VERSION 5.8 ;
BUSBITCHARS "[]" ;
DIVIDERCHAR "/" ;
UNITS
    DATABASE MICRONS 1000 ;
END UNITS

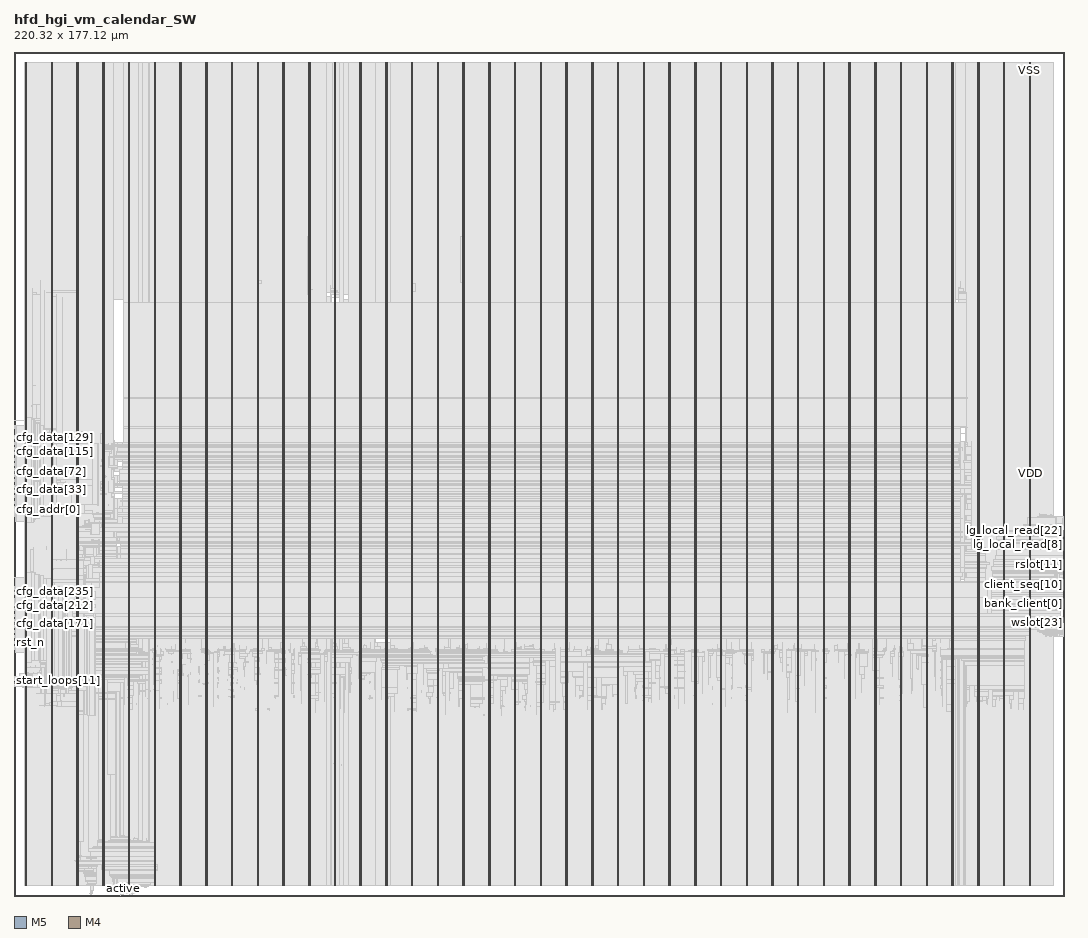
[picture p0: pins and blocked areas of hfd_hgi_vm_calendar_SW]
MACRO hfd_hgi_vm_calendar_SW
  FOREIGN hfd_hgi_vm_calendar_SW 0 0 ;
  CLASS BLOCK ;
  SIZE 220.32 BY 177.12 ;
  PIN active
    DIRECTION OUTPUT ;
    USE SIGNAL ;
    PORT
      LAYER M5 ;
        RECT  22.992 0 23.016 0.084 ;
    END
  END active
  PIN bank_client[0]
    DIRECTION OUTPUT ;
    USE SIGNAL ;
    PORT
      LAYER M4 ;
        RECT  220.236 61.392 220.32 61.416 ;
    END
  END bank_client[0]
  PIN bank_client[10]
    DIRECTION OUTPUT ;
    USE SIGNAL ;
    PORT
      LAYER M4 ;
        RECT  220.236 62.352 220.32 62.376 ;
    END
  END bank_client[10]
  PIN bank_client[11]
    DIRECTION OUTPUT ;
    USE SIGNAL ;
    PORT
      LAYER M4 ;
        RECT  220.236 62.448 220.32 62.472 ;
    END
  END bank_client[11]
  PIN bank_client[12]
    DIRECTION OUTPUT ;
    USE SIGNAL ;
    PORT
      LAYER M4 ;
        RECT  220.236 62.544 220.32 62.568 ;
    END
  END bank_client[12]
  PIN bank_client[13]
    DIRECTION OUTPUT ;
    USE SIGNAL ;
    PORT
      LAYER M4 ;
        RECT  220.236 62.64 220.32 62.664 ;
    END
  END bank_client[13]
  PIN bank_client[14]
    DIRECTION OUTPUT ;
    USE SIGNAL ;
    PORT
      LAYER M4 ;
        RECT  220.236 62.736 220.32 62.76 ;
    END
  END bank_client[14]
  PIN bank_client[15]
    DIRECTION OUTPUT ;
    USE SIGNAL ;
    PORT
      LAYER M4 ;
        RECT  220.236 62.832 220.32 62.856 ;
    END
  END bank_client[15]
  PIN bank_client[16]
    DIRECTION OUTPUT ;
    USE SIGNAL ;
    PORT
      LAYER M4 ;
        RECT  220.236 62.928 220.32 62.952 ;
    END
  END bank_client[16]
  PIN bank_client[17]
    DIRECTION OUTPUT ;
    USE SIGNAL ;
    PORT
      LAYER M4 ;
        RECT  220.236 63.024 220.32 63.048 ;
    END
  END bank_client[17]
  PIN bank_client[18]
    DIRECTION OUTPUT ;
    USE SIGNAL ;
    PORT
      LAYER M4 ;
        RECT  220.236 63.12 220.32 63.144 ;
    END
  END bank_client[18]
  PIN bank_client[19]
    DIRECTION OUTPUT ;
    USE SIGNAL ;
    PORT
      LAYER M4 ;
        RECT  220.236 63.216 220.32 63.24 ;
    END
  END bank_client[19]
  PIN bank_client[1]
    DIRECTION OUTPUT ;
    USE SIGNAL ;
    PORT
      LAYER M4 ;
        RECT  220.236 61.488 220.32 61.512 ;
    END
  END bank_client[1]
  PIN bank_client[20]
    DIRECTION OUTPUT ;
    USE SIGNAL ;
    PORT
      LAYER M4 ;
        RECT  220.236 63.312 220.32 63.336 ;
    END
  END bank_client[20]
  PIN bank_client[21]
    DIRECTION OUTPUT ;
    USE SIGNAL ;
    PORT
      LAYER M4 ;
        RECT  220.236 63.408 220.32 63.432 ;
    END
  END bank_client[21]
  PIN bank_client[22]
    DIRECTION OUTPUT ;
    USE SIGNAL ;
    PORT
      LAYER M4 ;
        RECT  220.236 63.504 220.32 63.528 ;
    END
  END bank_client[22]
  PIN bank_client[23]
    DIRECTION OUTPUT ;
    USE SIGNAL ;
    PORT
      LAYER M4 ;
        RECT  220.236 63.6 220.32 63.624 ;
    END
  END bank_client[23]
  PIN bank_client[2]
    DIRECTION OUTPUT ;
    USE SIGNAL ;
    PORT
      LAYER M4 ;
        RECT  220.236 61.584 220.32 61.608 ;
    END
  END bank_client[2]
  PIN bank_client[3]
    DIRECTION OUTPUT ;
    USE SIGNAL ;
    PORT
      LAYER M4 ;
        RECT  220.236 61.68 220.32 61.704 ;
    END
  END bank_client[3]
  PIN bank_client[4]
    DIRECTION OUTPUT ;
    USE SIGNAL ;
    PORT
      LAYER M4 ;
        RECT  220.236 61.776 220.32 61.8 ;
    END
  END bank_client[4]
  PIN bank_client[5]
    DIRECTION OUTPUT ;
    USE SIGNAL ;
    PORT
      LAYER M4 ;
        RECT  220.236 61.872 220.32 61.896 ;
    END
  END bank_client[5]
  PIN bank_client[6]
    DIRECTION OUTPUT ;
    USE SIGNAL ;
    PORT
      LAYER M4 ;
        RECT  220.236 61.968 220.32 61.992 ;
    END
  END bank_client[6]
  PIN bank_client[7]
    DIRECTION OUTPUT ;
    USE SIGNAL ;
    PORT
      LAYER M4 ;
        RECT  220.236 62.064 220.32 62.088 ;
    END
  END bank_client[7]
  PIN bank_client[8]
    DIRECTION OUTPUT ;
    USE SIGNAL ;
    PORT
      LAYER M4 ;
        RECT  220.236 62.16 220.32 62.184 ;
    END
  END bank_client[8]
  PIN bank_client[9]
    DIRECTION OUTPUT ;
    USE SIGNAL ;
    PORT
      LAYER M4 ;
        RECT  220.236 62.256 220.32 62.28 ;
    END
  END bank_client[9]
  PIN bank_enable[0]
    DIRECTION OUTPUT ;
    USE SIGNAL ;
    PORT
      LAYER M4 ;
        RECT  220.236 63.696 220.32 63.72 ;
    END
  END bank_enable[0]
  PIN bank_enable[1]
    DIRECTION OUTPUT ;
    USE SIGNAL ;
    PORT
      LAYER M4 ;
        RECT  220.236 63.792 220.32 63.816 ;
    END
  END bank_enable[1]
  PIN bank_enable[2]
    DIRECTION OUTPUT ;
    USE SIGNAL ;
    PORT
      LAYER M4 ;
        RECT  220.236 63.888 220.32 63.912 ;
    END
  END bank_enable[2]
  PIN bank_enable[3]
    DIRECTION OUTPUT ;
    USE SIGNAL ;
    PORT
      LAYER M4 ;
        RECT  220.236 63.984 220.32 64.008 ;
    END
  END bank_enable[3]
  PIN bank_enable[4]
    DIRECTION OUTPUT ;
    USE SIGNAL ;
    PORT
      LAYER M4 ;
        RECT  220.236 64.08 220.32 64.104 ;
    END
  END bank_enable[4]
  PIN bank_enable[5]
    DIRECTION OUTPUT ;
    USE SIGNAL ;
    PORT
      LAYER M4 ;
        RECT  220.236 64.176 220.32 64.2 ;
    END
  END bank_enable[5]
  PIN bank_enable[6]
    DIRECTION OUTPUT ;
    USE SIGNAL ;
    PORT
      LAYER M4 ;
        RECT  220.236 64.272 220.32 64.296 ;
    END
  END bank_enable[6]
  PIN bank_enable[7]
    DIRECTION OUTPUT ;
    USE SIGNAL ;
    PORT
      LAYER M4 ;
        RECT  220.236 64.368 220.32 64.392 ;
    END
  END bank_enable[7]
  PIN calendar_v
    DIRECTION OUTPUT ;
    USE SIGNAL ;
    PORT
      LAYER M5 ;
        RECT  23.088 0 23.112 0.084 ;
    END
  END calendar_v
  PIN cfg_addr[0]
    DIRECTION INPUT ;
    USE SIGNAL ;
    PORT
      LAYER M4 ;
        RECT  0 81.168 0.084 81.192 ;
    END
  END cfg_addr[0]
  PIN cfg_addr[1]
    DIRECTION INPUT ;
    USE SIGNAL ;
    PORT
      LAYER M4 ;
        RECT  0 81.264 0.084 81.288 ;
    END
  END cfg_addr[1]
  PIN cfg_addr[2]
    DIRECTION INPUT ;
    USE SIGNAL ;
    PORT
      LAYER M4 ;
        RECT  0 81.36 0.084 81.384 ;
    END
  END cfg_addr[2]
  PIN cfg_addr[3]
    DIRECTION INPUT ;
    USE SIGNAL ;
    PORT
      LAYER M4 ;
        RECT  0 81.456 0.084 81.48 ;
    END
  END cfg_addr[3]
  PIN cfg_addr[4]
    DIRECTION INPUT ;
    USE SIGNAL ;
    PORT
      LAYER M4 ;
        RECT  0 81.552 0.084 81.576 ;
    END
  END cfg_addr[4]
  PIN cfg_addr[5]
    DIRECTION INPUT ;
    USE SIGNAL ;
    PORT
      LAYER M4 ;
        RECT  0 81.648 0.084 81.672 ;
    END
  END cfg_addr[5]
  PIN cfg_addr[6]
    DIRECTION INPUT ;
    USE SIGNAL ;
    PORT
      LAYER M4 ;
        RECT  0 81.744 0.084 81.768 ;
    END
  END cfg_addr[6]
  PIN cfg_addr[7]
    DIRECTION INPUT ;
    USE SIGNAL ;
    PORT
      LAYER M4 ;
        RECT  0 81.84 0.084 81.864 ;
    END
  END cfg_addr[7]
  PIN cfg_addr[8]
    DIRECTION INPUT ;
    USE SIGNAL ;
    PORT
      LAYER M4 ;
        RECT  0 81.936 0.084 81.96 ;
    END
  END cfg_addr[8]
  PIN cfg_addr[9]
    DIRECTION INPUT ;
    USE SIGNAL ;
    PORT
      LAYER M4 ;
        RECT  0 82.032 0.084 82.056 ;
    END
  END cfg_addr[9]
  PIN cfg_data[0]
    DIRECTION INPUT ;
    USE SIGNAL ;
    PORT
      LAYER M4 ;
        RECT  0 82.128 0.084 82.152 ;
    END
  END cfg_data[0]
  PIN cfg_data[100]
    DIRECTION INPUT ;
    USE SIGNAL ;
    PORT
      LAYER M4 ;
        RECT  0 91.728 0.084 91.752 ;
    END
  END cfg_data[100]
  PIN cfg_data[101]
    DIRECTION INPUT ;
    USE SIGNAL ;
    PORT
      LAYER M4 ;
        RECT  0 91.824 0.084 91.848 ;
    END
  END cfg_data[101]
  PIN cfg_data[102]
    DIRECTION INPUT ;
    USE SIGNAL ;
    PORT
      LAYER M4 ;
        RECT  0 91.92 0.084 91.944 ;
    END
  END cfg_data[102]
  PIN cfg_data[103]
    DIRECTION INPUT ;
    USE SIGNAL ;
    PORT
      LAYER M4 ;
        RECT  0 92.016 0.084 92.04 ;
    END
  END cfg_data[103]
  PIN cfg_data[104]
    DIRECTION INPUT ;
    USE SIGNAL ;
    PORT
      LAYER M4 ;
        RECT  0 92.112 0.084 92.136 ;
    END
  END cfg_data[104]
  PIN cfg_data[105]
    DIRECTION INPUT ;
    USE SIGNAL ;
    PORT
      LAYER M4 ;
        RECT  0 92.208 0.084 92.232 ;
    END
  END cfg_data[105]
  PIN cfg_data[106]
    DIRECTION INPUT ;
    USE SIGNAL ;
    PORT
      LAYER M4 ;
        RECT  0 92.304 0.084 92.328 ;
    END
  END cfg_data[106]
  PIN cfg_data[107]
    DIRECTION INPUT ;
    USE SIGNAL ;
    PORT
      LAYER M4 ;
        RECT  0 92.4 0.084 92.424 ;
    END
  END cfg_data[107]
  PIN cfg_data[108]
    DIRECTION INPUT ;
    USE SIGNAL ;
    PORT
      LAYER M4 ;
        RECT  0 92.496 0.084 92.52 ;
    END
  END cfg_data[108]
  PIN cfg_data[109]
    DIRECTION INPUT ;
    USE SIGNAL ;
    PORT
      LAYER M4 ;
        RECT  0 92.592 0.084 92.616 ;
    END
  END cfg_data[109]
  PIN cfg_data[10]
    DIRECTION INPUT ;
    USE SIGNAL ;
    PORT
      LAYER M4 ;
        RECT  0 83.088 0.084 83.112 ;
    END
  END cfg_data[10]
  PIN cfg_data[110]
    DIRECTION INPUT ;
    USE SIGNAL ;
    PORT
      LAYER M4 ;
        RECT  0 92.688 0.084 92.712 ;
    END
  END cfg_data[110]
  PIN cfg_data[111]
    DIRECTION INPUT ;
    USE SIGNAL ;
    PORT
      LAYER M4 ;
        RECT  0 92.784 0.084 92.808 ;
    END
  END cfg_data[111]
  PIN cfg_data[112]
    DIRECTION INPUT ;
    USE SIGNAL ;
    PORT
      LAYER M4 ;
        RECT  0 92.88 0.084 92.904 ;
    END
  END cfg_data[112]
  PIN cfg_data[113]
    DIRECTION INPUT ;
    USE SIGNAL ;
    PORT
      LAYER M4 ;
        RECT  0 92.976 0.084 93 ;
    END
  END cfg_data[113]
  PIN cfg_data[114]
    DIRECTION INPUT ;
    USE SIGNAL ;
    PORT
      LAYER M4 ;
        RECT  0 93.072 0.084 93.096 ;
    END
  END cfg_data[114]
  PIN cfg_data[115]
    DIRECTION INPUT ;
    USE SIGNAL ;
    PORT
      LAYER M4 ;
        RECT  0 93.168 0.084 93.192 ;
    END
  END cfg_data[115]
  PIN cfg_data[116]
    DIRECTION INPUT ;
    USE SIGNAL ;
    PORT
      LAYER M4 ;
        RECT  0 93.264 0.084 93.288 ;
    END
  END cfg_data[116]
  PIN cfg_data[117]
    DIRECTION INPUT ;
    USE SIGNAL ;
    PORT
      LAYER M4 ;
        RECT  0 93.36 0.084 93.384 ;
    END
  END cfg_data[117]
  PIN cfg_data[118]
    DIRECTION INPUT ;
    USE SIGNAL ;
    PORT
      LAYER M4 ;
        RECT  0 93.456 0.084 93.48 ;
    END
  END cfg_data[118]
  PIN cfg_data[119]
    DIRECTION INPUT ;
    USE SIGNAL ;
    PORT
      LAYER M4 ;
        RECT  0 93.552 0.084 93.576 ;
    END
  END cfg_data[119]
  PIN cfg_data[11]
    DIRECTION INPUT ;
    USE SIGNAL ;
    PORT
      LAYER M4 ;
        RECT  0 83.184 0.084 83.208 ;
    END
  END cfg_data[11]
  PIN cfg_data[120]
    DIRECTION INPUT ;
    USE SIGNAL ;
    PORT
      LAYER M4 ;
        RECT  0 93.648 0.084 93.672 ;
    END
  END cfg_data[120]
  PIN cfg_data[121]
    DIRECTION INPUT ;
    USE SIGNAL ;
    PORT
      LAYER M4 ;
        RECT  0 93.744 0.084 93.768 ;
    END
  END cfg_data[121]
  PIN cfg_data[122]
    DIRECTION INPUT ;
    USE SIGNAL ;
    PORT
      LAYER M4 ;
        RECT  0 93.84 0.084 93.864 ;
    END
  END cfg_data[122]
  PIN cfg_data[123]
    DIRECTION INPUT ;
    USE SIGNAL ;
    PORT
      LAYER M4 ;
        RECT  0 93.936 0.084 93.96 ;
    END
  END cfg_data[123]
  PIN cfg_data[124]
    DIRECTION INPUT ;
    USE SIGNAL ;
    PORT
      LAYER M4 ;
        RECT  0 94.032 0.084 94.056 ;
    END
  END cfg_data[124]
  PIN cfg_data[125]
    DIRECTION INPUT ;
    USE SIGNAL ;
    PORT
      LAYER M4 ;
        RECT  0 94.128 0.084 94.152 ;
    END
  END cfg_data[125]
  PIN cfg_data[126]
    DIRECTION INPUT ;
    USE SIGNAL ;
    PORT
      LAYER M4 ;
        RECT  0 94.224 0.084 94.248 ;
    END
  END cfg_data[126]
  PIN cfg_data[127]
    DIRECTION INPUT ;
    USE SIGNAL ;
    PORT
      LAYER M4 ;
        RECT  0 94.32 0.084 94.344 ;
    END
  END cfg_data[127]
  PIN cfg_data[128]
    DIRECTION INPUT ;
    USE SIGNAL ;
    PORT
      LAYER M4 ;
        RECT  0 94.416 0.084 94.44 ;
    END
  END cfg_data[128]
  PIN cfg_data[129]
    DIRECTION INPUT ;
    USE SIGNAL ;
    PORT
      LAYER M4 ;
        RECT  0 94.512 0.084 94.536 ;
    END
  END cfg_data[129]
  PIN cfg_data[12]
    DIRECTION INPUT ;
    USE SIGNAL ;
    PORT
      LAYER M4 ;
        RECT  0 83.28 0.084 83.304 ;
    END
  END cfg_data[12]
  PIN cfg_data[130]
    DIRECTION INPUT ;
    USE SIGNAL ;
    PORT
      LAYER M4 ;
        RECT  0 94.608 0.084 94.632 ;
    END
  END cfg_data[130]
  PIN cfg_data[131]
    DIRECTION INPUT ;
    USE SIGNAL ;
    PORT
      LAYER M4 ;
        RECT  0 94.704 0.084 94.728 ;
    END
  END cfg_data[131]
  PIN cfg_data[132]
    DIRECTION INPUT ;
    USE SIGNAL ;
    PORT
      LAYER M4 ;
        RECT  0 94.8 0.084 94.824 ;
    END
  END cfg_data[132]
  PIN cfg_data[133]
    DIRECTION INPUT ;
    USE SIGNAL ;
    PORT
      LAYER M4 ;
        RECT  0 94.896 0.084 94.92 ;
    END
  END cfg_data[133]
  PIN cfg_data[134]
    DIRECTION INPUT ;
    USE SIGNAL ;
    PORT
      LAYER M4 ;
        RECT  0 94.992 0.084 95.016 ;
    END
  END cfg_data[134]
  PIN cfg_data[135]
    DIRECTION INPUT ;
    USE SIGNAL ;
    PORT
      LAYER M4 ;
        RECT  0 95.088 0.084 95.112 ;
    END
  END cfg_data[135]
  PIN cfg_data[136]
    DIRECTION INPUT ;
    USE SIGNAL ;
    PORT
      LAYER M4 ;
        RECT  0 95.184 0.084 95.208 ;
    END
  END cfg_data[136]
  PIN cfg_data[137]
    DIRECTION INPUT ;
    USE SIGNAL ;
    PORT
      LAYER M4 ;
        RECT  0 95.28 0.084 95.304 ;
    END
  END cfg_data[137]
  PIN cfg_data[138]
    DIRECTION INPUT ;
    USE SIGNAL ;
    PORT
      LAYER M4 ;
        RECT  0 95.376 0.084 95.4 ;
    END
  END cfg_data[138]
  PIN cfg_data[139]
    DIRECTION INPUT ;
    USE SIGNAL ;
    PORT
      LAYER M4 ;
        RECT  0 95.472 0.084 95.496 ;
    END
  END cfg_data[139]
  PIN cfg_data[13]
    DIRECTION INPUT ;
    USE SIGNAL ;
    PORT
      LAYER M4 ;
        RECT  0 83.376 0.084 83.4 ;
    END
  END cfg_data[13]
  PIN cfg_data[140]
    DIRECTION INPUT ;
    USE SIGNAL ;
    PORT
      LAYER M4 ;
        RECT  0 95.568 0.084 95.592 ;
    END
  END cfg_data[140]
  PIN cfg_data[141]
    DIRECTION INPUT ;
    USE SIGNAL ;
    PORT
      LAYER M4 ;
        RECT  0 95.664 0.084 95.688 ;
    END
  END cfg_data[141]
  PIN cfg_data[142]
    DIRECTION INPUT ;
    USE SIGNAL ;
    PORT
      LAYER M4 ;
        RECT  0 95.76 0.084 95.784 ;
    END
  END cfg_data[142]
  PIN cfg_data[143]
    DIRECTION INPUT ;
    USE SIGNAL ;
    PORT
      LAYER M4 ;
        RECT  0 95.856 0.084 95.88 ;
    END
  END cfg_data[143]
  PIN cfg_data[144]
    DIRECTION INPUT ;
    USE SIGNAL ;
    PORT
      LAYER M4 ;
        RECT  0 95.952 0.084 95.976 ;
    END
  END cfg_data[144]
  PIN cfg_data[145]
    DIRECTION INPUT ;
    USE SIGNAL ;
    PORT
      LAYER M4 ;
        RECT  0 96.048 0.084 96.072 ;
    END
  END cfg_data[145]
  PIN cfg_data[146]
    DIRECTION INPUT ;
    USE SIGNAL ;
    PORT
      LAYER M4 ;
        RECT  0 96.144 0.084 96.168 ;
    END
  END cfg_data[146]
  PIN cfg_data[147]
    DIRECTION INPUT ;
    USE SIGNAL ;
    PORT
      LAYER M4 ;
        RECT  0 96.24 0.084 96.264 ;
    END
  END cfg_data[147]
  PIN cfg_data[148]
    DIRECTION INPUT ;
    USE SIGNAL ;
    PORT
      LAYER M4 ;
        RECT  0 96.336 0.084 96.36 ;
    END
  END cfg_data[148]
  PIN cfg_data[149]
    DIRECTION INPUT ;
    USE SIGNAL ;
    PORT
      LAYER M4 ;
        RECT  0 96.432 0.084 96.456 ;
    END
  END cfg_data[149]
  PIN cfg_data[14]
    DIRECTION INPUT ;
    USE SIGNAL ;
    PORT
      LAYER M4 ;
        RECT  0 83.472 0.084 83.496 ;
    END
  END cfg_data[14]
  PIN cfg_data[150]
    DIRECTION INPUT ;
    USE SIGNAL ;
    PORT
      LAYER M4 ;
        RECT  0 55.056 0.084 55.08 ;
    END
  END cfg_data[150]
  PIN cfg_data[151]
    DIRECTION INPUT ;
    USE SIGNAL ;
    PORT
      LAYER M4 ;
        RECT  0 55.152 0.084 55.176 ;
    END
  END cfg_data[151]
  PIN cfg_data[152]
    DIRECTION INPUT ;
    USE SIGNAL ;
    PORT
      LAYER M4 ;
        RECT  0 55.248 0.084 55.272 ;
    END
  END cfg_data[152]
  PIN cfg_data[153]
    DIRECTION INPUT ;
    USE SIGNAL ;
    PORT
      LAYER M4 ;
        RECT  0 55.344 0.084 55.368 ;
    END
  END cfg_data[153]
  PIN cfg_data[154]
    DIRECTION INPUT ;
    USE SIGNAL ;
    PORT
      LAYER M4 ;
        RECT  0 55.44 0.084 55.464 ;
    END
  END cfg_data[154]
  PIN cfg_data[155]
    DIRECTION INPUT ;
    USE SIGNAL ;
    PORT
      LAYER M4 ;
        RECT  0 55.536 0.084 55.56 ;
    END
  END cfg_data[155]
  PIN cfg_data[156]
    DIRECTION INPUT ;
    USE SIGNAL ;
    PORT
      LAYER M4 ;
        RECT  0 55.632 0.084 55.656 ;
    END
  END cfg_data[156]
  PIN cfg_data[157]
    DIRECTION INPUT ;
    USE SIGNAL ;
    PORT
      LAYER M4 ;
        RECT  0 55.728 0.084 55.752 ;
    END
  END cfg_data[157]
  PIN cfg_data[158]
    DIRECTION INPUT ;
    USE SIGNAL ;
    PORT
      LAYER M4 ;
        RECT  0 55.824 0.084 55.848 ;
    END
  END cfg_data[158]
  PIN cfg_data[159]
    DIRECTION INPUT ;
    USE SIGNAL ;
    PORT
      LAYER M4 ;
        RECT  0 55.92 0.084 55.944 ;
    END
  END cfg_data[159]
  PIN cfg_data[15]
    DIRECTION INPUT ;
    USE SIGNAL ;
    PORT
      LAYER M4 ;
        RECT  0 83.568 0.084 83.592 ;
    END
  END cfg_data[15]
  PIN cfg_data[160]
    DIRECTION INPUT ;
    USE SIGNAL ;
    PORT
      LAYER M4 ;
        RECT  0 56.016 0.084 56.04 ;
    END
  END cfg_data[160]
  PIN cfg_data[161]
    DIRECTION INPUT ;
    USE SIGNAL ;
    PORT
      LAYER M4 ;
        RECT  0 56.112 0.084 56.136 ;
    END
  END cfg_data[161]
  PIN cfg_data[162]
    DIRECTION INPUT ;
    USE SIGNAL ;
    PORT
      LAYER M4 ;
        RECT  0 56.208 0.084 56.232 ;
    END
  END cfg_data[162]
  PIN cfg_data[163]
    DIRECTION INPUT ;
    USE SIGNAL ;
    PORT
      LAYER M4 ;
        RECT  0 56.304 0.084 56.328 ;
    END
  END cfg_data[163]
  PIN cfg_data[164]
    DIRECTION INPUT ;
    USE SIGNAL ;
    PORT
      LAYER M4 ;
        RECT  0 56.4 0.084 56.424 ;
    END
  END cfg_data[164]
  PIN cfg_data[165]
    DIRECTION INPUT ;
    USE SIGNAL ;
    PORT
      LAYER M4 ;
        RECT  0 56.496 0.084 56.52 ;
    END
  END cfg_data[165]
  PIN cfg_data[166]
    DIRECTION INPUT ;
    USE SIGNAL ;
    PORT
      LAYER M4 ;
        RECT  0 56.592 0.084 56.616 ;
    END
  END cfg_data[166]
  PIN cfg_data[167]
    DIRECTION INPUT ;
    USE SIGNAL ;
    PORT
      LAYER M4 ;
        RECT  0 56.688 0.084 56.712 ;
    END
  END cfg_data[167]
  PIN cfg_data[168]
    DIRECTION INPUT ;
    USE SIGNAL ;
    PORT
      LAYER M4 ;
        RECT  0 56.784 0.084 56.808 ;
    END
  END cfg_data[168]
  PIN cfg_data[169]
    DIRECTION INPUT ;
    USE SIGNAL ;
    PORT
      LAYER M4 ;
        RECT  0 56.88 0.084 56.904 ;
    END
  END cfg_data[169]
  PIN cfg_data[16]
    DIRECTION INPUT ;
    USE SIGNAL ;
    PORT
      LAYER M4 ;
        RECT  0 83.664 0.084 83.688 ;
    END
  END cfg_data[16]
  PIN cfg_data[170]
    DIRECTION INPUT ;
    USE SIGNAL ;
    PORT
      LAYER M4 ;
        RECT  0 56.976 0.084 57 ;
    END
  END cfg_data[170]
  PIN cfg_data[171]
    DIRECTION INPUT ;
    USE SIGNAL ;
    PORT
      LAYER M4 ;
        RECT  0 57.072 0.084 57.096 ;
    END
  END cfg_data[171]
  PIN cfg_data[172]
    DIRECTION INPUT ;
    USE SIGNAL ;
    PORT
      LAYER M4 ;
        RECT  0 57.168 0.084 57.192 ;
    END
  END cfg_data[172]
  PIN cfg_data[173]
    DIRECTION INPUT ;
    USE SIGNAL ;
    PORT
      LAYER M4 ;
        RECT  0 57.264 0.084 57.288 ;
    END
  END cfg_data[173]
  PIN cfg_data[174]
    DIRECTION INPUT ;
    USE SIGNAL ;
    PORT
      LAYER M4 ;
        RECT  0 57.36 0.084 57.384 ;
    END
  END cfg_data[174]
  PIN cfg_data[175]
    DIRECTION INPUT ;
    USE SIGNAL ;
    PORT
      LAYER M4 ;
        RECT  0 57.456 0.084 57.48 ;
    END
  END cfg_data[175]
  PIN cfg_data[176]
    DIRECTION INPUT ;
    USE SIGNAL ;
    PORT
      LAYER M4 ;
        RECT  0 57.552 0.084 57.576 ;
    END
  END cfg_data[176]
  PIN cfg_data[177]
    DIRECTION INPUT ;
    USE SIGNAL ;
    PORT
      LAYER M4 ;
        RECT  0 57.648 0.084 57.672 ;
    END
  END cfg_data[177]
  PIN cfg_data[178]
    DIRECTION INPUT ;
    USE SIGNAL ;
    PORT
      LAYER M4 ;
        RECT  0 57.744 0.084 57.768 ;
    END
  END cfg_data[178]
  PIN cfg_data[179]
    DIRECTION INPUT ;
    USE SIGNAL ;
    PORT
      LAYER M4 ;
        RECT  0 57.84 0.084 57.864 ;
    END
  END cfg_data[179]
  PIN cfg_data[17]
    DIRECTION INPUT ;
    USE SIGNAL ;
    PORT
      LAYER M4 ;
        RECT  0 83.76 0.084 83.784 ;
    END
  END cfg_data[17]
  PIN cfg_data[180]
    DIRECTION INPUT ;
    USE SIGNAL ;
    PORT
      LAYER M4 ;
        RECT  0 57.936 0.084 57.96 ;
    END
  END cfg_data[180]
  PIN cfg_data[181]
    DIRECTION INPUT ;
    USE SIGNAL ;
    PORT
      LAYER M4 ;
        RECT  0 58.032 0.084 58.056 ;
    END
  END cfg_data[181]
  PIN cfg_data[182]
    DIRECTION INPUT ;
    USE SIGNAL ;
    PORT
      LAYER M4 ;
        RECT  0 58.128 0.084 58.152 ;
    END
  END cfg_data[182]
  PIN cfg_data[183]
    DIRECTION INPUT ;
    USE SIGNAL ;
    PORT
      LAYER M4 ;
        RECT  0 58.224 0.084 58.248 ;
    END
  END cfg_data[183]
  PIN cfg_data[184]
    DIRECTION INPUT ;
    USE SIGNAL ;
    PORT
      LAYER M4 ;
        RECT  0 58.32 0.084 58.344 ;
    END
  END cfg_data[184]
  PIN cfg_data[185]
    DIRECTION INPUT ;
    USE SIGNAL ;
    PORT
      LAYER M4 ;
        RECT  0 58.416 0.084 58.44 ;
    END
  END cfg_data[185]
  PIN cfg_data[186]
    DIRECTION INPUT ;
    USE SIGNAL ;
    PORT
      LAYER M4 ;
        RECT  0 58.512 0.084 58.536 ;
    END
  END cfg_data[186]
  PIN cfg_data[187]
    DIRECTION INPUT ;
    USE SIGNAL ;
    PORT
      LAYER M4 ;
        RECT  0 58.608 0.084 58.632 ;
    END
  END cfg_data[187]
  PIN cfg_data[188]
    DIRECTION INPUT ;
    USE SIGNAL ;
    PORT
      LAYER M4 ;
        RECT  0 58.704 0.084 58.728 ;
    END
  END cfg_data[188]
  PIN cfg_data[189]
    DIRECTION INPUT ;
    USE SIGNAL ;
    PORT
      LAYER M4 ;
        RECT  0 58.8 0.084 58.824 ;
    END
  END cfg_data[189]
  PIN cfg_data[18]
    DIRECTION INPUT ;
    USE SIGNAL ;
    PORT
      LAYER M4 ;
        RECT  0 83.856 0.084 83.88 ;
    END
  END cfg_data[18]
  PIN cfg_data[190]
    DIRECTION INPUT ;
    USE SIGNAL ;
    PORT
      LAYER M4 ;
        RECT  0 58.896 0.084 58.92 ;
    END
  END cfg_data[190]
  PIN cfg_data[191]
    DIRECTION INPUT ;
    USE SIGNAL ;
    PORT
      LAYER M4 ;
        RECT  0 58.992 0.084 59.016 ;
    END
  END cfg_data[191]
  PIN cfg_data[192]
    DIRECTION INPUT ;
    USE SIGNAL ;
    PORT
      LAYER M4 ;
        RECT  0 59.088 0.084 59.112 ;
    END
  END cfg_data[192]
  PIN cfg_data[193]
    DIRECTION INPUT ;
    USE SIGNAL ;
    PORT
      LAYER M4 ;
        RECT  0 59.184 0.084 59.208 ;
    END
  END cfg_data[193]
  PIN cfg_data[194]
    DIRECTION INPUT ;
    USE SIGNAL ;
    PORT
      LAYER M4 ;
        RECT  0 59.28 0.084 59.304 ;
    END
  END cfg_data[194]
  PIN cfg_data[195]
    DIRECTION INPUT ;
    USE SIGNAL ;
    PORT
      LAYER M4 ;
        RECT  0 59.376 0.084 59.4 ;
    END
  END cfg_data[195]
  PIN cfg_data[196]
    DIRECTION INPUT ;
    USE SIGNAL ;
    PORT
      LAYER M4 ;
        RECT  0 59.472 0.084 59.496 ;
    END
  END cfg_data[196]
  PIN cfg_data[197]
    DIRECTION INPUT ;
    USE SIGNAL ;
    PORT
      LAYER M4 ;
        RECT  0 59.568 0.084 59.592 ;
    END
  END cfg_data[197]
  PIN cfg_data[198]
    DIRECTION INPUT ;
    USE SIGNAL ;
    PORT
      LAYER M4 ;
        RECT  0 59.664 0.084 59.688 ;
    END
  END cfg_data[198]
  PIN cfg_data[199]
    DIRECTION INPUT ;
    USE SIGNAL ;
    PORT
      LAYER M4 ;
        RECT  0 59.76 0.084 59.784 ;
    END
  END cfg_data[199]
  PIN cfg_data[19]
    DIRECTION INPUT ;
    USE SIGNAL ;
    PORT
      LAYER M4 ;
        RECT  0 83.952 0.084 83.976 ;
    END
  END cfg_data[19]
  PIN cfg_data[1]
    DIRECTION INPUT ;
    USE SIGNAL ;
    PORT
      LAYER M4 ;
        RECT  0 82.224 0.084 82.248 ;
    END
  END cfg_data[1]
  PIN cfg_data[200]
    DIRECTION INPUT ;
    USE SIGNAL ;
    PORT
      LAYER M4 ;
        RECT  0 59.856 0.084 59.88 ;
    END
  END cfg_data[200]
  PIN cfg_data[201]
    DIRECTION INPUT ;
    USE SIGNAL ;
    PORT
      LAYER M4 ;
        RECT  0 59.952 0.084 59.976 ;
    END
  END cfg_data[201]
  PIN cfg_data[202]
    DIRECTION INPUT ;
    USE SIGNAL ;
    PORT
      LAYER M4 ;
        RECT  0 60.048 0.084 60.072 ;
    END
  END cfg_data[202]
  PIN cfg_data[203]
    DIRECTION INPUT ;
    USE SIGNAL ;
    PORT
      LAYER M4 ;
        RECT  0 60.144 0.084 60.168 ;
    END
  END cfg_data[203]
  PIN cfg_data[204]
    DIRECTION INPUT ;
    USE SIGNAL ;
    PORT
      LAYER M4 ;
        RECT  0 60.24 0.084 60.264 ;
    END
  END cfg_data[204]
  PIN cfg_data[205]
    DIRECTION INPUT ;
    USE SIGNAL ;
    PORT
      LAYER M4 ;
        RECT  0 60.336 0.084 60.36 ;
    END
  END cfg_data[205]
  PIN cfg_data[206]
    DIRECTION INPUT ;
    USE SIGNAL ;
    PORT
      LAYER M4 ;
        RECT  0 60.432 0.084 60.456 ;
    END
  END cfg_data[206]
  PIN cfg_data[207]
    DIRECTION INPUT ;
    USE SIGNAL ;
    PORT
      LAYER M4 ;
        RECT  0 60.528 0.084 60.552 ;
    END
  END cfg_data[207]
  PIN cfg_data[208]
    DIRECTION INPUT ;
    USE SIGNAL ;
    PORT
      LAYER M4 ;
        RECT  0 60.624 0.084 60.648 ;
    END
  END cfg_data[208]
  PIN cfg_data[209]
    DIRECTION INPUT ;
    USE SIGNAL ;
    PORT
      LAYER M4 ;
        RECT  0 60.72 0.084 60.744 ;
    END
  END cfg_data[209]
  PIN cfg_data[20]
    DIRECTION INPUT ;
    USE SIGNAL ;
    PORT
      LAYER M4 ;
        RECT  0 84.048 0.084 84.072 ;
    END
  END cfg_data[20]
  PIN cfg_data[210]
    DIRECTION INPUT ;
    USE SIGNAL ;
    PORT
      LAYER M4 ;
        RECT  0 60.816 0.084 60.84 ;
    END
  END cfg_data[210]
  PIN cfg_data[211]
    DIRECTION INPUT ;
    USE SIGNAL ;
    PORT
      LAYER M4 ;
        RECT  0 60.912 0.084 60.936 ;
    END
  END cfg_data[211]
  PIN cfg_data[212]
    DIRECTION INPUT ;
    USE SIGNAL ;
    PORT
      LAYER M4 ;
        RECT  0 61.008 0.084 61.032 ;
    END
  END cfg_data[212]
  PIN cfg_data[213]
    DIRECTION INPUT ;
    USE SIGNAL ;
    PORT
      LAYER M4 ;
        RECT  0 61.104 0.084 61.128 ;
    END
  END cfg_data[213]
  PIN cfg_data[214]
    DIRECTION INPUT ;
    USE SIGNAL ;
    PORT
      LAYER M4 ;
        RECT  0 61.968 0.084 61.992 ;
    END
  END cfg_data[214]
  PIN cfg_data[215]
    DIRECTION INPUT ;
    USE SIGNAL ;
    PORT
      LAYER M4 ;
        RECT  0 62.064 0.084 62.088 ;
    END
  END cfg_data[215]
  PIN cfg_data[216]
    DIRECTION INPUT ;
    USE SIGNAL ;
    PORT
      LAYER M4 ;
        RECT  0 62.16 0.084 62.184 ;
    END
  END cfg_data[216]
  PIN cfg_data[217]
    DIRECTION INPUT ;
    USE SIGNAL ;
    PORT
      LAYER M4 ;
        RECT  0 62.256 0.084 62.28 ;
    END
  END cfg_data[217]
  PIN cfg_data[218]
    DIRECTION INPUT ;
    USE SIGNAL ;
    PORT
      LAYER M4 ;
        RECT  0 62.352 0.084 62.376 ;
    END
  END cfg_data[218]
  PIN cfg_data[219]
    DIRECTION INPUT ;
    USE SIGNAL ;
    PORT
      LAYER M4 ;
        RECT  0 62.448 0.084 62.472 ;
    END
  END cfg_data[219]
  PIN cfg_data[21]
    DIRECTION INPUT ;
    USE SIGNAL ;
    PORT
      LAYER M4 ;
        RECT  0 84.144 0.084 84.168 ;
    END
  END cfg_data[21]
  PIN cfg_data[220]
    DIRECTION INPUT ;
    USE SIGNAL ;
    PORT
      LAYER M4 ;
        RECT  0 62.544 0.084 62.568 ;
    END
  END cfg_data[220]
  PIN cfg_data[221]
    DIRECTION INPUT ;
    USE SIGNAL ;
    PORT
      LAYER M4 ;
        RECT  0 62.64 0.084 62.664 ;
    END
  END cfg_data[221]
  PIN cfg_data[222]
    DIRECTION INPUT ;
    USE SIGNAL ;
    PORT
      LAYER M4 ;
        RECT  0 62.736 0.084 62.76 ;
    END
  END cfg_data[222]
  PIN cfg_data[223]
    DIRECTION INPUT ;
    USE SIGNAL ;
    PORT
      LAYER M4 ;
        RECT  0 62.832 0.084 62.856 ;
    END
  END cfg_data[223]
  PIN cfg_data[224]
    DIRECTION INPUT ;
    USE SIGNAL ;
    PORT
      LAYER M4 ;
        RECT  0 62.928 0.084 62.952 ;
    END
  END cfg_data[224]
  PIN cfg_data[225]
    DIRECTION INPUT ;
    USE SIGNAL ;
    PORT
      LAYER M4 ;
        RECT  0 63.024 0.084 63.048 ;
    END
  END cfg_data[225]
  PIN cfg_data[226]
    DIRECTION INPUT ;
    USE SIGNAL ;
    PORT
      LAYER M4 ;
        RECT  0 63.12 0.084 63.144 ;
    END
  END cfg_data[226]
  PIN cfg_data[227]
    DIRECTION INPUT ;
    USE SIGNAL ;
    PORT
      LAYER M4 ;
        RECT  0 63.216 0.084 63.24 ;
    END
  END cfg_data[227]
  PIN cfg_data[228]
    DIRECTION INPUT ;
    USE SIGNAL ;
    PORT
      LAYER M4 ;
        RECT  0 63.312 0.084 63.336 ;
    END
  END cfg_data[228]
  PIN cfg_data[229]
    DIRECTION INPUT ;
    USE SIGNAL ;
    PORT
      LAYER M4 ;
        RECT  0 63.408 0.084 63.432 ;
    END
  END cfg_data[229]
  PIN cfg_data[22]
    DIRECTION INPUT ;
    USE SIGNAL ;
    PORT
      LAYER M4 ;
        RECT  0 84.24 0.084 84.264 ;
    END
  END cfg_data[22]
  PIN cfg_data[230]
    DIRECTION INPUT ;
    USE SIGNAL ;
    PORT
      LAYER M4 ;
        RECT  0 63.504 0.084 63.528 ;
    END
  END cfg_data[230]
  PIN cfg_data[231]
    DIRECTION INPUT ;
    USE SIGNAL ;
    PORT
      LAYER M4 ;
        RECT  0 63.6 0.084 63.624 ;
    END
  END cfg_data[231]
  PIN cfg_data[232]
    DIRECTION INPUT ;
    USE SIGNAL ;
    PORT
      LAYER M4 ;
        RECT  0 63.696 0.084 63.72 ;
    END
  END cfg_data[232]
  PIN cfg_data[233]
    DIRECTION INPUT ;
    USE SIGNAL ;
    PORT
      LAYER M4 ;
        RECT  0 63.792 0.084 63.816 ;
    END
  END cfg_data[233]
  PIN cfg_data[234]
    DIRECTION INPUT ;
    USE SIGNAL ;
    PORT
      LAYER M4 ;
        RECT  0 63.888 0.084 63.912 ;
    END
  END cfg_data[234]
  PIN cfg_data[235]
    DIRECTION INPUT ;
    USE SIGNAL ;
    PORT
      LAYER M4 ;
        RECT  0 63.984 0.084 64.008 ;
    END
  END cfg_data[235]
  PIN cfg_data[236]
    DIRECTION INPUT ;
    USE SIGNAL ;
    PORT
      LAYER M4 ;
        RECT  0 64.08 0.084 64.104 ;
    END
  END cfg_data[236]
  PIN cfg_data[237]
    DIRECTION INPUT ;
    USE SIGNAL ;
    PORT
      LAYER M4 ;
        RECT  0 64.176 0.084 64.2 ;
    END
  END cfg_data[237]
  PIN cfg_data[238]
    DIRECTION INPUT ;
    USE SIGNAL ;
    PORT
      LAYER M4 ;
        RECT  0 64.272 0.084 64.296 ;
    END
  END cfg_data[238]
  PIN cfg_data[239]
    DIRECTION INPUT ;
    USE SIGNAL ;
    PORT
      LAYER M4 ;
        RECT  0 64.368 0.084 64.392 ;
    END
  END cfg_data[239]
  PIN cfg_data[23]
    DIRECTION INPUT ;
    USE SIGNAL ;
    PORT
      LAYER M4 ;
        RECT  0 84.336 0.084 84.36 ;
    END
  END cfg_data[23]
  PIN cfg_data[240]
    DIRECTION INPUT ;
    USE SIGNAL ;
    PORT
      LAYER M4 ;
        RECT  0 64.464 0.084 64.488 ;
    END
  END cfg_data[240]
  PIN cfg_data[241]
    DIRECTION INPUT ;
    USE SIGNAL ;
    PORT
      LAYER M4 ;
        RECT  0 64.56 0.084 64.584 ;
    END
  END cfg_data[241]
  PIN cfg_data[242]
    DIRECTION INPUT ;
    USE SIGNAL ;
    PORT
      LAYER M4 ;
        RECT  0 64.656 0.084 64.68 ;
    END
  END cfg_data[242]
  PIN cfg_data[243]
    DIRECTION INPUT ;
    USE SIGNAL ;
    PORT
      LAYER M4 ;
        RECT  0 64.752 0.084 64.776 ;
    END
  END cfg_data[243]
  PIN cfg_data[244]
    DIRECTION INPUT ;
    USE SIGNAL ;
    PORT
      LAYER M4 ;
        RECT  0 64.848 0.084 64.872 ;
    END
  END cfg_data[244]
  PIN cfg_data[245]
    DIRECTION INPUT ;
    USE SIGNAL ;
    PORT
      LAYER M4 ;
        RECT  0 64.944 0.084 64.968 ;
    END
  END cfg_data[245]
  PIN cfg_data[246]
    DIRECTION INPUT ;
    USE SIGNAL ;
    PORT
      LAYER M4 ;
        RECT  0 51.984 0.084 52.008 ;
    END
  END cfg_data[246]
  PIN cfg_data[247]
    DIRECTION INPUT ;
    USE SIGNAL ;
    PORT
      LAYER M4 ;
        RECT  0 52.08 0.084 52.104 ;
    END
  END cfg_data[247]
  PIN cfg_data[248]
    DIRECTION INPUT ;
    USE SIGNAL ;
    PORT
      LAYER M4 ;
        RECT  0 52.176 0.084 52.2 ;
    END
  END cfg_data[248]
  PIN cfg_data[249]
    DIRECTION INPUT ;
    USE SIGNAL ;
    PORT
      LAYER M4 ;
        RECT  0 52.272 0.084 52.296 ;
    END
  END cfg_data[249]
  PIN cfg_data[24]
    DIRECTION INPUT ;
    USE SIGNAL ;
    PORT
      LAYER M4 ;
        RECT  0 84.432 0.084 84.456 ;
    END
  END cfg_data[24]
  PIN cfg_data[250]
    DIRECTION INPUT ;
    USE SIGNAL ;
    PORT
      LAYER M4 ;
        RECT  0 52.368 0.084 52.392 ;
    END
  END cfg_data[250]
  PIN cfg_data[251]
    DIRECTION INPUT ;
    USE SIGNAL ;
    PORT
      LAYER M4 ;
        RECT  0 52.464 0.084 52.488 ;
    END
  END cfg_data[251]
  PIN cfg_data[252]
    DIRECTION INPUT ;
    USE SIGNAL ;
    PORT
      LAYER M4 ;
        RECT  0 52.56 0.084 52.584 ;
    END
  END cfg_data[252]
  PIN cfg_data[253]
    DIRECTION INPUT ;
    USE SIGNAL ;
    PORT
      LAYER M4 ;
        RECT  0 52.656 0.084 52.68 ;
    END
  END cfg_data[253]
  PIN cfg_data[254]
    DIRECTION INPUT ;
    USE SIGNAL ;
    PORT
      LAYER M4 ;
        RECT  0 52.752 0.084 52.776 ;
    END
  END cfg_data[254]
  PIN cfg_data[255]
    DIRECTION INPUT ;
    USE SIGNAL ;
    PORT
      LAYER M4 ;
        RECT  0 52.848 0.084 52.872 ;
    END
  END cfg_data[255]
  PIN cfg_data[25]
    DIRECTION INPUT ;
    USE SIGNAL ;
    PORT
      LAYER M4 ;
        RECT  0 84.528 0.084 84.552 ;
    END
  END cfg_data[25]
  PIN cfg_data[26]
    DIRECTION INPUT ;
    USE SIGNAL ;
    PORT
      LAYER M4 ;
        RECT  0 84.624 0.084 84.648 ;
    END
  END cfg_data[26]
  PIN cfg_data[27]
    DIRECTION INPUT ;
    USE SIGNAL ;
    PORT
      LAYER M4 ;
        RECT  0 84.72 0.084 84.744 ;
    END
  END cfg_data[27]
  PIN cfg_data[28]
    DIRECTION INPUT ;
    USE SIGNAL ;
    PORT
      LAYER M4 ;
        RECT  0 84.816 0.084 84.84 ;
    END
  END cfg_data[28]
  PIN cfg_data[29]
    DIRECTION INPUT ;
    USE SIGNAL ;
    PORT
      LAYER M4 ;
        RECT  0 84.912 0.084 84.936 ;
    END
  END cfg_data[29]
  PIN cfg_data[2]
    DIRECTION INPUT ;
    USE SIGNAL ;
    PORT
      LAYER M4 ;
        RECT  0 82.32 0.084 82.344 ;
    END
  END cfg_data[2]
  PIN cfg_data[30]
    DIRECTION INPUT ;
    USE SIGNAL ;
    PORT
      LAYER M4 ;
        RECT  0 85.008 0.084 85.032 ;
    END
  END cfg_data[30]
  PIN cfg_data[31]
    DIRECTION INPUT ;
    USE SIGNAL ;
    PORT
      LAYER M4 ;
        RECT  0 85.104 0.084 85.128 ;
    END
  END cfg_data[31]
  PIN cfg_data[32]
    DIRECTION INPUT ;
    USE SIGNAL ;
    PORT
      LAYER M4 ;
        RECT  0 85.2 0.084 85.224 ;
    END
  END cfg_data[32]
  PIN cfg_data[33]
    DIRECTION INPUT ;
    USE SIGNAL ;
    PORT
      LAYER M4 ;
        RECT  0 85.296 0.084 85.32 ;
    END
  END cfg_data[33]
  PIN cfg_data[34]
    DIRECTION INPUT ;
    USE SIGNAL ;
    PORT
      LAYER M4 ;
        RECT  0 85.392 0.084 85.416 ;
    END
  END cfg_data[34]
  PIN cfg_data[35]
    DIRECTION INPUT ;
    USE SIGNAL ;
    PORT
      LAYER M4 ;
        RECT  0 85.488 0.084 85.512 ;
    END
  END cfg_data[35]
  PIN cfg_data[36]
    DIRECTION INPUT ;
    USE SIGNAL ;
    PORT
      LAYER M4 ;
        RECT  0 85.584 0.084 85.608 ;
    END
  END cfg_data[36]
  PIN cfg_data[37]
    DIRECTION INPUT ;
    USE SIGNAL ;
    PORT
      LAYER M4 ;
        RECT  0 85.68 0.084 85.704 ;
    END
  END cfg_data[37]
  PIN cfg_data[38]
    DIRECTION INPUT ;
    USE SIGNAL ;
    PORT
      LAYER M4 ;
        RECT  0 85.776 0.084 85.8 ;
    END
  END cfg_data[38]
  PIN cfg_data[39]
    DIRECTION INPUT ;
    USE SIGNAL ;
    PORT
      LAYER M4 ;
        RECT  0 85.872 0.084 85.896 ;
    END
  END cfg_data[39]
  PIN cfg_data[3]
    DIRECTION INPUT ;
    USE SIGNAL ;
    PORT
      LAYER M4 ;
        RECT  0 82.416 0.084 82.44 ;
    END
  END cfg_data[3]
  PIN cfg_data[40]
    DIRECTION INPUT ;
    USE SIGNAL ;
    PORT
      LAYER M4 ;
        RECT  0 85.968 0.084 85.992 ;
    END
  END cfg_data[40]
  PIN cfg_data[41]
    DIRECTION INPUT ;
    USE SIGNAL ;
    PORT
      LAYER M4 ;
        RECT  0 86.064 0.084 86.088 ;
    END
  END cfg_data[41]
  PIN cfg_data[42]
    DIRECTION INPUT ;
    USE SIGNAL ;
    PORT
      LAYER M4 ;
        RECT  0 86.16 0.084 86.184 ;
    END
  END cfg_data[42]
  PIN cfg_data[43]
    DIRECTION INPUT ;
    USE SIGNAL ;
    PORT
      LAYER M4 ;
        RECT  0 86.256 0.084 86.28 ;
    END
  END cfg_data[43]
  PIN cfg_data[44]
    DIRECTION INPUT ;
    USE SIGNAL ;
    PORT
      LAYER M4 ;
        RECT  0 86.352 0.084 86.376 ;
    END
  END cfg_data[44]
  PIN cfg_data[45]
    DIRECTION INPUT ;
    USE SIGNAL ;
    PORT
      LAYER M4 ;
        RECT  0 86.448 0.084 86.472 ;
    END
  END cfg_data[45]
  PIN cfg_data[46]
    DIRECTION INPUT ;
    USE SIGNAL ;
    PORT
      LAYER M4 ;
        RECT  0 86.544 0.084 86.568 ;
    END
  END cfg_data[46]
  PIN cfg_data[47]
    DIRECTION INPUT ;
    USE SIGNAL ;
    PORT
      LAYER M4 ;
        RECT  0 86.64 0.084 86.664 ;
    END
  END cfg_data[47]
  PIN cfg_data[48]
    DIRECTION INPUT ;
    USE SIGNAL ;
    PORT
      LAYER M4 ;
        RECT  0 86.736 0.084 86.76 ;
    END
  END cfg_data[48]
  PIN cfg_data[49]
    DIRECTION INPUT ;
    USE SIGNAL ;
    PORT
      LAYER M4 ;
        RECT  0 86.832 0.084 86.856 ;
    END
  END cfg_data[49]
  PIN cfg_data[4]
    DIRECTION INPUT ;
    USE SIGNAL ;
    PORT
      LAYER M4 ;
        RECT  0 82.512 0.084 82.536 ;
    END
  END cfg_data[4]
  PIN cfg_data[50]
    DIRECTION INPUT ;
    USE SIGNAL ;
    PORT
      LAYER M4 ;
        RECT  0 86.928 0.084 86.952 ;
    END
  END cfg_data[50]
  PIN cfg_data[51]
    DIRECTION INPUT ;
    USE SIGNAL ;
    PORT
      LAYER M4 ;
        RECT  0 87.024 0.084 87.048 ;
    END
  END cfg_data[51]
  PIN cfg_data[52]
    DIRECTION INPUT ;
    USE SIGNAL ;
    PORT
      LAYER M4 ;
        RECT  0 87.12 0.084 87.144 ;
    END
  END cfg_data[52]
  PIN cfg_data[53]
    DIRECTION INPUT ;
    USE SIGNAL ;
    PORT
      LAYER M4 ;
        RECT  0 87.216 0.084 87.24 ;
    END
  END cfg_data[53]
  PIN cfg_data[54]
    DIRECTION INPUT ;
    USE SIGNAL ;
    PORT
      LAYER M4 ;
        RECT  0 87.312 0.084 87.336 ;
    END
  END cfg_data[54]
  PIN cfg_data[55]
    DIRECTION INPUT ;
    USE SIGNAL ;
    PORT
      LAYER M4 ;
        RECT  0 87.408 0.084 87.432 ;
    END
  END cfg_data[55]
  PIN cfg_data[56]
    DIRECTION INPUT ;
    USE SIGNAL ;
    PORT
      LAYER M4 ;
        RECT  0 87.504 0.084 87.528 ;
    END
  END cfg_data[56]
  PIN cfg_data[57]
    DIRECTION INPUT ;
    USE SIGNAL ;
    PORT
      LAYER M4 ;
        RECT  0 87.6 0.084 87.624 ;
    END
  END cfg_data[57]
  PIN cfg_data[58]
    DIRECTION INPUT ;
    USE SIGNAL ;
    PORT
      LAYER M4 ;
        RECT  0 87.696 0.084 87.72 ;
    END
  END cfg_data[58]
  PIN cfg_data[59]
    DIRECTION INPUT ;
    USE SIGNAL ;
    PORT
      LAYER M4 ;
        RECT  0 87.792 0.084 87.816 ;
    END
  END cfg_data[59]
  PIN cfg_data[5]
    DIRECTION INPUT ;
    USE SIGNAL ;
    PORT
      LAYER M4 ;
        RECT  0 82.608 0.084 82.632 ;
    END
  END cfg_data[5]
  PIN cfg_data[60]
    DIRECTION INPUT ;
    USE SIGNAL ;
    PORT
      LAYER M4 ;
        RECT  0 87.888 0.084 87.912 ;
    END
  END cfg_data[60]
  PIN cfg_data[61]
    DIRECTION INPUT ;
    USE SIGNAL ;
    PORT
      LAYER M4 ;
        RECT  0 87.984 0.084 88.008 ;
    END
  END cfg_data[61]
  PIN cfg_data[62]
    DIRECTION INPUT ;
    USE SIGNAL ;
    PORT
      LAYER M4 ;
        RECT  0 88.08 0.084 88.104 ;
    END
  END cfg_data[62]
  PIN cfg_data[63]
    DIRECTION INPUT ;
    USE SIGNAL ;
    PORT
      LAYER M4 ;
        RECT  0 88.176 0.084 88.2 ;
    END
  END cfg_data[63]
  PIN cfg_data[64]
    DIRECTION INPUT ;
    USE SIGNAL ;
    PORT
      LAYER M4 ;
        RECT  0 88.272 0.084 88.296 ;
    END
  END cfg_data[64]
  PIN cfg_data[65]
    DIRECTION INPUT ;
    USE SIGNAL ;
    PORT
      LAYER M4 ;
        RECT  0 88.368 0.084 88.392 ;
    END
  END cfg_data[65]
  PIN cfg_data[66]
    DIRECTION INPUT ;
    USE SIGNAL ;
    PORT
      LAYER M4 ;
        RECT  0 88.464 0.084 88.488 ;
    END
  END cfg_data[66]
  PIN cfg_data[67]
    DIRECTION INPUT ;
    USE SIGNAL ;
    PORT
      LAYER M4 ;
        RECT  0 88.56 0.084 88.584 ;
    END
  END cfg_data[67]
  PIN cfg_data[68]
    DIRECTION INPUT ;
    USE SIGNAL ;
    PORT
      LAYER M4 ;
        RECT  0 88.656 0.084 88.68 ;
    END
  END cfg_data[68]
  PIN cfg_data[69]
    DIRECTION INPUT ;
    USE SIGNAL ;
    PORT
      LAYER M4 ;
        RECT  0 88.752 0.084 88.776 ;
    END
  END cfg_data[69]
  PIN cfg_data[6]
    DIRECTION INPUT ;
    USE SIGNAL ;
    PORT
      LAYER M4 ;
        RECT  0 82.704 0.084 82.728 ;
    END
  END cfg_data[6]
  PIN cfg_data[70]
    DIRECTION INPUT ;
    USE SIGNAL ;
    PORT
      LAYER M4 ;
        RECT  0 88.848 0.084 88.872 ;
    END
  END cfg_data[70]
  PIN cfg_data[71]
    DIRECTION INPUT ;
    USE SIGNAL ;
    PORT
      LAYER M4 ;
        RECT  0 88.944 0.084 88.968 ;
    END
  END cfg_data[71]
  PIN cfg_data[72]
    DIRECTION INPUT ;
    USE SIGNAL ;
    PORT
      LAYER M4 ;
        RECT  0 89.04 0.084 89.064 ;
    END
  END cfg_data[72]
  PIN cfg_data[73]
    DIRECTION INPUT ;
    USE SIGNAL ;
    PORT
      LAYER M4 ;
        RECT  0 89.136 0.084 89.16 ;
    END
  END cfg_data[73]
  PIN cfg_data[74]
    DIRECTION INPUT ;
    USE SIGNAL ;
    PORT
      LAYER M4 ;
        RECT  0 89.232 0.084 89.256 ;
    END
  END cfg_data[74]
  PIN cfg_data[75]
    DIRECTION INPUT ;
    USE SIGNAL ;
    PORT
      LAYER M4 ;
        RECT  0 89.328 0.084 89.352 ;
    END
  END cfg_data[75]
  PIN cfg_data[76]
    DIRECTION INPUT ;
    USE SIGNAL ;
    PORT
      LAYER M4 ;
        RECT  0 89.424 0.084 89.448 ;
    END
  END cfg_data[76]
  PIN cfg_data[77]
    DIRECTION INPUT ;
    USE SIGNAL ;
    PORT
      LAYER M4 ;
        RECT  0 89.52 0.084 89.544 ;
    END
  END cfg_data[77]
  PIN cfg_data[78]
    DIRECTION INPUT ;
    USE SIGNAL ;
    PORT
      LAYER M4 ;
        RECT  0 89.616 0.084 89.64 ;
    END
  END cfg_data[78]
  PIN cfg_data[79]
    DIRECTION INPUT ;
    USE SIGNAL ;
    PORT
      LAYER M4 ;
        RECT  0 89.712 0.084 89.736 ;
    END
  END cfg_data[79]
  PIN cfg_data[7]
    DIRECTION INPUT ;
    USE SIGNAL ;
    PORT
      LAYER M4 ;
        RECT  0 82.8 0.084 82.824 ;
    END
  END cfg_data[7]
  PIN cfg_data[80]
    DIRECTION INPUT ;
    USE SIGNAL ;
    PORT
      LAYER M4 ;
        RECT  0 89.808 0.084 89.832 ;
    END
  END cfg_data[80]
  PIN cfg_data[81]
    DIRECTION INPUT ;
    USE SIGNAL ;
    PORT
      LAYER M4 ;
        RECT  0 89.904 0.084 89.928 ;
    END
  END cfg_data[81]
  PIN cfg_data[82]
    DIRECTION INPUT ;
    USE SIGNAL ;
    PORT
      LAYER M4 ;
        RECT  0 90 0.084 90.024 ;
    END
  END cfg_data[82]
  PIN cfg_data[83]
    DIRECTION INPUT ;
    USE SIGNAL ;
    PORT
      LAYER M4 ;
        RECT  0 90.096 0.084 90.12 ;
    END
  END cfg_data[83]
  PIN cfg_data[84]
    DIRECTION INPUT ;
    USE SIGNAL ;
    PORT
      LAYER M4 ;
        RECT  0 90.192 0.084 90.216 ;
    END
  END cfg_data[84]
  PIN cfg_data[85]
    DIRECTION INPUT ;
    USE SIGNAL ;
    PORT
      LAYER M4 ;
        RECT  0 90.288 0.084 90.312 ;
    END
  END cfg_data[85]
  PIN cfg_data[86]
    DIRECTION INPUT ;
    USE SIGNAL ;
    PORT
      LAYER M4 ;
        RECT  0 90.384 0.084 90.408 ;
    END
  END cfg_data[86]
  PIN cfg_data[87]
    DIRECTION INPUT ;
    USE SIGNAL ;
    PORT
      LAYER M4 ;
        RECT  0 90.48 0.084 90.504 ;
    END
  END cfg_data[87]
  PIN cfg_data[88]
    DIRECTION INPUT ;
    USE SIGNAL ;
    PORT
      LAYER M4 ;
        RECT  0 90.576 0.084 90.6 ;
    END
  END cfg_data[88]
  PIN cfg_data[89]
    DIRECTION INPUT ;
    USE SIGNAL ;
    PORT
      LAYER M4 ;
        RECT  0 90.672 0.084 90.696 ;
    END
  END cfg_data[89]
  PIN cfg_data[8]
    DIRECTION INPUT ;
    USE SIGNAL ;
    PORT
      LAYER M4 ;
        RECT  0 82.896 0.084 82.92 ;
    END
  END cfg_data[8]
  PIN cfg_data[90]
    DIRECTION INPUT ;
    USE SIGNAL ;
    PORT
      LAYER M4 ;
        RECT  0 90.768 0.084 90.792 ;
    END
  END cfg_data[90]
  PIN cfg_data[91]
    DIRECTION INPUT ;
    USE SIGNAL ;
    PORT
      LAYER M4 ;
        RECT  0 90.864 0.084 90.888 ;
    END
  END cfg_data[91]
  PIN cfg_data[92]
    DIRECTION INPUT ;
    USE SIGNAL ;
    PORT
      LAYER M4 ;
        RECT  0 90.96 0.084 90.984 ;
    END
  END cfg_data[92]
  PIN cfg_data[93]
    DIRECTION INPUT ;
    USE SIGNAL ;
    PORT
      LAYER M4 ;
        RECT  0 91.056 0.084 91.08 ;
    END
  END cfg_data[93]
  PIN cfg_data[94]
    DIRECTION INPUT ;
    USE SIGNAL ;
    PORT
      LAYER M4 ;
        RECT  0 91.152 0.084 91.176 ;
    END
  END cfg_data[94]
  PIN cfg_data[95]
    DIRECTION INPUT ;
    USE SIGNAL ;
    PORT
      LAYER M4 ;
        RECT  0 91.248 0.084 91.272 ;
    END
  END cfg_data[95]
  PIN cfg_data[96]
    DIRECTION INPUT ;
    USE SIGNAL ;
    PORT
      LAYER M4 ;
        RECT  0 91.344 0.084 91.368 ;
    END
  END cfg_data[96]
  PIN cfg_data[97]
    DIRECTION INPUT ;
    USE SIGNAL ;
    PORT
      LAYER M4 ;
        RECT  0 91.44 0.084 91.464 ;
    END
  END cfg_data[97]
  PIN cfg_data[98]
    DIRECTION INPUT ;
    USE SIGNAL ;
    PORT
      LAYER M4 ;
        RECT  0 91.536 0.084 91.56 ;
    END
  END cfg_data[98]
  PIN cfg_data[99]
    DIRECTION INPUT ;
    USE SIGNAL ;
    PORT
      LAYER M4 ;
        RECT  0 91.632 0.084 91.656 ;
    END
  END cfg_data[99]
  PIN cfg_data[9]
    DIRECTION INPUT ;
    USE SIGNAL ;
    PORT
      LAYER M4 ;
        RECT  0 82.992 0.084 83.016 ;
    END
  END cfg_data[9]
  PIN cfg_we
    DIRECTION INPUT ;
    USE SIGNAL ;
    PORT
      LAYER M4 ;
        RECT  0 52.944 0.084 52.968 ;
    END
  END cfg_we
  PIN client_seq[0]
    DIRECTION OUTPUT ;
    USE SIGNAL ;
    PORT
      LAYER M4 ;
        RECT  220.236 64.464 220.32 64.488 ;
    END
  END client_seq[0]
  PIN client_seq[10]
    DIRECTION OUTPUT ;
    USE SIGNAL ;
    PORT
      LAYER M4 ;
        RECT  220.236 65.424 220.32 65.448 ;
    END
  END client_seq[10]
  PIN client_seq[11]
    DIRECTION OUTPUT ;
    USE SIGNAL ;
    PORT
      LAYER M4 ;
        RECT  220.236 65.52 220.32 65.544 ;
    END
  END client_seq[11]
  PIN client_seq[12]
    DIRECTION OUTPUT ;
    USE SIGNAL ;
    PORT
      LAYER M4 ;
        RECT  220.236 65.616 220.32 65.64 ;
    END
  END client_seq[12]
  PIN client_seq[13]
    DIRECTION OUTPUT ;
    USE SIGNAL ;
    PORT
      LAYER M4 ;
        RECT  220.236 65.712 220.32 65.736 ;
    END
  END client_seq[13]
  PIN client_seq[14]
    DIRECTION OUTPUT ;
    USE SIGNAL ;
    PORT
      LAYER M4 ;
        RECT  220.236 65.808 220.32 65.832 ;
    END
  END client_seq[14]
  PIN client_seq[15]
    DIRECTION OUTPUT ;
    USE SIGNAL ;
    PORT
      LAYER M4 ;
        RECT  220.236 65.904 220.32 65.928 ;
    END
  END client_seq[15]
  PIN client_seq[1]
    DIRECTION OUTPUT ;
    USE SIGNAL ;
    PORT
      LAYER M4 ;
        RECT  220.236 64.56 220.32 64.584 ;
    END
  END client_seq[1]
  PIN client_seq[2]
    DIRECTION OUTPUT ;
    USE SIGNAL ;
    PORT
      LAYER M4 ;
        RECT  220.236 64.656 220.32 64.68 ;
    END
  END client_seq[2]
  PIN client_seq[3]
    DIRECTION OUTPUT ;
    USE SIGNAL ;
    PORT
      LAYER M4 ;
        RECT  220.236 64.752 220.32 64.776 ;
    END
  END client_seq[3]
  PIN client_seq[4]
    DIRECTION OUTPUT ;
    USE SIGNAL ;
    PORT
      LAYER M4 ;
        RECT  220.236 64.848 220.32 64.872 ;
    END
  END client_seq[4]
  PIN client_seq[5]
    DIRECTION OUTPUT ;
    USE SIGNAL ;
    PORT
      LAYER M4 ;
        RECT  220.236 64.944 220.32 64.968 ;
    END
  END client_seq[5]
  PIN client_seq[6]
    DIRECTION OUTPUT ;
    USE SIGNAL ;
    PORT
      LAYER M4 ;
        RECT  220.236 65.04 220.32 65.064 ;
    END
  END client_seq[6]
  PIN client_seq[7]
    DIRECTION OUTPUT ;
    USE SIGNAL ;
    PORT
      LAYER M4 ;
        RECT  220.236 65.136 220.32 65.16 ;
    END
  END client_seq[7]
  PIN client_seq[8]
    DIRECTION OUTPUT ;
    USE SIGNAL ;
    PORT
      LAYER M4 ;
        RECT  220.236 65.232 220.32 65.256 ;
    END
  END client_seq[8]
  PIN client_seq[9]
    DIRECTION OUTPUT ;
    USE SIGNAL ;
    PORT
      LAYER M4 ;
        RECT  220.236 65.328 220.32 65.352 ;
    END
  END client_seq[9]
  PIN clk
    DIRECTION INPUT ;
    USE SIGNAL ;
    PORT
      LAYER M4 ;
        RECT  0 53.04 0.084 53.064 ;
    END
  END clk
  PIN done
    DIRECTION OUTPUT ;
    USE SIGNAL ;
    PORT
      LAYER M5 ;
        RECT  23.184 0 23.208 0.084 ;
    END
  END done
  PIN fault
    DIRECTION OUTPUT ;
    USE SIGNAL ;
    PORT
      LAYER M5 ;
        RECT  23.28 0 23.304 0.084 ;
    END
  END fault
  PIN hub_ring_client[0]
    DIRECTION OUTPUT ;
    USE SIGNAL ;
    PORT
      LAYER M4 ;
        RECT  220.236 66 220.32 66.024 ;
    END
  END hub_ring_client[0]
  PIN hub_ring_client[1]
    DIRECTION OUTPUT ;
    USE SIGNAL ;
    PORT
      LAYER M4 ;
        RECT  220.236 66.096 220.32 66.12 ;
    END
  END hub_ring_client[1]
  PIN hub_ring_client[2]
    DIRECTION OUTPUT ;
    USE SIGNAL ;
    PORT
      LAYER M4 ;
        RECT  220.236 66.192 220.32 66.216 ;
    END
  END hub_ring_client[2]
  PIN hub_ring_client[3]
    DIRECTION OUTPUT ;
    USE SIGNAL ;
    PORT
      LAYER M4 ;
        RECT  220.236 66.288 220.32 66.312 ;
    END
  END hub_ring_client[3]
  PIN hub_ring_client[4]
    DIRECTION OUTPUT ;
    USE SIGNAL ;
    PORT
      LAYER M4 ;
        RECT  220.236 66.384 220.32 66.408 ;
    END
  END hub_ring_client[4]
  PIN hub_ring_client[5]
    DIRECTION OUTPUT ;
    USE SIGNAL ;
    PORT
      LAYER M4 ;
        RECT  220.236 66.48 220.32 66.504 ;
    END
  END hub_ring_client[5]
  PIN hub_ring_enable[0]
    DIRECTION OUTPUT ;
    USE SIGNAL ;
    PORT
      LAYER M4 ;
        RECT  220.236 66.576 220.32 66.6 ;
    END
  END hub_ring_enable[0]
  PIN hub_ring_enable[1]
    DIRECTION OUTPUT ;
    USE SIGNAL ;
    PORT
      LAYER M4 ;
        RECT  220.236 66.672 220.32 66.696 ;
    END
  END hub_ring_enable[1]
  PIN lg_local_read[0]
    DIRECTION OUTPUT ;
    USE SIGNAL ;
    PORT
      LAYER M4 ;
        RECT  220.236 66.768 220.32 66.792 ;
    END
  END lg_local_read[0]
  PIN lg_local_read[10]
    DIRECTION OUTPUT ;
    USE SIGNAL ;
    PORT
      LAYER M4 ;
        RECT  220.236 73.872 220.32 73.896 ;
    END
  END lg_local_read[10]
  PIN lg_local_read[11]
    DIRECTION OUTPUT ;
    USE SIGNAL ;
    PORT
      LAYER M4 ;
        RECT  220.236 73.968 220.32 73.992 ;
    END
  END lg_local_read[11]
  PIN lg_local_read[12]
    DIRECTION OUTPUT ;
    USE SIGNAL ;
    PORT
      LAYER M4 ;
        RECT  220.236 74.064 220.32 74.088 ;
    END
  END lg_local_read[12]
  PIN lg_local_read[13]
    DIRECTION OUTPUT ;
    USE SIGNAL ;
    PORT
      LAYER M4 ;
        RECT  220.236 74.16 220.32 74.184 ;
    END
  END lg_local_read[13]
  PIN lg_local_read[14]
    DIRECTION OUTPUT ;
    USE SIGNAL ;
    PORT
      LAYER M4 ;
        RECT  220.236 74.256 220.32 74.28 ;
    END
  END lg_local_read[14]
  PIN lg_local_read[15]
    DIRECTION OUTPUT ;
    USE SIGNAL ;
    PORT
      LAYER M4 ;
        RECT  220.236 74.352 220.32 74.376 ;
    END
  END lg_local_read[15]
  PIN lg_local_read[16]
    DIRECTION OUTPUT ;
    USE SIGNAL ;
    PORT
      LAYER M4 ;
        RECT  220.236 74.448 220.32 74.472 ;
    END
  END lg_local_read[16]
  PIN lg_local_read[17]
    DIRECTION OUTPUT ;
    USE SIGNAL ;
    PORT
      LAYER M4 ;
        RECT  220.236 74.544 220.32 74.568 ;
    END
  END lg_local_read[17]
  PIN lg_local_read[18]
    DIRECTION OUTPUT ;
    USE SIGNAL ;
    PORT
      LAYER M4 ;
        RECT  220.236 74.64 220.32 74.664 ;
    END
  END lg_local_read[18]
  PIN lg_local_read[19]
    DIRECTION OUTPUT ;
    USE SIGNAL ;
    PORT
      LAYER M4 ;
        RECT  220.236 74.736 220.32 74.76 ;
    END
  END lg_local_read[19]
  PIN lg_local_read[1]
    DIRECTION OUTPUT ;
    USE SIGNAL ;
    PORT
      LAYER M4 ;
        RECT  220.236 66.864 220.32 66.888 ;
    END
  END lg_local_read[1]
  PIN lg_local_read[20]
    DIRECTION OUTPUT ;
    USE SIGNAL ;
    PORT
      LAYER M4 ;
        RECT  220.236 74.832 220.32 74.856 ;
    END
  END lg_local_read[20]
  PIN lg_local_read[21]
    DIRECTION OUTPUT ;
    USE SIGNAL ;
    PORT
      LAYER M4 ;
        RECT  220.236 74.928 220.32 74.952 ;
    END
  END lg_local_read[21]
  PIN lg_local_read[22]
    DIRECTION OUTPUT ;
    USE SIGNAL ;
    PORT
      LAYER M4 ;
        RECT  220.236 75.024 220.32 75.048 ;
    END
  END lg_local_read[22]
  PIN lg_local_read[23]
    DIRECTION OUTPUT ;
    USE SIGNAL ;
    PORT
      LAYER M4 ;
        RECT  220.236 75.12 220.32 75.144 ;
    END
  END lg_local_read[23]
  PIN lg_local_read[2]
    DIRECTION OUTPUT ;
    USE SIGNAL ;
    PORT
      LAYER M4 ;
        RECT  220.236 66.96 220.32 66.984 ;
    END
  END lg_local_read[2]
  PIN lg_local_read[3]
    DIRECTION OUTPUT ;
    USE SIGNAL ;
    PORT
      LAYER M4 ;
        RECT  220.236 67.056 220.32 67.08 ;
    END
  END lg_local_read[3]
  PIN lg_local_read[4]
    DIRECTION OUTPUT ;
    USE SIGNAL ;
    PORT
      LAYER M4 ;
        RECT  220.236 67.152 220.32 67.176 ;
    END
  END lg_local_read[4]
  PIN lg_local_read[5]
    DIRECTION OUTPUT ;
    USE SIGNAL ;
    PORT
      LAYER M4 ;
        RECT  220.236 67.248 220.32 67.272 ;
    END
  END lg_local_read[5]
  PIN lg_local_read[6]
    DIRECTION OUTPUT ;
    USE SIGNAL ;
    PORT
      LAYER M4 ;
        RECT  220.236 67.344 220.32 67.368 ;
    END
  END lg_local_read[6]
  PIN lg_local_read[7]
    DIRECTION OUTPUT ;
    USE SIGNAL ;
    PORT
      LAYER M4 ;
        RECT  220.236 67.44 220.32 67.464 ;
    END
  END lg_local_read[7]
  PIN lg_local_read[8]
    DIRECTION OUTPUT ;
    USE SIGNAL ;
    PORT
      LAYER M4 ;
        RECT  220.236 73.68 220.32 73.704 ;
    END
  END lg_local_read[8]
  PIN lg_local_read[9]
    DIRECTION OUTPUT ;
    USE SIGNAL ;
    PORT
      LAYER M4 ;
        RECT  220.236 73.776 220.32 73.8 ;
    END
  END lg_local_read[9]
  PIN lg_local_write[0]
    DIRECTION OUTPUT ;
    USE SIGNAL ;
    PORT
      LAYER M4 ;
        RECT  220.236 75.216 220.32 75.24 ;
    END
  END lg_local_write[0]
  PIN lg_local_write[10]
    DIRECTION OUTPUT ;
    USE SIGNAL ;
    PORT
      LAYER M4 ;
        RECT  220.236 76.176 220.32 76.2 ;
    END
  END lg_local_write[10]
  PIN lg_local_write[11]
    DIRECTION OUTPUT ;
    USE SIGNAL ;
    PORT
      LAYER M4 ;
        RECT  220.236 76.272 220.32 76.296 ;
    END
  END lg_local_write[11]
  PIN lg_local_write[12]
    DIRECTION OUTPUT ;
    USE SIGNAL ;
    PORT
      LAYER M4 ;
        RECT  220.236 76.368 220.32 76.392 ;
    END
  END lg_local_write[12]
  PIN lg_local_write[13]
    DIRECTION OUTPUT ;
    USE SIGNAL ;
    PORT
      LAYER M4 ;
        RECT  220.236 76.464 220.32 76.488 ;
    END
  END lg_local_write[13]
  PIN lg_local_write[14]
    DIRECTION OUTPUT ;
    USE SIGNAL ;
    PORT
      LAYER M4 ;
        RECT  220.236 76.56 220.32 76.584 ;
    END
  END lg_local_write[14]
  PIN lg_local_write[15]
    DIRECTION OUTPUT ;
    USE SIGNAL ;
    PORT
      LAYER M4 ;
        RECT  220.236 76.656 220.32 76.68 ;
    END
  END lg_local_write[15]
  PIN lg_local_write[16]
    DIRECTION OUTPUT ;
    USE SIGNAL ;
    PORT
      LAYER M4 ;
        RECT  220.236 58.32 220.32 58.344 ;
    END
  END lg_local_write[16]
  PIN lg_local_write[17]
    DIRECTION OUTPUT ;
    USE SIGNAL ;
    PORT
      LAYER M4 ;
        RECT  220.236 58.416 220.32 58.44 ;
    END
  END lg_local_write[17]
  PIN lg_local_write[18]
    DIRECTION OUTPUT ;
    USE SIGNAL ;
    PORT
      LAYER M4 ;
        RECT  220.236 58.512 220.32 58.536 ;
    END
  END lg_local_write[18]
  PIN lg_local_write[19]
    DIRECTION OUTPUT ;
    USE SIGNAL ;
    PORT
      LAYER M4 ;
        RECT  220.236 58.608 220.32 58.632 ;
    END
  END lg_local_write[19]
  PIN lg_local_write[1]
    DIRECTION OUTPUT ;
    USE SIGNAL ;
    PORT
      LAYER M4 ;
        RECT  220.236 75.312 220.32 75.336 ;
    END
  END lg_local_write[1]
  PIN lg_local_write[20]
    DIRECTION OUTPUT ;
    USE SIGNAL ;
    PORT
      LAYER M4 ;
        RECT  220.236 58.704 220.32 58.728 ;
    END
  END lg_local_write[20]
  PIN lg_local_write[21]
    DIRECTION OUTPUT ;
    USE SIGNAL ;
    PORT
      LAYER M4 ;
        RECT  220.236 58.8 220.32 58.824 ;
    END
  END lg_local_write[21]
  PIN lg_local_write[22]
    DIRECTION OUTPUT ;
    USE SIGNAL ;
    PORT
      LAYER M4 ;
        RECT  220.236 58.896 220.32 58.92 ;
    END
  END lg_local_write[22]
  PIN lg_local_write[23]
    DIRECTION OUTPUT ;
    USE SIGNAL ;
    PORT
      LAYER M4 ;
        RECT  220.236 58.992 220.32 59.016 ;
    END
  END lg_local_write[23]
  PIN lg_local_write[2]
    DIRECTION OUTPUT ;
    USE SIGNAL ;
    PORT
      LAYER M4 ;
        RECT  220.236 75.408 220.32 75.432 ;
    END
  END lg_local_write[2]
  PIN lg_local_write[3]
    DIRECTION OUTPUT ;
    USE SIGNAL ;
    PORT
      LAYER M4 ;
        RECT  220.236 75.504 220.32 75.528 ;
    END
  END lg_local_write[3]
  PIN lg_local_write[4]
    DIRECTION OUTPUT ;
    USE SIGNAL ;
    PORT
      LAYER M4 ;
        RECT  220.236 75.6 220.32 75.624 ;
    END
  END lg_local_write[4]
  PIN lg_local_write[5]
    DIRECTION OUTPUT ;
    USE SIGNAL ;
    PORT
      LAYER M4 ;
        RECT  220.236 75.696 220.32 75.72 ;
    END
  END lg_local_write[5]
  PIN lg_local_write[6]
    DIRECTION OUTPUT ;
    USE SIGNAL ;
    PORT
      LAYER M4 ;
        RECT  220.236 75.792 220.32 75.816 ;
    END
  END lg_local_write[6]
  PIN lg_local_write[7]
    DIRECTION OUTPUT ;
    USE SIGNAL ;
    PORT
      LAYER M4 ;
        RECT  220.236 75.888 220.32 75.912 ;
    END
  END lg_local_write[7]
  PIN lg_local_write[8]
    DIRECTION OUTPUT ;
    USE SIGNAL ;
    PORT
      LAYER M4 ;
        RECT  220.236 75.984 220.32 76.008 ;
    END
  END lg_local_write[8]
  PIN lg_local_write[9]
    DIRECTION OUTPUT ;
    USE SIGNAL ;
    PORT
      LAYER M4 ;
        RECT  220.236 76.08 220.32 76.104 ;
    END
  END lg_local_write[9]
  PIN ordinal[0]
    DIRECTION OUTPUT ;
    USE SIGNAL ;
    PORT
      LAYER M5 ;
        RECT  23.376 0 23.4 0.084 ;
    END
  END ordinal[0]
  PIN ordinal[10]
    DIRECTION OUTPUT ;
    USE SIGNAL ;
    PORT
      LAYER M5 ;
        RECT  24.336 0 24.36 0.084 ;
    END
  END ordinal[10]
  PIN ordinal[11]
    DIRECTION OUTPUT ;
    USE SIGNAL ;
    PORT
      LAYER M5 ;
        RECT  24.432 0 24.456 0.084 ;
    END
  END ordinal[11]
  PIN ordinal[12]
    DIRECTION OUTPUT ;
    USE SIGNAL ;
    PORT
      LAYER M5 ;
        RECT  24.528 0 24.552 0.084 ;
    END
  END ordinal[12]
  PIN ordinal[13]
    DIRECTION OUTPUT ;
    USE SIGNAL ;
    PORT
      LAYER M5 ;
        RECT  24.624 0 24.648 0.084 ;
    END
  END ordinal[13]
  PIN ordinal[14]
    DIRECTION OUTPUT ;
    USE SIGNAL ;
    PORT
      LAYER M5 ;
        RECT  24.72 0 24.744 0.084 ;
    END
  END ordinal[14]
  PIN ordinal[15]
    DIRECTION OUTPUT ;
    USE SIGNAL ;
    PORT
      LAYER M5 ;
        RECT  24.816 0 24.84 0.084 ;
    END
  END ordinal[15]
  PIN ordinal[16]
    DIRECTION OUTPUT ;
    USE SIGNAL ;
    PORT
      LAYER M5 ;
        RECT  24.912 0 24.936 0.084 ;
    END
  END ordinal[16]
  PIN ordinal[17]
    DIRECTION OUTPUT ;
    USE SIGNAL ;
    PORT
      LAYER M5 ;
        RECT  25.008 0 25.032 0.084 ;
    END
  END ordinal[17]
  PIN ordinal[18]
    DIRECTION OUTPUT ;
    USE SIGNAL ;
    PORT
      LAYER M5 ;
        RECT  25.104 0 25.128 0.084 ;
    END
  END ordinal[18]
  PIN ordinal[19]
    DIRECTION OUTPUT ;
    USE SIGNAL ;
    PORT
      LAYER M5 ;
        RECT  25.2 0 25.224 0.084 ;
    END
  END ordinal[19]
  PIN ordinal[1]
    DIRECTION OUTPUT ;
    USE SIGNAL ;
    PORT
      LAYER M5 ;
        RECT  23.472 0 23.496 0.084 ;
    END
  END ordinal[1]
  PIN ordinal[20]
    DIRECTION OUTPUT ;
    USE SIGNAL ;
    PORT
      LAYER M5 ;
        RECT  25.296 0 25.32 0.084 ;
    END
  END ordinal[20]
  PIN ordinal[21]
    DIRECTION OUTPUT ;
    USE SIGNAL ;
    PORT
      LAYER M5 ;
        RECT  25.392 0 25.416 0.084 ;
    END
  END ordinal[21]
  PIN ordinal[22]
    DIRECTION OUTPUT ;
    USE SIGNAL ;
    PORT
      LAYER M5 ;
        RECT  25.488 0 25.512 0.084 ;
    END
  END ordinal[22]
  PIN ordinal[23]
    DIRECTION OUTPUT ;
    USE SIGNAL ;
    PORT
      LAYER M5 ;
        RECT  25.584 0 25.608 0.084 ;
    END
  END ordinal[23]
  PIN ordinal[24]
    DIRECTION OUTPUT ;
    USE SIGNAL ;
    PORT
      LAYER M5 ;
        RECT  25.68 0 25.704 0.084 ;
    END
  END ordinal[24]
  PIN ordinal[25]
    DIRECTION OUTPUT ;
    USE SIGNAL ;
    PORT
      LAYER M5 ;
        RECT  25.776 0 25.8 0.084 ;
    END
  END ordinal[25]
  PIN ordinal[26]
    DIRECTION OUTPUT ;
    USE SIGNAL ;
    PORT
      LAYER M5 ;
        RECT  25.872 0 25.896 0.084 ;
    END
  END ordinal[26]
  PIN ordinal[27]
    DIRECTION OUTPUT ;
    USE SIGNAL ;
    PORT
      LAYER M5 ;
        RECT  25.968 0 25.992 0.084 ;
    END
  END ordinal[27]
  PIN ordinal[28]
    DIRECTION OUTPUT ;
    USE SIGNAL ;
    PORT
      LAYER M5 ;
        RECT  16.08 0 16.104 0.084 ;
    END
  END ordinal[28]
  PIN ordinal[29]
    DIRECTION OUTPUT ;
    USE SIGNAL ;
    PORT
      LAYER M5 ;
        RECT  16.176 0 16.2 0.084 ;
    END
  END ordinal[29]
  PIN ordinal[2]
    DIRECTION OUTPUT ;
    USE SIGNAL ;
    PORT
      LAYER M5 ;
        RECT  23.568 0 23.592 0.084 ;
    END
  END ordinal[2]
  PIN ordinal[30]
    DIRECTION OUTPUT ;
    USE SIGNAL ;
    PORT
      LAYER M5 ;
        RECT  16.272 0 16.296 0.084 ;
    END
  END ordinal[30]
  PIN ordinal[31]
    DIRECTION OUTPUT ;
    USE SIGNAL ;
    PORT
      LAYER M5 ;
        RECT  16.368 0 16.392 0.084 ;
    END
  END ordinal[31]
  PIN ordinal[3]
    DIRECTION OUTPUT ;
    USE SIGNAL ;
    PORT
      LAYER M5 ;
        RECT  23.664 0 23.688 0.084 ;
    END
  END ordinal[3]
  PIN ordinal[4]
    DIRECTION OUTPUT ;
    USE SIGNAL ;
    PORT
      LAYER M5 ;
        RECT  23.76 0 23.784 0.084 ;
    END
  END ordinal[4]
  PIN ordinal[5]
    DIRECTION OUTPUT ;
    USE SIGNAL ;
    PORT
      LAYER M5 ;
        RECT  23.856 0 23.88 0.084 ;
    END
  END ordinal[5]
  PIN ordinal[6]
    DIRECTION OUTPUT ;
    USE SIGNAL ;
    PORT
      LAYER M5 ;
        RECT  23.952 0 23.976 0.084 ;
    END
  END ordinal[6]
  PIN ordinal[7]
    DIRECTION OUTPUT ;
    USE SIGNAL ;
    PORT
      LAYER M5 ;
        RECT  24.048 0 24.072 0.084 ;
    END
  END ordinal[7]
  PIN ordinal[8]
    DIRECTION OUTPUT ;
    USE SIGNAL ;
    PORT
      LAYER M5 ;
        RECT  24.144 0 24.168 0.084 ;
    END
  END ordinal[8]
  PIN ordinal[9]
    DIRECTION OUTPUT ;
    USE SIGNAL ;
    PORT
      LAYER M5 ;
        RECT  24.24 0 24.264 0.084 ;
    END
  END ordinal[9]
  PIN replay_enable
    DIRECTION OUTPUT ;
    USE SIGNAL ;
    PORT
      LAYER M4 ;
        RECT  220.236 59.088 220.32 59.112 ;
    END
  END replay_enable
  PIN replay_source
    DIRECTION OUTPUT ;
    USE SIGNAL ;
    PORT
      LAYER M4 ;
        RECT  220.236 59.184 220.32 59.208 ;
    END
  END replay_source
  PIN response_enable[0]
    DIRECTION OUTPUT ;
    USE SIGNAL ;
    PORT
      LAYER M4 ;
        RECT  220.236 59.28 220.32 59.304 ;
    END
  END response_enable[0]
  PIN response_enable[1]
    DIRECTION OUTPUT ;
    USE SIGNAL ;
    PORT
      LAYER M4 ;
        RECT  220.236 59.376 220.32 59.4 ;
    END
  END response_enable[1]
  PIN response_enable[2]
    DIRECTION OUTPUT ;
    USE SIGNAL ;
    PORT
      LAYER M4 ;
        RECT  220.236 59.472 220.32 59.496 ;
    END
  END response_enable[2]
  PIN response_enable[3]
    DIRECTION OUTPUT ;
    USE SIGNAL ;
    PORT
      LAYER M4 ;
        RECT  220.236 59.568 220.32 59.592 ;
    END
  END response_enable[3]
  PIN response_enable[4]
    DIRECTION OUTPUT ;
    USE SIGNAL ;
    PORT
      LAYER M4 ;
        RECT  220.236 59.664 220.32 59.688 ;
    END
  END response_enable[4]
  PIN response_enable[5]
    DIRECTION OUTPUT ;
    USE SIGNAL ;
    PORT
      LAYER M4 ;
        RECT  220.236 59.76 220.32 59.784 ;
    END
  END response_enable[5]
  PIN response_enable[6]
    DIRECTION OUTPUT ;
    USE SIGNAL ;
    PORT
      LAYER M4 ;
        RECT  220.236 59.856 220.32 59.88 ;
    END
  END response_enable[6]
  PIN response_enable[7]
    DIRECTION OUTPUT ;
    USE SIGNAL ;
    PORT
      LAYER M4 ;
        RECT  220.236 59.952 220.32 59.976 ;
    END
  END response_enable[7]
  PIN response_seq[0]
    DIRECTION OUTPUT ;
    USE SIGNAL ;
    PORT
      LAYER M4 ;
        RECT  220.236 60.048 220.32 60.072 ;
    END
  END response_seq[0]
  PIN response_seq[10]
    DIRECTION OUTPUT ;
    USE SIGNAL ;
    PORT
      LAYER M4 ;
        RECT  220.236 61.008 220.32 61.032 ;
    END
  END response_seq[10]
  PIN response_seq[11]
    DIRECTION OUTPUT ;
    USE SIGNAL ;
    PORT
      LAYER M4 ;
        RECT  220.236 61.104 220.32 61.128 ;
    END
  END response_seq[11]
  PIN response_seq[12]
    DIRECTION OUTPUT ;
    USE SIGNAL ;
    PORT
      LAYER M4 ;
        RECT  220.236 61.2 220.32 61.224 ;
    END
  END response_seq[12]
  PIN response_seq[13]
    DIRECTION OUTPUT ;
    USE SIGNAL ;
    PORT
      LAYER M4 ;
        RECT  220.236 61.296 220.32 61.32 ;
    END
  END response_seq[13]
  PIN response_seq[14]
    DIRECTION OUTPUT ;
    USE SIGNAL ;
    PORT
      LAYER M4 ;
        RECT  220.236 67.536 220.32 67.56 ;
    END
  END response_seq[14]
  PIN response_seq[15]
    DIRECTION OUTPUT ;
    USE SIGNAL ;
    PORT
      LAYER M4 ;
        RECT  220.236 67.632 220.32 67.656 ;
    END
  END response_seq[15]
  PIN response_seq[1]
    DIRECTION OUTPUT ;
    USE SIGNAL ;
    PORT
      LAYER M4 ;
        RECT  220.236 60.144 220.32 60.168 ;
    END
  END response_seq[1]
  PIN response_seq[2]
    DIRECTION OUTPUT ;
    USE SIGNAL ;
    PORT
      LAYER M4 ;
        RECT  220.236 60.24 220.32 60.264 ;
    END
  END response_seq[2]
  PIN response_seq[3]
    DIRECTION OUTPUT ;
    USE SIGNAL ;
    PORT
      LAYER M4 ;
        RECT  220.236 60.336 220.32 60.36 ;
    END
  END response_seq[3]
  PIN response_seq[4]
    DIRECTION OUTPUT ;
    USE SIGNAL ;
    PORT
      LAYER M4 ;
        RECT  220.236 60.432 220.32 60.456 ;
    END
  END response_seq[4]
  PIN response_seq[5]
    DIRECTION OUTPUT ;
    USE SIGNAL ;
    PORT
      LAYER M4 ;
        RECT  220.236 60.528 220.32 60.552 ;
    END
  END response_seq[5]
  PIN response_seq[6]
    DIRECTION OUTPUT ;
    USE SIGNAL ;
    PORT
      LAYER M4 ;
        RECT  220.236 60.624 220.32 60.648 ;
    END
  END response_seq[6]
  PIN response_seq[7]
    DIRECTION OUTPUT ;
    USE SIGNAL ;
    PORT
      LAYER M4 ;
        RECT  220.236 60.72 220.32 60.744 ;
    END
  END response_seq[7]
  PIN response_seq[8]
    DIRECTION OUTPUT ;
    USE SIGNAL ;
    PORT
      LAYER M4 ;
        RECT  220.236 60.816 220.32 60.84 ;
    END
  END response_seq[8]
  PIN response_seq[9]
    DIRECTION OUTPUT ;
    USE SIGNAL ;
    PORT
      LAYER M4 ;
        RECT  220.236 60.912 220.32 60.936 ;
    END
  END response_seq[9]
  PIN ring_tx_enable[0]
    DIRECTION OUTPUT ;
    USE SIGNAL ;
    PORT
      LAYER M4 ;
        RECT  220.236 67.728 220.32 67.752 ;
    END
  END ring_tx_enable[0]
  PIN ring_tx_enable[1]
    DIRECTION OUTPUT ;
    USE SIGNAL ;
    PORT
      LAYER M4 ;
        RECT  220.236 67.824 220.32 67.848 ;
    END
  END ring_tx_enable[1]
  PIN ring_tx_source[0]
    DIRECTION OUTPUT ;
    USE SIGNAL ;
    PORT
      LAYER M4 ;
        RECT  220.236 67.92 220.32 67.944 ;
    END
  END ring_tx_source[0]
  PIN ring_tx_source[1]
    DIRECTION OUTPUT ;
    USE SIGNAL ;
    PORT
      LAYER M4 ;
        RECT  220.236 68.016 220.32 68.04 ;
    END
  END ring_tx_source[1]
  PIN ring_tx_source[2]
    DIRECTION OUTPUT ;
    USE SIGNAL ;
    PORT
      LAYER M4 ;
        RECT  220.236 68.112 220.32 68.136 ;
    END
  END ring_tx_source[2]
  PIN ring_tx_source[3]
    DIRECTION OUTPUT ;
    USE SIGNAL ;
    PORT
      LAYER M4 ;
        RECT  220.236 68.208 220.32 68.232 ;
    END
  END ring_tx_source[3]
  PIN ring_tx_source[4]
    DIRECTION OUTPUT ;
    USE SIGNAL ;
    PORT
      LAYER M4 ;
        RECT  220.236 68.304 220.32 68.328 ;
    END
  END ring_tx_source[4]
  PIN ring_tx_source[5]
    DIRECTION OUTPUT ;
    USE SIGNAL ;
    PORT
      LAYER M4 ;
        RECT  220.236 68.4 220.32 68.424 ;
    END
  END ring_tx_source[5]
  PIN rslot[0]
    DIRECTION OUTPUT ;
    USE SIGNAL ;
    PORT
      LAYER M4 ;
        RECT  220.236 68.496 220.32 68.52 ;
    END
  END rslot[0]
  PIN rslot[10]
    DIRECTION OUTPUT ;
    USE SIGNAL ;
    PORT
      LAYER M4 ;
        RECT  220.236 69.456 220.32 69.48 ;
    END
  END rslot[10]
  PIN rslot[11]
    DIRECTION OUTPUT ;
    USE SIGNAL ;
    PORT
      LAYER M4 ;
        RECT  220.236 69.552 220.32 69.576 ;
    END
  END rslot[11]
  PIN rslot[12]
    DIRECTION OUTPUT ;
    USE SIGNAL ;
    PORT
      LAYER M4 ;
        RECT  220.236 69.648 220.32 69.672 ;
    END
  END rslot[12]
  PIN rslot[13]
    DIRECTION OUTPUT ;
    USE SIGNAL ;
    PORT
      LAYER M4 ;
        RECT  220.236 69.744 220.32 69.768 ;
    END
  END rslot[13]
  PIN rslot[14]
    DIRECTION OUTPUT ;
    USE SIGNAL ;
    PORT
      LAYER M4 ;
        RECT  220.236 69.84 220.32 69.864 ;
    END
  END rslot[14]
  PIN rslot[15]
    DIRECTION OUTPUT ;
    USE SIGNAL ;
    PORT
      LAYER M4 ;
        RECT  220.236 69.936 220.32 69.96 ;
    END
  END rslot[15]
  PIN rslot[16]
    DIRECTION OUTPUT ;
    USE SIGNAL ;
    PORT
      LAYER M4 ;
        RECT  220.236 70.032 220.32 70.056 ;
    END
  END rslot[16]
  PIN rslot[17]
    DIRECTION OUTPUT ;
    USE SIGNAL ;
    PORT
      LAYER M4 ;
        RECT  220.236 70.128 220.32 70.152 ;
    END
  END rslot[17]
  PIN rslot[18]
    DIRECTION OUTPUT ;
    USE SIGNAL ;
    PORT
      LAYER M4 ;
        RECT  220.236 70.224 220.32 70.248 ;
    END
  END rslot[18]
  PIN rslot[19]
    DIRECTION OUTPUT ;
    USE SIGNAL ;
    PORT
      LAYER M4 ;
        RECT  220.236 70.32 220.32 70.344 ;
    END
  END rslot[19]
  PIN rslot[1]
    DIRECTION OUTPUT ;
    USE SIGNAL ;
    PORT
      LAYER M4 ;
        RECT  220.236 68.592 220.32 68.616 ;
    END
  END rslot[1]
  PIN rslot[20]
    DIRECTION OUTPUT ;
    USE SIGNAL ;
    PORT
      LAYER M4 ;
        RECT  220.236 70.416 220.32 70.44 ;
    END
  END rslot[20]
  PIN rslot[21]
    DIRECTION OUTPUT ;
    USE SIGNAL ;
    PORT
      LAYER M4 ;
        RECT  220.236 70.512 220.32 70.536 ;
    END
  END rslot[21]
  PIN rslot[22]
    DIRECTION OUTPUT ;
    USE SIGNAL ;
    PORT
      LAYER M4 ;
        RECT  220.236 70.608 220.32 70.632 ;
    END
  END rslot[22]
  PIN rslot[23]
    DIRECTION OUTPUT ;
    USE SIGNAL ;
    PORT
      LAYER M4 ;
        RECT  220.236 70.704 220.32 70.728 ;
    END
  END rslot[23]
  PIN rslot[2]
    DIRECTION OUTPUT ;
    USE SIGNAL ;
    PORT
      LAYER M4 ;
        RECT  220.236 68.688 220.32 68.712 ;
    END
  END rslot[2]
  PIN rslot[3]
    DIRECTION OUTPUT ;
    USE SIGNAL ;
    PORT
      LAYER M4 ;
        RECT  220.236 68.784 220.32 68.808 ;
    END
  END rslot[3]
  PIN rslot[4]
    DIRECTION OUTPUT ;
    USE SIGNAL ;
    PORT
      LAYER M4 ;
        RECT  220.236 68.88 220.32 68.904 ;
    END
  END rslot[4]
  PIN rslot[5]
    DIRECTION OUTPUT ;
    USE SIGNAL ;
    PORT
      LAYER M4 ;
        RECT  220.236 68.976 220.32 69 ;
    END
  END rslot[5]
  PIN rslot[6]
    DIRECTION OUTPUT ;
    USE SIGNAL ;
    PORT
      LAYER M4 ;
        RECT  220.236 69.072 220.32 69.096 ;
    END
  END rslot[6]
  PIN rslot[7]
    DIRECTION OUTPUT ;
    USE SIGNAL ;
    PORT
      LAYER M4 ;
        RECT  220.236 69.168 220.32 69.192 ;
    END
  END rslot[7]
  PIN rslot[8]
    DIRECTION OUTPUT ;
    USE SIGNAL ;
    PORT
      LAYER M4 ;
        RECT  220.236 69.264 220.32 69.288 ;
    END
  END rslot[8]
  PIN rslot[9]
    DIRECTION OUTPUT ;
    USE SIGNAL ;
    PORT
      LAYER M4 ;
        RECT  220.236 69.36 220.32 69.384 ;
    END
  END rslot[9]
  PIN rslot_v[0]
    DIRECTION OUTPUT ;
    USE SIGNAL ;
    PORT
      LAYER M4 ;
        RECT  220.236 70.8 220.32 70.824 ;
    END
  END rslot_v[0]
  PIN rslot_v[1]
    DIRECTION OUTPUT ;
    USE SIGNAL ;
    PORT
      LAYER M4 ;
        RECT  220.236 70.896 220.32 70.92 ;
    END
  END rslot_v[1]
  PIN rslot_v[2]
    DIRECTION OUTPUT ;
    USE SIGNAL ;
    PORT
      LAYER M4 ;
        RECT  220.236 70.992 220.32 71.016 ;
    END
  END rslot_v[2]
  PIN rslot_v[3]
    DIRECTION OUTPUT ;
    USE SIGNAL ;
    PORT
      LAYER M4 ;
        RECT  220.236 71.088 220.32 71.112 ;
    END
  END rslot_v[3]
  PIN rslot_v[4]
    DIRECTION OUTPUT ;
    USE SIGNAL ;
    PORT
      LAYER M4 ;
        RECT  220.236 71.184 220.32 71.208 ;
    END
  END rslot_v[4]
  PIN rslot_v[5]
    DIRECTION OUTPUT ;
    USE SIGNAL ;
    PORT
      LAYER M4 ;
        RECT  220.236 71.28 220.32 71.304 ;
    END
  END rslot_v[5]
  PIN rslot_v[6]
    DIRECTION OUTPUT ;
    USE SIGNAL ;
    PORT
      LAYER M4 ;
        RECT  220.236 71.376 220.32 71.4 ;
    END
  END rslot_v[6]
  PIN rslot_v[7]
    DIRECTION OUTPUT ;
    USE SIGNAL ;
    PORT
      LAYER M4 ;
        RECT  220.236 71.472 220.32 71.496 ;
    END
  END rslot_v[7]
  PIN rst_n
    DIRECTION INPUT ;
    USE SIGNAL ;
    PORT
      LAYER M4 ;
        RECT  0 53.136 0.084 53.16 ;
    END
  END rst_n
  PIN start_base[0]
    DIRECTION INPUT ;
    USE SIGNAL ;
    PORT
      LAYER M4 ;
        RECT  0 53.232 0.084 53.256 ;
    END
  END start_base[0]
  PIN start_base[1]
    DIRECTION INPUT ;
    USE SIGNAL ;
    PORT
      LAYER M4 ;
        RECT  0 53.328 0.084 53.352 ;
    END
  END start_base[1]
  PIN start_base[2]
    DIRECTION INPUT ;
    USE SIGNAL ;
    PORT
      LAYER M4 ;
        RECT  0 53.424 0.084 53.448 ;
    END
  END start_base[2]
  PIN start_base[3]
    DIRECTION INPUT ;
    USE SIGNAL ;
    PORT
      LAYER M4 ;
        RECT  0 53.52 0.084 53.544 ;
    END
  END start_base[3]
  PIN start_base[4]
    DIRECTION INPUT ;
    USE SIGNAL ;
    PORT
      LAYER M4 ;
        RECT  0 53.616 0.084 53.64 ;
    END
  END start_base[4]
  PIN start_base[5]
    DIRECTION INPUT ;
    USE SIGNAL ;
    PORT
      LAYER M4 ;
        RECT  0 53.712 0.084 53.736 ;
    END
  END start_base[5]
  PIN start_base[6]
    DIRECTION INPUT ;
    USE SIGNAL ;
    PORT
      LAYER M4 ;
        RECT  0 53.808 0.084 53.832 ;
    END
  END start_base[6]
  PIN start_base[7]
    DIRECTION INPUT ;
    USE SIGNAL ;
    PORT
      LAYER M4 ;
        RECT  0 53.904 0.084 53.928 ;
    END
  END start_base[7]
  PIN start_base[8]
    DIRECTION INPUT ;
    USE SIGNAL ;
    PORT
      LAYER M4 ;
        RECT  0 54 0.084 54.024 ;
    END
  END start_base[8]
  PIN start_base[9]
    DIRECTION INPUT ;
    USE SIGNAL ;
    PORT
      LAYER M4 ;
        RECT  0 54.096 0.084 54.12 ;
    END
  END start_base[9]
  PIN start_limit[0]
    DIRECTION INPUT ;
    USE SIGNAL ;
    PORT
      LAYER M4 ;
        RECT  0 54.192 0.084 54.216 ;
    END
  END start_limit[0]
  PIN start_limit[10]
    DIRECTION INPUT ;
    USE SIGNAL ;
    PORT
      LAYER M4 ;
        RECT  0 44.112 0.084 44.136 ;
    END
  END start_limit[10]
  PIN start_limit[1]
    DIRECTION INPUT ;
    USE SIGNAL ;
    PORT
      LAYER M4 ;
        RECT  0 54.288 0.084 54.312 ;
    END
  END start_limit[1]
  PIN start_limit[2]
    DIRECTION INPUT ;
    USE SIGNAL ;
    PORT
      LAYER M4 ;
        RECT  0 54.384 0.084 54.408 ;
    END
  END start_limit[2]
  PIN start_limit[3]
    DIRECTION INPUT ;
    USE SIGNAL ;
    PORT
      LAYER M4 ;
        RECT  0 54.48 0.084 54.504 ;
    END
  END start_limit[3]
  PIN start_limit[4]
    DIRECTION INPUT ;
    USE SIGNAL ;
    PORT
      LAYER M4 ;
        RECT  0 54.576 0.084 54.6 ;
    END
  END start_limit[4]
  PIN start_limit[5]
    DIRECTION INPUT ;
    USE SIGNAL ;
    PORT
      LAYER M4 ;
        RECT  0 54.672 0.084 54.696 ;
    END
  END start_limit[5]
  PIN start_limit[6]
    DIRECTION INPUT ;
    USE SIGNAL ;
    PORT
      LAYER M4 ;
        RECT  0 54.768 0.084 54.792 ;
    END
  END start_limit[6]
  PIN start_limit[7]
    DIRECTION INPUT ;
    USE SIGNAL ;
    PORT
      LAYER M4 ;
        RECT  0 54.864 0.084 54.888 ;
    END
  END start_limit[7]
  PIN start_limit[8]
    DIRECTION INPUT ;
    USE SIGNAL ;
    PORT
      LAYER M4 ;
        RECT  0 54.96 0.084 54.984 ;
    END
  END start_limit[8]
  PIN start_limit[9]
    DIRECTION INPUT ;
    USE SIGNAL ;
    PORT
      LAYER M4 ;
        RECT  0 44.016 0.084 44.04 ;
    END
  END start_limit[9]
  PIN start_loops[0]
    DIRECTION INPUT ;
    USE SIGNAL ;
    PORT
      LAYER M4 ;
        RECT  0 44.208 0.084 44.232 ;
    END
  END start_loops[0]
  PIN start_loops[10]
    DIRECTION INPUT ;
    USE SIGNAL ;
    PORT
      LAYER M4 ;
        RECT  0 45.168 0.084 45.192 ;
    END
  END start_loops[10]
  PIN start_loops[11]
    DIRECTION INPUT ;
    USE SIGNAL ;
    PORT
      LAYER M4 ;
        RECT  0 45.264 0.084 45.288 ;
    END
  END start_loops[11]
  PIN start_loops[12]
    DIRECTION INPUT ;
    USE SIGNAL ;
    PORT
      LAYER M4 ;
        RECT  0 45.36 0.084 45.384 ;
    END
  END start_loops[12]
  PIN start_loops[13]
    DIRECTION INPUT ;
    USE SIGNAL ;
    PORT
      LAYER M4 ;
        RECT  0 45.456 0.084 45.48 ;
    END
  END start_loops[13]
  PIN start_loops[14]
    DIRECTION INPUT ;
    USE SIGNAL ;
    PORT
      LAYER M4 ;
        RECT  0 45.552 0.084 45.576 ;
    END
  END start_loops[14]
  PIN start_loops[15]
    DIRECTION INPUT ;
    USE SIGNAL ;
    PORT
      LAYER M4 ;
        RECT  0 45.648 0.084 45.672 ;
    END
  END start_loops[15]
  PIN start_loops[1]
    DIRECTION INPUT ;
    USE SIGNAL ;
    PORT
      LAYER M4 ;
        RECT  0 44.304 0.084 44.328 ;
    END
  END start_loops[1]
  PIN start_loops[2]
    DIRECTION INPUT ;
    USE SIGNAL ;
    PORT
      LAYER M4 ;
        RECT  0 44.4 0.084 44.424 ;
    END
  END start_loops[2]
  PIN start_loops[3]
    DIRECTION INPUT ;
    USE SIGNAL ;
    PORT
      LAYER M4 ;
        RECT  0 44.496 0.084 44.52 ;
    END
  END start_loops[3]
  PIN start_loops[4]
    DIRECTION INPUT ;
    USE SIGNAL ;
    PORT
      LAYER M4 ;
        RECT  0 44.592 0.084 44.616 ;
    END
  END start_loops[4]
  PIN start_loops[5]
    DIRECTION INPUT ;
    USE SIGNAL ;
    PORT
      LAYER M4 ;
        RECT  0 44.688 0.084 44.712 ;
    END
  END start_loops[5]
  PIN start_loops[6]
    DIRECTION INPUT ;
    USE SIGNAL ;
    PORT
      LAYER M4 ;
        RECT  0 44.784 0.084 44.808 ;
    END
  END start_loops[6]
  PIN start_loops[7]
    DIRECTION INPUT ;
    USE SIGNAL ;
    PORT
      LAYER M4 ;
        RECT  0 44.88 0.084 44.904 ;
    END
  END start_loops[7]
  PIN start_loops[8]
    DIRECTION INPUT ;
    USE SIGNAL ;
    PORT
      LAYER M4 ;
        RECT  0 44.976 0.084 45 ;
    END
  END start_loops[8]
  PIN start_loops[9]
    DIRECTION INPUT ;
    USE SIGNAL ;
    PORT
      LAYER M4 ;
        RECT  0 45.072 0.084 45.096 ;
    END
  END start_loops[9]
  PIN start_v
    DIRECTION INPUT ;
    USE SIGNAL ;
    PORT
      LAYER M4 ;
        RECT  0 45.744 0.084 45.768 ;
    END
  END start_v
  PIN wslot[0]
    DIRECTION OUTPUT ;
    USE SIGNAL ;
    PORT
      LAYER M4 ;
        RECT  220.236 71.568 220.32 71.592 ;
    END
  END wslot[0]
  PIN wslot[10]
    DIRECTION OUTPUT ;
    USE SIGNAL ;
    PORT
      LAYER M4 ;
        RECT  220.236 72.528 220.32 72.552 ;
    END
  END wslot[10]
  PIN wslot[11]
    DIRECTION OUTPUT ;
    USE SIGNAL ;
    PORT
      LAYER M4 ;
        RECT  220.236 72.624 220.32 72.648 ;
    END
  END wslot[11]
  PIN wslot[12]
    DIRECTION OUTPUT ;
    USE SIGNAL ;
    PORT
      LAYER M4 ;
        RECT  220.236 72.72 220.32 72.744 ;
    END
  END wslot[12]
  PIN wslot[13]
    DIRECTION OUTPUT ;
    USE SIGNAL ;
    PORT
      LAYER M4 ;
        RECT  220.236 72.816 220.32 72.84 ;
    END
  END wslot[13]
  PIN wslot[14]
    DIRECTION OUTPUT ;
    USE SIGNAL ;
    PORT
      LAYER M4 ;
        RECT  220.236 72.912 220.32 72.936 ;
    END
  END wslot[14]
  PIN wslot[15]
    DIRECTION OUTPUT ;
    USE SIGNAL ;
    PORT
      LAYER M4 ;
        RECT  220.236 73.008 220.32 73.032 ;
    END
  END wslot[15]
  PIN wslot[16]
    DIRECTION OUTPUT ;
    USE SIGNAL ;
    PORT
      LAYER M4 ;
        RECT  220.236 73.104 220.32 73.128 ;
    END
  END wslot[16]
  PIN wslot[17]
    DIRECTION OUTPUT ;
    USE SIGNAL ;
    PORT
      LAYER M4 ;
        RECT  220.236 73.2 220.32 73.224 ;
    END
  END wslot[17]
  PIN wslot[18]
    DIRECTION OUTPUT ;
    USE SIGNAL ;
    PORT
      LAYER M4 ;
        RECT  220.236 73.296 220.32 73.32 ;
    END
  END wslot[18]
  PIN wslot[19]
    DIRECTION OUTPUT ;
    USE SIGNAL ;
    PORT
      LAYER M4 ;
        RECT  220.236 73.392 220.32 73.416 ;
    END
  END wslot[19]
  PIN wslot[1]
    DIRECTION OUTPUT ;
    USE SIGNAL ;
    PORT
      LAYER M4 ;
        RECT  220.236 71.664 220.32 71.688 ;
    END
  END wslot[1]
  PIN wslot[20]
    DIRECTION OUTPUT ;
    USE SIGNAL ;
    PORT
      LAYER M4 ;
        RECT  220.236 73.488 220.32 73.512 ;
    END
  END wslot[20]
  PIN wslot[21]
    DIRECTION OUTPUT ;
    USE SIGNAL ;
    PORT
      LAYER M4 ;
        RECT  220.236 73.584 220.32 73.608 ;
    END
  END wslot[21]
  PIN wslot[22]
    DIRECTION OUTPUT ;
    USE SIGNAL ;
    PORT
      LAYER M4 ;
        RECT  220.236 57.36 220.32 57.384 ;
    END
  END wslot[22]
  PIN wslot[23]
    DIRECTION OUTPUT ;
    USE SIGNAL ;
    PORT
      LAYER M4 ;
        RECT  220.236 57.456 220.32 57.48 ;
    END
  END wslot[23]
  PIN wslot[2]
    DIRECTION OUTPUT ;
    USE SIGNAL ;
    PORT
      LAYER M4 ;
        RECT  220.236 71.76 220.32 71.784 ;
    END
  END wslot[2]
  PIN wslot[3]
    DIRECTION OUTPUT ;
    USE SIGNAL ;
    PORT
      LAYER M4 ;
        RECT  220.236 71.856 220.32 71.88 ;
    END
  END wslot[3]
  PIN wslot[4]
    DIRECTION OUTPUT ;
    USE SIGNAL ;
    PORT
      LAYER M4 ;
        RECT  220.236 71.952 220.32 71.976 ;
    END
  END wslot[4]
  PIN wslot[5]
    DIRECTION OUTPUT ;
    USE SIGNAL ;
    PORT
      LAYER M4 ;
        RECT  220.236 72.048 220.32 72.072 ;
    END
  END wslot[5]
  PIN wslot[6]
    DIRECTION OUTPUT ;
    USE SIGNAL ;
    PORT
      LAYER M4 ;
        RECT  220.236 72.144 220.32 72.168 ;
    END
  END wslot[6]
  PIN wslot[7]
    DIRECTION OUTPUT ;
    USE SIGNAL ;
    PORT
      LAYER M4 ;
        RECT  220.236 72.24 220.32 72.264 ;
    END
  END wslot[7]
  PIN wslot[8]
    DIRECTION OUTPUT ;
    USE SIGNAL ;
    PORT
      LAYER M4 ;
        RECT  220.236 72.336 220.32 72.36 ;
    END
  END wslot[8]
  PIN wslot[9]
    DIRECTION OUTPUT ;
    USE SIGNAL ;
    PORT
      LAYER M4 ;
        RECT  220.236 72.432 220.32 72.456 ;
    END
  END wslot[9]
  PIN wslot_v[0]
    DIRECTION OUTPUT ;
    USE SIGNAL ;
    PORT
      LAYER M4 ;
        RECT  220.236 57.552 220.32 57.576 ;
    END
  END wslot_v[0]
  PIN wslot_v[1]
    DIRECTION OUTPUT ;
    USE SIGNAL ;
    PORT
      LAYER M4 ;
        RECT  220.236 57.648 220.32 57.672 ;
    END
  END wslot_v[1]
  PIN wslot_v[2]
    DIRECTION OUTPUT ;
    USE SIGNAL ;
    PORT
      LAYER M4 ;
        RECT  220.236 57.744 220.32 57.768 ;
    END
  END wslot_v[2]
  PIN wslot_v[3]
    DIRECTION OUTPUT ;
    USE SIGNAL ;
    PORT
      LAYER M4 ;
        RECT  220.236 57.84 220.32 57.864 ;
    END
  END wslot_v[3]
  PIN wslot_v[4]
    DIRECTION OUTPUT ;
    USE SIGNAL ;
    PORT
      LAYER M4 ;
        RECT  220.236 57.936 220.32 57.96 ;
    END
  END wslot_v[4]
  PIN wslot_v[5]
    DIRECTION OUTPUT ;
    USE SIGNAL ;
    PORT
      LAYER M4 ;
        RECT  220.236 58.032 220.32 58.056 ;
    END
  END wslot_v[5]
  PIN wslot_v[6]
    DIRECTION OUTPUT ;
    USE SIGNAL ;
    PORT
      LAYER M4 ;
        RECT  220.236 58.128 220.32 58.152 ;
    END
  END wslot_v[6]
  PIN wslot_v[7]
    DIRECTION OUTPUT ;
    USE SIGNAL ;
    PORT
      LAYER M4 ;
        RECT  220.236 58.224 220.32 58.248 ;
    END
  END wslot_v[7]
  PIN VDD
    DIRECTION INOUT ;
    USE POWER ;
    PORT
      LAYER M5 ;
        RECT  213.192 2.151 213.312 174.969 ;
        RECT  207.792 2.151 207.912 174.969 ;
        RECT  202.392 2.151 202.512 174.969 ;
        RECT  196.992 2.151 197.112 174.969 ;
        RECT  191.592 2.151 191.712 174.969 ;
        RECT  186.192 2.151 186.312 174.969 ;
        RECT  180.792 2.151 180.912 174.969 ;
        RECT  175.392 2.151 175.512 174.969 ;
        RECT  169.992 2.151 170.112 174.969 ;
        RECT  164.592 2.151 164.712 174.969 ;
        RECT  159.192 2.151 159.312 174.969 ;
        RECT  153.792 2.151 153.912 174.969 ;
        RECT  148.392 2.151 148.512 174.969 ;
        RECT  142.992 2.151 143.112 174.969 ;
        RECT  137.592 2.151 137.712 174.969 ;
        RECT  132.192 2.151 132.312 174.969 ;
        RECT  126.792 2.151 126.912 174.969 ;
        RECT  121.392 2.151 121.512 174.969 ;
        RECT  115.992 2.151 116.112 174.969 ;
        RECT  110.592 2.151 110.712 174.969 ;
        RECT  105.192 2.151 105.312 174.969 ;
        RECT  99.792 2.151 99.912 174.969 ;
        RECT  94.392 2.151 94.512 174.969 ;
        RECT  88.992 2.151 89.112 174.969 ;
        RECT  83.592 2.151 83.712 174.969 ;
        RECT  78.192 2.151 78.312 174.969 ;
        RECT  72.792 2.151 72.912 174.969 ;
        RECT  67.392 2.151 67.512 174.969 ;
        RECT  61.992 2.151 62.112 174.969 ;
        RECT  56.592 2.151 56.712 174.969 ;
        RECT  51.192 2.151 51.312 174.969 ;
        RECT  45.792 2.151 45.912 174.969 ;
        RECT  40.392 2.151 40.512 174.969 ;
        RECT  34.992 2.151 35.112 174.969 ;
        RECT  29.592 2.151 29.712 174.969 ;
        RECT  24.192 2.151 24.312 174.969 ;
        RECT  18.792 2.151 18.912 174.969 ;
        RECT  13.392 2.151 13.512 174.969 ;
        RECT  7.992 2.151 8.112 174.969 ;
        RECT  2.592 2.151 2.712 174.969 ;
    END
  END VDD
  PIN VSS
    DIRECTION INOUT ;
    USE GROUND ;
    PORT
      LAYER M5 ;
        RECT  213 2.137 213.12 174.983 ;
        RECT  207.6 2.137 207.72 174.983 ;
        RECT  202.2 2.137 202.32 174.983 ;
        RECT  196.8 2.137 196.92 174.983 ;
        RECT  191.4 2.137 191.52 174.983 ;
        RECT  186 2.137 186.12 174.983 ;
        RECT  180.6 2.137 180.72 174.983 ;
        RECT  175.2 2.137 175.32 174.983 ;
        RECT  169.8 2.137 169.92 174.983 ;
        RECT  164.4 2.137 164.52 174.983 ;
        RECT  159 2.137 159.12 174.983 ;
        RECT  153.6 2.137 153.72 174.983 ;
        RECT  148.2 2.137 148.32 174.983 ;
        RECT  142.8 2.137 142.92 174.983 ;
        RECT  137.4 2.137 137.52 174.983 ;
        RECT  132 2.137 132.12 174.983 ;
        RECT  126.6 2.137 126.72 174.983 ;
        RECT  121.2 2.137 121.32 174.983 ;
        RECT  115.8 2.137 115.92 174.983 ;
        RECT  110.4 2.137 110.52 174.983 ;
        RECT  105 2.137 105.12 174.983 ;
        RECT  99.6 2.137 99.72 174.983 ;
        RECT  94.2 2.137 94.32 174.983 ;
        RECT  88.8 2.137 88.92 174.983 ;
        RECT  83.4 2.137 83.52 174.983 ;
        RECT  78 2.137 78.12 174.983 ;
        RECT  72.6 2.137 72.72 174.983 ;
        RECT  67.2 2.137 67.32 174.983 ;
        RECT  61.8 2.137 61.92 174.983 ;
        RECT  56.4 2.137 56.52 174.983 ;
        RECT  51 2.137 51.12 174.983 ;
        RECT  45.6 2.137 45.72 174.983 ;
        RECT  40.2 2.137 40.32 174.983 ;
        RECT  34.8 2.137 34.92 174.983 ;
        RECT  29.4 2.137 29.52 174.983 ;
        RECT  24 2.137 24.12 174.983 ;
        RECT  18.6 2.137 18.72 174.983 ;
        RECT  13.2 2.137 13.32 174.983 ;
        RECT  7.8 2.137 7.92 174.983 ;
        RECT  2.4 2.137 2.52 174.983 ;
    END
  END VSS
  # OT_OBS_CLOSED layer=M5 d_um=1.536 added=178
  OBS
    LAYER RVTN ;
     RECT  2.16 2.16 218.16 2.295 ;
     RECT  2.16 2.565 218.16 2.835 ;
     RECT  2.16 3.105 218.16 3.375 ;
     RECT  2.16 3.645 218.16 3.915 ;
     RECT  2.16 4.185 218.16 4.455 ;
     RECT  2.16 4.725 218.16 4.995 ;
     RECT  2.16 5.265 218.16 5.535 ;
     RECT  2.16 5.805 218.16 6.075 ;
     RECT  2.16 6.345 218.16 6.615 ;
     RECT  2.16 6.885 218.16 7.155 ;
     RECT  2.16 7.425 218.16 7.695 ;
     RECT  2.16 7.965 218.16 8.235 ;
     RECT  2.16 8.505 218.16 8.775 ;
     RECT  2.16 9.045 218.16 9.315 ;
     RECT  2.16 9.585 218.16 9.855 ;
     RECT  2.16 10.125 218.16 10.395 ;
     RECT  2.16 10.665 218.16 10.935 ;
     RECT  2.16 11.205 218.16 11.475 ;
     RECT  2.16 11.745 218.16 12.015 ;
     RECT  2.16 12.285 218.16 12.555 ;
     RECT  2.16 12.825 218.16 13.095 ;
     RECT  2.16 13.365 218.16 13.635 ;
     RECT  2.16 13.905 218.16 14.175 ;
     RECT  2.16 14.445 218.16 14.715 ;
     RECT  2.16 14.985 218.16 15.255 ;
     RECT  2.16 15.525 218.16 15.795 ;
     RECT  2.16 16.065 218.16 16.335 ;
     RECT  2.16 16.605 218.16 16.875 ;
     RECT  2.16 17.145 218.16 17.415 ;
     RECT  2.16 17.685 218.16 17.955 ;
     RECT  2.16 18.225 218.16 18.495 ;
     RECT  2.16 18.765 218.16 19.035 ;
     RECT  2.16 19.305 218.16 19.575 ;
     RECT  2.16 19.845 218.16 20.115 ;
     RECT  2.16 20.385 218.16 20.655 ;
     RECT  2.16 20.925 218.16 21.195 ;
     RECT  2.16 21.465 218.16 21.735 ;
     RECT  2.16 22.005 218.16 22.275 ;
     RECT  2.16 22.545 218.16 22.815 ;
     RECT  2.16 23.085 218.16 23.355 ;
     RECT  2.16 23.625 218.16 23.895 ;
     RECT  2.16 24.165 218.16 24.435 ;
     RECT  2.16 24.705 218.16 24.975 ;
     RECT  2.16 25.245 218.16 25.515 ;
     RECT  2.16 25.785 218.16 26.055 ;
     RECT  2.16 26.325 218.16 26.595 ;
     RECT  2.16 26.865 218.16 27.135 ;
     RECT  2.16 27.405 218.16 27.675 ;
     RECT  2.16 27.945 218.16 28.215 ;
     RECT  2.16 28.485 218.16 28.755 ;
     RECT  2.16 29.025 218.16 29.295 ;
     RECT  2.16 29.565 218.16 29.835 ;
     RECT  2.16 30.105 218.16 30.375 ;
     RECT  2.16 30.645 218.16 30.915 ;
     RECT  2.16 31.185 218.16 31.455 ;
     RECT  2.16 31.725 218.16 31.995 ;
     RECT  2.16 32.265 218.16 32.535 ;
     RECT  2.16 32.805 218.16 33.075 ;
     RECT  2.16 33.345 218.16 33.615 ;
     RECT  2.16 33.885 218.16 34.155 ;
     RECT  2.16 34.425 218.16 34.695 ;
     RECT  2.16 34.965 218.16 35.235 ;
     RECT  2.16 35.505 218.16 35.775 ;
     RECT  2.16 36.045 218.16 36.315 ;
     RECT  2.16 36.585 218.16 36.855 ;
     RECT  2.16 37.125 218.16 37.395 ;
     RECT  2.16 37.665 218.16 37.935 ;
     RECT  2.16 38.205 218.16 38.475 ;
     RECT  2.16 38.745 218.16 39.015 ;
     RECT  2.16 39.285 218.16 39.555 ;
     RECT  2.16 39.825 218.16 40.095 ;
     RECT  2.16 40.365 218.16 40.635 ;
     RECT  2.16 40.905 218.16 41.175 ;
     RECT  2.16 41.445 218.16 41.715 ;
     RECT  2.16 41.985 218.16 42.255 ;
     RECT  2.16 42.525 218.16 42.795 ;
     RECT  2.16 43.065 218.16 43.335 ;
     RECT  2.16 43.605 218.16 43.875 ;
     RECT  2.16 44.145 218.16 44.415 ;
     RECT  2.16 44.685 218.16 44.955 ;
     RECT  2.16 45.225 218.16 45.495 ;
     RECT  2.16 45.765 218.16 46.035 ;
     RECT  2.16 46.305 218.16 46.575 ;
     RECT  2.16 46.845 218.16 47.115 ;
     RECT  2.16 47.385 218.16 47.655 ;
     RECT  2.16 47.925 218.16 48.195 ;
     RECT  2.16 48.465 218.16 48.735 ;
     RECT  2.16 49.005 218.16 49.275 ;
     RECT  2.16 49.545 218.16 49.815 ;
     RECT  2.16 50.085 218.16 50.355 ;
     RECT  2.16 50.625 218.16 50.895 ;
     RECT  2.16 51.165 218.16 51.435 ;
     RECT  2.16 51.705 218.16 51.84 ;
     RECT  2.16 51.84 20.844 51.975 ;
     RECT  199.692 51.84 218.16 51.975 ;
     RECT  2.16 52.245 20.844 52.515 ;
     RECT  199.692 52.245 218.16 52.515 ;
     RECT  2.16 52.785 20.844 53.055 ;
     RECT  199.692 52.785 218.16 53.055 ;
     RECT  2.16 53.325 20.844 53.595 ;
     RECT  199.692 53.325 218.16 53.595 ;
     RECT  2.16 53.865 20.844 54.135 ;
     RECT  199.692 53.865 218.16 54.135 ;
     RECT  2.16 54.405 20.844 54.675 ;
     RECT  199.692 54.405 218.16 54.675 ;
     RECT  2.16 54.945 20.844 55.215 ;
     RECT  199.692 54.945 218.16 55.215 ;
     RECT  2.16 55.485 20.844 55.755 ;
     RECT  199.692 55.485 218.16 55.755 ;
     RECT  2.16 56.025 20.844 56.295 ;
     RECT  199.692 56.025 218.16 56.295 ;
     RECT  2.16 56.565 20.844 56.835 ;
     RECT  199.692 56.565 218.16 56.835 ;
     RECT  2.16 57.105 20.844 57.375 ;
     RECT  199.692 57.105 218.16 57.375 ;
     RECT  2.16 57.645 20.844 57.915 ;
     RECT  199.692 57.645 218.16 57.915 ;
     RECT  2.16 58.185 20.844 58.455 ;
     RECT  199.692 58.185 218.16 58.455 ;
     RECT  2.16 58.725 20.844 58.995 ;
     RECT  199.692 58.725 218.16 58.995 ;
     RECT  2.16 59.265 20.844 59.535 ;
     RECT  199.692 59.265 218.16 59.535 ;
     RECT  2.16 59.805 20.844 60.075 ;
     RECT  199.692 59.805 218.16 60.075 ;
     RECT  2.16 60.345 20.844 60.615 ;
     RECT  199.692 60.345 218.16 60.615 ;
     RECT  2.16 60.885 20.844 61.155 ;
     RECT  199.692 60.885 218.16 61.155 ;
     RECT  2.16 61.425 20.844 61.695 ;
     RECT  199.692 61.425 218.16 61.695 ;
     RECT  2.16 61.965 20.844 62.235 ;
     RECT  199.692 61.965 218.16 62.235 ;
     RECT  2.16 62.505 20.844 62.775 ;
     RECT  199.692 62.505 218.16 62.775 ;
     RECT  2.16 63.045 20.844 63.315 ;
     RECT  199.692 63.045 218.16 63.315 ;
     RECT  2.16 63.585 20.844 63.855 ;
     RECT  199.692 63.585 218.16 63.855 ;
     RECT  2.16 64.125 20.844 64.395 ;
     RECT  199.692 64.125 218.16 64.395 ;
     RECT  2.16 64.665 20.844 64.935 ;
     RECT  199.692 64.665 218.16 64.935 ;
     RECT  2.16 65.205 20.844 65.475 ;
     RECT  199.692 65.205 218.16 65.475 ;
     RECT  2.16 65.745 20.844 66.015 ;
     RECT  199.692 65.745 218.16 66.015 ;
     RECT  2.16 66.285 20.844 66.555 ;
     RECT  199.692 66.285 218.16 66.555 ;
     RECT  2.16 66.825 20.844 67.095 ;
     RECT  199.692 66.825 218.16 67.095 ;
     RECT  2.16 67.365 20.844 67.635 ;
     RECT  199.692 67.365 218.16 67.635 ;
     RECT  2.16 67.905 20.844 68.175 ;
     RECT  199.692 67.905 218.16 68.175 ;
     RECT  2.16 68.445 20.844 68.715 ;
     RECT  199.692 68.445 218.16 68.715 ;
     RECT  2.16 68.985 20.844 69.255 ;
     RECT  199.692 68.985 218.16 69.255 ;
     RECT  2.16 69.525 20.844 69.795 ;
     RECT  199.692 69.525 218.16 69.795 ;
     RECT  2.16 70.065 20.844 70.335 ;
     RECT  199.692 70.065 218.16 70.335 ;
     RECT  2.16 70.605 20.844 70.875 ;
     RECT  199.692 70.605 218.16 70.875 ;
     RECT  2.16 71.145 20.844 71.415 ;
     RECT  199.692 71.145 218.16 71.415 ;
     RECT  2.16 71.685 20.844 71.955 ;
     RECT  199.692 71.685 218.16 71.955 ;
     RECT  2.16 72.225 20.844 72.495 ;
     RECT  199.692 72.225 218.16 72.495 ;
     RECT  2.16 72.765 20.844 73.035 ;
     RECT  199.692 72.765 218.16 73.035 ;
     RECT  2.16 73.305 20.844 73.575 ;
     RECT  199.692 73.305 218.16 73.575 ;
     RECT  2.16 73.845 20.844 74.115 ;
     RECT  199.692 73.845 218.16 74.115 ;
     RECT  2.16 74.385 20.844 74.655 ;
     RECT  199.692 74.385 218.16 74.655 ;
     RECT  2.16 74.925 20.844 75.195 ;
     RECT  199.692 74.925 218.16 75.195 ;
     RECT  2.16 75.465 20.844 75.735 ;
     RECT  199.692 75.465 218.16 75.735 ;
     RECT  2.16 76.005 20.844 76.275 ;
     RECT  199.692 76.005 218.16 76.275 ;
     RECT  2.16 76.545 20.844 76.815 ;
     RECT  199.692 76.545 218.16 76.815 ;
     RECT  2.16 77.085 20.844 77.355 ;
     RECT  199.692 77.085 218.16 77.355 ;
     RECT  2.16 77.625 20.844 77.895 ;
     RECT  199.692 77.625 218.16 77.895 ;
     RECT  2.16 78.165 20.844 78.435 ;
     RECT  199.692 78.165 218.16 78.435 ;
     RECT  2.16 78.705 20.844 78.975 ;
     RECT  199.692 78.705 218.16 78.975 ;
     RECT  2.16 79.245 20.844 79.515 ;
     RECT  199.692 79.245 218.16 79.515 ;
     RECT  2.16 79.785 20.844 80.055 ;
     RECT  199.692 79.785 218.16 80.055 ;
     RECT  2.16 80.325 20.844 80.595 ;
     RECT  199.692 80.325 218.16 80.595 ;
     RECT  2.16 80.865 20.844 81.135 ;
     RECT  199.692 80.865 218.16 81.135 ;
     RECT  2.16 81.405 20.844 81.675 ;
     RECT  199.692 81.405 218.16 81.675 ;
     RECT  2.16 81.945 20.844 82.215 ;
     RECT  199.692 81.945 218.16 82.215 ;
     RECT  2.16 82.485 20.844 82.755 ;
     RECT  199.692 82.485 218.16 82.755 ;
     RECT  2.16 83.025 20.844 83.295 ;
     RECT  199.692 83.025 218.16 83.295 ;
     RECT  2.16 83.565 20.844 83.835 ;
     RECT  199.692 83.565 218.16 83.835 ;
     RECT  2.16 84.105 20.844 84.375 ;
     RECT  199.692 84.105 218.16 84.375 ;
     RECT  2.16 84.645 20.844 84.915 ;
     RECT  199.692 84.645 218.16 84.915 ;
     RECT  2.16 85.185 20.844 85.455 ;
     RECT  199.692 85.185 218.16 85.455 ;
     RECT  2.16 85.725 20.844 85.995 ;
     RECT  199.692 85.725 218.16 85.995 ;
     RECT  2.16 86.265 20.844 86.535 ;
     RECT  199.692 86.265 218.16 86.535 ;
     RECT  2.16 86.805 20.844 87.075 ;
     RECT  199.692 86.805 218.16 87.075 ;
     RECT  2.16 87.345 20.844 87.615 ;
     RECT  199.692 87.345 218.16 87.615 ;
     RECT  2.16 87.885 20.844 88.155 ;
     RECT  199.692 87.885 218.16 88.155 ;
     RECT  2.16 88.425 20.844 88.695 ;
     RECT  199.692 88.425 218.16 88.695 ;
     RECT  2.16 88.965 20.844 89.235 ;
     RECT  199.692 88.965 218.16 89.235 ;
     RECT  2.16 89.505 20.844 89.775 ;
     RECT  199.692 89.505 218.16 89.775 ;
     RECT  2.16 90.045 20.844 90.315 ;
     RECT  199.692 90.045 218.16 90.315 ;
     RECT  2.16 90.585 20.844 90.855 ;
     RECT  199.692 90.585 218.16 90.855 ;
     RECT  2.16 91.125 20.844 91.395 ;
     RECT  199.692 91.125 218.16 91.395 ;
     RECT  2.16 91.665 20.844 91.935 ;
     RECT  199.692 91.665 218.16 91.935 ;
     RECT  2.16 92.205 20.844 92.475 ;
     RECT  199.692 92.205 218.16 92.475 ;
     RECT  2.16 92.745 20.844 93.015 ;
     RECT  199.692 92.745 218.16 93.015 ;
     RECT  2.16 93.285 20.844 93.555 ;
     RECT  199.692 93.285 218.16 93.555 ;
     RECT  2.16 93.825 20.844 94.095 ;
     RECT  199.692 93.825 218.16 94.095 ;
     RECT  2.16 94.365 20.844 94.635 ;
     RECT  199.692 94.365 218.16 94.635 ;
     RECT  2.16 94.905 20.844 95.175 ;
     RECT  199.692 94.905 218.16 95.175 ;
     RECT  2.16 95.445 20.844 95.715 ;
     RECT  199.692 95.445 218.16 95.715 ;
     RECT  2.16 95.985 20.844 96.255 ;
     RECT  199.692 95.985 218.16 96.255 ;
     RECT  2.16 96.525 20.844 96.795 ;
     RECT  199.692 96.525 218.16 96.795 ;
     RECT  2.16 97.065 20.844 97.335 ;
     RECT  199.692 97.065 218.16 97.335 ;
     RECT  2.16 97.605 20.844 97.875 ;
     RECT  199.692 97.605 218.16 97.875 ;
     RECT  2.16 98.145 20.844 98.415 ;
     RECT  199.692 98.145 218.16 98.415 ;
     RECT  2.16 98.685 20.844 98.955 ;
     RECT  199.692 98.685 218.16 98.955 ;
     RECT  2.16 99.225 20.844 99.495 ;
     RECT  199.692 99.225 218.16 99.495 ;
     RECT  2.16 99.765 20.844 100.035 ;
     RECT  199.692 99.765 218.16 100.035 ;
     RECT  2.16 100.305 20.844 100.575 ;
     RECT  199.692 100.305 218.16 100.575 ;
     RECT  2.16 100.845 20.844 101.115 ;
     RECT  199.692 100.845 218.16 101.115 ;
     RECT  2.16 101.385 20.844 101.655 ;
     RECT  199.692 101.385 218.16 101.655 ;
     RECT  2.16 101.925 20.844 102.195 ;
     RECT  199.692 101.925 218.16 102.195 ;
     RECT  2.16 102.465 20.844 102.735 ;
     RECT  199.692 102.465 218.16 102.735 ;
     RECT  2.16 103.005 20.844 103.275 ;
     RECT  199.692 103.005 218.16 103.275 ;
     RECT  2.16 103.545 20.844 103.815 ;
     RECT  199.692 103.545 218.16 103.815 ;
     RECT  2.16 104.085 20.844 104.355 ;
     RECT  199.692 104.085 218.16 104.355 ;
     RECT  2.16 104.625 20.844 104.895 ;
     RECT  199.692 104.625 218.16 104.895 ;
     RECT  2.16 105.165 20.844 105.435 ;
     RECT  199.692 105.165 218.16 105.435 ;
     RECT  2.16 105.705 20.844 105.975 ;
     RECT  199.692 105.705 218.16 105.975 ;
     RECT  2.16 106.245 20.844 106.515 ;
     RECT  199.692 106.245 218.16 106.515 ;
     RECT  2.16 106.785 20.844 107.055 ;
     RECT  199.692 106.785 218.16 107.055 ;
     RECT  2.16 107.325 20.844 107.595 ;
     RECT  199.692 107.325 218.16 107.595 ;
     RECT  2.16 107.865 20.844 108.135 ;
     RECT  199.692 107.865 218.16 108.135 ;
     RECT  2.16 108.405 20.844 108.675 ;
     RECT  199.692 108.405 218.16 108.675 ;
     RECT  2.16 108.945 20.844 109.215 ;
     RECT  199.692 108.945 218.16 109.215 ;
     RECT  2.16 109.485 20.844 109.755 ;
     RECT  199.692 109.485 218.16 109.755 ;
     RECT  2.16 110.025 20.844 110.295 ;
     RECT  199.692 110.025 218.16 110.295 ;
     RECT  2.16 110.565 20.844 110.835 ;
     RECT  199.692 110.565 218.16 110.835 ;
     RECT  2.16 111.105 20.844 111.375 ;
     RECT  199.692 111.105 218.16 111.375 ;
     RECT  2.16 111.645 20.844 111.915 ;
     RECT  199.692 111.645 218.16 111.915 ;
     RECT  2.16 112.185 20.844 112.455 ;
     RECT  199.692 112.185 218.16 112.455 ;
     RECT  2.16 112.725 20.844 112.995 ;
     RECT  199.692 112.725 218.16 112.995 ;
     RECT  2.16 113.265 20.844 113.535 ;
     RECT  199.692 113.265 218.16 113.535 ;
     RECT  2.16 113.805 20.844 114.075 ;
     RECT  199.692 113.805 218.16 114.075 ;
     RECT  2.16 114.345 20.844 114.615 ;
     RECT  199.692 114.345 218.16 114.615 ;
     RECT  2.16 114.885 20.844 115.155 ;
     RECT  199.692 114.885 218.16 115.155 ;
     RECT  2.16 115.425 20.844 115.695 ;
     RECT  199.692 115.425 218.16 115.695 ;
     RECT  2.16 115.965 20.844 116.235 ;
     RECT  199.692 115.965 218.16 116.235 ;
     RECT  2.16 116.505 20.844 116.775 ;
     RECT  199.692 116.505 218.16 116.775 ;
     RECT  2.16 117.045 20.844 117.315 ;
     RECT  199.692 117.045 218.16 117.315 ;
     RECT  2.16 117.585 20.844 117.855 ;
     RECT  199.692 117.585 218.16 117.855 ;
     RECT  2.16 118.125 20.844 118.395 ;
     RECT  199.692 118.125 218.16 118.395 ;
     RECT  2.16 118.665 20.844 118.935 ;
     RECT  199.692 118.665 218.16 118.935 ;
     RECT  2.16 119.205 20.844 119.475 ;
     RECT  199.692 119.205 218.16 119.475 ;
     RECT  2.16 119.745 20.844 120.015 ;
     RECT  199.692 119.745 218.16 120.015 ;
     RECT  2.16 120.285 20.844 120.555 ;
     RECT  199.692 120.285 218.16 120.555 ;
     RECT  2.16 120.825 20.844 121.095 ;
     RECT  199.692 120.825 218.16 121.095 ;
     RECT  2.16 121.365 20.844 121.635 ;
     RECT  199.692 121.365 218.16 121.635 ;
     RECT  2.16 121.905 20.844 122.175 ;
     RECT  199.692 121.905 218.16 122.175 ;
     RECT  2.16 122.445 20.844 122.715 ;
     RECT  199.692 122.445 218.16 122.715 ;
     RECT  2.16 122.985 20.844 123.255 ;
     RECT  199.692 122.985 218.16 123.255 ;
     RECT  2.16 123.525 20.844 123.795 ;
     RECT  199.692 123.525 218.16 123.795 ;
     RECT  2.16 124.065 20.844 124.335 ;
     RECT  199.692 124.065 218.16 124.335 ;
     RECT  2.16 124.605 20.844 124.875 ;
     RECT  199.692 124.605 218.16 124.875 ;
     RECT  2.16 125.145 20.844 125.415 ;
     RECT  199.692 125.145 218.16 125.415 ;
     RECT  2.16 125.685 20.844 125.955 ;
     RECT  199.692 125.685 218.16 125.955 ;
     RECT  2.16 126.225 20.844 126.495 ;
     RECT  199.692 126.225 218.16 126.495 ;
     RECT  2.16 126.765 218.16 127.035 ;
     RECT  2.16 127.305 218.16 127.575 ;
     RECT  2.16 127.845 218.16 128.115 ;
     RECT  2.16 128.385 218.16 128.655 ;
     RECT  2.16 128.925 218.16 129.195 ;
     RECT  2.16 129.465 218.16 129.735 ;
     RECT  2.16 130.005 218.16 130.275 ;
     RECT  2.16 130.545 218.16 130.815 ;
     RECT  2.16 131.085 218.16 131.355 ;
     RECT  2.16 131.625 218.16 131.895 ;
     RECT  2.16 132.165 218.16 132.435 ;
     RECT  2.16 132.705 218.16 132.975 ;
     RECT  2.16 133.245 218.16 133.515 ;
     RECT  2.16 133.785 218.16 134.055 ;
     RECT  2.16 134.325 218.16 134.595 ;
     RECT  2.16 134.865 218.16 135.135 ;
     RECT  2.16 135.405 218.16 135.675 ;
     RECT  2.16 135.945 218.16 136.215 ;
     RECT  2.16 136.485 218.16 136.755 ;
     RECT  2.16 137.025 218.16 137.295 ;
     RECT  2.16 137.565 218.16 137.835 ;
     RECT  2.16 138.105 218.16 138.375 ;
     RECT  2.16 138.645 218.16 138.915 ;
     RECT  2.16 139.185 218.16 139.455 ;
     RECT  2.16 139.725 218.16 139.995 ;
     RECT  2.16 140.265 218.16 140.535 ;
     RECT  2.16 140.805 218.16 141.075 ;
     RECT  2.16 141.345 218.16 141.615 ;
     RECT  2.16 141.885 218.16 142.155 ;
     RECT  2.16 142.425 218.16 142.695 ;
     RECT  2.16 142.965 218.16 143.235 ;
     RECT  2.16 143.505 218.16 143.775 ;
     RECT  2.16 144.045 218.16 144.315 ;
     RECT  2.16 144.585 218.16 144.855 ;
     RECT  2.16 145.125 218.16 145.395 ;
     RECT  2.16 145.665 218.16 145.935 ;
     RECT  2.16 146.205 218.16 146.475 ;
     RECT  2.16 146.745 218.16 147.015 ;
     RECT  2.16 147.285 218.16 147.555 ;
     RECT  2.16 147.825 218.16 148.095 ;
     RECT  2.16 148.365 218.16 148.635 ;
     RECT  2.16 148.905 218.16 149.175 ;
     RECT  2.16 149.445 218.16 149.715 ;
     RECT  2.16 149.985 218.16 150.255 ;
     RECT  2.16 150.525 218.16 150.795 ;
     RECT  2.16 151.065 218.16 151.335 ;
     RECT  2.16 151.605 218.16 151.875 ;
     RECT  2.16 152.145 218.16 152.415 ;
     RECT  2.16 152.685 218.16 152.955 ;
     RECT  2.16 153.225 218.16 153.495 ;
     RECT  2.16 153.765 218.16 154.035 ;
     RECT  2.16 154.305 218.16 154.575 ;
     RECT  2.16 154.845 218.16 155.115 ;
     RECT  2.16 155.385 218.16 155.655 ;
     RECT  2.16 155.925 218.16 156.195 ;
     RECT  2.16 156.465 218.16 156.735 ;
     RECT  2.16 157.005 218.16 157.275 ;
     RECT  2.16 157.545 218.16 157.815 ;
     RECT  2.16 158.085 218.16 158.355 ;
     RECT  2.16 158.625 218.16 158.895 ;
     RECT  2.16 159.165 218.16 159.435 ;
     RECT  2.16 159.705 218.16 159.975 ;
     RECT  2.16 160.245 218.16 160.515 ;
     RECT  2.16 160.785 218.16 161.055 ;
     RECT  2.16 161.325 218.16 161.595 ;
     RECT  2.16 161.865 218.16 162.135 ;
     RECT  2.16 162.405 218.16 162.675 ;
     RECT  2.16 162.945 218.16 163.215 ;
     RECT  2.16 163.485 218.16 163.755 ;
     RECT  2.16 164.025 218.16 164.295 ;
     RECT  2.16 164.565 218.16 164.835 ;
     RECT  2.16 165.105 218.16 165.375 ;
     RECT  2.16 165.645 218.16 165.915 ;
     RECT  2.16 166.185 218.16 166.455 ;
     RECT  2.16 166.725 218.16 166.995 ;
     RECT  2.16 167.265 218.16 167.535 ;
     RECT  2.16 167.805 218.16 168.075 ;
     RECT  2.16 168.345 218.16 168.615 ;
     RECT  2.16 168.885 218.16 169.155 ;
     RECT  2.16 169.425 218.16 169.695 ;
     RECT  2.16 169.965 218.16 170.235 ;
     RECT  2.16 170.505 218.16 170.775 ;
     RECT  2.16 171.045 218.16 171.315 ;
     RECT  2.16 171.585 218.16 171.855 ;
     RECT  2.16 172.125 218.16 172.395 ;
     RECT  2.16 172.665 218.16 172.935 ;
     RECT  2.16 173.205 218.16 173.475 ;
     RECT  2.16 173.745 218.16 174.015 ;
     RECT  2.16 174.285 218.16 174.555 ;
     RECT  2.16 174.825 218.16 174.96 ;
    LAYER RVTP ;
     RECT  2.16 2.295 218.16 2.565 ;
     RECT  2.16 2.835 218.16 3.105 ;
     RECT  2.16 3.375 218.16 3.645 ;
     RECT  2.16 3.915 218.16 4.185 ;
     RECT  2.16 4.455 218.16 4.725 ;
     RECT  2.16 4.995 218.16 5.265 ;
     RECT  2.16 5.535 218.16 5.805 ;
     RECT  2.16 6.075 218.16 6.345 ;
     RECT  2.16 6.615 218.16 6.885 ;
     RECT  2.16 7.155 218.16 7.425 ;
     RECT  2.16 7.695 218.16 7.965 ;
     RECT  2.16 8.235 218.16 8.505 ;
     RECT  2.16 8.775 218.16 9.045 ;
     RECT  2.16 9.315 218.16 9.585 ;
     RECT  2.16 9.855 218.16 10.125 ;
     RECT  2.16 10.395 218.16 10.665 ;
     RECT  2.16 10.935 218.16 11.205 ;
     RECT  2.16 11.475 218.16 11.745 ;
     RECT  2.16 12.015 218.16 12.285 ;
     RECT  2.16 12.555 218.16 12.825 ;
     RECT  2.16 13.095 218.16 13.365 ;
     RECT  2.16 13.635 218.16 13.905 ;
     RECT  2.16 14.175 218.16 14.445 ;
     RECT  2.16 14.715 218.16 14.985 ;
     RECT  2.16 15.255 218.16 15.525 ;
     RECT  2.16 15.795 218.16 16.065 ;
     RECT  2.16 16.335 218.16 16.605 ;
     RECT  2.16 16.875 218.16 17.145 ;
     RECT  2.16 17.415 218.16 17.685 ;
     RECT  2.16 17.955 218.16 18.225 ;
     RECT  2.16 18.495 218.16 18.765 ;
     RECT  2.16 19.035 218.16 19.305 ;
     RECT  2.16 19.575 218.16 19.845 ;
     RECT  2.16 20.115 218.16 20.385 ;
     RECT  2.16 20.655 218.16 20.925 ;
     RECT  2.16 21.195 218.16 21.465 ;
     RECT  2.16 21.735 218.16 22.005 ;
     RECT  2.16 22.275 218.16 22.545 ;
     RECT  2.16 22.815 218.16 23.085 ;
     RECT  2.16 23.355 218.16 23.625 ;
     RECT  2.16 23.895 218.16 24.165 ;
     RECT  2.16 24.435 218.16 24.705 ;
     RECT  2.16 24.975 218.16 25.245 ;
     RECT  2.16 25.515 218.16 25.785 ;
     RECT  2.16 26.055 218.16 26.325 ;
     RECT  2.16 26.595 218.16 26.865 ;
     RECT  2.16 27.135 218.16 27.405 ;
     RECT  2.16 27.675 218.16 27.945 ;
     RECT  2.16 28.215 218.16 28.485 ;
     RECT  2.16 28.755 218.16 29.025 ;
     RECT  2.16 29.295 218.16 29.565 ;
     RECT  2.16 29.835 218.16 30.105 ;
     RECT  2.16 30.375 218.16 30.645 ;
     RECT  2.16 30.915 218.16 31.185 ;
     RECT  2.16 31.455 218.16 31.725 ;
     RECT  2.16 31.995 218.16 32.265 ;
     RECT  2.16 32.535 218.16 32.805 ;
     RECT  2.16 33.075 218.16 33.345 ;
     RECT  2.16 33.615 218.16 33.885 ;
     RECT  2.16 34.155 218.16 34.425 ;
     RECT  2.16 34.695 218.16 34.965 ;
     RECT  2.16 35.235 218.16 35.505 ;
     RECT  2.16 35.775 218.16 36.045 ;
     RECT  2.16 36.315 218.16 36.585 ;
     RECT  2.16 36.855 218.16 37.125 ;
     RECT  2.16 37.395 218.16 37.665 ;
     RECT  2.16 37.935 218.16 38.205 ;
     RECT  2.16 38.475 218.16 38.745 ;
     RECT  2.16 39.015 218.16 39.285 ;
     RECT  2.16 39.555 218.16 39.825 ;
     RECT  2.16 40.095 218.16 40.365 ;
     RECT  2.16 40.635 218.16 40.905 ;
     RECT  2.16 41.175 218.16 41.445 ;
     RECT  2.16 41.715 218.16 41.985 ;
     RECT  2.16 42.255 218.16 42.525 ;
     RECT  2.16 42.795 218.16 43.065 ;
     RECT  2.16 43.335 218.16 43.605 ;
     RECT  2.16 43.875 218.16 44.145 ;
     RECT  2.16 44.415 218.16 44.685 ;
     RECT  2.16 44.955 218.16 45.225 ;
     RECT  2.16 45.495 218.16 45.765 ;
     RECT  2.16 46.035 218.16 46.305 ;
     RECT  2.16 46.575 218.16 46.845 ;
     RECT  2.16 47.115 218.16 47.385 ;
     RECT  2.16 47.655 218.16 47.925 ;
     RECT  2.16 48.195 218.16 48.465 ;
     RECT  2.16 48.735 218.16 49.005 ;
     RECT  2.16 49.275 218.16 49.545 ;
     RECT  2.16 49.815 218.16 50.085 ;
     RECT  2.16 50.355 218.16 50.625 ;
     RECT  2.16 50.895 218.16 51.165 ;
     RECT  2.16 51.435 218.16 51.705 ;
     RECT  2.16 51.975 20.844 52.245 ;
     RECT  199.692 51.975 218.16 52.245 ;
     RECT  2.16 52.515 20.844 52.785 ;
     RECT  199.692 52.515 218.16 52.785 ;
     RECT  2.16 53.055 20.844 53.325 ;
     RECT  199.692 53.055 218.16 53.325 ;
     RECT  2.16 53.595 20.844 53.865 ;
     RECT  199.692 53.595 218.16 53.865 ;
     RECT  2.16 54.135 20.844 54.405 ;
     RECT  199.692 54.135 218.16 54.405 ;
     RECT  2.16 54.675 20.844 54.945 ;
     RECT  199.692 54.675 218.16 54.945 ;
     RECT  2.16 55.215 20.844 55.485 ;
     RECT  199.692 55.215 218.16 55.485 ;
     RECT  2.16 55.755 20.844 56.025 ;
     RECT  199.692 55.755 218.16 56.025 ;
     RECT  2.16 56.295 20.844 56.565 ;
     RECT  199.692 56.295 218.16 56.565 ;
     RECT  2.16 56.835 20.844 57.105 ;
     RECT  199.692 56.835 218.16 57.105 ;
     RECT  2.16 57.375 20.844 57.645 ;
     RECT  199.692 57.375 218.16 57.645 ;
     RECT  2.16 57.915 20.844 58.185 ;
     RECT  199.692 57.915 218.16 58.185 ;
     RECT  2.16 58.455 20.844 58.725 ;
     RECT  199.692 58.455 218.16 58.725 ;
     RECT  2.16 58.995 20.844 59.265 ;
     RECT  199.692 58.995 218.16 59.265 ;
     RECT  2.16 59.535 20.844 59.805 ;
     RECT  199.692 59.535 218.16 59.805 ;
     RECT  2.16 60.075 20.844 60.345 ;
     RECT  199.692 60.075 218.16 60.345 ;
     RECT  2.16 60.615 20.844 60.885 ;
     RECT  199.692 60.615 218.16 60.885 ;
     RECT  2.16 61.155 20.844 61.425 ;
     RECT  199.692 61.155 218.16 61.425 ;
     RECT  2.16 61.695 20.844 61.965 ;
     RECT  199.692 61.695 218.16 61.965 ;
     RECT  2.16 62.235 20.844 62.505 ;
     RECT  199.692 62.235 218.16 62.505 ;
     RECT  2.16 62.775 20.844 63.045 ;
     RECT  199.692 62.775 218.16 63.045 ;
     RECT  2.16 63.315 20.844 63.585 ;
     RECT  199.692 63.315 218.16 63.585 ;
     RECT  2.16 63.855 20.844 64.125 ;
     RECT  199.692 63.855 218.16 64.125 ;
     RECT  2.16 64.395 20.844 64.665 ;
     RECT  199.692 64.395 218.16 64.665 ;
     RECT  2.16 64.935 20.844 65.205 ;
     RECT  199.692 64.935 218.16 65.205 ;
     RECT  2.16 65.475 20.844 65.745 ;
     RECT  199.692 65.475 218.16 65.745 ;
     RECT  2.16 66.015 20.844 66.285 ;
     RECT  199.692 66.015 218.16 66.285 ;
     RECT  2.16 66.555 20.844 66.825 ;
     RECT  199.692 66.555 218.16 66.825 ;
     RECT  2.16 67.095 20.844 67.365 ;
     RECT  199.692 67.095 218.16 67.365 ;
     RECT  2.16 67.635 20.844 67.905 ;
     RECT  199.692 67.635 218.16 67.905 ;
     RECT  2.16 68.175 20.844 68.445 ;
     RECT  199.692 68.175 218.16 68.445 ;
     RECT  2.16 68.715 20.844 68.985 ;
     RECT  199.692 68.715 218.16 68.985 ;
     RECT  2.16 69.255 20.844 69.525 ;
     RECT  199.692 69.255 218.16 69.525 ;
     RECT  2.16 69.795 20.844 70.065 ;
     RECT  199.692 69.795 218.16 70.065 ;
     RECT  2.16 70.335 20.844 70.605 ;
     RECT  199.692 70.335 218.16 70.605 ;
     RECT  2.16 70.875 20.844 71.145 ;
     RECT  199.692 70.875 218.16 71.145 ;
     RECT  2.16 71.415 20.844 71.685 ;
     RECT  199.692 71.415 218.16 71.685 ;
     RECT  2.16 71.955 20.844 72.225 ;
     RECT  199.692 71.955 218.16 72.225 ;
     RECT  2.16 72.495 20.844 72.765 ;
     RECT  199.692 72.495 218.16 72.765 ;
     RECT  2.16 73.035 20.844 73.305 ;
     RECT  199.692 73.035 218.16 73.305 ;
     RECT  2.16 73.575 20.844 73.845 ;
     RECT  199.692 73.575 218.16 73.845 ;
     RECT  2.16 74.115 20.844 74.385 ;
     RECT  199.692 74.115 218.16 74.385 ;
     RECT  2.16 74.655 20.844 74.925 ;
     RECT  199.692 74.655 218.16 74.925 ;
     RECT  2.16 75.195 20.844 75.465 ;
     RECT  199.692 75.195 218.16 75.465 ;
     RECT  2.16 75.735 20.844 76.005 ;
     RECT  199.692 75.735 218.16 76.005 ;
     RECT  2.16 76.275 20.844 76.545 ;
     RECT  199.692 76.275 218.16 76.545 ;
     RECT  2.16 76.815 20.844 77.085 ;
     RECT  199.692 76.815 218.16 77.085 ;
     RECT  2.16 77.355 20.844 77.625 ;
     RECT  199.692 77.355 218.16 77.625 ;
     RECT  2.16 77.895 20.844 78.165 ;
     RECT  199.692 77.895 218.16 78.165 ;
     RECT  2.16 78.435 20.844 78.705 ;
     RECT  199.692 78.435 218.16 78.705 ;
     RECT  2.16 78.975 20.844 79.245 ;
     RECT  199.692 78.975 218.16 79.245 ;
     RECT  2.16 79.515 20.844 79.785 ;
     RECT  199.692 79.515 218.16 79.785 ;
     RECT  2.16 80.055 20.844 80.325 ;
     RECT  199.692 80.055 218.16 80.325 ;
     RECT  2.16 80.595 20.844 80.865 ;
     RECT  199.692 80.595 218.16 80.865 ;
     RECT  2.16 81.135 20.844 81.405 ;
     RECT  199.692 81.135 218.16 81.405 ;
     RECT  2.16 81.675 20.844 81.945 ;
     RECT  199.692 81.675 218.16 81.945 ;
     RECT  2.16 82.215 20.844 82.485 ;
     RECT  199.692 82.215 218.16 82.485 ;
     RECT  2.16 82.755 20.844 83.025 ;
     RECT  199.692 82.755 218.16 83.025 ;
     RECT  2.16 83.295 20.844 83.565 ;
     RECT  199.692 83.295 218.16 83.565 ;
     RECT  2.16 83.835 20.844 84.105 ;
     RECT  199.692 83.835 218.16 84.105 ;
     RECT  2.16 84.375 20.844 84.645 ;
     RECT  199.692 84.375 218.16 84.645 ;
     RECT  2.16 84.915 20.844 85.185 ;
     RECT  199.692 84.915 218.16 85.185 ;
     RECT  2.16 85.455 20.844 85.725 ;
     RECT  199.692 85.455 218.16 85.725 ;
     RECT  2.16 85.995 20.844 86.265 ;
     RECT  199.692 85.995 218.16 86.265 ;
     RECT  2.16 86.535 20.844 86.805 ;
     RECT  199.692 86.535 218.16 86.805 ;
     RECT  2.16 87.075 20.844 87.345 ;
     RECT  199.692 87.075 218.16 87.345 ;
     RECT  2.16 87.615 20.844 87.885 ;
     RECT  199.692 87.615 218.16 87.885 ;
     RECT  2.16 88.155 20.844 88.425 ;
     RECT  199.692 88.155 218.16 88.425 ;
     RECT  2.16 88.695 20.844 88.965 ;
     RECT  199.692 88.695 218.16 88.965 ;
     RECT  2.16 89.235 20.844 89.505 ;
     RECT  199.692 89.235 218.16 89.505 ;
     RECT  2.16 89.775 20.844 90.045 ;
     RECT  199.692 89.775 218.16 90.045 ;
     RECT  2.16 90.315 20.844 90.585 ;
     RECT  199.692 90.315 218.16 90.585 ;
     RECT  2.16 90.855 20.844 91.125 ;
     RECT  199.692 90.855 218.16 91.125 ;
     RECT  2.16 91.395 20.844 91.665 ;
     RECT  199.692 91.395 218.16 91.665 ;
     RECT  2.16 91.935 20.844 92.205 ;
     RECT  199.692 91.935 218.16 92.205 ;
     RECT  2.16 92.475 20.844 92.745 ;
     RECT  199.692 92.475 218.16 92.745 ;
     RECT  2.16 93.015 20.844 93.285 ;
     RECT  199.692 93.015 218.16 93.285 ;
     RECT  2.16 93.555 20.844 93.825 ;
     RECT  199.692 93.555 218.16 93.825 ;
     RECT  2.16 94.095 20.844 94.365 ;
     RECT  199.692 94.095 218.16 94.365 ;
     RECT  2.16 94.635 20.844 94.905 ;
     RECT  199.692 94.635 218.16 94.905 ;
     RECT  2.16 95.175 20.844 95.445 ;
     RECT  199.692 95.175 218.16 95.445 ;
     RECT  2.16 95.715 20.844 95.985 ;
     RECT  199.692 95.715 218.16 95.985 ;
     RECT  2.16 96.255 20.844 96.525 ;
     RECT  199.692 96.255 218.16 96.525 ;
     RECT  2.16 96.795 20.844 97.065 ;
     RECT  199.692 96.795 218.16 97.065 ;
     RECT  2.16 97.335 20.844 97.605 ;
     RECT  199.692 97.335 218.16 97.605 ;
     RECT  2.16 97.875 20.844 98.145 ;
     RECT  199.692 97.875 218.16 98.145 ;
     RECT  2.16 98.415 20.844 98.685 ;
     RECT  199.692 98.415 218.16 98.685 ;
     RECT  2.16 98.955 20.844 99.225 ;
     RECT  199.692 98.955 218.16 99.225 ;
     RECT  2.16 99.495 20.844 99.765 ;
     RECT  199.692 99.495 218.16 99.765 ;
     RECT  2.16 100.035 20.844 100.305 ;
     RECT  199.692 100.035 218.16 100.305 ;
     RECT  2.16 100.575 20.844 100.845 ;
     RECT  199.692 100.575 218.16 100.845 ;
     RECT  2.16 101.115 20.844 101.385 ;
     RECT  199.692 101.115 218.16 101.385 ;
     RECT  2.16 101.655 20.844 101.925 ;
     RECT  199.692 101.655 218.16 101.925 ;
     RECT  2.16 102.195 20.844 102.465 ;
     RECT  199.692 102.195 218.16 102.465 ;
     RECT  2.16 102.735 20.844 103.005 ;
     RECT  199.692 102.735 218.16 103.005 ;
     RECT  2.16 103.275 20.844 103.545 ;
     RECT  199.692 103.275 218.16 103.545 ;
     RECT  2.16 103.815 20.844 104.085 ;
     RECT  199.692 103.815 218.16 104.085 ;
     RECT  2.16 104.355 20.844 104.625 ;
     RECT  199.692 104.355 218.16 104.625 ;
     RECT  2.16 104.895 20.844 105.165 ;
     RECT  199.692 104.895 218.16 105.165 ;
     RECT  2.16 105.435 20.844 105.705 ;
     RECT  199.692 105.435 218.16 105.705 ;
     RECT  2.16 105.975 20.844 106.245 ;
     RECT  199.692 105.975 218.16 106.245 ;
     RECT  2.16 106.515 20.844 106.785 ;
     RECT  199.692 106.515 218.16 106.785 ;
     RECT  2.16 107.055 20.844 107.325 ;
     RECT  199.692 107.055 218.16 107.325 ;
     RECT  2.16 107.595 20.844 107.865 ;
     RECT  199.692 107.595 218.16 107.865 ;
     RECT  2.16 108.135 20.844 108.405 ;
     RECT  199.692 108.135 218.16 108.405 ;
     RECT  2.16 108.675 20.844 108.945 ;
     RECT  199.692 108.675 218.16 108.945 ;
     RECT  2.16 109.215 20.844 109.485 ;
     RECT  199.692 109.215 218.16 109.485 ;
     RECT  2.16 109.755 20.844 110.025 ;
     RECT  199.692 109.755 218.16 110.025 ;
     RECT  2.16 110.295 20.844 110.565 ;
     RECT  199.692 110.295 218.16 110.565 ;
     RECT  2.16 110.835 20.844 111.105 ;
     RECT  199.692 110.835 218.16 111.105 ;
     RECT  2.16 111.375 20.844 111.645 ;
     RECT  199.692 111.375 218.16 111.645 ;
     RECT  2.16 111.915 20.844 112.185 ;
     RECT  199.692 111.915 218.16 112.185 ;
     RECT  2.16 112.455 20.844 112.725 ;
     RECT  199.692 112.455 218.16 112.725 ;
     RECT  2.16 112.995 20.844 113.265 ;
     RECT  199.692 112.995 218.16 113.265 ;
     RECT  2.16 113.535 20.844 113.805 ;
     RECT  199.692 113.535 218.16 113.805 ;
     RECT  2.16 114.075 20.844 114.345 ;
     RECT  199.692 114.075 218.16 114.345 ;
     RECT  2.16 114.615 20.844 114.885 ;
     RECT  199.692 114.615 218.16 114.885 ;
     RECT  2.16 115.155 20.844 115.425 ;
     RECT  199.692 115.155 218.16 115.425 ;
     RECT  2.16 115.695 20.844 115.965 ;
     RECT  199.692 115.695 218.16 115.965 ;
     RECT  2.16 116.235 20.844 116.505 ;
     RECT  199.692 116.235 218.16 116.505 ;
     RECT  2.16 116.775 20.844 117.045 ;
     RECT  199.692 116.775 218.16 117.045 ;
     RECT  2.16 117.315 20.844 117.585 ;
     RECT  199.692 117.315 218.16 117.585 ;
     RECT  2.16 117.855 20.844 118.125 ;
     RECT  199.692 117.855 218.16 118.125 ;
     RECT  2.16 118.395 20.844 118.665 ;
     RECT  199.692 118.395 218.16 118.665 ;
     RECT  2.16 118.935 20.844 119.205 ;
     RECT  199.692 118.935 218.16 119.205 ;
     RECT  2.16 119.475 20.844 119.745 ;
     RECT  199.692 119.475 218.16 119.745 ;
     RECT  2.16 120.015 20.844 120.285 ;
     RECT  199.692 120.015 218.16 120.285 ;
     RECT  2.16 120.555 20.844 120.825 ;
     RECT  199.692 120.555 218.16 120.825 ;
     RECT  2.16 121.095 20.844 121.365 ;
     RECT  199.692 121.095 218.16 121.365 ;
     RECT  2.16 121.635 20.844 121.905 ;
     RECT  199.692 121.635 218.16 121.905 ;
     RECT  2.16 122.175 20.844 122.445 ;
     RECT  199.692 122.175 218.16 122.445 ;
     RECT  2.16 122.715 20.844 122.985 ;
     RECT  199.692 122.715 218.16 122.985 ;
     RECT  2.16 123.255 20.844 123.525 ;
     RECT  199.692 123.255 218.16 123.525 ;
     RECT  2.16 123.795 20.844 124.065 ;
     RECT  199.692 123.795 218.16 124.065 ;
     RECT  2.16 124.335 20.844 124.605 ;
     RECT  199.692 124.335 218.16 124.605 ;
     RECT  2.16 124.875 20.844 125.145 ;
     RECT  199.692 124.875 218.16 125.145 ;
     RECT  2.16 125.415 20.844 125.685 ;
     RECT  199.692 125.415 218.16 125.685 ;
     RECT  2.16 125.955 20.844 126.225 ;
     RECT  199.692 125.955 218.16 126.225 ;
     RECT  2.16 126.495 20.844 126.63 ;
     RECT  199.692 126.495 218.16 126.63 ;
     RECT  2.16 126.63 218.16 126.765 ;
     RECT  2.16 127.035 218.16 127.305 ;
     RECT  2.16 127.575 218.16 127.845 ;
     RECT  2.16 128.115 218.16 128.385 ;
     RECT  2.16 128.655 218.16 128.925 ;
     RECT  2.16 129.195 218.16 129.465 ;
     RECT  2.16 129.735 218.16 130.005 ;
     RECT  2.16 130.275 218.16 130.545 ;
     RECT  2.16 130.815 218.16 131.085 ;
     RECT  2.16 131.355 218.16 131.625 ;
     RECT  2.16 131.895 218.16 132.165 ;
     RECT  2.16 132.435 218.16 132.705 ;
     RECT  2.16 132.975 218.16 133.245 ;
     RECT  2.16 133.515 218.16 133.785 ;
     RECT  2.16 134.055 218.16 134.325 ;
     RECT  2.16 134.595 218.16 134.865 ;
     RECT  2.16 135.135 218.16 135.405 ;
     RECT  2.16 135.675 218.16 135.945 ;
     RECT  2.16 136.215 218.16 136.485 ;
     RECT  2.16 136.755 218.16 137.025 ;
     RECT  2.16 137.295 218.16 137.565 ;
     RECT  2.16 137.835 218.16 138.105 ;
     RECT  2.16 138.375 218.16 138.645 ;
     RECT  2.16 138.915 218.16 139.185 ;
     RECT  2.16 139.455 218.16 139.725 ;
     RECT  2.16 139.995 218.16 140.265 ;
     RECT  2.16 140.535 218.16 140.805 ;
     RECT  2.16 141.075 218.16 141.345 ;
     RECT  2.16 141.615 218.16 141.885 ;
     RECT  2.16 142.155 218.16 142.425 ;
     RECT  2.16 142.695 218.16 142.965 ;
     RECT  2.16 143.235 218.16 143.505 ;
     RECT  2.16 143.775 218.16 144.045 ;
     RECT  2.16 144.315 218.16 144.585 ;
     RECT  2.16 144.855 218.16 145.125 ;
     RECT  2.16 145.395 218.16 145.665 ;
     RECT  2.16 145.935 218.16 146.205 ;
     RECT  2.16 146.475 218.16 146.745 ;
     RECT  2.16 147.015 218.16 147.285 ;
     RECT  2.16 147.555 218.16 147.825 ;
     RECT  2.16 148.095 218.16 148.365 ;
     RECT  2.16 148.635 218.16 148.905 ;
     RECT  2.16 149.175 218.16 149.445 ;
     RECT  2.16 149.715 218.16 149.985 ;
     RECT  2.16 150.255 218.16 150.525 ;
     RECT  2.16 150.795 218.16 151.065 ;
     RECT  2.16 151.335 218.16 151.605 ;
     RECT  2.16 151.875 218.16 152.145 ;
     RECT  2.16 152.415 218.16 152.685 ;
     RECT  2.16 152.955 218.16 153.225 ;
     RECT  2.16 153.495 218.16 153.765 ;
     RECT  2.16 154.035 218.16 154.305 ;
     RECT  2.16 154.575 218.16 154.845 ;
     RECT  2.16 155.115 218.16 155.385 ;
     RECT  2.16 155.655 218.16 155.925 ;
     RECT  2.16 156.195 218.16 156.465 ;
     RECT  2.16 156.735 218.16 157.005 ;
     RECT  2.16 157.275 218.16 157.545 ;
     RECT  2.16 157.815 218.16 158.085 ;
     RECT  2.16 158.355 218.16 158.625 ;
     RECT  2.16 158.895 218.16 159.165 ;
     RECT  2.16 159.435 218.16 159.705 ;
     RECT  2.16 159.975 218.16 160.245 ;
     RECT  2.16 160.515 218.16 160.785 ;
     RECT  2.16 161.055 218.16 161.325 ;
     RECT  2.16 161.595 218.16 161.865 ;
     RECT  2.16 162.135 218.16 162.405 ;
     RECT  2.16 162.675 218.16 162.945 ;
     RECT  2.16 163.215 218.16 163.485 ;
     RECT  2.16 163.755 218.16 164.025 ;
     RECT  2.16 164.295 218.16 164.565 ;
     RECT  2.16 164.835 218.16 165.105 ;
     RECT  2.16 165.375 218.16 165.645 ;
     RECT  2.16 165.915 218.16 166.185 ;
     RECT  2.16 166.455 218.16 166.725 ;
     RECT  2.16 166.995 218.16 167.265 ;
     RECT  2.16 167.535 218.16 167.805 ;
     RECT  2.16 168.075 218.16 168.345 ;
     RECT  2.16 168.615 218.16 168.885 ;
     RECT  2.16 169.155 218.16 169.425 ;
     RECT  2.16 169.695 218.16 169.965 ;
     RECT  2.16 170.235 218.16 170.505 ;
     RECT  2.16 170.775 218.16 171.045 ;
     RECT  2.16 171.315 218.16 171.585 ;
     RECT  2.16 171.855 218.16 172.125 ;
     RECT  2.16 172.395 218.16 172.665 ;
     RECT  2.16 172.935 218.16 173.205 ;
     RECT  2.16 173.475 218.16 173.745 ;
     RECT  2.16 174.015 218.16 174.285 ;
     RECT  2.16 174.555 218.16 174.825 ;
    LAYER M1 ;
     RECT  2.16 2.151 218.16 51.849 ;
     RECT  22.896 54 197.64 124.488 ;
     RECT  2.16 51.849 20.844 126.621 ;
     RECT  199.692 51.849 218.16 126.621 ;
     RECT  2.16 126.621 218.16 174.969 ;
    LAYER M2 ;
     RECT  0.103 52.794 0.139 53.694 ;
     RECT  0.103 54.612 0.139 54.63 ;
     RECT  0.103 58.806 0.139 58.824 ;
     RECT  0.103 59.742 0.139 60.408 ;
     RECT  0.103 87.822 0.139 88.452 ;
     RECT  0.103 89.244 0.139 89.874 ;
     RECT  0.103 94.572 0.139 94.59 ;
     RECT  0.139 90.828 0.175 90.846 ;
     RECT  0.139 94.572 0.175 95.13 ;
     RECT  0.175 94.032 0.211 95.13 ;
     RECT  0.103 62.514 0.239 62.649 ;
     RECT  0.175 90.828 0.239 90.918 ;
     RECT  0.211 93.906 0.247 95.13 ;
     RECT  0.239 62.631 0.311 62.649 ;
     RECT  0.139 58.806 0.347 60.408 ;
     RECT  0.139 52.794 0.455 54.666 ;
     RECT  0.103 85.77 0.535 85.788 ;
     RECT  0.103 86.742 0.535 86.76 ;
     RECT  0.247 93.834 0.535 95.13 ;
     RECT  0.103 95.922 0.535 95.94 ;
     RECT  0.103 80.91 0.571 80.928 ;
     RECT  0.103 81.72 0.571 81.738 ;
     RECT  0.103 44.19 1.147 45.99 ;
     RECT  0.175 56.502 1.147 56.52 ;
     RECT  0.103 63.522 1.147 63.846 ;
     RECT  0.535 66.06 1.147 66.078 ;
     RECT  0.239 90.9 1.147 90.918 ;
     RECT  0.535 93.834 1.147 95.94 ;
     RECT  1.147 44.19 1.183 46.26 ;
     RECT  1.147 66.024 1.183 66.078 ;
     RECT  1.183 44.19 1.219 46.53 ;
     RECT  1.183 97.272 1.219 97.29 ;
     RECT  1.219 97.002 1.327 97.29 ;
     RECT  1.327 97.002 1.651 97.866 ;
     RECT  1.219 44.19 1.723 46.638 ;
     RECT  1.147 61.902 1.723 61.92 ;
     RECT  0.535 85.77 1.723 86.76 ;
     RECT  1.723 43.65 2.16 46.638 ;
     RECT  0.103 52.02 2.16 52.038 ;
     RECT  0.455 52.794 2.16 52.812 ;
     RECT  0.455 53.676 2.16 54.666 ;
     RECT  1.147 56.502 2.16 56.592 ;
     RECT  0.535 57.924 2.16 57.942 ;
     RECT  0.347 58.806 2.16 59.256 ;
     RECT  0.347 60.354 2.16 60.408 ;
     RECT  1.723 61.902 2.16 62.568 ;
     RECT  1.147 63.522 2.16 64.386 ;
     RECT  1.183 65.682 2.16 66.078 ;
     RECT  0.571 80.91 2.16 81.738 ;
     RECT  1.147 83.268 2.16 83.286 ;
     RECT  1.723 85.122 2.16 86.76 ;
     RECT  0.139 87.822 2.16 89.874 ;
     RECT  1.147 90.666 2.16 90.918 ;
     RECT  1.147 93.762 2.16 95.94 ;
     RECT  1.651 96.84 2.16 97.866 ;
     RECT  2.16 2.151 20.844 174.969 ;
     RECT  20.844 58.626 20.939 83.79 ;
     RECT  20.939 58.806 20.975 83.79 ;
     RECT  20.844 2.151 21.047 54.324 ;
     RECT  20.844 89.046 21.047 95.634 ;
     RECT  20.844 55.116 21.083 57.87 ;
     RECT  20.975 60.696 21.083 83.79 ;
     RECT  21.047 89.046 21.083 95.364 ;
     RECT  20.975 58.806 21.119 59.904 ;
     RECT  21.083 89.046 21.119 95.094 ;
     RECT  21.083 55.566 21.155 57.87 ;
     RECT  21.083 60.696 21.155 83.484 ;
     RECT  21.047 2.151 21.451 54.198 ;
     RECT  21.119 58.968 21.479 59.904 ;
     RECT  21.119 91.026 21.623 95.094 ;
     RECT  21.155 60.696 21.659 69.624 ;
     RECT  20.844 85.734 21.659 88.146 ;
     RECT  21.623 91.026 21.659 92.124 ;
     RECT  21.623 92.916 21.659 95.094 ;
     RECT  21.479 59.886 21.695 59.904 ;
     RECT  21.659 60.696 21.695 66.744 ;
     RECT  21.155 70.416 21.695 73.404 ;
     RECT  21.155 74.43 21.695 83.484 ;
     RECT  21.155 55.566 21.875 57.474 ;
     RECT  21.695 64.71 21.947 66.744 ;
     RECT  21.659 68.076 22.019 69.624 ;
     RECT  21.695 60.696 22.091 63.81 ;
     RECT  21.451 2.106 22.163 54.198 ;
     RECT  22.163 2.106 22.451 53.964 ;
     RECT  22.451 2.151 22.896 53.964 ;
     RECT  21.875 55.566 22.896 55.746 ;
     RECT  21.875 56.646 22.896 57.474 ;
     RECT  21.479 58.968 22.896 58.986 ;
     RECT  22.091 60.696 22.896 61.569 ;
     RECT  22.091 62.712 22.896 63.81 ;
     RECT  21.947 64.71 22.896 66.654 ;
     RECT  22.019 68.256 22.896 69.624 ;
     RECT  21.695 70.506 22.896 73.404 ;
     RECT  21.695 74.556 22.896 83.484 ;
     RECT  20.844 84.546 22.896 84.906 ;
     RECT  21.659 85.734 22.896 86.22 ;
     RECT  21.659 86.976 22.896 88.146 ;
     RECT  21.119 89.046 22.896 90.144 ;
     RECT  21.659 91.206 22.896 92.124 ;
     RECT  21.659 93.186 22.896 95.094 ;
     RECT  20.844 125.118 22.896 174.969 ;
     RECT  22.896 2.151 26.023 174.969 ;
     RECT  26.023 2.034 26.879 174.969 ;
     RECT  26.879 2.07 28.319 174.969 ;
     RECT  28.319 2.106 28.355 174.969 ;
     RECT  28.355 2.151 65.507 174.969 ;
     RECT  65.507 2.151 66.407 125.712 ;
     RECT  66.407 2.151 66.695 125.676 ;
     RECT  65.507 126.576 66.775 174.969 ;
     RECT  66.695 125.658 67.171 125.676 ;
     RECT  66.775 126.54 67.171 174.969 ;
     RECT  66.695 2.151 68.359 124.488 ;
     RECT  67.171 125.658 68.359 174.969 ;
     RECT  68.359 2.151 69.179 174.969 ;
     RECT  69.179 2.151 70.159 125.136 ;
     RECT  69.179 126.234 70.159 174.969 ;
     RECT  70.159 2.151 75.767 174.969 ;
     RECT  75.767 2.151 79.015 53.244 ;
     RECT  75.767 54 79.015 174.969 ;
     RECT  79.015 2.151 197.64 174.969 ;
     RECT  197.64 2.151 197.879 57.474 ;
     RECT  197.879 2.151 197.951 57.366 ;
     RECT  197.951 2.151 198.239 57.024 ;
     RECT  198.239 2.151 198.347 55.44 ;
     RECT  198.239 56.376 198.347 57.024 ;
     RECT  198.347 56.736 198.383 57.024 ;
     RECT  197.64 60.246 198.383 60.57 ;
     RECT  197.64 65.25 198.383 65.466 ;
     RECT  198.383 60.318 198.391 60.57 ;
     RECT  197.64 66.33 198.427 94.356 ;
     RECT  198.427 66.33 198.607 94.392 ;
     RECT  197.64 95.148 198.607 95.4 ;
     RECT  198.643 99.576 198.679 99.594 ;
     RECT  198.679 58.698 198.787 59.256 ;
     RECT  198.679 99.396 198.967 99.594 ;
     RECT  197.64 98.226 199.183 98.244 ;
     RECT  198.347 2.151 199.219 54.126 ;
     RECT  198.391 60.318 199.255 60.714 ;
     RECT  198.383 65.448 199.399 65.466 ;
     RECT  198.607 66.33 199.399 95.4 ;
     RECT  199.219 2.151 199.507 54.666 ;
     RECT  198.347 55.422 199.507 55.44 ;
     RECT  198.787 58.626 199.579 59.256 ;
     RECT  199.507 2.151 199.692 55.44 ;
     RECT  198.383 56.808 199.692 57.024 ;
     RECT  199.579 58.536 199.692 59.256 ;
     RECT  199.255 60.318 199.692 60.984 ;
     RECT  199.399 65.448 199.692 95.4 ;
     RECT  197.64 96.966 199.692 96.984 ;
     RECT  199.183 98.226 199.692 98.514 ;
     RECT  198.967 99.396 199.692 100.296 ;
     RECT  198.679 103.626 199.692 103.644 ;
     RECT  198.715 104.706 199.692 104.724 ;
     RECT  197.64 125.118 199.692 174.969 ;
     RECT  199.692 2.151 218.16 174.969 ;
     RECT  218.16 54.378 218.579 65.034 ;
     RECT  218.16 65.826 218.579 79.704 ;
     RECT  218.579 65.826 218.651 79.578 ;
     RECT  218.579 54.414 218.687 65.034 ;
     RECT  218.651 72.306 218.831 79.578 ;
     RECT  218.651 65.826 218.867 71.514 ;
     RECT  218.831 72.306 218.903 77.148 ;
     RECT  218.687 54.45 218.939 65.034 ;
     RECT  218.939 54.45 219.011 56.934 ;
     RECT  218.939 62.478 219.155 65.034 ;
     RECT  218.903 72.306 219.191 74.844 ;
     RECT  218.903 75.816 219.191 77.148 ;
     RECT  219.191 72.468 219.407 74.844 ;
     RECT  219.191 76.626 219.407 77.148 ;
     RECT  218.939 57.816 219.443 61.614 ;
     RECT  219.155 62.478 219.443 63.774 ;
     RECT  218.867 65.826 219.443 69.48 ;
     RECT  218.867 70.236 219.443 71.514 ;
     RECT  219.407 72.666 219.443 74.844 ;
     RECT  219.011 54.45 219.479 55.746 ;
     RECT  219.443 72.666 219.479 74.646 ;
     RECT  219.479 55.728 219.515 55.746 ;
     RECT  219.443 60.858 219.515 61.299 ;
     RECT  219.155 64.674 219.515 65.034 ;
     RECT  219.479 72.666 219.515 74.448 ;
     RECT  219.011 56.916 219.551 56.934 ;
     RECT  219.443 57.816 219.551 60.066 ;
     RECT  219.551 58.581 219.587 60.066 ;
     RECT  219.551 57.816 219.623 57.834 ;
     RECT  219.587 58.581 219.623 59.796 ;
     RECT  219.623 59.238 219.659 59.256 ;
     RECT  219.407 76.716 220.019 77.148 ;
     RECT  219.443 70.578 220.127 71.514 ;
     RECT  219.515 72.666 220.127 73.224 ;
     RECT  219.191 75.816 220.127 75.834 ;
     RECT  218.831 78.066 220.127 79.578 ;
     RECT  219.443 66.834 220.163 68.274 ;
     RECT  220.127 71.046 220.163 71.514 ;
     RECT  220.019 76.716 220.163 76.734 ;
     RECT  220.127 78.066 220.163 78.804 ;
     RECT  219.515 64.98 220.199 65.034 ;
     RECT  220.163 66.834 220.199 68.166 ;
     RECT  220.163 71.046 220.199 71.334 ;
     RECT  220.127 72.666 220.199 73.179 ;
     RECT  219.515 74.016 220.199 74.448 ;
     RECT  219.479 54.45 220.235 54.972 ;
     RECT  219.515 61.281 220.235 61.299 ;
     RECT  219.443 62.478 220.235 63.234 ;
     RECT  220.199 64.98 220.235 64.998 ;
     RECT  220.199 66.834 220.235 66.852 ;
     RECT  220.199 68.148 220.235 68.166 ;
     RECT  219.443 69.228 220.235 69.246 ;
     RECT  220.199 71.046 220.235 71.064 ;
     RECT  220.199 72.666 220.235 72.684 ;
     RECT  220.199 74.016 220.235 74.034 ;
     RECT  220.163 78.066 220.235 78.579 ;
     RECT  220.127 79.56 220.235 79.578 ;
     RECT  220.235 54.45 220.271 54.738 ;
     RECT  220.235 62.478 220.271 62.73 ;
    LAYER M3 ;
     RECT  22.248 0.091 22.266 0.139 ;
     RECT  22.248 0.139 22.338 0.187 ;
     RECT  22.248 0.187 22.41 0.235 ;
     RECT  24.156 0.091 24.858 0.523 ;
     RECT  16.056 0.091 16.074 0.571 ;
     RECT  22.248 0.235 22.95 0.571 ;
     RECT  24.156 0.523 25.506 0.571 ;
     RECT  15.948 0.571 16.434 1.147 ;
     RECT  22.248 0.571 25.506 1.243 ;
     RECT  27.36 1.771 27.378 1.819 ;
     RECT  27.36 1.819 27.45 1.867 ;
     RECT  22.248 1.243 25.542 2.029 ;
     RECT  26.316 1.723 26.334 2.029 ;
     RECT  27.36 1.867 27.774 2.029 ;
     RECT  22.248 2.029 27.774 2.065 ;
     RECT  22.248 2.065 28.314 2.101 ;
     RECT  15.948 1.147 16.686 2.191 ;
     RECT  22.248 2.101 28.35 2.191 ;
     RECT  21.456 2.101 21.474 2.219 ;
     RECT  15.336 2.191 16.686 2.227 ;
     RECT  15.264 2.227 16.686 2.263 ;
     RECT  22.248 2.191 28.638 2.371 ;
     RECT  15.264 2.263 17.154 2.399 ;
     RECT  2.415 2.143 2.505 2.413 ;
     RECT  7.815 2.143 7.905 2.413 ;
     RECT  13.215 2.143 13.305 2.413 ;
     RECT  18.615 2.143 18.705 2.413 ;
     RECT  29.415 2.143 29.505 2.413 ;
     RECT  34.815 2.143 34.905 2.413 ;
     RECT  40.215 2.143 40.305 2.413 ;
     RECT  45.615 2.143 45.705 2.413 ;
     RECT  51.015 2.143 51.105 2.413 ;
     RECT  56.415 2.143 56.505 2.413 ;
     RECT  61.815 2.143 61.905 2.413 ;
     RECT  67.215 2.143 67.305 2.413 ;
     RECT  72.615 2.143 72.705 2.413 ;
     RECT  78.015 2.143 78.105 2.413 ;
     RECT  83.415 2.143 83.505 2.413 ;
     RECT  88.815 2.143 88.905 2.413 ;
     RECT  94.215 2.143 94.305 2.413 ;
     RECT  99.615 2.143 99.705 2.413 ;
     RECT  105.015 2.143 105.105 2.413 ;
     RECT  110.415 2.143 110.505 2.413 ;
     RECT  115.815 2.143 115.905 2.413 ;
     RECT  121.215 2.143 121.305 2.413 ;
     RECT  126.615 2.143 126.705 2.413 ;
     RECT  132.015 2.143 132.105 2.413 ;
     RECT  137.415 2.143 137.505 2.413 ;
     RECT  142.815 2.143 142.905 2.413 ;
     RECT  148.215 2.143 148.305 2.413 ;
     RECT  153.615 2.143 153.705 2.413 ;
     RECT  159.015 2.143 159.105 2.413 ;
     RECT  164.415 2.143 164.505 2.413 ;
     RECT  169.815 2.143 169.905 2.413 ;
     RECT  175.215 2.143 175.305 2.413 ;
     RECT  180.615 2.143 180.705 2.413 ;
     RECT  186.015 2.143 186.105 2.413 ;
     RECT  191.415 2.143 191.505 2.413 ;
     RECT  196.815 2.143 196.905 2.413 ;
     RECT  202.215 2.143 202.305 2.413 ;
     RECT  207.615 2.143 207.705 2.413 ;
     RECT  213.015 2.143 213.105 2.413 ;
     RECT  15.336 2.399 17.154 2.605 ;
     RECT  15.336 2.605 17.37 2.641 ;
     RECT  29.415 2.413 29.697 2.641 ;
     RECT  21.564 2.371 28.638 2.731 ;
     RECT  29.376 2.641 29.697 2.731 ;
     RECT  21.564 2.731 29.697 2.795 ;
     RECT  15.336 2.641 17.406 3.145 ;
     RECT  20.7 3.109 20.718 3.181 ;
     RECT  15.048 3.145 17.406 3.299 ;
     RECT  20.7 3.181 20.898 3.685 ;
     RECT  21.636 2.795 29.697 3.685 ;
     RECT  20.7 3.685 29.697 3.811 ;
     RECT  15.048 3.299 17.37 3.991 ;
     RECT  20.412 3.811 29.697 3.991 ;
     RECT  14.832 3.991 17.37 4.145 ;
     RECT  14.832 4.145 17.334 4.217 ;
     RECT  20.196 3.991 29.697 4.261 ;
     RECT  14.832 4.217 17.298 4.495 ;
     RECT  19.98 4.261 29.697 4.531 ;
     RECT  14.688 4.495 17.298 4.801 ;
     RECT  14.616 4.801 17.298 4.955 ;
     RECT  14.616 4.955 16.578 5.071 ;
     RECT  13.215 2.413 13.497 5.305 ;
     RECT  14.22 5.071 16.578 5.305 ;
     RECT  18.615 2.413 18.897 5.305 ;
     RECT  19.98 4.531 29.754 5.305 ;
     RECT  18.615 5.305 30.042 5.461 ;
     RECT  13.215 5.305 16.578 5.701 ;
     RECT  17.316 5.035 17.334 5.701 ;
     RECT  13.215 5.701 17.334 6.115 ;
     RECT  18.396 5.461 30.042 6.115 ;
     RECT  13.215 6.115 17.514 6.277 ;
     RECT  13.212 6.277 17.514 6.317 ;
     RECT  18.396 6.115 30.114 6.539 ;
     RECT  13.215 6.317 17.514 6.547 ;
     RECT  13.215 6.547 17.622 6.583 ;
     RECT  18.396 6.539 29.697 6.583 ;
     RECT  13.215 6.583 29.697 7.231 ;
     RECT  12.888 7.231 29.697 7.387 ;
     RECT  12.708 7.387 29.697 7.427 ;
     RECT  13.215 7.427 29.697 8.195 ;
     RECT  13.215 8.195 14.778 8.303 ;
     RECT  13.215 8.303 14.238 8.429 ;
     RECT  15.948 8.195 29.697 9.355 ;
     RECT  15.66 9.355 29.697 10.049 ;
     RECT  16.56 10.049 29.697 10.121 ;
     RECT  16.776 10.121 29.697 10.355 ;
     RECT  17.424 10.355 29.697 11.129 ;
     RECT  17.424 11.129 28.386 11.399 ;
     RECT  19.836 11.399 28.386 11.435 ;
     RECT  13.215 8.429 13.95 11.443 ;
     RECT  19.836 11.435 28.17 11.453 ;
     RECT  17.424 11.399 19.026 11.549 ;
     RECT  17.784 11.549 19.026 11.669 ;
     RECT  19.836 11.453 26.982 11.669 ;
     RECT  27.72 11.453 28.17 11.669 ;
     RECT  19.872 11.669 25.866 11.705 ;
     RECT  26.856 11.669 26.874 11.705 ;
     RECT  19.872 11.705 24.39 11.741 ;
     RECT  27.72 11.669 28.098 11.741 ;
     RECT  17.784 11.669 18.954 11.813 ;
     RECT  20.232 11.741 24.39 11.939 ;
     RECT  25.128 11.705 25.866 11.975 ;
     RECT  27.72 11.741 27.738 11.975 ;
     RECT  25.128 11.975 25.218 12.083 ;
     RECT  20.232 11.939 24.297 12.317 ;
     RECT  25.2 12.083 25.218 12.317 ;
     RECT  20.232 12.317 21.654 12.509 ;
     RECT  20.232 12.509 21.402 12.523 ;
     RECT  20.16 12.523 21.402 12.56 ;
     RECT  22.392 12.317 24.297 12.587 ;
     RECT  22.392 12.587 23.13 12.623 ;
     RECT  20.232 12.56 21.402 25.555 ;
     RECT  68.76 27.481 68.778 27.629 ;
     RECT  67.215 2.413 67.497 27.751 ;
     RECT  67.032 27.751 67.497 27.821 ;
     RECT  15.66 10.049 15.678 37.831 ;
     RECT  15.372 37.831 15.678 37.901 ;
     RECT  13.215 11.443 14.526 38.005 ;
     RECT  98.604 37.963 98.622 38.141 ;
     RECT  13.215 38.005 14.562 38.173 ;
     RECT  13.215 38.173 14.814 38.641 ;
     RECT  15.66 37.901 15.678 38.641 ;
     RECT  115.815 2.413 116.097 38.641 ;
     RECT  196.815 2.413 197.097 38.677 ;
     RECT  196.092 38.677 197.097 38.713 ;
     RECT  13.215 38.641 15.678 38.717 ;
     RECT  114.876 38.641 114.894 38.717 ;
     RECT  51.015 2.413 51.297 39.019 ;
     RECT  83.415 2.413 83.697 39.019 ;
     RECT  84.456 38.677 84.474 39.019 ;
     RECT  115.668 38.641 116.097 39.067 ;
     RECT  123.264 39.055 123.282 39.091 ;
     RECT  53.568 39.019 53.586 39.181 ;
     RECT  82.656 39.019 82.674 39.181 ;
     RECT  83.415 39.019 84.474 39.181 ;
     RECT  113.148 38.731 113.166 39.181 ;
     RECT  53.424 39.181 53.586 39.208 ;
     RECT  24.015 12.587 24.297 39.217 ;
     RECT  53.1 39.208 53.586 39.245 ;
     RECT  102.312 37.963 102.33 39.253 ;
     RECT  88.815 2.413 89.097 39.259 ;
     RECT  50.724 39.019 51.297 39.317 ;
     RECT  53.424 39.245 53.586 39.317 ;
     RECT  82.656 39.181 84.474 39.317 ;
     RECT  53.424 39.317 53.442 39.341 ;
     RECT  107.316 39.019 107.334 39.547 ;
     RECT  96.84 39.595 96.858 39.631 ;
     RECT  191.415 2.413 191.697 39.631 ;
     RECT  13.215 38.717 14.814 39.721 ;
     RECT  15.66 38.717 15.678 39.721 ;
     RECT  109.548 38.155 109.566 39.721 ;
     RECT  110.415 2.413 110.697 39.721 ;
     RECT  107.172 39.547 107.334 39.749 ;
     RECT  13.215 39.721 15.678 39.757 ;
     RECT  96.66 39.631 96.858 39.757 ;
     RECT  102.024 39.253 102.33 39.757 ;
     RECT  205.956 39.721 205.974 39.757 ;
     RECT  13.215 39.757 15.93 39.773 ;
     RECT  102.024 39.757 103.014 39.821 ;
     RECT  104.112 39.721 104.13 39.821 ;
     RECT  96.516 39.757 96.858 39.829 ;
     RECT  95.796 39.829 96.858 39.835 ;
     RECT  97.632 39.595 97.65 39.835 ;
     RECT  10.836 39.757 10.854 39.857 ;
     RECT  15.66 39.773 15.93 39.857 ;
     RECT  108.396 39.721 108.414 39.869 ;
     RECT  102.024 39.821 102.618 40.064 ;
     RECT  104.076 40.027 104.094 40.064 ;
     RECT  105.015 2.413 105.297 40.135 ;
     RECT  195.66 38.713 197.097 40.171 ;
     RECT  107.316 39.749 107.334 40.261 ;
     RECT  112.32 39.217 112.338 40.261 ;
     RECT  113.148 39.181 113.706 40.261 ;
     RECT  34.815 2.413 35.097 40.267 ;
     RECT  181.692 40.135 181.71 40.297 ;
     RECT  123.264 39.091 123.39 40.333 ;
     RECT  124.164 40.099 124.182 40.333 ;
     RECT  204.336 40.261 204.354 40.333 ;
     RECT  25.632 40.261 25.65 40.349 ;
     RECT  95.796 39.835 97.65 40.369 ;
     RECT  199.836 39.829 199.854 40.369 ;
     RECT  146.484 40.267 146.502 40.397 ;
     RECT  24.015 39.217 24.822 40.405 ;
     RECT  128.664 40.363 128.682 40.405 ;
     RECT  210.78 39.181 210.798 40.405 ;
     RECT  211.788 39.217 211.806 40.405 ;
     RECT  6.372 39.757 6.39 40.441 ;
     RECT  87.444 40.297 87.462 40.441 ;
     RECT  99.615 2.413 99.897 40.441 ;
     RECT  209.196 39.253 209.214 40.441 ;
     RECT  32.22 40.261 32.238 40.445 ;
     RECT  33.336 40.369 33.354 40.445 ;
     RECT  34.815 40.267 35.19 40.445 ;
     RECT  105.015 40.135 105.822 40.555 ;
     RECT  83.415 39.317 83.697 40.651 ;
     RECT  84.456 39.317 84.474 40.651 ;
     RECT  109.548 39.721 110.697 40.651 ;
     RECT  112.32 40.261 113.706 40.699 ;
     RECT  115.38 39.067 116.097 40.699 ;
     RECT  107.316 40.261 107.442 40.801 ;
     RECT  10.8 40.699 10.818 40.829 ;
     RECT  105.015 40.555 106.362 40.829 ;
     RECT  112.32 40.699 114.426 40.829 ;
     RECT  115.38 40.699 116.19 40.829 ;
     RECT  164.415 2.413 164.697 40.837 ;
     RECT  199.836 40.369 200.142 40.837 ;
     RECT  202.215 2.413 202.497 40.873 ;
     RECT  105.015 40.829 105.822 40.909 ;
     RECT  202.215 40.873 203.202 40.909 ;
     RECT  63.252 38.515 63.27 40.939 ;
     RECT  202.032 40.909 203.202 40.939 ;
     RECT  204.084 40.333 204.354 40.939 ;
     RECT  102.024 40.064 102.474 40.945 ;
     RECT  9.72 40.909 9.738 40.981 ;
     RECT  90.468 38.173 90.486 40.981 ;
     RECT  9.72 40.981 10.026 41.021 ;
     RECT  202.032 40.939 204.354 41.069 ;
     RECT  120.384 39.217 120.402 41.071 ;
     RECT  121.215 2.413 121.497 41.071 ;
     RECT  132.015 2.413 132.297 41.071 ;
     RECT  142.815 2.413 143.097 41.071 ;
     RECT  153.615 2.413 153.897 41.071 ;
     RECT  175.215 2.413 175.497 41.071 ;
     RECT  186.015 2.413 186.297 41.071 ;
     RECT  120.384 41.071 121.497 41.117 ;
     RECT  131.904 41.071 132.297 41.117 ;
     RECT  142.704 41.071 143.097 41.117 ;
     RECT  153.504 41.071 153.897 41.117 ;
     RECT  175.104 41.071 175.497 41.117 ;
     RECT  185.904 41.071 186.297 41.117 ;
     RECT  88.776 39.259 89.097 41.131 ;
     RECT  162.36 38.515 162.378 41.215 ;
     RECT  208.908 40.441 209.214 41.215 ;
     RECT  17.784 11.813 18.897 41.227 ;
     RECT  19.656 25.555 21.402 41.227 ;
     RECT  205.344 39.757 205.974 41.251 ;
     RECT  72.615 2.413 72.897 41.275 ;
     RECT  114.624 41.179 114.642 41.279 ;
     RECT  29.415 11.129 29.697 41.323 ;
     RECT  61.815 2.413 62.097 41.323 ;
     RECT  95.796 40.369 98.37 41.323 ;
     RECT  107.136 40.801 107.442 41.323 ;
     RECT  13.215 39.773 14.814 41.341 ;
     RECT  15.66 39.857 15.678 41.341 ;
     RECT  74.664 41.323 74.682 41.341 ;
     RECT  78.015 2.413 78.297 41.341 ;
     RECT  93.276 39.793 93.438 41.341 ;
     RECT  16.812 41.227 16.83 41.369 ;
     RECT  34.815 40.445 35.097 41.377 ;
     RECT  45.615 2.413 45.897 41.377 ;
     RECT  56.415 2.413 56.697 41.377 ;
     RECT  67.215 27.821 67.497 41.377 ;
     RECT  123.264 40.333 124.182 41.377 ;
     RECT  72.615 41.275 72.99 41.405 ;
     RECT  74.448 41.341 74.682 41.405 ;
     RECT  83.415 40.651 84.474 41.413 ;
     RECT  93.276 41.341 93.474 41.413 ;
     RECT  94.215 2.413 94.497 41.413 ;
     RECT  133.056 40.873 133.074 41.413 ;
     RECT  133.848 40.603 133.866 41.413 ;
     RECT  210.78 40.405 211.806 41.413 ;
     RECT  22.32 40.945 22.338 41.419 ;
     RECT  23.076 40.099 23.094 41.419 ;
     RECT  30.528 39.289 30.546 41.419 ;
     RECT  61.815 41.323 62.19 41.419 ;
     RECT  63.252 40.939 63.99 41.419 ;
     RECT  74.664 41.405 74.682 41.419 ;
     RECT  95.796 41.323 98.622 41.419 ;
     RECT  130.356 41.341 130.374 41.419 ;
     RECT  169.815 2.413 170.097 41.419 ;
     RECT  181.62 40.297 181.71 41.419 ;
     RECT  74.664 41.419 74.79 41.449 ;
     RECT  17.784 41.227 21.402 41.453 ;
     RECT  29.415 41.323 29.79 41.453 ;
     RECT  34.815 41.377 35.118 41.453 ;
     RECT  67.215 41.377 67.518 41.453 ;
     RECT  83.124 41.413 84.474 41.453 ;
     RECT  28.476 41.341 28.494 41.467 ;
     RECT  93.276 41.413 94.518 41.467 ;
     RECT  34.815 41.453 35.097 41.485 ;
     RECT  204.084 41.069 204.354 41.485 ;
     RECT  206.856 40.945 206.874 41.512 ;
     RECT  207.615 2.413 207.897 41.512 ;
     RECT  27.936 41.467 28.494 41.513 ;
     RECT  93.276 41.467 94.59 41.513 ;
     RECT  78.015 41.341 78.354 41.521 ;
     RECT  87.192 40.441 87.462 41.521 ;
     RECT  22.32 41.419 23.094 41.549 ;
     RECT  30.528 41.419 30.906 41.549 ;
     RECT  83.232 41.453 84.474 41.549 ;
     RECT  95.796 41.419 98.73 41.549 ;
     RECT  150.48 41.419 150.498 41.549 ;
     RECT  169.815 41.419 170.442 41.549 ;
     RECT  181.62 41.419 182.43 41.549 ;
     RECT  13.215 41.341 15.714 41.597 ;
     RECT  23.94 40.405 24.822 41.611 ;
     RECT  45.615 41.377 45.918 41.611 ;
     RECT  56.415 41.377 56.718 41.611 ;
     RECT  67.215 41.453 67.497 41.611 ;
     RECT  78.015 41.521 78.642 41.611 ;
     RECT  88.776 41.131 89.154 41.611 ;
     RECT  99.615 40.441 100.602 41.611 ;
     RECT  23.904 41.611 24.822 41.648 ;
     RECT  56.304 41.611 56.718 41.648 ;
     RECT  67.104 41.611 67.497 41.648 ;
     RECT  77.904 41.611 78.642 41.648 ;
     RECT  88.704 41.611 89.154 41.648 ;
     RECT  99.504 41.611 100.602 41.648 ;
     RECT  42.876 41.419 42.894 41.659 ;
     RECT  74.664 41.449 75.15 41.693 ;
     RECT  54.828 41.419 54.846 41.707 ;
     RECT  56.415 41.648 56.718 41.707 ;
     RECT  121.14 41.117 121.497 41.707 ;
     RECT  58.716 41.707 58.734 41.719 ;
     RECT  42.804 41.659 42.894 41.755 ;
     RECT  45.504 41.611 45.918 41.755 ;
     RECT  118.656 41.419 118.674 41.755 ;
     RECT  121.14 41.707 122.31 41.755 ;
     RECT  123.264 41.377 124.398 41.755 ;
     RECT  132.015 41.117 132.297 41.755 ;
     RECT  133.056 41.413 133.866 41.755 ;
     RECT  28.476 41.513 28.494 41.789 ;
     RECT  17.784 41.453 18.897 41.791 ;
     RECT  54.72 41.707 54.846 41.791 ;
     RECT  45.504 41.755 46.35 41.881 ;
     RECT  86.904 41.521 87.462 41.881 ;
     RECT  118.584 41.755 118.818 41.881 ;
     RECT  118.584 41.881 119.394 41.885 ;
     RECT  121.14 41.755 124.398 41.885 ;
     RECT  102.024 40.945 102.546 41.909 ;
     RECT  78.015 41.648 78.642 41.917 ;
     RECT  79.92 38.713 79.938 41.917 ;
     RECT  86.652 41.881 87.462 41.917 ;
     RECT  202.032 41.069 203.238 41.917 ;
     RECT  204.084 41.485 204.534 41.917 ;
     RECT  45.072 41.881 46.35 41.933 ;
     RECT  58.716 41.719 58.806 41.944 ;
     RECT  205.344 41.251 206.082 41.947 ;
     RECT  206.856 41.512 207.897 41.947 ;
     RECT  115.38 40.829 116.097 41.953 ;
     RECT  202.032 41.917 204.534 41.953 ;
     RECT  38.736 41.881 39.33 41.981 ;
     RECT  42.768 41.755 42.93 41.981 ;
     RECT  54.72 41.791 55.458 41.981 ;
     RECT  56.415 41.707 56.754 41.981 ;
     RECT  61.815 41.419 63.99 41.981 ;
     RECT  74.664 41.693 74.79 41.981 ;
     RECT  106.596 41.323 107.442 41.981 ;
     RECT  23.94 41.648 24.822 41.989 ;
     RECT  205.344 41.947 207.897 41.989 ;
     RECT  208.908 41.215 209.826 41.989 ;
     RECT  132.015 41.755 133.866 41.995 ;
     RECT  142.815 41.117 143.097 41.995 ;
     RECT  153.615 41.117 153.897 41.995 ;
     RECT  175.215 41.117 175.497 41.995 ;
     RECT  186.015 41.117 186.297 41.995 ;
     RECT  42.768 41.981 42.894 42.017 ;
     RECT  45.615 41.933 46.35 42.017 ;
     RECT  117.828 41.917 117.846 42.025 ;
     RECT  120.384 41.117 120.402 42.025 ;
     RECT  121.14 41.885 122.418 42.025 ;
     RECT  45.615 42.017 46.206 42.029 ;
     RECT  118.62 41.885 119.394 42.029 ;
     RECT  120.384 42.025 122.418 42.029 ;
     RECT  130.356 41.419 130.554 42.029 ;
     RECT  131.832 41.995 133.866 42.029 ;
     RECT  138.528 41.419 138.546 42.029 ;
     RECT  99.615 41.648 100.602 42.043 ;
     RECT  131.832 42.029 132.297 42.053 ;
     RECT  142.632 41.995 143.097 42.053 ;
     RECT  153.432 41.995 153.897 42.053 ;
     RECT  175.032 41.995 175.497 42.053 ;
     RECT  185.832 41.995 186.297 42.053 ;
     RECT  90.468 40.981 90.558 42.061 ;
     RECT  91.44 40.981 91.458 42.061 ;
     RECT  194.904 39.793 194.922 42.061 ;
     RECT  54.828 41.981 55.458 42.077 ;
     RECT  58.716 41.944 58.842 42.077 ;
     RECT  74.772 41.981 74.79 42.077 ;
     RECT  106.704 41.981 107.442 42.077 ;
     RECT  120.384 42.029 122.202 42.077 ;
     RECT  131.904 42.053 132.297 42.077 ;
     RECT  142.704 42.053 143.097 42.077 ;
     RECT  153.504 42.053 153.897 42.077 ;
     RECT  175.104 42.053 175.497 42.077 ;
     RECT  185.904 42.053 186.297 42.077 ;
     RECT  118.764 42.029 119.394 42.125 ;
     RECT  8.856 39.793 8.874 42.151 ;
     RECT  9.72 41.021 9.738 42.151 ;
     RECT  83.415 41.549 84.474 42.151 ;
     RECT  67.215 41.648 67.497 42.235 ;
     RECT  125.676 41.881 125.694 42.331 ;
     RECT  126.615 2.413 126.897 42.331 ;
     RECT  17.712 41.791 18.897 42.421 ;
     RECT  10.476 41.917 10.494 42.427 ;
     RECT  17.064 42.421 18.897 42.427 ;
     RECT  19.656 41.453 21.402 42.427 ;
     RECT  91.368 42.061 91.458 42.457 ;
     RECT  119.376 42.125 119.394 42.457 ;
     RECT  137.415 2.413 137.697 42.457 ;
     RECT  17.064 42.427 21.402 42.475 ;
     RECT  78.015 41.917 79.938 42.475 ;
     RECT  91.332 42.457 91.458 42.493 ;
     RECT  107.316 42.077 107.442 42.493 ;
     RECT  13.215 41.597 15.678 42.52 ;
     RECT  13.215 42.52 15.75 42.557 ;
     RECT  6.372 40.441 6.606 42.565 ;
     RECT  58.68 42.529 58.698 42.565 ;
     RECT  90.144 42.061 90.558 42.565 ;
     RECT  186.015 42.077 186.297 42.565 ;
     RECT  67.215 42.235 67.554 42.571 ;
     RECT  16.812 42.475 21.402 42.601 ;
     RECT  86.652 41.917 87.786 42.601 ;
     RECT  16.632 42.601 21.402 42.605 ;
     RECT  86.652 42.601 88.002 42.629 ;
     RECT  91.332 42.493 91.494 42.629 ;
     RECT  89.928 42.565 90.558 42.719 ;
     RECT  91.332 42.629 91.458 42.719 ;
     RECT  63.252 41.981 63.99 42.727 ;
     RECT  63.252 42.727 64.35 42.791 ;
     RECT  8.856 42.151 9.738 42.799 ;
     RECT  10.476 42.427 10.854 42.799 ;
     RECT  45.615 42.029 45.897 42.961 ;
     RECT  205.344 41.989 209.826 42.961 ;
     RECT  210.78 41.413 211.95 42.961 ;
     RECT  33.444 40.873 33.462 42.989 ;
     RECT  8.856 42.799 10.854 42.997 ;
     RECT  19.656 42.605 21.402 42.997 ;
     RECT  22.32 41.549 22.338 42.997 ;
     RECT  26.388 42.331 26.406 42.997 ;
     RECT  27.54 41.953 27.558 42.997 ;
     RECT  140.724 40.405 140.742 42.997 ;
     RECT  201.564 41.953 204.534 42.997 ;
     RECT  130.356 42.029 130.374 43.003 ;
     RECT  119.376 42.457 119.466 43.033 ;
     RECT  26.388 42.997 27.558 43.037 ;
     RECT  85.5 42.727 85.518 43.061 ;
     RECT  7.815 2.413 8.097 43.069 ;
     RECT  8.856 42.997 11.97 43.069 ;
     RECT  29.415 41.453 29.697 43.069 ;
     RECT  30.528 41.549 30.546 43.069 ;
     RECT  205.344 42.961 211.95 43.069 ;
     RECT  28.62 42.961 28.638 43.085 ;
     RECT  45.615 42.961 46.026 43.105 ;
     RECT  102.024 41.909 102.474 43.105 ;
     RECT  103.212 42.421 103.23 43.105 ;
     RECT  26.388 43.037 26.802 43.133 ;
     RECT  60.264 40.411 60.282 43.141 ;
     RECT  93.276 41.513 94.497 43.141 ;
     RECT  188.28 42.493 188.298 43.141 ;
     RECT  29.415 43.069 30.546 43.181 ;
     RECT  23.94 41.989 25.074 43.231 ;
     RECT  27.54 43.037 27.558 43.231 ;
     RECT  45.432 43.105 46.026 43.231 ;
     RECT  45.036 43.231 46.026 43.259 ;
     RECT  107.316 42.493 107.694 43.267 ;
     RECT  23.904 43.231 25.074 43.277 ;
     RECT  27.54 43.231 28.134 43.277 ;
     RECT  45.036 43.259 45.897 43.277 ;
     RECT  29.415 43.181 29.697 43.291 ;
     RECT  69.408 38.551 69.426 43.291 ;
     RECT  199.836 40.837 200.394 43.303 ;
     RECT  29.232 43.291 29.697 43.331 ;
     RECT  104.976 40.909 105.822 43.387 ;
     RECT  148.215 2.413 148.497 43.387 ;
     RECT  149.328 39.865 149.346 43.387 ;
     RECT  153.615 42.077 153.897 43.387 ;
     RECT  154.764 42.961 154.782 43.387 ;
     RECT  201.492 42.997 204.534 43.411 ;
     RECT  205.344 43.069 212.058 43.411 ;
     RECT  139.392 39.289 139.41 43.501 ;
     RECT  140.688 42.997 140.742 43.501 ;
     RECT  136.8 42.457 137.697 43.531 ;
     RECT  130.104 43.003 130.374 43.537 ;
     RECT  132.015 42.077 132.297 43.537 ;
     RECT  133.056 42.029 133.866 43.537 ;
     RECT  150.48 43.387 150.498 43.537 ;
     RECT  164.016 40.837 164.697 43.537 ;
     RECT  169.815 41.549 170.097 43.537 ;
     RECT  175.215 42.077 175.497 43.537 ;
     RECT  181.62 41.549 181.71 43.537 ;
     RECT  194.652 42.061 194.922 43.537 ;
     RECT  139.392 43.501 140.742 43.579 ;
     RECT  146.484 43.387 146.502 43.579 ;
     RECT  7.815 43.069 11.97 43.609 ;
     RECT  130.104 43.537 130.554 43.609 ;
     RECT  139.176 43.579 140.742 43.609 ;
     RECT  169.815 43.537 170.442 43.609 ;
     RECT  181.62 43.537 182.43 43.609 ;
     RECT  146.484 43.579 146.61 43.613 ;
     RECT  148.215 43.387 149.346 43.613 ;
     RECT  91.368 42.719 91.458 43.627 ;
     RECT  164.016 43.537 164.754 43.637 ;
     RECT  175.215 43.537 175.554 43.637 ;
     RECT  2.415 2.413 2.697 43.645 ;
     RECT  142.815 42.077 143.097 43.645 ;
     RECT  199.8 43.303 200.394 43.645 ;
     RECT  99.615 42.043 100.638 43.672 ;
     RECT  120.384 42.077 120.402 43.672 ;
     RECT  121.14 42.077 122.202 43.672 ;
     RECT  132.015 43.537 133.866 43.672 ;
     RECT  142.815 43.645 143.154 43.672 ;
     RECT  153.615 43.387 154.782 43.672 ;
     RECT  175.215 43.637 175.497 43.672 ;
     RECT  186.015 42.565 186.498 43.672 ;
     RECT  131.904 43.672 133.866 43.673 ;
     RECT  3.996 43.645 4.014 43.681 ;
     RECT  120.384 43.672 122.202 43.681 ;
     RECT  82.62 43.609 82.638 43.709 ;
     RECT  138.564 43.609 140.742 43.709 ;
     RECT  169.815 43.609 170.514 43.709 ;
     RECT  181.62 43.609 182.502 43.709 ;
     RECT  6.372 42.565 6.93 43.765 ;
     RECT  3.528 43.681 4.086 43.771 ;
     RECT  4.86 43.681 4.878 43.771 ;
     RECT  135.504 41.251 135.522 43.771 ;
     RECT  136.548 43.531 137.697 43.771 ;
     RECT  152.568 43.579 152.586 43.771 ;
     RECT  48.42 43.339 48.438 43.799 ;
     RECT  138.636 43.709 140.742 43.799 ;
     RECT  142.704 43.672 143.154 43.799 ;
     RECT  151.884 43.771 152.586 43.799 ;
     RECT  153.504 43.672 154.782 43.805 ;
     RECT  1.728 43.645 2.697 43.807 ;
     RECT  3.528 43.771 4.878 43.807 ;
     RECT  180.615 2.413 180.897 43.807 ;
     RECT  181.62 43.709 182.43 43.807 ;
     RECT  151.884 43.799 151.902 43.808 ;
     RECT  130.104 43.609 130.626 43.835 ;
     RECT  5.976 43.765 6.93 43.843 ;
     RECT  7.815 43.609 12.114 43.843 ;
     RECT  77.148 41.131 77.166 43.843 ;
     RECT  78.015 42.475 80.55 43.843 ;
     RECT  86.904 42.629 88.002 43.867 ;
     RECT  7.815 43.843 12.294 43.879 ;
     RECT  5.688 43.843 6.93 43.901 ;
     RECT  47.592 43.807 47.61 43.901 ;
     RECT  135.504 43.771 137.697 43.901 ;
     RECT  146.592 43.613 146.61 43.901 ;
     RECT  148.215 43.613 148.518 43.901 ;
     RECT  1.728 43.807 4.878 43.951 ;
     RECT  7.668 43.879 12.294 43.951 ;
     RECT  13.215 42.557 15.678 43.951 ;
     RECT  102.024 43.105 103.23 44.059 ;
     RECT  199.8 43.645 200.43 44.113 ;
     RECT  201.492 43.411 212.058 44.113 ;
     RECT  168.12 38.551 168.138 44.149 ;
     RECT  117.756 42.025 117.846 44.155 ;
     RECT  118.728 43.033 119.466 44.155 ;
     RECT  23.94 43.277 25.074 44.203 ;
     RECT  45.615 43.277 45.897 44.203 ;
     RECT  56.415 41.981 56.697 44.203 ;
     RECT  86.832 43.867 88.002 44.203 ;
     RECT  88.776 41.648 89.154 44.203 ;
     RECT  123.264 41.885 124.398 44.203 ;
     RECT  6.372 43.901 6.93 44.221 ;
     RECT  7.668 43.951 15.678 44.221 ;
     RECT  86.832 44.203 89.154 44.249 ;
     RECT  131.904 43.673 132.297 44.249 ;
     RECT  150.48 43.537 150.858 44.249 ;
     RECT  153.504 43.805 153.897 44.249 ;
     RECT  169.815 43.709 170.442 44.249 ;
     RECT  175.104 43.672 175.497 44.249 ;
     RECT  180.615 43.807 182.43 44.249 ;
     RECT  185.904 43.672 186.498 44.249 ;
     RECT  194.364 43.537 194.922 44.249 ;
     RECT  29.415 43.331 29.697 44.299 ;
     RECT  40.215 2.413 40.497 44.299 ;
     RECT  51.015 39.317 51.297 44.299 ;
     RECT  61.815 41.981 62.097 44.299 ;
     RECT  70.488 42.601 70.506 44.299 ;
     RECT  130.464 43.835 130.626 44.347 ;
     RECT  198.36 44.203 198.378 44.381 ;
     RECT  40.104 44.299 40.497 44.383 ;
     RECT  109.548 40.651 111.114 44.383 ;
     RECT  95.796 41.549 98.37 44.419 ;
     RECT  190.764 39.631 191.697 44.419 ;
     RECT  93.276 43.141 94.554 44.443 ;
     RECT  95.544 44.419 98.37 44.443 ;
     RECT  123.264 44.203 124.902 44.443 ;
     RECT  125.676 42.331 126.897 44.443 ;
     RECT  39.708 44.383 40.497 44.491 ;
     RECT  26.388 43.133 26.406 44.581 ;
     RECT  29.304 44.299 29.697 44.581 ;
     RECT  30.528 43.181 30.546 44.581 ;
     RECT  34.272 41.485 35.097 44.581 ;
     RECT  39.708 44.491 40.842 44.581 ;
     RECT  45.504 44.203 45.897 44.581 ;
     RECT  50.904 44.299 51.297 44.581 ;
     RECT  55.44 42.077 55.458 44.581 ;
     RECT  56.304 44.203 56.697 44.581 ;
     RECT  58.284 42.565 58.698 44.581 ;
     RECT  61.704 44.299 62.097 44.581 ;
     RECT  63.252 42.791 63.99 44.581 ;
     RECT  66.528 42.571 67.554 44.581 ;
     RECT  72.615 41.405 72.897 44.581 ;
     RECT  0.108 44.185 0.126 44.587 ;
     RECT  133.056 43.673 133.866 44.587 ;
     RECT  26.388 44.581 26.802 44.617 ;
     RECT  148.215 43.901 148.497 44.617 ;
     RECT  39.6 44.581 40.842 44.621 ;
     RECT  142.704 43.799 143.097 44.653 ;
     RECT  25.884 44.617 26.802 44.689 ;
     RECT  27.54 43.277 27.558 44.689 ;
     RECT  30.528 44.581 30.798 44.689 ;
     RECT  42.768 43.771 42.786 44.689 ;
     RECT  46.764 44.581 46.782 44.689 ;
     RECT  58.284 44.581 58.734 44.689 ;
     RECT  70.488 44.299 70.722 44.689 ;
     RECT  107.028 43.267 107.694 44.689 ;
     RECT  115.092 41.953 116.097 44.689 ;
     RECT  195.66 40.171 197.19 44.689 ;
     RECT  0.108 44.587 0.558 44.717 ;
     RECT  1.728 43.951 5.598 44.717 ;
     RECT  34.272 44.581 35.154 44.717 ;
     RECT  40.104 44.621 40.842 44.717 ;
     RECT  42.768 44.689 42.858 44.717 ;
     RECT  45.504 44.581 45.954 44.717 ;
     RECT  46.764 44.689 46.854 44.717 ;
     RECT  50.904 44.581 51.354 44.717 ;
     RECT  54.72 44.581 55.458 44.717 ;
     RECT  56.304 44.581 56.754 44.717 ;
     RECT  66.528 44.581 67.59 44.717 ;
     RECT  114.984 44.689 116.097 44.725 ;
     RECT  72.615 44.581 72.954 44.761 ;
     RECT  135.504 43.901 135.522 44.761 ;
     RECT  133.056 44.587 134.55 44.765 ;
     RECT  74.664 44.635 74.682 44.779 ;
     RECT  42.84 44.717 42.858 44.789 ;
     RECT  46.836 44.717 46.854 44.789 ;
     RECT  54.792 44.717 55.458 44.789 ;
     RECT  58.284 44.689 58.806 44.789 ;
     RECT  61.704 44.581 63.99 44.789 ;
     RECT  70.488 44.689 70.794 44.789 ;
     RECT  40.104 44.717 40.554 44.813 ;
     RECT  45.504 44.717 45.918 44.813 ;
     RECT  109.548 44.383 111.474 44.827 ;
     RECT  2.304 44.717 5.598 44.851 ;
     RECT  6.372 44.221 15.678 44.851 ;
     RECT  19.656 42.997 22.338 44.851 ;
     RECT  23.076 41.549 23.094 44.851 ;
     RECT  38.844 44.761 38.862 44.851 ;
     RECT  99.504 43.672 100.638 44.887 ;
     RECT  74.664 44.779 74.79 44.909 ;
     RECT  109.476 44.827 111.474 44.915 ;
     RECT  104.364 43.387 105.822 44.923 ;
     RECT  106.596 44.689 107.694 44.923 ;
     RECT  142.704 44.653 143.55 44.923 ;
     RECT  40.215 44.813 40.554 44.951 ;
     RECT  23.904 44.203 25.074 44.995 ;
     RECT  25.884 44.689 27.558 44.995 ;
     RECT  130.464 44.347 130.806 44.995 ;
     RECT  132.015 44.249 132.297 44.995 ;
     RECT  93.276 44.443 98.37 45.019 ;
     RECT  16.632 42.605 16.65 45.031 ;
     RECT  29.304 44.581 29.754 45.031 ;
     RECT  16.632 45.031 16.722 45.059 ;
     RECT  29.232 45.031 29.754 45.115 ;
     RECT  29.232 45.115 29.79 45.121 ;
     RECT  30.528 44.689 30.87 45.121 ;
     RECT  99.468 44.887 100.638 45.163 ;
     RECT  50.904 44.717 51.318 45.193 ;
     RECT  148.14 44.617 148.497 45.193 ;
     RECT  29.232 45.121 30.87 45.211 ;
     RECT  38.772 44.851 38.862 45.211 ;
     RECT  93.276 45.019 98.73 45.211 ;
     RECT  99.468 45.163 101.25 45.211 ;
     RECT  29.232 45.211 30.906 45.221 ;
     RECT  34.272 44.717 35.118 45.245 ;
     RECT  38.772 45.211 38.898 45.245 ;
     RECT  40.215 44.951 40.518 45.245 ;
     RECT  50.436 45.193 51.318 45.245 ;
     RECT  104.364 44.923 107.694 45.265 ;
     RECT  23.904 44.995 27.558 45.301 ;
     RECT  44.784 45.229 44.802 45.341 ;
     RECT  83.415 42.151 84.546 45.355 ;
     RECT  86.832 44.249 88.002 45.355 ;
     RECT  88.776 44.249 89.154 45.355 ;
     RECT  23.904 45.301 28.242 45.389 ;
     RECT  30.528 45.221 30.906 45.389 ;
     RECT  38.88 45.245 38.898 45.389 ;
     RECT  42.876 45.211 42.894 45.389 ;
     RECT  46.872 45.211 46.89 45.389 ;
     RECT  93.276 45.211 101.25 45.403 ;
     RECT  102.024 44.059 103.626 45.403 ;
     RECT  61.704 44.789 62.097 45.419 ;
     RECT  83.304 45.355 84.546 45.419 ;
     RECT  72.504 44.761 72.954 45.427 ;
     RECT  195.66 44.689 197.514 45.427 ;
     RECT  93.276 45.403 103.626 45.455 ;
     RECT  17.712 42.605 18.897 45.463 ;
     RECT  19.656 44.851 23.094 45.463 ;
     RECT  99.468 45.455 103.626 45.485 ;
     RECT  104.364 45.265 107.766 45.491 ;
     RECT  82.62 45.463 82.638 45.499 ;
     RECT  186.015 44.249 186.498 45.499 ;
     RECT  72.504 45.427 73.494 45.535 ;
     RECT  93.276 45.455 98.73 45.535 ;
     RECT  1.152 45.163 1.206 45.547 ;
     RECT  109.584 44.915 111.474 45.563 ;
     RECT  69.408 43.291 69.462 45.571 ;
     RECT  188.28 43.141 188.55 45.571 ;
     RECT  130.464 44.995 132.297 45.643 ;
     RECT  133.056 44.765 133.866 45.643 ;
     RECT  135.396 44.761 135.522 45.643 ;
     RECT  45.615 44.813 45.918 45.661 ;
     RECT  55.44 44.789 55.458 45.661 ;
     RECT  56.304 44.717 56.697 45.661 ;
     RECT  135.252 45.643 135.522 45.661 ;
     RECT  177.732 42.601 177.75 45.661 ;
     RECT  130.464 45.643 133.866 45.689 ;
     RECT  135.252 45.661 135.63 45.691 ;
     RECT  2.304 44.851 15.678 45.725 ;
     RECT  134.604 45.691 135.63 45.725 ;
     RECT  139.176 43.799 140.742 45.739 ;
     RECT  150.84 44.249 150.858 45.739 ;
     RECT  169.815 44.249 170.097 45.739 ;
     RECT  180.615 44.249 181.71 45.739 ;
     RECT  194.58 44.249 194.922 45.739 ;
     RECT  42.768 45.661 42.858 45.761 ;
     RECT  45.615 45.661 45.954 45.761 ;
     RECT  68.436 39.307 68.454 45.769 ;
     RECT  69.228 45.571 69.462 45.769 ;
     RECT  162.36 41.215 162.63 45.769 ;
     RECT  114.768 44.725 116.334 45.787 ;
     RECT  117.756 44.155 119.466 45.787 ;
     RECT  145.764 44.311 145.782 45.787 ;
     RECT  45.615 45.761 45.897 45.805 ;
     RECT  147.564 45.193 148.497 45.805 ;
     RECT  42.84 45.761 42.858 45.833 ;
     RECT  120.384 43.681 122.274 45.835 ;
     RECT  123.264 44.443 126.897 45.835 ;
     RECT  2.376 45.725 15.678 45.841 ;
     RECT  16.704 45.059 16.722 45.841 ;
     RECT  61.815 45.419 62.097 45.841 ;
     RECT  93.06 45.535 98.73 45.869 ;
     RECT  135.396 45.725 135.63 45.869 ;
     RECT  138.528 45.739 140.742 45.869 ;
     RECT  150.48 45.739 150.858 45.869 ;
     RECT  169.815 45.739 170.442 45.869 ;
     RECT  180.615 45.739 182.43 45.869 ;
     RECT  194.364 45.739 194.922 45.869 ;
     RECT  17.712 45.463 23.094 45.931 ;
     RECT  23.904 45.389 26.406 45.931 ;
     RECT  117.396 45.787 119.466 45.979 ;
     RECT  0.108 44.717 0.126 45.995 ;
     RECT  93.06 45.869 98.694 45.995 ;
     RECT  114.588 45.787 116.334 46.013 ;
     RECT  17.712 45.931 26.406 46.039 ;
     RECT  101.448 45.485 103.626 46.039 ;
     RECT  104.364 45.491 107.73 46.039 ;
     RECT  17.676 46.039 26.406 46.075 ;
     RECT  193.392 43.105 193.41 46.075 ;
     RECT  2.376 45.841 16.722 46.111 ;
     RECT  17.604 46.075 26.406 46.111 ;
     RECT  36.54 40.261 36.558 46.111 ;
     RECT  75.672 43.303 75.69 46.111 ;
     RECT  61.815 45.841 62.37 46.123 ;
     RECT  68.436 45.769 69.462 46.123 ;
     RECT  89.928 42.719 90.486 46.171 ;
     RECT  34.272 45.245 35.097 46.201 ;
     RECT  56.304 45.661 56.754 46.201 ;
     RECT  2.376 46.111 26.406 46.219 ;
     RECT  36.36 46.111 36.558 46.229 ;
     RECT  1.152 45.547 1.242 46.265 ;
     RECT  2.376 46.219 26.658 46.265 ;
     RECT  99.468 45.485 100.638 46.267 ;
     RECT  101.448 46.039 107.73 46.267 ;
     RECT  45.504 45.805 45.897 46.273 ;
     RECT  128.34 40.405 128.682 46.273 ;
     RECT  36.612 46.237 36.63 46.309 ;
     RECT  164.016 43.637 164.697 46.309 ;
     RECT  36.612 46.309 36.702 46.337 ;
     RECT  56.304 46.201 57.258 46.337 ;
     RECT  72.216 45.535 73.494 46.345 ;
     RECT  2.415 46.265 26.658 46.409 ;
     RECT  30.528 45.389 30.546 46.411 ;
     RECT  61.815 46.123 62.442 46.411 ;
     RECT  63.252 44.789 63.99 46.411 ;
     RECT  50.436 45.245 51.297 46.471 ;
     RECT  34.272 46.201 35.55 46.499 ;
     RECT  36.684 46.337 36.702 46.499 ;
     RECT  61.56 46.411 63.99 46.499 ;
     RECT  5.364 46.409 26.658 46.507 ;
     RECT  27.54 45.389 28.242 46.507 ;
     RECT  29.232 45.221 29.697 46.507 ;
     RECT  30.528 46.411 31.05 46.507 ;
     RECT  40.215 45.245 40.497 46.507 ;
     RECT  45.108 46.273 45.897 46.507 ;
     RECT  66.528 44.717 67.554 46.507 ;
     RECT  68.436 46.123 69.57 46.507 ;
     RECT  130.464 45.689 132.297 46.507 ;
     RECT  1.188 46.265 1.242 46.535 ;
     RECT  2.415 46.409 4.518 46.535 ;
     RECT  99.468 46.267 107.73 46.543 ;
     RECT  38.988 46.507 39.006 46.579 ;
     RECT  75.6 46.111 75.69 46.579 ;
     RECT  177.732 45.661 178.47 46.579 ;
     RECT  29.232 46.507 31.05 46.589 ;
     RECT  34.272 46.499 35.478 46.589 ;
     RECT  58.284 44.789 58.698 46.603 ;
     RECT  70.488 44.789 70.506 46.603 ;
     RECT  72.216 46.345 73.89 46.603 ;
     RECT  74.664 46.459 74.682 46.603 ;
     RECT  82.296 45.499 82.638 46.603 ;
     RECT  83.376 45.419 84.546 46.603 ;
     RECT  38.844 46.579 39.006 46.607 ;
     RECT  40.215 46.507 40.806 46.607 ;
     RECT  29.232 46.589 30.978 46.637 ;
     RECT  1.224 46.535 1.242 46.643 ;
     RECT  50.436 46.471 51.678 46.679 ;
     RECT  30.528 46.637 30.978 46.733 ;
     RECT  38.844 46.607 38.97 46.733 ;
     RECT  46.944 46.603 46.962 46.733 ;
     RECT  58.284 46.603 58.914 46.733 ;
     RECT  61.704 46.499 63.99 46.741 ;
     RECT  82.296 46.603 84.546 46.741 ;
     RECT  86.832 45.355 89.154 46.747 ;
     RECT  109.584 45.563 110.697 46.747 ;
     RECT  111.456 45.563 111.474 46.747 ;
     RECT  2.415 46.535 4.23 46.769 ;
     RECT  4.032 46.769 4.23 46.781 ;
     RECT  91.368 43.627 92.142 46.795 ;
     RECT  93.06 45.995 98.37 46.795 ;
     RECT  2.415 46.769 2.97 46.805 ;
     RECT  4.032 46.781 4.05 46.805 ;
     RECT  86.796 46.747 89.154 46.843 ;
     RECT  162.108 45.769 162.63 46.849 ;
     RECT  158.148 45.391 158.166 46.885 ;
     RECT  159.015 2.413 159.297 46.885 ;
     RECT  38.844 46.733 38.898 46.891 ;
     RECT  42.984 46.603 43.002 46.891 ;
     RECT  72.216 46.603 74.79 46.921 ;
     RECT  75.6 46.579 75.942 46.921 ;
     RECT  37.008 46.507 37.026 46.925 ;
     RECT  40.215 46.607 40.698 46.987 ;
     RECT  127.944 46.273 128.682 47.035 ;
     RECT  129.996 46.507 132.297 47.035 ;
     RECT  134.604 45.725 134.622 47.047 ;
     RECT  135.396 45.869 135.414 47.047 ;
     RECT  33.372 46.747 33.39 47.083 ;
     RECT  89.928 46.171 90.63 47.119 ;
     RECT  91.368 46.795 98.37 47.119 ;
     RECT  42.768 46.891 43.002 47.131 ;
     RECT  70.488 46.603 70.722 47.131 ;
     RECT  127.944 47.035 132.297 47.131 ;
     RECT  133.056 45.689 133.866 47.131 ;
     RECT  139.176 45.869 140.742 47.131 ;
     RECT  158.148 46.885 159.297 47.147 ;
     RECT  162.108 46.849 163.242 47.147 ;
     RECT  114.768 46.013 116.334 47.155 ;
     RECT  117.288 45.979 119.466 47.155 ;
     RECT  30.528 46.733 30.906 47.165 ;
     RECT  34.272 46.589 35.406 47.165 ;
     RECT  139.176 47.131 140.85 47.183 ;
     RECT  42.768 47.131 43.074 47.261 ;
     RECT  46.872 47.131 46.89 47.261 ;
     RECT  58.284 46.733 58.842 47.261 ;
     RECT  70.488 47.131 70.83 47.261 ;
     RECT  86.652 46.843 89.154 47.275 ;
     RECT  180.615 45.869 181.71 47.281 ;
     RECT  33.372 47.083 33.534 47.309 ;
     RECT  34.272 47.165 35.298 47.309 ;
     RECT  33.372 47.309 33.39 47.315 ;
     RECT  194.58 45.869 194.922 47.323 ;
     RECT  5.364 46.507 28.242 47.345 ;
     RECT  54.72 45.661 55.458 47.416 ;
     RECT  56.304 46.337 56.898 47.416 ;
     RECT  48.276 46.075 48.294 47.425 ;
     RECT  54.72 47.416 56.898 47.425 ;
     RECT  54.72 47.425 57.042 47.453 ;
     RECT  194.364 47.323 194.922 47.453 ;
     RECT  45.108 46.507 46.098 47.461 ;
     RECT  56.304 47.453 57.042 47.461 ;
     RECT  34.344 47.309 35.298 47.489 ;
     RECT  38.772 46.891 38.898 47.489 ;
     RECT  40.104 46.987 40.698 47.501 ;
     RECT  56.304 47.461 57.114 47.501 ;
     RECT  61.704 46.741 64.242 47.501 ;
     RECT  56.415 47.501 57.114 47.579 ;
     RECT  77.148 43.843 80.55 47.587 ;
     RECT  194.472 47.453 194.922 47.597 ;
     RECT  86.652 47.275 89.19 47.659 ;
     RECT  89.928 47.119 98.37 47.659 ;
     RECT  189.684 47.425 189.702 47.659 ;
     RECT  99.468 46.543 108.198 47.695 ;
     RECT  29.232 46.637 29.79 47.731 ;
     RECT  30.528 47.165 30.87 47.731 ;
     RECT  85.824 44.395 85.842 47.731 ;
     RECT  86.652 47.659 98.37 47.731 ;
     RECT  38.808 47.489 38.898 47.755 ;
     RECT  85.824 47.731 98.37 47.837 ;
     RECT  5.58 47.345 28.242 47.849 ;
     RECT  29.232 47.731 30.87 47.849 ;
     RECT  42.768 47.261 42.822 47.849 ;
     RECT  45.108 47.461 46.818 47.849 ;
     RECT  70.488 47.261 70.758 47.849 ;
     RECT  5.58 47.849 26.802 47.885 ;
     RECT  38.808 47.755 39.006 47.885 ;
     RECT  40.215 47.501 40.698 47.885 ;
     RECT  42.768 47.849 42.786 47.885 ;
     RECT  46.764 47.849 46.782 47.885 ;
     RECT  50.436 46.679 51.498 47.885 ;
     RECT  54.72 47.453 55.458 47.885 ;
     RECT  56.415 47.579 57.042 47.885 ;
     RECT  61.815 47.501 64.242 47.885 ;
     RECT  66.528 46.507 69.57 47.885 ;
     RECT  77.148 47.587 80.946 47.885 ;
     RECT  91.116 47.837 98.37 47.947 ;
     RECT  99.396 47.695 108.198 47.947 ;
     RECT  120.384 45.835 126.897 48.001 ;
     RECT  30.528 47.849 30.798 48.029 ;
     RECT  38.808 47.885 38.934 48.029 ;
     RECT  157.356 46.651 157.374 48.091 ;
     RECT  38.808 48.029 38.826 48.125 ;
     RECT  48.132 47.425 48.294 48.127 ;
     RECT  120.384 48.001 127.134 48.139 ;
     RECT  127.944 47.131 133.866 48.139 ;
     RECT  3.492 47.899 3.51 48.155 ;
     RECT  195.66 45.427 197.586 48.163 ;
     RECT  177.48 46.579 178.47 48.199 ;
     RECT  82.296 46.741 84.618 48.235 ;
     RECT  112.32 40.829 113.706 48.235 ;
     RECT  4.5 48.163 4.518 48.263 ;
     RECT  109.584 46.747 111.474 48.271 ;
     RECT  77.364 47.885 80.946 48.397 ;
     RECT  82.008 48.235 84.618 48.397 ;
     RECT  134.604 47.047 135.414 48.427 ;
     RECT  199.8 44.113 212.058 48.433 ;
     RECT  139.176 47.183 140.706 48.469 ;
     RECT  150.84 45.869 150.858 48.469 ;
     RECT  162.108 47.147 162.126 48.469 ;
     RECT  29.232 47.849 29.79 48.523 ;
     RECT  34.704 47.489 35.298 48.523 ;
     RECT  40.215 47.885 40.59 48.523 ;
     RECT  56.415 47.885 56.79 48.523 ;
     RECT  58.284 47.261 58.806 48.523 ;
     RECT  153.615 44.249 153.897 48.523 ;
     RECT  175.215 44.249 175.497 48.523 ;
     RECT  61.815 47.885 62.514 48.541 ;
     RECT  168.084 44.149 168.138 48.541 ;
     RECT  29.088 48.523 29.79 48.569 ;
     RECT  34.704 48.523 35.91 48.569 ;
     RECT  39.924 48.523 40.59 48.569 ;
     RECT  138.528 48.469 140.706 48.569 ;
     RECT  150.48 48.469 150.858 48.569 ;
     RECT  162.108 48.469 162.486 48.569 ;
     RECT  175.104 48.523 175.497 48.569 ;
     RECT  5.58 47.885 26.73 48.659 ;
     RECT  60.12 43.141 60.282 48.667 ;
     RECT  58.284 48.523 58.914 48.701 ;
     RECT  149.328 43.613 149.346 48.703 ;
     RECT  150.084 48.667 150.102 48.703 ;
     RECT  153.504 48.523 153.897 48.703 ;
     RECT  85.824 47.837 90.162 48.739 ;
     RECT  91.116 47.947 108.198 48.739 ;
     RECT  5.58 48.659 9.45 48.803 ;
     RECT  10.224 48.659 26.73 48.803 ;
     RECT  53.1 48.703 53.118 48.803 ;
     RECT  77.364 48.397 84.618 48.811 ;
     RECT  85.824 48.739 108.198 48.811 ;
     RECT  184.284 46.111 184.302 48.811 ;
     RECT  77.364 48.811 108.198 48.839 ;
     RECT  54.792 47.885 55.458 48.901 ;
     RECT  56.304 48.523 56.79 48.901 ;
     RECT  61.704 48.541 62.514 48.901 ;
     RECT  190.476 44.419 191.697 48.907 ;
     RECT  45.108 47.849 45.99 48.937 ;
     RECT  46.764 48.775 46.782 48.937 ;
     RECT  161.208 47.083 161.226 48.937 ;
     RECT  54.792 48.901 57.042 48.941 ;
     RECT  61.56 48.901 62.514 48.941 ;
     RECT  45.108 48.937 46.782 48.965 ;
     RECT  48.132 48.127 48.474 48.965 ;
     RECT  68.436 47.885 69.57 48.973 ;
     RECT  70.488 47.849 70.506 48.973 ;
     RECT  5.58 48.803 9.414 49.003 ;
     RECT  48.276 48.965 48.474 49.003 ;
     RECT  77.364 48.839 98.622 49.003 ;
     RECT  99.396 48.839 108.198 49.003 ;
     RECT  108.972 48.271 111.474 49.003 ;
     RECT  114.768 47.155 119.466 49.003 ;
     RECT  120.384 48.139 133.866 49.003 ;
     RECT  45.108 48.965 46.35 49.037 ;
     RECT  99.396 49.003 111.474 49.037 ;
     RECT  190.476 48.907 191.79 49.037 ;
     RECT  53.028 48.811 53.046 49.051 ;
     RECT  54.792 48.941 55.458 49.051 ;
     RECT  61.815 48.941 62.514 49.051 ;
     RECT  63.252 47.885 64.242 49.051 ;
     RECT  66.528 47.885 67.59 49.051 ;
     RECT  68.436 48.973 70.506 49.051 ;
     RECT  169.815 45.869 170.097 49.081 ;
     RECT  194.58 47.597 194.922 49.081 ;
     RECT  33.192 49.003 33.21 49.099 ;
     RECT  108.828 49.037 111.474 49.133 ;
     RECT  72.216 46.921 75.942 49.147 ;
     RECT  29.232 48.569 29.79 49.171 ;
     RECT  30.528 48.029 30.546 49.171 ;
     RECT  199.512 48.433 212.058 49.171 ;
     RECT  10.476 48.803 26.73 49.195 ;
     RECT  27.54 47.849 28.242 49.195 ;
     RECT  65.196 40.891 65.214 49.195 ;
     RECT  29.232 49.171 30.546 49.229 ;
     RECT  33.084 49.099 33.21 49.229 ;
     RECT  48.276 49.003 49.158 49.229 ;
     RECT  52.992 49.051 53.046 49.229 ;
     RECT  108.864 49.133 111.474 49.229 ;
     RECT  114.768 49.003 133.866 49.235 ;
     RECT  30.528 49.229 30.546 49.243 ;
     RECT  42.768 49.051 42.786 49.243 ;
     RECT  50.436 47.885 51.39 49.279 ;
     RECT  144.54 42.529 144.558 49.279 ;
     RECT  194.364 49.081 194.922 49.307 ;
     RECT  40.215 48.569 40.59 49.315 ;
     RECT  133.344 49.235 133.866 49.315 ;
     RECT  134.604 48.427 135.594 49.315 ;
     RECT  139.176 48.569 140.706 49.339 ;
     RECT  3.636 49.003 3.654 49.351 ;
     RECT  50.436 49.279 51.462 49.421 ;
     RECT  77.04 49.003 98.622 49.421 ;
     RECT  2.415 46.805 2.697 49.441 ;
     RECT  3.636 49.351 4.698 49.441 ;
     RECT  5.472 49.003 9.414 49.441 ;
     RECT  77.04 49.421 98.406 49.441 ;
     RECT  154.764 43.805 154.782 49.477 ;
     RECT  168.084 48.541 168.21 49.477 ;
     RECT  108.972 49.229 111.474 49.483 ;
     RECT  112.284 48.235 113.706 49.483 ;
     RECT  199.296 49.171 212.058 49.513 ;
     RECT  138.528 49.339 140.706 49.517 ;
     RECT  194.58 49.307 194.922 49.531 ;
     RECT  195.66 48.163 197.658 49.531 ;
     RECT  76.968 49.441 98.406 49.549 ;
     RECT  10.476 49.195 28.242 49.579 ;
     RECT  133.344 49.315 135.594 49.579 ;
     RECT  3.636 49.441 9.414 49.585 ;
     RECT  30.528 49.243 30.798 49.675 ;
     RECT  37.044 49.003 37.062 49.675 ;
     RECT  58.284 48.701 58.698 49.675 ;
     RECT  29.232 49.229 29.79 49.711 ;
     RECT  54.72 49.051 55.458 49.711 ;
     RECT  56.415 48.941 56.898 49.711 ;
     RECT  61.815 49.051 64.242 49.711 ;
     RECT  175.215 48.569 175.497 49.711 ;
     RECT  168.084 49.477 168.39 49.739 ;
     RECT  29.088 49.711 29.79 49.757 ;
     RECT  54.72 49.711 57.042 49.757 ;
     RECT  61.56 49.711 64.242 49.757 ;
     RECT  175.104 49.711 175.497 49.757 ;
     RECT  37.044 49.675 37.17 49.805 ;
     RECT  37.044 49.805 37.062 49.819 ;
     RECT  154.764 49.477 155.07 49.819 ;
     RECT  3.636 49.585 9.486 49.855 ;
     RECT  34.704 48.569 35.19 49.855 ;
     RECT  47.34 49.783 47.358 49.867 ;
     RECT  48.276 49.229 48.474 49.867 ;
     RECT  194.58 49.531 197.658 49.867 ;
     RECT  2.415 49.441 2.79 49.891 ;
     RECT  3.636 49.855 9.666 49.891 ;
     RECT  10.404 49.579 28.242 49.891 ;
     RECT  194.58 49.867 197.766 49.891 ;
     RECT  198.792 49.513 212.058 49.891 ;
     RECT  34.704 49.855 35.442 49.901 ;
     RECT  66.528 49.051 70.506 49.963 ;
     RECT  72.216 49.147 75.978 49.963 ;
     RECT  76.932 49.549 98.406 49.963 ;
     RECT  160.92 48.937 161.226 49.981 ;
     RECT  162.108 48.569 162.126 49.981 ;
     RECT  163.224 47.147 163.242 49.981 ;
     RECT  194.58 49.891 212.058 49.981 ;
     RECT  149.328 48.703 150.102 50.017 ;
     RECT  150.84 48.569 150.858 50.017 ;
     RECT  176.544 41.449 176.562 50.089 ;
     RECT  99.396 49.037 108.09 50.107 ;
     RECT  108.972 49.483 113.706 50.107 ;
     RECT  180.072 47.281 181.71 50.125 ;
     RECT  50.436 49.421 51.426 50.141 ;
     RECT  29.232 49.757 29.79 50.161 ;
     RECT  30.528 49.675 30.906 50.161 ;
     RECT  59.688 48.667 60.282 50.161 ;
     RECT  194.58 49.981 212.094 50.161 ;
     RECT  65.196 49.195 65.682 50.203 ;
     RECT  29.232 50.161 30.906 50.251 ;
     RECT  47.34 49.867 48.474 50.251 ;
     RECT  72.216 49.963 98.406 50.251 ;
     RECT  139.176 49.517 140.706 50.251 ;
     RECT  190.476 49.037 191.697 50.251 ;
     RECT  114.768 49.235 132.606 50.279 ;
     RECT  144.54 49.279 144.81 50.299 ;
     RECT  183.996 48.811 184.302 50.299 ;
     RECT  185.616 45.499 186.498 50.299 ;
     RECT  50.436 50.141 51.297 50.323 ;
     RECT  136.512 43.901 137.697 50.323 ;
     RECT  138.528 50.251 140.706 50.323 ;
     RECT  142.092 44.923 143.55 50.323 ;
     RECT  144.468 50.299 144.81 50.323 ;
     RECT  194.364 50.161 212.094 50.323 ;
     RECT  42.768 49.243 42.894 50.347 ;
     RECT  47.34 50.251 48.906 50.347 ;
     RECT  114.768 50.279 119.142 50.347 ;
     RECT  2.415 49.891 28.242 50.359 ;
     RECT  147.42 45.805 148.497 50.359 ;
     RECT  149.328 50.017 150.858 50.359 ;
     RECT  153.288 48.703 153.897 50.359 ;
     RECT  154.764 49.819 155.142 50.359 ;
     RECT  159.015 47.147 159.297 50.359 ;
     RECT  165.78 44.113 165.798 50.359 ;
     RECT  174.276 45.697 174.294 50.359 ;
     RECT  175.215 49.757 175.497 50.359 ;
     RECT  189.288 47.659 189.702 50.359 ;
     RECT  190.476 50.251 191.97 50.359 ;
     RECT  29.232 50.251 31.05 50.395 ;
     RECT  59.688 50.161 60.318 50.395 ;
     RECT  58.284 49.675 58.842 50.431 ;
     RECT  72.216 50.251 98.622 50.431 ;
     RECT  99.396 50.107 113.706 50.431 ;
     RECT  180.072 50.125 182.322 50.431 ;
     RECT  44.028 50.431 44.046 50.443 ;
     RECT  147.42 50.359 150.858 50.459 ;
     RECT  145.764 45.787 146.07 50.491 ;
     RECT  180.072 50.431 182.394 50.491 ;
     RECT  2.376 50.359 28.242 50.521 ;
     RECT  180.072 50.491 182.43 50.521 ;
     RECT  71.784 50.431 113.706 50.549 ;
     RECT  194.328 50.323 212.094 50.549 ;
     RECT  42.768 50.347 43.074 50.573 ;
     RECT  71.784 50.549 87.75 50.585 ;
     RECT  120.06 50.279 132.606 50.585 ;
     RECT  136.512 50.323 140.706 50.585 ;
     RECT  40.215 49.315 41.058 50.593 ;
     RECT  44.028 50.443 44.082 50.593 ;
     RECT  45.18 49.037 46.35 50.593 ;
     RECT  2.34 50.521 28.242 50.621 ;
     RECT  29.232 50.395 31.338 50.621 ;
     RECT  44.028 50.593 44.154 50.621 ;
     RECT  175.215 50.359 175.662 50.621 ;
     RECT  189.288 50.359 191.97 50.621 ;
     RECT  180.072 50.521 182.502 50.629 ;
     RECT  66.528 49.963 71.046 50.635 ;
     RECT  71.784 50.585 87.462 50.635 ;
     RECT  138.528 50.585 140.706 50.657 ;
     RECT  175.215 50.621 175.554 50.657 ;
     RECT  153.288 50.359 155.142 50.665 ;
     RECT  174.276 50.359 174.438 50.683 ;
     RECT  175.215 50.657 175.497 50.683 ;
     RECT  30.78 50.621 31.338 50.693 ;
     RECT  44.064 50.621 44.154 50.701 ;
     RECT  45.144 50.593 46.35 50.701 ;
     RECT  29.232 50.621 29.898 50.731 ;
     RECT  40.14 50.593 41.058 50.731 ;
     RECT  58.284 50.431 58.878 50.731 ;
     RECT  61.704 49.757 64.242 50.731 ;
     RECT  65.088 50.203 65.682 50.731 ;
     RECT  36.504 49.819 37.062 50.779 ;
     RECT  133.344 49.579 135.666 50.779 ;
     RECT  47.34 50.347 49.014 50.791 ;
     RECT  165.78 50.359 166.482 50.791 ;
     RECT  58.284 50.731 58.95 50.819 ;
     RECT  61.704 50.731 65.682 50.819 ;
     RECT  40.104 50.731 41.058 50.827 ;
     RECT  41.832 39.865 41.85 50.827 ;
     RECT  47.232 50.791 49.014 50.827 ;
     RECT  56.304 49.757 56.79 50.827 ;
     RECT  59.688 50.395 60.426 50.827 ;
     RECT  145.764 50.491 146.502 50.827 ;
     RECT  149.328 50.459 150.858 50.827 ;
     RECT  176.544 50.089 176.742 50.827 ;
     RECT  177.48 48.199 179.082 50.827 ;
     RECT  58.68 50.819 58.95 50.828 ;
     RECT  64.944 50.819 65.682 50.855 ;
     RECT  88.56 50.549 113.706 50.855 ;
     RECT  47.232 50.827 49.086 50.863 ;
     RECT  53.028 49.229 53.046 50.863 ;
     RECT  54.72 49.757 55.458 50.863 ;
     RECT  158.148 47.147 158.166 50.863 ;
     RECT  159.015 50.359 159.462 50.863 ;
     RECT  169.815 49.081 170.586 50.863 ;
     RECT  188.064 45.571 188.55 50.863 ;
     RECT  189.288 50.621 191.697 50.863 ;
     RECT  50.148 50.323 51.297 50.875 ;
     RECT  52.092 50.827 52.11 50.875 ;
     RECT  138.564 50.657 140.706 50.891 ;
     RECT  26.388 50.621 28.242 50.899 ;
     RECT  33.048 50.629 33.066 50.899 ;
     RECT  52.992 50.863 53.046 50.899 ;
     RECT  36.504 50.779 37.17 50.909 ;
     RECT  33.048 50.899 33.39 50.923 ;
     RECT  59.688 50.827 60.786 50.923 ;
     RECT  61.704 50.819 64.134 50.923 ;
     RECT  153.108 50.665 155.142 50.923 ;
     RECT  2.34 50.621 25.65 50.935 ;
     RECT  34.704 49.901 35.334 50.935 ;
     RECT  36.504 50.909 37.134 50.935 ;
     RECT  50.148 50.875 52.11 50.935 ;
     RECT  158.112 50.863 159.462 50.935 ;
     RECT  183.996 50.299 184.662 50.935 ;
     RECT  145.764 50.827 146.646 50.956 ;
     RECT  47.232 50.863 49.41 50.963 ;
     RECT  121.032 50.585 132.606 50.963 ;
     RECT  32.544 50.923 33.39 50.971 ;
     RECT  40.104 50.827 41.85 50.971 ;
     RECT  133.344 50.779 135.738 50.971 ;
     RECT  136.512 50.585 137.697 50.971 ;
     RECT  157.176 48.091 157.374 50.971 ;
     RECT  158.112 50.935 159.642 50.971 ;
     RECT  169.815 50.863 170.766 50.971 ;
     RECT  65.016 50.855 65.682 50.999 ;
     RECT  88.56 50.855 113.634 51.005 ;
     RECT  29.196 50.731 29.898 51.019 ;
     RECT  39.924 50.971 41.85 51.061 ;
     RECT  157.176 50.971 159.678 51.061 ;
     RECT  39.348 51.061 41.85 51.089 ;
     RECT  58.68 50.828 58.914 51.089 ;
     RECT  59.688 50.923 64.134 51.089 ;
     RECT  102.42 51.005 113.634 51.089 ;
     RECT  176.544 50.827 179.082 51.089 ;
     RECT  185.616 50.299 186.57 51.089 ;
     RECT  42.768 50.573 43.038 51.097 ;
     RECT  26.388 50.899 28.314 51.101 ;
     RECT  59.94 51.089 64.134 51.112 ;
     RECT  65.088 50.999 65.682 51.125 ;
     RECT  102.42 51.089 103.626 51.125 ;
     RECT  54.684 50.863 55.458 51.133 ;
     RECT  56.232 50.827 56.898 51.133 ;
     RECT  142.092 50.323 144.81 51.133 ;
     RECT  176.724 51.089 179.082 51.163 ;
     RECT  149.328 50.827 151.146 51.169 ;
     RECT  160.668 49.981 161.226 51.169 ;
     RECT  66.528 50.635 87.462 51.197 ;
     RECT  121.032 50.963 127.782 51.197 ;
     RECT  142.092 51.133 144.846 51.197 ;
     RECT  169.815 50.971 170.838 51.205 ;
     RECT  49.32 50.963 49.41 51.233 ;
     RECT  88.56 51.005 101.646 51.233 ;
     RECT  128.664 50.963 132.606 51.241 ;
     RECT  133.344 50.971 137.697 51.241 ;
     RECT  139.824 50.891 140.706 51.241 ;
     RECT  142.092 51.197 143.694 51.241 ;
     RECT  139.824 51.241 143.694 51.245 ;
     RECT  156.744 51.061 159.678 51.245 ;
     RECT  173.052 48.901 173.07 51.259 ;
     RECT  72.288 51.197 87.462 51.269 ;
     RECT  128.664 51.241 137.697 51.269 ;
     RECT  42.048 51.097 43.038 51.307 ;
     RECT  52.92 50.899 53.046 51.307 ;
     RECT  54.684 51.133 56.898 51.307 ;
     RECT  65.16 51.125 65.682 51.307 ;
     RECT  66.528 51.197 71.262 51.307 ;
     RECT  145.764 50.956 146.682 51.307 ;
     RECT  147.42 50.459 148.59 51.307 ;
     RECT  158.472 51.245 159.678 51.307 ;
     RECT  185.832 51.089 186.57 51.307 ;
     RECT  120.06 50.585 120.078 51.331 ;
     RECT  145.764 51.307 148.59 51.331 ;
     RECT  149.328 51.169 151.614 51.331 ;
     RECT  152.784 50.923 155.142 51.331 ;
     RECT  158.472 51.307 159.75 51.331 ;
     RECT  164.016 46.309 165.006 51.331 ;
     RECT  165.78 50.791 166.518 51.331 ;
     RECT  167.328 47.371 167.346 51.331 ;
     RECT  168.084 49.739 168.21 51.331 ;
     RECT  169.815 51.205 171.018 51.331 ;
     RECT  172.98 51.259 173.07 51.331 ;
     RECT  193.068 46.075 193.41 51.331 ;
     RECT  26.388 51.101 27.342 51.341 ;
     RECT  2.304 50.935 25.65 51.355 ;
     RECT  26.388 51.341 26.982 51.355 ;
     RECT  32.4 50.971 33.39 51.355 ;
     RECT  50.148 50.935 52.182 51.355 ;
     RECT  72.504 51.269 87.462 51.355 ;
     RECT  144.468 51.197 144.846 51.355 ;
     RECT  167.328 51.331 168.21 51.355 ;
     RECT  39.348 51.089 41.31 51.359 ;
     RECT  88.56 51.233 101.61 51.359 ;
     RECT  102.636 51.125 103.59 51.359 ;
     RECT  121.032 51.197 127.71 51.359 ;
     RECT  139.824 51.245 143.55 51.359 ;
     RECT  180.072 50.629 182.574 51.359 ;
     RECT  183.996 50.935 184.77 51.359 ;
     RECT  185.832 51.307 186.678 51.359 ;
     RECT  32.4 51.355 33.75 51.367 ;
     RECT  34.704 50.935 37.134 51.367 ;
     RECT  44.064 50.701 46.35 51.367 ;
     RECT  47.232 50.963 48.474 51.367 ;
     RECT  88.56 51.359 101.43 51.367 ;
     RECT  120.06 51.331 120.15 51.367 ;
     RECT  136.368 51.269 137.697 51.367 ;
     RECT  180.144 51.359 182.574 51.367 ;
     RECT  192.672 51.331 193.41 51.367 ;
     RECT  42.048 51.307 43.182 51.389 ;
     RECT  144.468 51.355 144.882 51.389 ;
     RECT  30.78 50.693 31.266 51.395 ;
     RECT  72.504 51.355 87.534 51.395 ;
     RECT  102.636 51.359 103.446 51.395 ;
     RECT  104.364 51.089 113.634 51.395 ;
     RECT  114.588 50.347 119.142 51.395 ;
     RECT  124.02 51.359 127.71 51.395 ;
     RECT  128.664 51.269 135.414 51.395 ;
     RECT  144.54 51.389 144.882 51.395 ;
     RECT  176.724 51.163 179.226 51.395 ;
     RECT  180.144 51.367 182.898 51.395 ;
     RECT  32.4 51.367 37.134 51.403 ;
     RECT  172.98 51.331 173.394 51.403 ;
     RECT  174.276 50.683 175.497 51.403 ;
     RECT  29.088 51.019 29.898 51.431 ;
     RECT  124.02 51.395 125.802 51.431 ;
     RECT  126.612 51.395 127.71 51.431 ;
     RECT  145.764 51.331 155.142 51.431 ;
     RECT  28.224 51.101 28.314 51.439 ;
     RECT  88.452 51.367 101.43 51.439 ;
     RECT  119.988 51.367 120.15 51.439 ;
     RECT  136.368 51.367 137.826 51.439 ;
     RECT  138.564 50.891 139.086 51.439 ;
     RECT  149.4 51.431 155.142 51.439 ;
     RECT  160.668 51.169 161.334 51.439 ;
     RECT  2.304 51.355 26.982 51.467 ;
     RECT  119.988 51.439 120.186 51.467 ;
     RECT  176.724 51.395 178.542 51.467 ;
     RECT  28.224 51.439 28.35 51.475 ;
     RECT  29.088 51.431 29.826 51.475 ;
     RECT  88.38 51.439 101.43 51.475 ;
     RECT  162.108 49.981 163.242 51.475 ;
     RECT  164.016 51.331 166.518 51.475 ;
     RECT  172.188 51.331 172.206 51.475 ;
     RECT  172.98 51.403 175.554 51.475 ;
     RECT  188.064 50.863 191.697 51.475 ;
     RECT  192.672 51.367 193.518 51.475 ;
     RECT  52.92 51.307 56.898 51.485 ;
     RECT  149.4 51.439 155.178 51.485 ;
     RECT  169.596 51.331 171.018 51.485 ;
     RECT  65.16 51.307 71.262 51.503 ;
     RECT  72.504 51.395 87.282 51.503 ;
     RECT  126.612 51.431 127.134 51.503 ;
     RECT  149.4 51.485 151.002 51.503 ;
     RECT  167.328 51.355 168.822 51.503 ;
     RECT  42.732 51.389 43.182 51.511 ;
     RECT  44.064 51.367 48.474 51.511 ;
     RECT  57.78 51.061 57.942 51.511 ;
     RECT  120.132 51.467 120.186 51.511 ;
     RECT  121.032 51.359 123.03 51.511 ;
     RECT  179.28 51.403 179.298 51.511 ;
     RECT  187.524 51.475 191.697 51.511 ;
     RECT  120.132 51.511 123.03 51.533 ;
     RECT  28.224 51.475 29.826 51.539 ;
     RECT  32.04 51.403 37.134 51.539 ;
     RECT  39.348 51.359 40.95 51.539 ;
     RECT  42.732 51.511 48.474 51.539 ;
     RECT  65.268 51.503 71.262 51.539 ;
     RECT  120.132 51.533 122.742 51.539 ;
     RECT  141.444 51.359 143.55 51.539 ;
     RECT  167.328 51.503 168.75 51.539 ;
     RECT  179.28 51.511 179.37 51.539 ;
     RECT  182.304 51.395 182.898 51.539 ;
     RECT  184.284 51.359 184.77 51.539 ;
     RECT  145.764 51.431 148.662 51.547 ;
     RECT  53.388 51.485 56.79 51.581 ;
     RECT  49.644 51.355 52.182 51.587 ;
     RECT  60.084 51.112 64.134 51.592 ;
     RECT  162.108 51.475 166.518 51.595 ;
     RECT  167.328 51.539 168.174 51.595 ;
     RECT  182.376 51.539 182.898 51.595 ;
     RECT  39.348 51.539 40.878 51.601 ;
     RECT  51.84 51.587 52.182 51.601 ;
     RECT  160.632 51.439 161.334 51.601 ;
     RECT  28.224 51.539 29.79 51.629 ;
     RECT  30.78 51.395 31.05 51.629 ;
     RECT  32.04 51.539 33.894 51.629 ;
     RECT  49.644 51.587 51.105 51.629 ;
     RECT  53.388 51.581 56.718 51.629 ;
     RECT  60.084 51.592 64.242 51.629 ;
     RECT  72.504 51.503 87.03 51.629 ;
     RECT  88.344 51.475 101.43 51.629 ;
     RECT  104.364 51.395 111.402 51.629 ;
     RECT  112.896 51.395 113.634 51.629 ;
     RECT  117.396 51.395 119.142 51.629 ;
     RECT  126.612 51.503 127.026 51.629 ;
     RECT  128.916 51.395 135.414 51.629 ;
     RECT  136.368 51.439 139.086 51.629 ;
     RECT  139.824 51.359 140.706 51.629 ;
     RECT  142.092 51.539 143.55 51.629 ;
     RECT  145.512 51.547 148.662 51.629 ;
     RECT  152.136 51.485 155.178 51.629 ;
     RECT  156.744 51.245 157.374 51.629 ;
     RECT  162.108 51.595 168.174 51.629 ;
     RECT  176.796 51.467 178.542 51.629 ;
     RECT  187.524 51.511 191.754 51.629 ;
     RECT  194.364 50.549 212.094 51.629 ;
     RECT  34.632 51.539 37.134 51.635 ;
     RECT  145.512 51.629 148.59 51.635 ;
     RECT  32.04 51.629 32.274 51.637 ;
     RECT  39.24 51.601 40.878 51.643 ;
     RECT  28.224 51.629 28.242 51.665 ;
     RECT  39.132 51.643 40.878 51.665 ;
     RECT  42.732 51.539 46.53 51.665 ;
     RECT  47.304 51.539 48.474 51.665 ;
     RECT  54.756 51.629 56.718 51.665 ;
     RECT  57.6 51.511 57.942 51.665 ;
     RECT  65.268 51.539 67.986 51.665 ;
     RECT  72.504 51.629 81.054 51.665 ;
     RECT  92.412 51.629 95.238 51.665 ;
     RECT  95.976 51.629 95.994 51.665 ;
     RECT  102.636 51.395 102.87 51.665 ;
     RECT  104.364 51.629 111.078 51.665 ;
     RECT  117.396 51.629 118.71 51.665 ;
     RECT  120.168 51.539 122.706 51.665 ;
     RECT  124.164 51.431 125.802 51.665 ;
     RECT  128.916 51.629 132.39 51.665 ;
     RECT  133.272 51.629 135.414 51.665 ;
     RECT  136.548 51.629 137.754 51.665 ;
     RECT  139.824 51.629 140.454 51.665 ;
     RECT  142.092 51.629 143.406 51.665 ;
     RECT  145.512 51.635 148.554 51.665 ;
     RECT  153.108 51.629 154.71 51.665 ;
     RECT  156.744 51.629 156.762 51.665 ;
     RECT  160.596 51.601 161.334 51.665 ;
     RECT  166.464 51.629 168.174 51.665 ;
     RECT  176.868 51.629 178.542 51.665 ;
     RECT  179.352 51.539 179.37 51.665 ;
     RECT  184.464 51.539 184.77 51.673 ;
     RECT  42.732 51.665 42.966 51.677 ;
     RECT  43.884 51.665 46.53 51.677 ;
     RECT  77.616 51.665 81.054 51.677 ;
     RECT  48.204 51.665 48.474 51.701 ;
     RECT  65.52 51.665 67.986 51.701 ;
     RECT  68.976 51.539 71.262 51.701 ;
     RECT  77.832 51.677 81.054 51.701 ;
     RECT  96.876 51.629 101.43 51.701 ;
     RECT  104.76 51.665 110.61 51.701 ;
     RECT  114.588 51.395 116.586 51.701 ;
     RECT  117.396 51.665 117.594 51.701 ;
     RECT  118.476 51.665 118.71 51.701 ;
     RECT  124.272 51.665 125.802 51.701 ;
     RECT  126.615 51.629 127.026 51.701 ;
     RECT  130.068 51.665 132.39 51.701 ;
     RECT  167.832 51.665 168.174 51.701 ;
     RECT  172.188 51.475 175.554 51.701 ;
     RECT  182.376 51.595 183.006 51.701 ;
     RECT  185.832 51.359 186.498 51.701 ;
     RECT  189.9 51.629 191.754 51.701 ;
     RECT  49.86 51.629 51.105 51.725 ;
     RECT  82.656 51.629 83.934 51.725 ;
     RECT  126.615 51.701 126.918 51.725 ;
     RECT  130.536 51.701 132.39 51.725 ;
     RECT  138.528 51.629 139.086 51.725 ;
     RECT  142.704 51.665 143.262 51.725 ;
     RECT  147.672 51.665 148.554 51.725 ;
     RECT  173.7 51.701 175.554 51.725 ;
     RECT  49.932 51.725 51.105 51.737 ;
     RECT  84.924 51.629 86.958 51.737 ;
     RECT  88.344 51.629 91.494 51.737 ;
     RECT  118.584 51.701 118.71 51.737 ;
     RECT  130.644 51.725 132.21 51.737 ;
     RECT  167.832 51.701 168.03 51.737 ;
     RECT  194.364 51.629 194.454 51.737 ;
     RECT  195.3 51.629 212.094 51.737 ;
     RECT  158.472 51.331 159.822 51.745 ;
     RECT  160.596 51.665 161.298 51.745 ;
     RECT  2.304 51.467 26.91 51.773 ;
     RECT  33.084 51.629 33.894 51.773 ;
     RECT  35.892 51.635 37.134 51.773 ;
     RECT  58.716 51.089 58.914 51.773 ;
     RECT  66.384 51.701 67.986 51.773 ;
     RECT  82.656 51.725 83.826 51.773 ;
     RECT  84.924 51.737 86.67 51.773 ;
     RECT  88.344 51.737 89.118 51.773 ;
     RECT  92.916 51.665 95.202 51.773 ;
     RECT  96.876 51.701 101.07 51.773 ;
     RECT  104.76 51.701 109.53 51.773 ;
     RECT  113.076 51.629 113.562 51.773 ;
     RECT  120.24 51.665 122.706 51.773 ;
     RECT  133.272 51.665 135.27 51.773 ;
     RECT  138.636 51.725 139.086 51.773 ;
     RECT  149.472 51.503 151.002 51.773 ;
     RECT  153.504 51.665 154.71 51.773 ;
     RECT  158.472 51.745 161.298 51.773 ;
     RECT  162.468 51.629 165.222 51.773 ;
     RECT  166.464 51.665 166.59 51.773 ;
     RECT  169.596 51.485 170.694 51.773 ;
     RECT  172.188 51.701 172.818 51.773 ;
     RECT  173.7 51.725 175.482 51.773 ;
     RECT  177.3 51.665 178.542 51.773 ;
     RECT  194.4 51.737 194.454 51.773 ;
     RECT  48.312 51.701 48.474 51.781 ;
     RECT  184.464 51.673 184.914 51.782 ;
     RECT  30.78 51.629 30.87 51.809 ;
     RECT  31.86 51.637 32.274 51.809 ;
     RECT  34.632 51.635 35.118 51.809 ;
     RECT  37.116 51.773 37.134 51.809 ;
     RECT  39.132 51.665 40.482 51.809 ;
     RECT  48.312 51.781 48.726 51.809 ;
     RECT  58.824 51.773 58.914 51.809 ;
     RECT  68.976 51.701 70.794 51.809 ;
     RECT  100.98 51.773 101.07 51.809 ;
     RECT  104.76 51.773 106.398 51.809 ;
     RECT  118.692 51.737 118.71 51.809 ;
     RECT  150.552 51.773 150.606 51.809 ;
     RECT  162.504 51.773 162.594 51.809 ;
     RECT  177.3 51.773 177.75 51.809 ;
     RECT  50.076 51.737 51.105 51.821 ;
     RECT  55.404 51.665 56.718 51.821 ;
     RECT  66.384 51.773 67.914 51.821 ;
     RECT  72.504 51.665 76.878 51.821 ;
     RECT  77.832 51.701 80.37 51.821 ;
     RECT  90.324 51.737 91.494 51.821 ;
     RECT  113.256 51.773 113.562 51.821 ;
     RECT  114.732 51.701 116.586 51.821 ;
     RECT  121.032 51.773 122.67 51.821 ;
     RECT  126.615 51.725 126.81 51.821 ;
     RECT  130.68 51.737 132.21 51.821 ;
     RECT  133.272 51.773 134.658 51.821 ;
     RECT  138.672 51.773 139.086 51.821 ;
     RECT  146.484 51.665 146.61 51.821 ;
     RECT  147.672 51.725 148.41 51.821 ;
     RECT  153.504 51.773 153.81 51.821 ;
     RECT  158.904 51.773 160.182 51.821 ;
     RECT  166.572 51.773 166.59 51.821 ;
     RECT  173.7 51.773 173.718 51.821 ;
     RECT  178.524 51.773 178.542 51.821 ;
     RECT  50.184 51.821 51.105 51.857 ;
     RECT  105.015 51.809 106.398 51.857 ;
     RECT  126.615 51.821 126.705 51.857 ;
     RECT  147.672 51.821 148.305 51.857 ;
     RECT  153.615 51.821 153.705 51.857 ;
     RECT  159.015 51.821 160.182 51.857 ;
     RECT  163.584 51.773 165.222 51.857 ;
     RECT  169.815 51.773 170.694 51.857 ;
     RECT  2.304 51.773 26.874 51.869 ;
     RECT  50.184 51.857 50.706 51.869 ;
     RECT  55.872 51.821 56.646 51.869 ;
     RECT  58.896 51.809 58.914 51.869 ;
     RECT  60.084 51.629 63.882 51.869 ;
     RECT  79.02 51.821 80.37 51.869 ;
     RECT  85.032 51.773 86.67 51.869 ;
     RECT  88.344 51.773 89.01 51.869 ;
     RECT  98.604 51.773 99.954 51.869 ;
     RECT  101.016 51.809 101.07 51.869 ;
     RECT  133.272 51.821 134.55 51.869 ;
     RECT  170.208 51.857 170.694 51.869 ;
     RECT  29.016 51.629 29.79 51.899 ;
     RECT  30.78 51.809 30.798 51.899 ;
     RECT  31.86 51.809 31.878 51.899 ;
     RECT  34.632 51.809 35.082 51.899 ;
     RECT  39.348 51.809 40.482 51.899 ;
     RECT  42.84 51.677 42.966 51.899 ;
     RECT  43.884 51.677 44.478 51.899 ;
     RECT  45.432 51.677 46.53 51.899 ;
     RECT  51.84 51.601 52.542 51.899 ;
     RECT  60.084 51.869 62.19 51.899 ;
     RECT  72.504 51.821 74.826 51.899 ;
     RECT  77.832 51.821 78.21 51.899 ;
     RECT  82.8 51.773 83.826 51.899 ;
     RECT  88.776 51.869 88.974 51.899 ;
     RECT  113.364 51.821 113.562 51.899 ;
     RECT  133.272 51.869 133.974 51.899 ;
     RECT  136.8 51.665 137.754 51.899 ;
     RECT  174.996 51.773 175.482 51.899 ;
     RECT  180.144 51.395 181.242 51.899 ;
     RECT  184.464 51.782 184.878 51.899 ;
     RECT  110.304 51.701 110.61 51.917 ;
     RECT  121.032 51.821 122.634 51.917 ;
     RECT  131.256 51.821 132.21 51.917 ;
     RECT  142.704 51.725 143.01 51.917 ;
     RECT  73.26 51.899 74.826 51.935 ;
     RECT  162.54 51.809 162.558 51.935 ;
     RECT  35.892 51.773 35.91 51.965 ;
     RECT  121.032 51.917 121.194 51.965 ;
     RECT  195.912 51.737 212.094 51.965 ;
     RECT  73.26 51.935 73.926 51.971 ;
     RECT  82.8 51.899 83.79 51.971 ;
     RECT  85.68 51.869 86.67 51.971 ;
     RECT  92.916 51.773 95.166 51.971 ;
     RECT  98.604 51.869 99.882 51.971 ;
     RECT  107.136 51.773 109.314 51.971 ;
     RECT  190.404 51.701 191.754 51.979 ;
     RECT  192.636 51.475 193.518 51.979 ;
     RECT  42.948 51.899 42.966 52.007 ;
     RECT  50.184 51.869 50.202 52.007 ;
     RECT  115.632 51.821 116.586 52.007 ;
     RECT  97.308 51.773 97.722 52.013 ;
     RECT  146.484 51.821 146.502 52.013 ;
     RECT  170.676 51.869 170.694 52.013 ;
     RECT  174.996 51.899 175.41 52.013 ;
     RECT  182.412 51.701 183.006 52.013 ;
     RECT  190.404 51.979 193.518 52.013 ;
     RECT  0.108 52.015 0.126 52.027 ;
     RECT  43.884 51.899 44.442 52.043 ;
     RECT  121.032 51.965 121.05 52.043 ;
     RECT  182.808 52.013 183.006 52.043 ;
     RECT  53.388 51.629 53.982 52.079 ;
     RECT  185.832 51.701 186.426 52.079 ;
     RECT  114.732 51.821 114.75 52.109 ;
     RECT  194.4 51.773 194.418 52.109 ;
     RECT  24.192 51.869 26.226 52.157 ;
     RECT  90.396 51.821 91.494 52.157 ;
     RECT  92.952 51.971 93.51 52.157 ;
     RECT  139.068 51.821 139.086 52.169 ;
     RECT  68.976 51.809 70.686 52.205 ;
     RECT  105.444 51.857 106.398 52.205 ;
     RECT  83.232 51.971 83.79 52.241 ;
     RECT  86.04 51.971 86.67 52.241 ;
     RECT  48.708 51.809 48.726 52.253 ;
     RECT  60.084 51.899 61.326 52.253 ;
     RECT  75.744 51.821 76.878 52.253 ;
     RECT  0.108 52.027 0.162 52.267 ;
     RECT  63.288 51.869 63.882 52.277 ;
     RECT  107.136 51.971 109.062 52.277 ;
     RECT  43.92 52.043 44.442 52.301 ;
     RECT  62.136 51.899 62.154 52.313 ;
     RECT  97.704 52.013 97.722 52.313 ;
     RECT  60.084 52.253 60.966 52.349 ;
     RECT  90.396 52.157 90.414 52.349 ;
     RECT  115.632 52.007 115.65 52.349 ;
     RECT  128.916 51.665 128.934 52.349 ;
     RECT  33.084 51.773 33.102 52.394 ;
     RECT  43.92 52.301 43.938 52.394 ;
     RECT  190.512 52.013 193.518 52.394 ;
     RECT  117.576 51.701 117.594 52.397 ;
     RECT  185.832 52.079 185.85 52.397 ;
     RECT  66.816 51.821 67.914 52.439 ;
     RECT  120.24 51.773 120.258 52.439 ;
     RECT  106.38 52.205 106.398 52.445 ;
     RECT  73.404 51.971 73.926 52.475 ;
     RECT  172.188 51.773 172.746 52.475 ;
     RECT  73.404 52.475 73.566 52.511 ;
     RECT  159.624 51.857 160.182 52.511 ;
     RECT  79.02 51.869 79.83 52.547 ;
     RECT  83.376 52.241 83.79 52.547 ;
     RECT  163.584 51.857 163.71 52.547 ;
     RECT  30.168 52.315 30.186 52.583 ;
     RECT  47.304 51.665 47.394 52.583 ;
     RECT  101.052 51.869 101.07 52.583 ;
     RECT  108.144 52.277 109.062 52.583 ;
     RECT  122.004 51.917 122.634 52.583 ;
     RECT  192.672 52.394 193.518 52.583 ;
     RECT  86.04 52.241 86.058 52.589 ;
     RECT  47.304 52.583 47.322 52.619 ;
     RECT  93.492 52.157 93.51 52.619 ;
     RECT  131.256 51.917 131.274 52.619 ;
     RECT  184.788 51.899 184.806 52.619 ;
     RECT  190.512 52.394 191.754 52.637 ;
     RECT  79.02 52.547 79.578 52.664 ;
     RECT  113.364 51.899 113.418 52.664 ;
     RECT  24.48 52.157 26.226 52.685 ;
     RECT  147.672 51.857 147.69 52.685 ;
     RECT  33.876 51.773 33.894 52.709 ;
     RECT  172.728 52.475 172.746 52.709 ;
     RECT  168.012 51.737 168.03 52.733 ;
     RECT  190.512 52.637 190.638 52.733 ;
     RECT  108.72 52.583 109.062 52.745 ;
     RECT  124.272 51.701 125.406 52.745 ;
     RECT  109.044 52.745 109.062 52.781 ;
     RECT  137.556 51.899 137.574 52.781 ;
     RECT  165.204 51.857 165.222 52.781 ;
     RECT  191.736 52.637 191.754 52.781 ;
     RECT  94.644 51.971 95.166 52.817 ;
     RECT  136.8 51.899 136.818 52.817 ;
     RECT  65.52 51.701 65.538 52.829 ;
     RECT  73.548 52.511 73.566 52.853 ;
     RECT  107.136 52.277 107.154 52.853 ;
     RECT  160.164 52.511 160.182 52.853 ;
     RECT  63.288 52.277 63.594 52.877 ;
     RECT  66.816 52.439 67.734 52.877 ;
     RECT  57.924 51.665 57.942 52.889 ;
     RECT  163.692 52.547 163.71 52.889 ;
     RECT  68.976 52.205 70.182 52.925 ;
     RECT  193.5 52.583 193.518 52.925 ;
     RECT  60.444 52.349 60.966 52.934 ;
     RECT  187.524 51.629 188.658 52.934 ;
     RECT  95.148 52.817 95.166 52.973 ;
     RECT  46.152 51.899 46.206 52.979 ;
     RECT  113.4 52.664 113.418 52.979 ;
     RECT  213.015 2.413 213.297 52.987 ;
     RECT  46.152 52.979 46.17 53.015 ;
     RECT  174.996 52.013 175.122 53.015 ;
     RECT  99.216 51.971 99.234 53.021 ;
     RECT  0.108 52.267 0.342 53.023 ;
     RECT  68.976 52.925 69.642 53.051 ;
     RECT  177.3 51.809 177.318 53.051 ;
     RECT  124.272 52.745 124.83 53.069 ;
     RECT  75.744 52.253 76.374 53.087 ;
     RECT  175.032 53.015 175.122 53.087 ;
     RECT  116.568 52.007 116.586 53.117 ;
     RECT  175.032 53.087 175.05 53.117 ;
     RECT  55.872 51.869 56.61 53.123 ;
     RECT  150.588 51.809 150.606 53.123 ;
     RECT  63.324 52.877 63.594 53.159 ;
     RECT  66.816 52.877 67.194 53.159 ;
     RECT  154.692 51.773 154.71 53.159 ;
     RECT  74.808 51.935 74.826 53.204 ;
     RECT  161.28 51.773 161.298 53.204 ;
     RECT  2.304 51.869 23.382 53.221 ;
     RECT  24.48 52.685 25.686 53.221 ;
     RECT  60.516 52.934 60.966 53.249 ;
     RECT  105.444 52.205 105.462 53.249 ;
     RECT  83.772 52.547 83.79 53.261 ;
     RECT  88.956 51.899 88.974 53.261 ;
     RECT  0.108 53.023 0.378 53.323 ;
     RECT  2.304 53.221 25.686 53.365 ;
     RECT  0.108 53.323 0.45 53.519 ;
     RECT  192.672 52.583 192.69 53.563 ;
     RECT  196.236 51.965 212.094 53.563 ;
     RECT  194.364 53.221 194.382 53.716 ;
     RECT  2.268 53.365 25.686 53.741 ;
     RECT  2.304 53.741 25.686 54 ;
     RECT  35.892 53.131 35.91 54 ;
     RECT  39.348 51.899 39.366 54 ;
     RECT  52.092 51.899 52.11 54 ;
     RECT  53.388 52.079 53.406 54 ;
     RECT  56.592 53.123 56.61 54 ;
     RECT  60.516 53.249 60.534 54 ;
     RECT  63.576 53.159 63.594 54 ;
     RECT  66.816 53.159 66.834 54 ;
     RECT  68.976 53.051 69.426 54 ;
     RECT  75.744 53.087 75.762 54 ;
     RECT  79.02 52.664 79.038 54 ;
     RECT  91.188 52.157 91.494 54 ;
     RECT  102.852 51.665 102.87 54 ;
     RECT  122.616 52.583 122.634 54 ;
     RECT  124.812 53.069 124.83 54 ;
     RECT  137.952 52.825 137.97 54 ;
     RECT  149.508 51.773 149.526 54 ;
     RECT  152.136 51.629 152.154 54 ;
     RECT  180.144 51.899 180.162 54 ;
     RECT  181.224 51.899 181.242 54 ;
     RECT  182.988 52.043 183.006 54 ;
     RECT  187.524 52.934 188.118 54 ;
     RECT  190.512 52.733 190.53 54 ;
     RECT  192.672 53.563 193.302 54 ;
     RECT  194.364 53.716 194.454 54 ;
     RECT  196.236 53.563 212.238 54 ;
     RECT  0.108 53.519 0.378 54.379 ;
     RECT  216.576 54.373 216.594 54.409 ;
     RECT  218.556 54.373 218.574 54.409 ;
     RECT  0.108 54.379 0.414 54.473 ;
     RECT  217.368 54.445 217.386 54.481 ;
     RECT  2.304 54 212.238 54.509 ;
     RECT  216.396 54.409 216.594 54.571 ;
     RECT  217.368 54.481 217.782 54.571 ;
     RECT  0.108 54.473 0.27 54.605 ;
     RECT  0.108 54.605 0.162 54.635 ;
     RECT  0.144 54.635 0.162 54.671 ;
     RECT  216.396 54.571 217.782 54.679 ;
     RECT  218.556 54.409 218.682 54.679 ;
     RECT  2.34 54.509 212.238 54.715 ;
     RECT  212.976 52.987 213.297 54.715 ;
     RECT  220.248 54.445 220.266 54.715 ;
     RECT  220.176 54.715 220.266 54.743 ;
     RECT  216.396 54.679 218.682 54.841 ;
     RECT  216.072 54.841 219.042 54.985 ;
     RECT  215.784 54.985 219.042 55.111 ;
     RECT  215.712 55.111 219.042 55.183 ;
     RECT  220.176 54.743 220.23 55.183 ;
     RECT  215.712 55.183 220.23 55.255 ;
     RECT  2.34 54.715 213.297 55.525 ;
     RECT  0.324 55.435 0.342 55.531 ;
     RECT  215.208 55.255 220.23 55.561 ;
     RECT  0.144 55.531 0.342 55.565 ;
     RECT  0.144 55.565 0.162 55.709 ;
     RECT  214.812 55.561 220.23 55.795 ;
     RECT  214.704 55.795 220.23 55.831 ;
     RECT  2.304 55.525 213.297 55.921 ;
     RECT  214.488 55.831 220.23 55.921 ;
     RECT  2.304 55.921 220.23 56.399 ;
     RECT  2.304 56.399 11.43 56.489 ;
     RECT  12.24 56.399 220.23 56.489 ;
     RECT  1.152 55.531 1.17 56.597 ;
     RECT  0.18 56.497 0.198 56.813 ;
     RECT  2.304 56.489 10.026 57.163 ;
     RECT  2.268 57.163 10.026 57.209 ;
     RECT  2.304 57.209 10.026 57.451 ;
     RECT  10.8 56.489 11.43 57.451 ;
     RECT  2.304 57.451 11.43 57.569 ;
     RECT  2.304 57.569 10.026 57.629 ;
     RECT  0.144 57.499 0.162 57.869 ;
     RECT  10.764 57.569 11.43 57.911 ;
     RECT  10.764 57.911 11.178 57.947 ;
     RECT  0.18 57.919 0.558 57.965 ;
     RECT  0.18 57.965 0.342 58.445 ;
     RECT  12.276 56.489 220.23 58.693 ;
     RECT  2.34 57.629 10.026 58.699 ;
     RECT  12.24 58.693 220.23 58.733 ;
     RECT  0.18 58.445 0.198 58.792 ;
     RECT  11.16 57.947 11.178 58.801 ;
     RECT  0.108 58.792 0.198 58.829 ;
     RECT  10.836 58.801 11.178 58.919 ;
     RECT  2.304 58.699 10.026 59.189 ;
     RECT  12.24 58.733 219.654 59.297 ;
     RECT  0.144 58.829 0.198 59.467 ;
     RECT  0.144 59.467 0.342 59.737 ;
     RECT  0.108 59.737 0.342 59.765 ;
     RECT  0.108 59.765 0.234 59.789 ;
     RECT  205.2 59.297 219.654 59.885 ;
     RECT  2.304 59.189 9.666 59.999 ;
     RECT  219.42 59.885 219.654 60.173 ;
     RECT  0.108 59.789 0.198 60.413 ;
     RECT  11.16 58.919 11.178 60.583 ;
     RECT  0.144 60.413 0.198 60.619 ;
     RECT  205.2 59.885 218.61 60.691 ;
     RECT  219.42 60.173 219.618 60.691 ;
     RECT  0.144 60.619 0.378 60.749 ;
     RECT  2.304 59.999 9.378 60.955 ;
     RECT  0.144 60.749 0.162 60.989 ;
     RECT  10.8 60.583 11.178 61.123 ;
     RECT  205.2 60.691 219.618 61.195 ;
     RECT  2.196 60.955 9.378 61.223 ;
     RECT  10.764 61.123 11.178 61.223 ;
     RECT  205.2 61.195 220.23 61.304 ;
     RECT  205.2 61.304 220.05 61.325 ;
     RECT  2.268 61.223 9.378 61.385 ;
     RECT  1.152 60.907 1.17 61.925 ;
     RECT  205.2 61.325 219.546 62.189 ;
     RECT  0.144 61.915 0.162 62.251 ;
     RECT  0.144 62.251 0.234 62.443 ;
     RECT  220.176 62.443 220.23 62.473 ;
     RECT  2.304 61.385 9.378 62.545 ;
     RECT  12.24 59.297 204.354 62.621 ;
     RECT  0.108 62.443 0.234 62.626 ;
     RECT  0.108 62.626 0.306 62.669 ;
     RECT  220.176 62.473 220.266 62.735 ;
     RECT  205.2 62.189 219.15 62.941 ;
     RECT  220.176 62.735 220.23 62.941 ;
     RECT  1.728 62.545 9.378 63.053 ;
     RECT  2.232 63.053 9.378 63.149 ;
     RECT  205.2 62.941 220.23 63.239 ;
     RECT  2.232 63.149 8.55 63.275 ;
     RECT  11.16 61.223 11.178 63.391 ;
     RECT  10.836 63.391 11.178 63.625 ;
     RECT  205.2 63.239 220.194 63.773 ;
     RECT  205.2 63.773 219.438 63.779 ;
     RECT  10.512 63.625 11.178 63.781 ;
     RECT  0.108 63.403 0.126 63.851 ;
     RECT  2.304 63.275 8.55 63.931 ;
     RECT  12.24 62.621 13.554 63.931 ;
     RECT  0.144 63.883 0.162 63.979 ;
     RECT  1.152 63.211 1.17 63.979 ;
     RECT  9.36 63.149 9.378 64.049 ;
     RECT  0.144 63.979 1.17 64.157 ;
     RECT  10.44 63.781 11.178 64.201 ;
     RECT  10.26 64.201 11.178 64.301 ;
     RECT  0.54 64.157 1.17 64.459 ;
     RECT  2.304 63.931 8.586 64.471 ;
     RECT  10.836 64.301 11.178 64.589 ;
     RECT  12.132 63.931 13.554 64.625 ;
     RECT  220.176 63.773 220.194 64.651 ;
     RECT  205.2 63.779 219.15 64.669 ;
     RECT  220.176 64.651 220.23 64.669 ;
     RECT  10.872 64.589 11.178 64.769 ;
     RECT  2.304 64.471 8.694 64.843 ;
     RECT  11.16 64.769 11.178 64.859 ;
     RECT  12.6 64.625 13.554 64.859 ;
     RECT  9.432 64.669 9.45 64.931 ;
     RECT  2.268 64.843 8.694 65.165 ;
     RECT  2.304 65.165 8.694 65.237 ;
     RECT  10.44 65.704 10.458 65.741 ;
     RECT  205.2 64.669 220.23 65.741 ;
     RECT  0.54 64.459 1.314 65.777 ;
     RECT  13.215 64.859 13.554 65.821 ;
     RECT  10.836 65.749 10.854 65.849 ;
     RECT  14.508 62.621 204.354 65.849 ;
     RECT  14.508 65.849 203.886 65.933 ;
     RECT  13.215 65.821 13.698 65.939 ;
     RECT  2.304 65.237 8.586 65.975 ;
     RECT  2.34 65.975 8.586 65.981 ;
     RECT  205.416 65.741 220.23 66.011 ;
     RECT  0.54 65.777 1.17 66.047 ;
     RECT  7.815 65.981 8.586 66.077 ;
     RECT  0.54 66.047 0.558 66.083 ;
     RECT  205.452 66.011 220.23 66.317 ;
     RECT  2.34 65.981 7.074 66.479 ;
     RECT  7.056 66.479 7.074 66.701 ;
     RECT  219.348 66.317 220.23 66.701 ;
     RECT  219.348 66.701 219.438 66.749 ;
     RECT  2.412 66.479 6.246 66.785 ;
     RECT  199.404 65.933 203.886 66.797 ;
     RECT  2.415 66.785 6.246 66.857 ;
     RECT  205.452 66.317 218.394 66.859 ;
     RECT  199.872 66.797 203.886 66.893 ;
     RECT  205.344 66.859 218.394 67.019 ;
     RECT  14.508 65.933 198.63 67.099 ;
     RECT  2.415 66.857 6.138 67.277 ;
     RECT  3.564 67.277 6.138 67.289 ;
     RECT  3.564 67.289 5.598 67.325 ;
     RECT  3.564 67.325 5.274 67.397 ;
     RECT  3.564 67.397 5.13 67.421 ;
     RECT  219.384 66.749 219.438 67.432 ;
     RECT  220.176 66.701 220.23 67.432 ;
     RECT  3.564 67.421 4.842 67.559 ;
     RECT  205.416 67.019 218.394 67.639 ;
     RECT  219.384 67.432 220.23 67.639 ;
     RECT  14.508 67.099 198.99 67.819 ;
     RECT  199.908 66.893 203.886 67.819 ;
     RECT  3.564 67.559 4.518 67.829 ;
     RECT  205.416 67.639 220.23 67.829 ;
     RECT  3.564 67.829 4.374 67.865 ;
     RECT  14.508 67.819 203.886 67.949 ;
     RECT  3.564 67.865 4.194 68.099 ;
     RECT  205.416 67.829 218.898 68.141 ;
     RECT  205.416 68.141 218.574 68.251 ;
     RECT  219.996 67.829 220.23 68.333 ;
     RECT  7.815 66.077 8.097 68.611 ;
     RECT  7.815 68.611 8.226 68.669 ;
     RECT  10.8 68.647 10.818 68.747 ;
     RECT  199.476 67.949 203.886 68.755 ;
     RECT  14.508 67.949 198.63 68.881 ;
     RECT  199.44 68.755 204.066 68.881 ;
     RECT  14.508 68.881 204.066 69.005 ;
     RECT  205.164 68.251 218.574 69.179 ;
     RECT  205.416 69.179 218.574 69.215 ;
     RECT  220.212 68.333 220.23 69.251 ;
     RECT  219.42 68.587 219.438 69.355 ;
     RECT  14.508 69.005 198.63 69.449 ;
     RECT  205.56 69.215 218.574 69.485 ;
     RECT  219.42 69.355 220.122 69.485 ;
     RECT  199.44 69.005 204.066 69.493 ;
     RECT  205.596 69.485 218.574 69.547 ;
     RECT  16.884 69.449 198.63 69.989 ;
     RECT  199.44 69.493 204.606 69.989 ;
     RECT  220.104 69.485 220.122 70.027 ;
     RECT  205.596 69.547 218.862 70.219 ;
     RECT  220.104 70.027 220.23 70.219 ;
     RECT  199.44 69.989 204.066 70.259 ;
     RECT  205.596 70.219 220.23 70.267 ;
     RECT  13.215 65.939 13.497 70.411 ;
     RECT  14.508 69.449 16.146 70.411 ;
     RECT  9.792 70.459 9.81 70.501 ;
     RECT  9.72 70.501 9.81 70.529 ;
     RECT  8.856 70.501 8.874 70.541 ;
     RECT  9.72 70.529 9.738 70.637 ;
     RECT  205.452 70.267 220.23 70.685 ;
     RECT  16.956 69.989 198.63 70.829 ;
     RECT  13.215 70.411 16.146 71.021 ;
     RECT  15.084 71.021 16.146 71.275 ;
     RECT  16.956 70.829 21.474 71.275 ;
     RECT  199.44 70.259 203.85 71.405 ;
     RECT  206.028 70.685 220.23 71.519 ;
     RECT  13.215 71.021 14.31 71.609 ;
     RECT  15.084 71.275 21.474 71.645 ;
     RECT  16.92 71.645 21.474 71.659 ;
     RECT  22.248 70.829 198.63 71.659 ;
     RECT  16.92 71.659 198.63 71.753 ;
     RECT  15.084 71.645 16.146 71.761 ;
     RECT  199.476 71.405 203.85 71.885 ;
     RECT  13.215 71.609 13.986 71.915 ;
     RECT  16.956 71.753 198.63 71.951 ;
     RECT  199.512 71.885 203.85 72.293 ;
     RECT  14.904 71.761 16.146 72.379 ;
     RECT  14.868 72.379 16.146 72.499 ;
     RECT  14.508 72.499 16.146 72.571 ;
     RECT  16.956 71.951 21.474 72.571 ;
     RECT  3.564 68.099 4.122 72.689 ;
     RECT  199.836 72.293 203.85 72.689 ;
     RECT  11.088 70.303 11.106 72.725 ;
     RECT  202.032 72.689 203.85 72.725 ;
     RECT  206.064 71.519 220.23 72.761 ;
     RECT  22.248 71.951 198.63 72.845 ;
     RECT  206.064 72.761 218.358 72.941 ;
     RECT  202.032 72.725 203.814 73.031 ;
     RECT  4.104 72.689 4.122 73.229 ;
     RECT  22.284 72.845 198.63 73.325 ;
     RECT  6.804 72.697 6.822 73.337 ;
     RECT  14.508 72.571 21.474 73.381 ;
     RECT  13.215 71.915 13.698 73.471 ;
     RECT  14.436 73.381 21.474 73.471 ;
     RECT  219.168 72.761 220.23 73.483 ;
     RECT  22.32 73.325 198.63 73.507 ;
     RECT  22.32 73.507 198.954 73.579 ;
     RECT  199.836 72.689 200.826 73.579 ;
     RECT  218.808 73.483 220.23 73.901 ;
     RECT  206.064 72.941 217.998 73.921 ;
     RECT  218.808 73.901 219.438 73.921 ;
     RECT  202.032 73.031 203.274 73.949 ;
     RECT  13.215 73.471 21.474 74.059 ;
     RECT  22.32 73.579 200.826 74.059 ;
     RECT  206.064 73.921 219.438 74.107 ;
     RECT  13.215 74.059 200.826 74.189 ;
     RECT  202.215 73.949 203.274 74.417 ;
     RECT  13.215 74.189 198.63 74.453 ;
     RECT  205.884 74.107 219.438 74.615 ;
     RECT  206.064 74.615 219.438 74.623 ;
     RECT  220.176 73.901 220.23 74.623 ;
     RECT  199.404 74.189 200.826 74.765 ;
     RECT  206.064 74.623 220.23 74.861 ;
     RECT  22.212 74.453 198.63 75.127 ;
     RECT  13.215 74.453 21.474 75.245 ;
     RECT  22.212 75.127 198.954 75.307 ;
     RECT  21.6 75.307 198.954 75.341 ;
     RECT  206.064 74.861 219.222 75.497 ;
     RECT  206.1 75.497 219.222 75.533 ;
     RECT  202.215 74.417 203.238 75.569 ;
     RECT  206.46 75.533 219.222 75.595 ;
     RECT  219.996 74.861 220.23 75.595 ;
     RECT  206.46 75.595 220.23 75.659 ;
     RECT  199.8 74.765 200.826 75.775 ;
     RECT  199.476 75.775 200.826 75.917 ;
     RECT  202.215 75.569 202.662 76.037 ;
     RECT  21.6 75.341 198.63 76.351 ;
     RECT  206.928 75.659 220.23 76.379 ;
     RECT  21.6 76.351 198.954 76.397 ;
     RECT  13.215 75.245 20.79 76.459 ;
     RECT  21.6 76.397 198.63 76.459 ;
     RECT  207.576 76.379 220.23 76.505 ;
     RECT  208.62 76.505 220.23 76.613 ;
     RECT  208.62 76.613 209.466 76.649 ;
     RECT  208.62 76.649 209.394 76.739 ;
     RECT  207.576 76.505 207.897 76.775 ;
     RECT  208.62 76.739 209.286 76.775 ;
     RECT  210.204 76.613 220.23 76.919 ;
     RECT  208.62 76.775 208.638 77.045 ;
     RECT  210.204 76.919 219.222 77.081 ;
     RECT  210.636 77.081 218.826 77.279 ;
     RECT  210.636 77.279 210.654 77.315 ;
     RECT  211.536 77.279 218.826 77.315 ;
     RECT  13.215 76.459 198.63 77.357 ;
     RECT  13.215 77.357 17.658 77.585 ;
     RECT  211.752 77.315 218.826 77.657 ;
     RECT  14.364 77.585 17.658 77.819 ;
     RECT  199.908 75.917 200.826 77.827 ;
     RECT  211.752 77.657 218.574 77.855 ;
     RECT  212.076 77.855 218.574 77.963 ;
     RECT  14.832 77.819 17.658 77.981 ;
     RECT  199.872 77.827 200.826 78.061 ;
     RECT  14.976 77.981 17.658 78.089 ;
     RECT  18.432 77.357 198.63 78.089 ;
     RECT  15.624 78.089 17.658 78.205 ;
     RECT  18.432 78.089 21.726 78.205 ;
     RECT  15.624 78.205 21.726 78.221 ;
     RECT  219.96 76.919 220.23 78.269 ;
     RECT  199.404 78.061 200.826 78.317 ;
     RECT  15.624 78.221 21.69 78.359 ;
     RECT  2.415 67.277 2.697 78.367 ;
     RECT  2.415 78.367 3.402 78.427 ;
     RECT  2.415 78.427 4.05 78.439 ;
     RECT  2.376 78.439 4.05 78.469 ;
     RECT  2.304 78.469 4.05 78.511 ;
     RECT  2.304 78.511 4.23 78.637 ;
     RECT  220.032 78.269 220.23 78.665 ;
     RECT  199.44 78.317 200.826 78.797 ;
     RECT  15.624 78.359 15.822 78.899 ;
     RECT  15.624 78.899 15.642 78.935 ;
     RECT  16.884 78.359 21.69 78.989 ;
     RECT  2.232 78.637 4.23 79.051 ;
     RECT  2.232 79.051 4.446 79.141 ;
     RECT  22.752 78.089 198.63 79.141 ;
     RECT  16.884 78.989 21.114 79.181 ;
     RECT  22.752 79.141 198.954 79.277 ;
     RECT  2.232 79.141 4.986 79.291 ;
     RECT  220.104 78.665 220.23 79.313 ;
     RECT  212.688 77.963 218.574 79.349 ;
     RECT  16.884 79.181 20.322 79.411 ;
     RECT  213.015 79.349 218.574 79.439 ;
     RECT  213.015 79.439 214.074 79.511 ;
     RECT  22.752 79.277 198.63 79.531 ;
     RECT  220.212 79.313 220.23 79.583 ;
     RECT  2.232 79.291 5.31 79.591 ;
     RECT  21.06 79.181 21.114 79.619 ;
     RECT  2.232 79.591 5.598 79.681 ;
     RECT  214.812 79.439 218.574 79.709 ;
     RECT  22.212 79.531 198.63 79.723 ;
     RECT  215.208 79.709 217.854 79.745 ;
     RECT  199.836 78.797 200.826 79.816 ;
     RECT  2.232 79.681 6.102 79.861 ;
     RECT  6.912 79.717 6.93 79.861 ;
     RECT  7.815 68.669 8.097 79.861 ;
     RECT  215.208 79.745 217.782 79.889 ;
     RECT  21.636 79.723 198.63 79.979 ;
     RECT  213.015 79.511 213.39 79.979 ;
     RECT  215.208 79.889 216.666 79.979 ;
     RECT  217.44 79.889 217.782 79.979 ;
     RECT  215.208 79.979 216.486 80.015 ;
     RECT  215.208 80.015 215.478 80.087 ;
     RECT  216.396 80.015 216.486 80.087 ;
     RECT  16.704 79.411 20.322 80.131 ;
     RECT  215.208 80.087 215.226 80.159 ;
     RECT  16.56 80.131 20.322 80.248 ;
     RECT  16.38 80.248 20.322 80.249 ;
     RECT  2.232 79.861 8.097 80.257 ;
     RECT  16.38 80.249 16.398 80.285 ;
     RECT  18.576 80.249 20.322 80.329 ;
     RECT  21.672 79.979 198.63 80.393 ;
     RECT  18.576 80.329 20.646 80.429 ;
     RECT  17.28 80.249 17.694 80.519 ;
     RECT  13.215 77.585 13.497 80.671 ;
     RECT  12.528 80.671 13.497 80.761 ;
     RECT  18.615 80.429 20.646 80.789 ;
     RECT  2.232 80.257 8.19 80.905 ;
     RECT  19.908 80.789 19.926 80.969 ;
     RECT  199.476 79.816 200.826 81.005 ;
     RECT  21.672 80.393 21.69 81.067 ;
     RECT  9.936 80.941 9.954 81.211 ;
     RECT  11.196 80.221 11.214 81.211 ;
     RECT  21.636 81.067 21.69 81.259 ;
     RECT  0.108 80.905 0.126 81.307 ;
     RECT  9.936 81.211 11.214 81.329 ;
     RECT  21.06 81.259 21.69 81.355 ;
     RECT  22.752 80.393 198.63 81.355 ;
     RECT  21.06 81.355 198.63 81.365 ;
     RECT  12.456 80.761 13.497 81.437 ;
     RECT  0.108 81.307 0.162 81.445 ;
     RECT  2.232 80.905 8.73 81.481 ;
     RECT  14.796 80.875 14.814 81.571 ;
     RECT  12.06 81.595 12.258 81.635 ;
     RECT  14.76 81.571 14.814 81.679 ;
     RECT  9.936 81.329 10.926 81.707 ;
     RECT  12.24 81.635 12.258 81.707 ;
     RECT  9.936 81.707 10.854 81.751 ;
     RECT  14.724 81.679 14.814 81.779 ;
     RECT  22.176 81.365 198.63 81.779 ;
     RECT  0.108 81.445 0.594 81.869 ;
     RECT  21.06 81.365 21.078 81.917 ;
     RECT  17.64 81.883 17.658 81.931 ;
     RECT  19.8 81.931 19.926 82.061 ;
     RECT  2.232 81.481 9.054 82.123 ;
     RECT  9.828 81.751 10.854 82.123 ;
     RECT  19.908 82.061 19.926 82.139 ;
     RECT  199.98 81.005 200.826 82.291 ;
     RECT  2.232 82.123 10.854 82.525 ;
     RECT  2.196 82.525 10.854 82.553 ;
     RECT  2.196 82.553 9.99 82.589 ;
     RECT  17.568 81.931 17.658 82.651 ;
     RECT  21.636 82.315 21.654 82.679 ;
     RECT  13.104 81.437 13.497 82.688 ;
     RECT  14.796 81.779 14.814 82.699 ;
     RECT  17.208 82.651 17.658 82.715 ;
     RECT  14.724 82.699 14.814 82.733 ;
     RECT  17.208 82.715 17.226 82.747 ;
     RECT  18.615 80.789 18.897 82.747 ;
     RECT  14.724 82.733 14.742 82.751 ;
     RECT  17.1 82.747 17.226 82.781 ;
     RECT  0.144 81.869 0.594 82.795 ;
     RECT  22.68 81.779 198.63 82.831 ;
     RECT  0.144 82.795 1.17 82.925 ;
     RECT  9 82.589 9.99 82.949 ;
     RECT  10.8 82.553 10.854 82.973 ;
     RECT  17.1 82.781 17.118 82.973 ;
     RECT  0.18 82.925 1.17 83.021 ;
     RECT  22.248 82.831 198.63 83.021 ;
     RECT  9 82.949 9.126 83.117 ;
     RECT  199.908 82.291 200.826 83.179 ;
     RECT  0.252 83.021 1.17 83.291 ;
     RECT  18.615 82.747 18.99 83.323 ;
     RECT  2.304 82.589 8.226 83.335 ;
     RECT  2.232 83.335 8.226 83.371 ;
     RECT  9 83.117 9.054 83.371 ;
     RECT  10.836 82.973 10.854 83.399 ;
     RECT  199.512 83.179 200.826 83.399 ;
     RECT  0.252 83.291 0.594 83.405 ;
     RECT  22.752 83.021 198.63 83.489 ;
     RECT  21.06 82.699 21.078 83.605 ;
     RECT  0.252 83.405 0.522 83.693 ;
     RECT  20.52 83.605 21.078 83.755 ;
     RECT  9.9 82.949 9.99 83.759 ;
     RECT  22.788 83.489 198.63 83.767 ;
     RECT  2.232 83.371 9.054 84.139 ;
     RECT  22.788 83.767 198.954 84.181 ;
     RECT  199.8 83.399 200.826 84.181 ;
     RECT  18.615 83.323 19.062 84.235 ;
     RECT  2.232 84.139 9.126 84.269 ;
     RECT  13.215 82.688 13.497 84.271 ;
     RECT  18.615 84.235 19.386 84.307 ;
     RECT  13.104 84.271 13.497 84.317 ;
     RECT  17.1 84.139 17.118 84.317 ;
     RECT  18.216 84.307 19.386 84.365 ;
     RECT  20.484 83.755 21.078 84.365 ;
     RECT  2.268 84.269 9.126 84.379 ;
     RECT  10.8 84.379 10.818 84.451 ;
     RECT  18.615 84.365 19.386 84.479 ;
     RECT  0.252 83.693 0.306 84.509 ;
     RECT  22.788 84.181 200.826 84.523 ;
     RECT  22.752 84.523 200.826 84.557 ;
     RECT  2.268 84.379 9.234 84.569 ;
     RECT  10.692 84.451 10.818 84.619 ;
     RECT  10.692 84.619 10.854 84.64 ;
     RECT  20.484 84.365 20.97 84.649 ;
     RECT  19.8 84.649 20.97 84.749 ;
     RECT  22.752 84.557 198.63 84.811 ;
     RECT  9.216 84.569 9.234 84.839 ;
     RECT  22.716 84.811 198.63 84.911 ;
     RECT  18.615 84.479 18.897 85.099 ;
     RECT  20.952 84.749 20.97 85.099 ;
     RECT  2.268 84.569 8.406 85.117 ;
     RECT  20.952 85.099 21.078 85.133 ;
     RECT  10.656 84.64 10.854 85.351 ;
     RECT  10.224 85.351 10.854 85.387 ;
     RECT  18.144 85.099 18.897 85.415 ;
     RECT  18.18 85.415 18.897 85.421 ;
     RECT  1.728 85.117 8.406 85.435 ;
     RECT  22.788 84.911 198.63 85.459 ;
     RECT  199.476 84.557 200.826 85.459 ;
     RECT  10.224 85.387 10.926 85.487 ;
     RECT  1.728 85.435 8.478 85.517 ;
     RECT  9.396 85.261 9.414 85.531 ;
     RECT  10.224 85.487 10.782 85.531 ;
     RECT  19.8 84.749 19.926 85.559 ;
     RECT  18.216 85.421 18.897 85.579 ;
     RECT  2.268 85.517 8.478 85.621 ;
     RECT  9.396 85.531 10.782 85.621 ;
     RECT  2.268 85.621 10.782 85.649 ;
     RECT  21.06 85.133 21.078 85.675 ;
     RECT  18.216 85.579 18.99 85.757 ;
     RECT  0.288 84.509 0.306 85.765 ;
     RECT  0.108 85.765 0.306 85.805 ;
     RECT  19.836 85.559 19.926 85.829 ;
     RECT  10.224 85.649 10.782 85.919 ;
     RECT  21.06 85.675 21.654 86.155 ;
     RECT  22.788 85.459 200.826 86.155 ;
     RECT  0.144 85.805 0.306 86.251 ;
     RECT  2.268 85.649 9.198 86.285 ;
     RECT  18.216 85.757 18.897 86.299 ;
     RECT  0.144 86.251 0.45 86.305 ;
     RECT  10.332 85.919 10.782 86.305 ;
     RECT  21.06 86.155 200.826 86.381 ;
     RECT  10.332 86.305 10.962 86.431 ;
     RECT  21.06 86.381 198.63 86.443 ;
     RECT  20.952 86.443 198.63 86.459 ;
     RECT  2.304 86.285 9.198 86.495 ;
     RECT  10.332 86.431 11.034 86.567 ;
     RECT  0.144 86.305 0.558 86.573 ;
     RECT  20.952 86.459 21.078 86.573 ;
     RECT  18.18 86.299 18.897 86.635 ;
     RECT  199.404 86.381 200.826 86.669 ;
     RECT  0.108 86.728 0.126 86.765 ;
     RECT  2.34 86.495 9.198 86.773 ;
     RECT  10.332 86.567 10.854 86.773 ;
     RECT  16.416 86.731 16.434 86.779 ;
     RECT  2.34 86.773 10.854 86.837 ;
     RECT  18.18 86.635 18.99 86.909 ;
     RECT  19.836 85.829 19.854 86.999 ;
     RECT  10.836 86.837 10.854 87.071 ;
     RECT  22.14 86.459 198.63 87.071 ;
     RECT  2.34 86.837 9.738 87.179 ;
     RECT  199.476 86.669 200.826 87.245 ;
     RECT  2.34 87.179 9.378 87.269 ;
     RECT  22.176 87.071 198.63 87.269 ;
     RECT  2.34 87.269 9.126 87.385 ;
     RECT  21.06 86.573 21.078 87.403 ;
     RECT  16.416 86.779 16.506 87.547 ;
     RECT  17.64 87.115 17.694 87.547 ;
     RECT  15.984 87.547 16.506 87.629 ;
     RECT  16.488 87.629 16.506 87.683 ;
     RECT  20.448 87.403 21.078 87.725 ;
     RECT  20.448 87.725 20.502 87.845 ;
     RECT  17.604 87.547 17.694 87.883 ;
     RECT  18.615 86.909 18.99 87.883 ;
     RECT  2.304 87.385 9.126 87.917 ;
     RECT  10.908 87.421 10.926 87.925 ;
     RECT  18.615 87.883 19.098 88.075 ;
     RECT  10.368 87.925 10.926 88.079 ;
     RECT  18.615 88.075 19.386 88.115 ;
     RECT  18.615 88.115 19.098 88.157 ;
     RECT  199.872 87.245 200.826 88.195 ;
     RECT  17.064 87.883 17.694 88.205 ;
     RECT  14.832 87.883 14.85 88.219 ;
     RECT  10.728 88.079 10.926 88.231 ;
     RECT  2.304 87.917 8.802 88.349 ;
     RECT  10.728 88.231 10.962 88.349 ;
     RECT  0.108 87.787 0.126 88.456 ;
     RECT  18.615 88.157 18.99 88.591 ;
     RECT  14.832 88.219 15.39 88.603 ;
     RECT  18.504 88.591 18.99 88.637 ;
     RECT  22.212 87.269 198.63 88.651 ;
     RECT  17.064 88.205 17.082 88.655 ;
     RECT  10.728 88.349 10.818 88.799 ;
     RECT  14.796 88.603 15.39 88.799 ;
     RECT  199.44 88.195 200.826 88.861 ;
     RECT  15.948 88.891 15.966 89.005 ;
     RECT  0.108 88.456 0.162 89.069 ;
     RECT  10.8 88.799 10.818 89.069 ;
     RECT  2.304 88.349 8.73 89.131 ;
     RECT  2.304 89.131 8.874 89.203 ;
     RECT  15.948 89.005 16.578 89.213 ;
     RECT  20.484 87.845 20.502 89.227 ;
     RECT  15.948 89.213 16.542 89.339 ;
     RECT  18.615 88.637 18.99 89.357 ;
     RECT  20.448 89.227 20.502 89.419 ;
     RECT  10.908 89.311 10.926 89.429 ;
     RECT  2.304 89.203 9.162 89.437 ;
     RECT  22.176 88.651 198.63 89.473 ;
     RECT  199.368 88.861 200.826 89.473 ;
     RECT  22.176 89.473 200.826 89.501 ;
     RECT  22.716 89.501 200.826 89.549 ;
     RECT  14.796 88.799 14.814 89.609 ;
     RECT  20.448 89.419 21.078 89.611 ;
     RECT  2.304 89.437 9.486 89.851 ;
     RECT  0.108 89.069 0.126 89.879 ;
     RECT  20.448 89.611 21.654 89.899 ;
     RECT  13.215 84.317 13.497 89.941 ;
     RECT  22.716 89.549 198.63 89.969 ;
     RECT  2.304 89.851 9.81 89.977 ;
     RECT  13.215 89.941 13.662 89.981 ;
     RECT  2.268 89.977 9.81 90.049 ;
     RECT  18.615 89.357 18.897 90.085 ;
     RECT  22.716 89.969 198.378 90.113 ;
     RECT  2.268 90.049 9.918 90.121 ;
     RECT  16.488 89.339 16.542 90.239 ;
     RECT  18.108 90.085 18.897 90.239 ;
     RECT  2.268 90.121 10.242 90.247 ;
     RECT  19.908 89.899 21.654 90.275 ;
     RECT  19.908 90.275 20.214 90.347 ;
     RECT  18.576 90.239 18.897 90.379 ;
     RECT  16.488 90.239 16.506 90.419 ;
     RECT  2.268 90.247 10.818 90.509 ;
     RECT  18.576 90.379 18.99 90.557 ;
     RECT  19.908 90.347 20.034 90.571 ;
     RECT  7.524 90.509 8.514 90.617 ;
     RECT  1.152 89.707 1.17 90.689 ;
     RECT  0.144 90.427 0.162 90.763 ;
     RECT  22.752 90.113 198.378 90.787 ;
     RECT  0.144 90.763 0.198 90.823 ;
     RECT  22.752 90.787 198.45 90.823 ;
     RECT  0.144 90.823 0.234 90.859 ;
     RECT  9.252 90.509 10.818 90.931 ;
     RECT  199.44 89.549 200.826 90.931 ;
     RECT  22.752 90.823 198.522 90.959 ;
     RECT  0.144 90.859 0.342 90.989 ;
     RECT  9.252 90.931 10.854 91.049 ;
     RECT  22.752 90.959 198.378 91.193 ;
     RECT  18.576 90.557 18.897 91.201 ;
     RECT  19.8 90.571 20.034 91.201 ;
     RECT  2.268 90.509 6.786 91.243 ;
     RECT  7.524 90.617 8.442 91.243 ;
     RECT  199.332 90.931 200.826 91.277 ;
     RECT  13.215 89.981 13.497 91.291 ;
     RECT  18.36 91.201 18.897 91.291 ;
     RECT  19.8 91.201 20.106 91.319 ;
     RECT  13.104 91.291 13.497 91.328 ;
     RECT  0.144 90.989 0.234 91.421 ;
     RECT  2.268 91.243 8.442 91.469 ;
     RECT  9.468 91.049 10.854 91.471 ;
     RECT  20.988 90.275 21.654 91.531 ;
     RECT  22.752 91.193 198.09 91.531 ;
     RECT  2.304 91.469 8.442 91.561 ;
     RECT  0.216 91.421 0.234 91.613 ;
     RECT  18.288 91.291 18.897 91.613 ;
     RECT  16.524 91.399 16.542 91.741 ;
     RECT  9.468 91.471 10.89 91.771 ;
     RECT  2.304 91.561 8.586 91.903 ;
     RECT  9.36 91.771 10.89 91.903 ;
     RECT  19.908 91.319 20.106 91.915 ;
     RECT  20.988 91.531 198.09 91.915 ;
     RECT  16.524 91.741 17.118 91.931 ;
     RECT  19.908 91.915 198.09 91.975 ;
     RECT  14.256 91.363 14.274 92.011 ;
     RECT  2.304 91.903 10.89 92.039 ;
     RECT  19.908 91.975 198.522 92.084 ;
     RECT  9.36 92.039 10.89 92.129 ;
     RECT  16.56 91.931 17.118 92.129 ;
     RECT  19.908 92.084 198.45 92.129 ;
     RECT  19.98 92.129 198.45 92.141 ;
     RECT  21.06 92.141 198.45 92.165 ;
     RECT  21.06 92.165 198.414 92.399 ;
     RECT  199.836 91.277 200.826 92.407 ;
     RECT  21.564 92.399 198.414 92.435 ;
     RECT  199.728 92.407 200.826 92.551 ;
     RECT  14.256 92.011 14.922 92.579 ;
     RECT  1.152 92.587 1.17 92.683 ;
     RECT  2.304 92.039 8.586 92.705 ;
     RECT  19.98 92.141 19.998 92.875 ;
     RECT  21.6 92.435 198.414 92.983 ;
     RECT  17.676 92.281 17.694 93.011 ;
     RECT  9.612 92.129 10.818 93.019 ;
     RECT  12.24 89.977 12.258 93.091 ;
     RECT  9.216 93.019 10.818 93.119 ;
     RECT  14.868 92.579 14.922 93.119 ;
     RECT  9.612 93.119 10.818 93.209 ;
     RECT  21.6 92.983 198.45 93.245 ;
     RECT  18.615 91.613 18.897 93.289 ;
     RECT  19.98 92.875 20.502 93.289 ;
     RECT  16.56 92.129 16.614 93.325 ;
     RECT  13.215 91.328 13.497 93.352 ;
     RECT  21.6 93.245 198.09 93.353 ;
     RECT  0.108 92.875 0.126 93.355 ;
     RECT  2.304 92.705 8.406 93.355 ;
     RECT  13.104 93.352 13.497 93.361 ;
     RECT  2.232 93.355 8.406 93.451 ;
     RECT  0.108 93.355 0.162 93.547 ;
     RECT  14.868 93.119 14.886 93.595 ;
     RECT  11.916 93.091 12.258 93.631 ;
     RECT  0.108 93.547 0.198 93.643 ;
     RECT  0.108 93.643 0.234 93.739 ;
     RECT  18.615 93.289 20.502 93.739 ;
     RECT  11.736 93.631 12.258 93.749 ;
     RECT  9.792 93.209 10.818 93.829 ;
     RECT  13.104 93.361 13.518 93.829 ;
     RECT  14.832 93.595 14.886 93.857 ;
     RECT  18.615 93.739 20.574 93.865 ;
     RECT  1.152 92.683 1.206 93.893 ;
     RECT  16.524 93.325 16.614 93.893 ;
     RECT  2.232 93.451 8.442 93.901 ;
     RECT  16.524 93.893 16.542 93.901 ;
     RECT  9.792 93.829 10.926 93.929 ;
     RECT  13.104 93.829 13.554 93.929 ;
     RECT  14.868 93.857 14.886 93.929 ;
     RECT  0.108 93.739 0.27 93.979 ;
     RECT  2.232 93.901 8.55 94.019 ;
     RECT  9.792 93.929 10.854 94.019 ;
     RECT  13.215 93.929 13.554 94.019 ;
     RECT  18.615 93.865 20.61 94.027 ;
     RECT  21.636 93.353 198.09 94.027 ;
     RECT  198.936 93.451 198.954 94.027 ;
     RECT  21.636 94.027 198.954 94.157 ;
     RECT  9.792 94.019 10.782 94.171 ;
     RECT  15.984 93.901 16.542 94.199 ;
     RECT  9.684 94.171 10.782 94.289 ;
     RECT  199.692 92.551 200.826 94.289 ;
     RECT  18.504 94.027 20.61 94.315 ;
     RECT  21.636 94.157 198.45 94.315 ;
     RECT  2.232 94.019 8.37 94.411 ;
     RECT  18.504 94.315 198.45 94.559 ;
     RECT  0.108 93.979 0.486 94.612 ;
     RECT  199.692 94.289 200.034 94.667 ;
     RECT  18.504 94.559 19.746 94.739 ;
     RECT  20.484 94.559 198.45 94.739 ;
     RECT  19.656 94.739 19.746 94.829 ;
     RECT  20.484 94.739 21.654 94.829 ;
     RECT  12.24 93.749 12.258 94.837 ;
     RECT  13.215 94.019 13.497 94.837 ;
     RECT  18.504 94.739 18.897 94.873 ;
     RECT  19.728 94.829 19.746 94.937 ;
     RECT  9.9 94.289 10.782 94.945 ;
     RECT  20.484 94.829 21.078 94.973 ;
     RECT  12.24 94.837 13.497 95.009 ;
     RECT  22.788 94.739 198.45 95.071 ;
     RECT  1.692 94.411 8.37 95.099 ;
     RECT  9.144 94.981 9.162 95.099 ;
     RECT  22.788 95.071 198.63 95.099 ;
     RECT  199.692 94.667 199.998 95.099 ;
     RECT  9.9 94.945 10.818 95.135 ;
     RECT  0.144 94.612 0.486 95.251 ;
     RECT  0.144 95.251 0.558 95.309 ;
     RECT  0.144 95.309 0.486 95.357 ;
     RECT  21.024 94.973 21.078 95.369 ;
     RECT  200.808 94.289 200.826 95.369 ;
     RECT  12.564 95.009 13.497 95.513 ;
     RECT  16.524 94.199 16.542 95.549 ;
     RECT  9.9 95.135 10.782 95.639 ;
     RECT  21.024 95.369 21.042 95.639 ;
     RECT  1.692 95.099 8.334 95.659 ;
     RECT  0.144 95.357 0.306 95.755 ;
     RECT  0.108 95.755 0.306 95.933 ;
     RECT  1.656 95.659 8.334 95.947 ;
     RECT  1.296 95.947 8.334 96.043 ;
     RECT  9.9 95.639 10.242 96.179 ;
     RECT  1.188 96.043 8.334 96.601 ;
     RECT  0.108 95.933 0.126 96.653 ;
     RECT  1.188 96.601 8.838 96.863 ;
     RECT  18.252 94.873 18.897 97.097 ;
     RECT  2.304 96.863 8.838 97.169 ;
     RECT  1.188 96.863 1.35 97.295 ;
     RECT  14.256 95.647 14.274 97.529 ;
     RECT  1.332 97.295 1.35 97.871 ;
     RECT  2.304 97.169 6.75 97.951 ;
     RECT  7.524 97.169 8.838 97.951 ;
     RECT  2.304 97.951 8.838 97.997 ;
     RECT  22.896 95.099 198.63 98.059 ;
     RECT  2.304 97.997 6.786 98.093 ;
     RECT  199.692 95.099 199.962 98.221 ;
     RECT  18.504 97.097 18.897 98.339 ;
     RECT  199.692 98.221 199.998 98.339 ;
     RECT  22.896 98.059 198.702 98.491 ;
     RECT  199.692 98.339 199.962 98.491 ;
     RECT  2.304 98.093 6.498 98.669 ;
     RECT  6.336 98.669 6.498 99.149 ;
     RECT  2.304 98.669 5.598 99.419 ;
     RECT  2.304 99.419 5.526 99.689 ;
     RECT  2.415 99.689 5.526 100.265 ;
     RECT  2.415 100.265 3.798 100.499 ;
     RECT  3.78 100.499 3.798 102.619 ;
     RECT  3.708 102.619 3.798 102.965 ;
     RECT  3.78 102.965 3.798 103.081 ;
     RECT  4.644 100.265 5.526 103.081 ;
     RECT  22.896 98.491 199.962 104.299 ;
     RECT  22.896 104.299 199.998 104.549 ;
     RECT  22.896 104.549 199.962 124.488 ;
     RECT  198.108 124.488 199.962 125.141 ;
     RECT  10.224 96.179 10.242 125.681 ;
     RECT  66.672 124.488 66.69 125.689 ;
     RECT  7.815 97.997 8.838 125.717 ;
     RECT  66.384 125.689 66.69 126.229 ;
     RECT  3.78 103.081 5.526 126.257 ;
     RECT  66.384 126.229 67.194 126.265 ;
     RECT  68.364 124.488 68.382 126.265 ;
     RECT  8.82 125.717 8.838 126.293 ;
     RECT  70.164 125.653 70.182 126.301 ;
     RECT  198.108 125.141 199.89 126.329 ;
     RECT  198.108 126.329 199.818 126.563 ;
     RECT  3.78 126.257 4.662 126.599 ;
     RECT  61.632 126.265 61.65 126.613 ;
     RECT  65.484 126.229 65.502 126.689 ;
     RECT  66.384 126.265 68.382 126.689 ;
     RECT  69.156 125.653 69.174 126.689 ;
     RECT  70.164 126.301 70.29 126.689 ;
     RECT  85.32 126.571 85.338 126.689 ;
     RECT  66.384 126.689 67.914 126.797 ;
     RECT  83.607 126.613 83.697 126.805 ;
     RECT  198.108 126.563 199.746 126.869 ;
     RECT  24.207 126.613 24.297 126.883 ;
     RECT  29.607 126.613 29.697 126.883 ;
     RECT  35.007 126.613 35.097 126.883 ;
     RECT  40.407 126.613 40.497 126.883 ;
     RECT  45.807 126.613 45.897 126.883 ;
     RECT  51.207 126.613 51.297 126.883 ;
     RECT  56.607 126.613 56.697 126.883 ;
     RECT  72.807 126.613 72.897 126.883 ;
     RECT  78.207 126.613 78.297 126.883 ;
     RECT  83.607 126.805 84.222 126.883 ;
     RECT  89.007 126.613 89.097 126.883 ;
     RECT  94.407 126.613 94.497 126.883 ;
     RECT  99.807 126.613 99.897 126.883 ;
     RECT  105.207 126.613 105.297 126.883 ;
     RECT  110.607 126.613 110.697 126.883 ;
     RECT  116.007 126.613 116.097 126.883 ;
     RECT  121.407 126.613 121.497 126.883 ;
     RECT  126.807 126.613 126.897 126.883 ;
     RECT  132.207 126.613 132.297 126.883 ;
     RECT  137.607 126.613 137.697 126.883 ;
     RECT  143.007 126.613 143.097 126.883 ;
     RECT  148.407 126.613 148.497 126.883 ;
     RECT  153.807 126.613 153.897 126.883 ;
     RECT  159.207 126.613 159.297 126.883 ;
     RECT  164.607 126.613 164.697 126.883 ;
     RECT  170.007 126.613 170.097 126.883 ;
     RECT  175.407 126.613 175.497 126.883 ;
     RECT  180.807 126.613 180.897 126.883 ;
     RECT  186.207 126.613 186.297 126.883 ;
     RECT  191.607 126.613 191.697 126.883 ;
     RECT  197.007 126.613 197.097 126.883 ;
     RECT  66.384 126.797 67.806 126.959 ;
     RECT  70.164 126.689 70.182 126.959 ;
     RECT  69.048 126.931 69.066 126.989 ;
     RECT  6.48 99.149 6.498 127.139 ;
     RECT  61.632 126.613 62.097 127.237 ;
     RECT  3.78 126.599 3.942 127.265 ;
     RECT  61.632 127.237 62.73 127.337 ;
     RECT  3.78 127.265 3.798 127.409 ;
     RECT  66.384 126.959 67.497 127.499 ;
     RECT  198.108 126.869 199.206 127.499 ;
     RECT  5.472 126.257 5.526 127.769 ;
     RECT  198.108 127.499 198.666 127.769 ;
     RECT  66.384 127.499 66.402 128.039 ;
     RECT  198.612 127.769 198.666 128.039 ;
     RECT  51.015 126.883 51.297 128.551 ;
     RECT  83.415 126.883 84.222 128.579 ;
     RECT  94.215 126.883 94.497 128.821 ;
     RECT  198.648 128.039 198.666 128.885 ;
     RECT  96.876 128.857 96.894 129.029 ;
     RECT  51.015 128.551 51.894 129.119 ;
     RECT  5.472 127.769 5.49 129.155 ;
     RECT  93.744 128.821 94.497 138.299 ;
     RECT  61.632 127.337 62.097 138.335 ;
     RECT  2.415 100.499 2.697 174.707 ;
     RECT  7.815 125.717 8.097 174.707 ;
     RECT  13.215 95.513 13.497 174.707 ;
     RECT  18.615 98.339 18.897 174.707 ;
     RECT  24.015 126.883 24.297 174.707 ;
     RECT  29.415 126.883 29.697 174.707 ;
     RECT  34.815 126.883 35.097 174.707 ;
     RECT  40.215 126.883 40.497 174.707 ;
     RECT  45.615 126.883 45.897 174.707 ;
     RECT  51.015 129.119 51.297 174.707 ;
     RECT  56.415 126.883 56.697 174.707 ;
     RECT  61.815 138.335 62.097 174.707 ;
     RECT  67.215 127.499 67.497 174.707 ;
     RECT  72.615 126.883 72.897 174.707 ;
     RECT  78.015 126.883 78.297 174.707 ;
     RECT  83.415 128.579 83.697 174.707 ;
     RECT  88.815 126.883 89.097 174.707 ;
     RECT  94.215 138.299 94.497 174.707 ;
     RECT  99.615 126.883 99.897 174.707 ;
     RECT  105.015 126.883 105.297 174.707 ;
     RECT  110.415 126.883 110.697 174.707 ;
     RECT  115.815 126.883 116.097 174.707 ;
     RECT  121.215 126.883 121.497 174.707 ;
     RECT  126.615 126.883 126.897 174.707 ;
     RECT  132.015 126.883 132.297 174.707 ;
     RECT  137.415 126.883 137.697 174.707 ;
     RECT  142.815 126.883 143.097 174.707 ;
     RECT  148.215 126.883 148.497 174.707 ;
     RECT  153.615 126.883 153.897 174.707 ;
     RECT  159.015 126.883 159.297 174.707 ;
     RECT  164.415 126.883 164.697 174.707 ;
     RECT  169.815 126.883 170.097 174.707 ;
     RECT  175.215 126.883 175.497 174.707 ;
     RECT  180.615 126.883 180.897 174.707 ;
     RECT  186.015 126.883 186.297 174.707 ;
     RECT  191.415 126.883 191.697 174.707 ;
     RECT  196.815 126.883 197.097 174.707 ;
     RECT  202.215 76.037 202.497 174.707 ;
     RECT  207.615 76.775 207.897 174.707 ;
     RECT  213.015 79.979 213.297 174.707 ;
     RECT  2.415 174.707 2.505 174.977 ;
     RECT  7.815 174.707 7.905 174.977 ;
     RECT  13.215 174.707 13.305 174.977 ;
     RECT  18.615 174.707 18.705 174.977 ;
     RECT  24.015 174.707 24.105 174.977 ;
     RECT  29.415 174.707 29.505 174.977 ;
     RECT  34.815 174.707 34.905 174.977 ;
     RECT  40.215 174.707 40.305 174.977 ;
     RECT  45.615 174.707 45.705 174.977 ;
     RECT  51.015 174.707 51.105 174.977 ;
     RECT  56.415 174.707 56.505 174.977 ;
     RECT  61.815 174.707 61.905 174.977 ;
     RECT  67.215 174.707 67.305 174.977 ;
     RECT  72.615 174.707 72.705 174.977 ;
     RECT  78.015 174.707 78.105 174.977 ;
     RECT  83.415 174.707 83.505 174.977 ;
     RECT  88.815 174.707 88.905 174.977 ;
     RECT  94.215 174.707 94.305 174.977 ;
     RECT  99.615 174.707 99.705 174.977 ;
     RECT  105.015 174.707 105.105 174.977 ;
     RECT  110.415 174.707 110.505 174.977 ;
     RECT  115.815 174.707 115.905 174.977 ;
     RECT  121.215 174.707 121.305 174.977 ;
     RECT  126.615 174.707 126.705 174.977 ;
     RECT  132.015 174.707 132.105 174.977 ;
     RECT  137.415 174.707 137.505 174.977 ;
     RECT  142.815 174.707 142.905 174.977 ;
     RECT  148.215 174.707 148.305 174.977 ;
     RECT  153.615 174.707 153.705 174.977 ;
     RECT  159.015 174.707 159.105 174.977 ;
     RECT  164.415 174.707 164.505 174.977 ;
     RECT  169.815 174.707 169.905 174.977 ;
     RECT  175.215 174.707 175.305 174.977 ;
     RECT  180.615 174.707 180.705 174.977 ;
     RECT  186.015 174.707 186.105 174.977 ;
     RECT  191.415 174.707 191.505 174.977 ;
     RECT  196.815 174.707 196.905 174.977 ;
     RECT  202.215 174.707 202.305 174.977 ;
     RECT  207.615 174.707 207.705 174.977 ;
     RECT  213.015 174.707 213.105 174.977 ;
    LAYER M4 ;
     RECT  0.037 96.624 0.06 96.648 ;
     RECT  0.06 51.984 0.133 64.968 ;
     RECT  0.06 81.168 0.133 96.648 ;
     RECT  0.037 98.16 0.133 98.184 ;
     RECT  0.133 51.84 0.181 65.016 ;
     RECT  0.133 80.352 0.181 96.648 ;
     RECT  0.181 51.648 0.229 65.016 ;
     RECT  0.181 66.768 0.229 66.792 ;
     RECT  0.181 79.728 0.229 96.648 ;
     RECT  0.133 98.064 0.229 98.664 ;
     RECT  0.229 51.264 0.277 65.016 ;
     RECT  0.229 66.144 0.277 66.792 ;
     RECT  0.181 99.792 0.277 99.816 ;
     RECT  0.277 51.12 0.325 66.792 ;
     RECT  0.229 79.008 0.325 98.664 ;
     RECT  0.325 78.624 0.517 98.664 ;
     RECT  0.325 51.024 2.293 66.792 ;
     RECT  0.517 78.48 2.293 98.664 ;
     RECT  0.277 99.744 2.293 99.816 ;
     RECT  0.06 44.016 2.408 45.768 ;
     RECT  2.293 50.64 2.408 66.84 ;
     RECT  2.293 78.432 2.408 99.816 ;
     RECT  2.408 2.148 2.512 174.972 ;
     RECT  2.512 2.418 2.704 174.702 ;
     RECT  2.704 49.008 3.709 67.848 ;
     RECT  2.704 78.432 3.709 100.344 ;
     RECT  2.704 44.784 3.781 46.344 ;
     RECT  3.697 102.624 3.827 102.648 ;
     RECT  3.781 44.64 3.836 46.344 ;
     RECT  3.836 43.776 3.925 46.344 ;
     RECT  3.709 78.432 4.061 100.008 ;
     RECT  3.709 49.488 4.249 67.848 ;
     RECT  4.061 78.528 4.259 100.008 ;
     RECT  4.259 79.104 4.349 100.008 ;
     RECT  4.349 79.104 4.403 86.952 ;
     RECT  4.349 87.936 4.403 99.768 ;
     RECT  3.949 107.184 4.499 107.208 ;
     RECT  4.403 87.936 4.601 99.528 ;
     RECT  3.925 43.776 4.837 46.776 ;
     RECT  4.837 43.776 4.844 46.872 ;
     RECT  4.601 87.936 5.005 99.24 ;
     RECT  4.403 79.152 5.027 86.952 ;
     RECT  4.249 49.488 5.141 67.416 ;
     RECT  5.141 49.488 5.285 67.368 ;
     RECT  5.027 79.296 5.321 86.952 ;
     RECT  5.321 79.728 5.353 86.952 ;
     RECT  5.005 87.936 5.353 99.192 ;
     RECT  5.285 49.488 5.42 67.32 ;
     RECT  4.741 42.432 5.461 42.456 ;
     RECT  4.844 43.728 5.461 46.872 ;
     RECT  5.42 49.008 5.507 67.32 ;
     RECT  5.507 49.488 5.609 67.32 ;
     RECT  5.353 79.728 5.653 99.192 ;
     RECT  5.461 42.432 5.845 46.872 ;
     RECT  2.704 47.904 5.845 47.928 ;
     RECT  5.609 49.488 6.193 67.272 ;
     RECT  5.653 79.728 6.229 98.664 ;
     RECT  6.229 79.728 6.293 96.984 ;
     RECT  6.229 97.968 6.409 98.664 ;
     RECT  5.845 42.432 6.469 47.928 ;
     RECT  6.469 42.432 6.649 47.976 ;
     RECT  5.413 40.032 6.661 40.056 ;
     RECT  6.649 42.432 6.805 48.264 ;
     RECT  6.193 49.488 6.805 66.696 ;
     RECT  6.661 40.032 7.429 40.296 ;
     RECT  7.429 40.032 7.808 40.68 ;
     RECT  6.805 42.432 7.808 66.696 ;
     RECT  6.293 79.728 7.808 96.936 ;
     RECT  6.409 97.968 7.808 98.088 ;
     RECT  6.757 126.672 7.808 126.696 ;
     RECT  7.808 2.148 7.912 174.972 ;
     RECT  7.912 2.418 8.104 174.702 ;
     RECT  8.104 81.6 8.309 94.968 ;
     RECT  8.104 44.064 8.579 64.728 ;
     RECT  8.309 81.6 8.813 94.92 ;
     RECT  8.104 40.032 9.205 40.872 ;
     RECT  8.104 42.432 9.241 43.032 ;
     RECT  8.579 44.64 9.347 64.728 ;
     RECT  9.241 42.432 9.749 43.56 ;
     RECT  8.104 70.512 9.781 70.536 ;
     RECT  9.205 39.744 9.98 40.872 ;
     RECT  9.98 39.744 10.067 41.016 ;
     RECT  9.781 70.464 10.067 70.536 ;
     RECT  9.347 44.64 10.249 64.296 ;
     RECT  10.249 44.592 10.289 64.296 ;
     RECT  10.289 44.592 10.499 64.056 ;
     RECT  10.499 44.592 10.549 57.048 ;
     RECT  10.499 58.464 10.643 64.056 ;
     RECT  10.643 62.208 10.691 64.056 ;
     RECT  10.691 62.208 10.787 62.808 ;
     RECT  10.643 58.464 10.835 61.224 ;
     RECT  9.749 42.432 10.865 43.368 ;
     RECT  10.865 42.48 10.969 43.368 ;
     RECT  10.549 44.352 10.969 57.048 ;
     RECT  10.835 59.856 11.171 61.224 ;
     RECT  10.969 42.48 11.507 57.048 ;
     RECT  11.507 44.064 11.549 57.048 ;
     RECT  11.549 44.352 12.017 57.048 ;
     RECT  8.813 81.6 12.089 86.04 ;
     RECT  10.691 63.792 12.121 64.056 ;
     RECT  11.171 60.816 12.841 61.224 ;
     RECT  12.017 44.352 13.057 54.36 ;
     RECT  12.017 55.488 13.057 57.048 ;
     RECT  12.697 7.392 13.093 7.416 ;
     RECT  13.093 6.288 13.208 6.312 ;
     RECT  13.093 7.392 13.208 7.992 ;
     RECT  10.067 39.744 13.208 40.872 ;
     RECT  11.507 42.48 13.208 43.032 ;
     RECT  13.057 44.352 13.208 57.048 ;
     RECT  10.835 58.464 13.208 58.536 ;
     RECT  12.841 60.624 13.208 61.224 ;
     RECT  10.787 62.304 13.208 62.808 ;
     RECT  12.121 63.792 13.208 64.44 ;
     RECT  8.104 65.712 13.208 66.312 ;
     RECT  8.104 68.64 13.208 68.664 ;
     RECT  10.067 70.512 13.208 70.536 ;
     RECT  8.104 80.256 13.208 80.28 ;
     RECT  12.089 82.128 13.208 86.04 ;
     RECT  8.813 87.36 13.208 94.92 ;
     RECT  8.104 126.672 13.208 126.984 ;
     RECT  13.208 2.148 13.312 174.972 ;
     RECT  13.312 2.418 13.504 174.702 ;
     RECT  13.504 7.392 13.889 7.992 ;
     RECT  13.889 7.392 14.285 7.416 ;
     RECT  13.504 39.024 14.485 43.032 ;
     RECT  13.504 58.464 14.485 59.304 ;
     RECT  14.485 38.16 14.492 43.032 ;
     RECT  13.504 71.616 14.533 72.504 ;
     RECT  13.504 62.304 14.677 66.312 ;
     RECT  13.504 67.296 14.677 67.32 ;
     RECT  13.504 44.352 14.732 57.048 ;
     RECT  14.485 58.368 14.732 59.304 ;
     RECT  14.492 38.016 14.749 43.032 ;
     RECT  13.504 80.256 14.785 80.28 ;
     RECT  14.732 44.352 14.819 59.304 ;
     RECT  13.504 5.136 14.821 5.16 ;
     RECT  14.677 62.304 14.821 67.32 ;
     RECT  14.821 5.136 14.861 5.736 ;
     RECT  13.504 70.608 14.869 70.632 ;
     RECT  14.533 71.616 14.869 73.08 ;
     RECT  14.869 70.608 14.897 73.08 ;
     RECT  14.821 77.952 14.905 78.696 ;
     RECT  14.897 70.992 14.956 73.08 ;
     RECT  13.504 68.64 15.037 68.664 ;
     RECT  14.821 62.304 15.107 67.416 ;
     RECT  14.819 58.368 15.113 58.92 ;
     RECT  15.107 66.72 15.289 67.416 ;
     RECT  15.037 68.64 15.289 69.288 ;
     RECT  14.749 38.016 15.301 43.128 ;
     RECT  14.819 44.352 15.301 57.048 ;
     RECT  15.301 38.016 15.361 57.048 ;
     RECT  13.504 74.112 15.395 74.136 ;
     RECT  15.325 75.264 15.409 75.288 ;
     RECT  14.905 78.096 15.653 78.696 ;
     RECT  14.861 5.712 15.721 5.736 ;
     RECT  15.289 66.72 15.733 69.288 ;
     RECT  15.361 37.872 15.827 57.048 ;
     RECT  15.181 7.968 15.965 7.992 ;
     RECT  15.965 7.968 15.973 8.568 ;
     RECT  14.965 76.944 15.973 76.968 ;
     RECT  15.937 0.576 16.045 0.6 ;
     RECT  15.973 7.248 16.049 8.568 ;
     RECT  16.045 0.096 16.165 0.6 ;
     RECT  15.721 5.712 16.189 6.264 ;
     RECT  15.973 75.936 16.22 76.968 ;
     RECT  15.653 78.096 16.22 78.168 ;
     RECT  16.165 0.096 16.307 1.176 ;
     RECT  15.107 62.304 16.307 65.736 ;
     RECT  16.049 7.248 16.337 7.992 ;
     RECT  13.504 82.128 16.405 86.04 ;
     RECT  13.504 87.36 16.405 94.92 ;
     RECT  14.785 80.256 16.409 80.904 ;
     RECT  16.307 0.576 16.445 1.176 ;
     RECT  16.453 3.936 16.54 3.96 ;
     RECT  15.733 66.72 16.553 69.576 ;
     RECT  15.113 58.464 16.657 58.92 ;
     RECT  16.445 1.152 16.697 1.176 ;
     RECT  13.504 60.528 16.765 61.224 ;
     RECT  14.956 71.616 16.765 73.08 ;
     RECT  16.297 74.688 16.765 74.712 ;
     RECT  16.765 74.64 16.766 74.712 ;
     RECT  16.553 69.264 16.873 69.576 ;
     RECT  15.827 37.872 16.981 56.664 ;
     RECT  16.657 58.464 17.077 59.304 ;
     RECT  16.981 37.872 17.089 57.096 ;
     RECT  17.077 58.128 17.089 59.304 ;
     RECT  17.089 37.872 17.123 59.304 ;
     RECT  16.765 60.432 17.125 61.224 ;
     RECT  16.307 62.304 17.125 63.816 ;
     RECT  16.337 7.968 17.237 7.992 ;
     RECT  16.765 71.28 17.273 73.08 ;
     RECT  16.873 69.264 17.485 69.624 ;
     RECT  16.405 82.128 17.557 94.92 ;
     RECT  17.557 81.936 17.629 94.92 ;
     RECT  17.273 71.712 17.665 73.08 ;
     RECT  17.485 69.264 17.737 69.72 ;
     RECT  16.766 74.64 17.773 74.664 ;
     RECT  17.665 71.712 17.845 73.656 ;
     RECT  17.773 74.64 17.845 74.712 ;
     RECT  16.22 75.936 17.917 78.168 ;
     RECT  17.737 68.976 17.948 69.72 ;
     RECT  16.307 64.8 17.953 65.736 ;
     RECT  16.553 66.72 17.953 67.848 ;
     RECT  17.953 64.8 17.989 67.848 ;
     RECT  17.948 68.976 17.989 70.488 ;
     RECT  17.845 71.712 17.989 74.712 ;
     RECT  17.917 75.936 17.989 78.6 ;
     RECT  17.123 37.872 18.229 59.016 ;
     RECT  17.125 60.432 18.229 63.816 ;
     RECT  17.269 79.584 18.241 79.608 ;
     RECT  16.409 80.88 18.241 80.904 ;
     RECT  18.229 37.872 18.277 63.816 ;
     RECT  17.989 64.8 18.277 70.488 ;
     RECT  18.277 37.872 18.385 70.488 ;
     RECT  18.385 37.872 18.565 70.68 ;
     RECT  17.989 71.712 18.565 78.6 ;
     RECT  16.189 5.472 18.608 6.264 ;
     RECT  18.277 7.632 18.608 7.656 ;
     RECT  17.413 11.52 18.608 11.544 ;
     RECT  18.565 37.872 18.608 78.6 ;
     RECT  18.241 79.584 18.608 80.904 ;
     RECT  17.629 81.888 18.608 94.92 ;
     RECT  13.504 126.672 18.608 126.984 ;
     RECT  18.608 2.148 18.712 174.972 ;
     RECT  18.712 2.418 18.904 174.702 ;
     RECT  18.904 8.832 19.043 11.544 ;
     RECT  18.904 37.872 19.757 94.92 ;
     RECT  18.904 5.472 19.957 6.264 ;
     RECT  19.957 4.848 20.044 6.264 ;
     RECT  18.904 7.632 20.113 7.656 ;
     RECT  19.043 8.832 20.113 8.856 ;
     RECT  19.043 10.56 20.329 11.544 ;
     RECT  20.149 12.528 20.329 12.552 ;
     RECT  20.113 7.632 20.369 8.856 ;
     RECT  20.329 10.56 20.369 12.552 ;
     RECT  20.044 5.472 20.473 6.264 ;
     RECT  20.369 10.56 20.693 11.016 ;
     RECT  19.757 37.872 21.013 94.392 ;
     RECT  20.473 5.472 21.233 6.84 ;
     RECT  20.369 12 21.305 12.552 ;
     RECT  20.185 4.368 21.341 4.392 ;
     RECT  20.369 7.872 21.373 8.856 ;
     RECT  21.085 10.128 21.449 10.152 ;
     RECT  21.233 5.472 21.733 6.264 ;
     RECT  20.689 3.312 21.881 3.336 ;
     RECT  21.373 7.392 22.165 8.856 ;
     RECT  21.013 37.872 22.165 94.44 ;
     RECT  22.237 0.096 22.309 0.12 ;
     RECT  21.733 4.512 22.355 6.264 ;
     RECT  22.309 0.096 22.381 0.168 ;
     RECT  22.525 10.368 22.633 10.392 ;
     RECT  22.355 4.656 22.705 6.264 ;
     RECT  22.165 7.392 22.705 9.144 ;
     RECT  22.705 4.656 22.745 9.144 ;
     RECT  22.633 10.368 22.889 10.584 ;
     RECT  22.381 0.096 22.921 0.216 ;
     RECT  22.921 0.096 22.957 0.264 ;
     RECT  22.165 37.872 22.968 94.536 ;
     RECT  23.065 1.68 23.281 1.704 ;
     RECT  23.281 1.632 23.317 1.704 ;
     RECT  22.745 4.656 23.317 6.696 ;
     RECT  22.957 0.096 23.411 0.648 ;
     RECT  22.745 7.968 23.557 9.144 ;
     RECT  22.889 10.368 23.557 10.392 ;
     RECT  23.317 4.512 23.821 6.696 ;
     RECT  23.317 1.632 24.008 2.28 ;
     RECT  23.821 4.416 24.008 6.696 ;
     RECT  23.557 7.968 24.008 10.392 ;
     RECT  21.305 12.48 24.008 12.552 ;
     RECT  22.968 37.872 24.008 124.488 ;
     RECT  18.904 126.672 24.008 126.984 ;
     RECT  24.008 126.672 24.112 174.972 ;
     RECT  24.112 126.672 24.2 174.702 ;
     RECT  24.008 1.632 24.304 124.488 ;
     RECT  24.2 126.618 24.304 174.702 ;
     RECT  24.304 7.92 24.329 7.992 ;
     RECT  23.411 0.096 24.421 0.6 ;
     RECT  24.304 1.632 24.421 3 ;
     RECT  24.421 0.096 24.445 3 ;
     RECT  24.445 0.096 24.473 2.904 ;
     RECT  24.304 4.368 24.725 6.12 ;
     RECT  24.725 5.712 24.761 6.12 ;
     RECT  24.304 10.32 24.833 11.448 ;
     RECT  24.473 0.096 24.869 2.424 ;
     RECT  24.833 10.8 25.445 11.448 ;
     RECT  24.869 0.528 25.523 2.424 ;
     RECT  25.523 1.248 25.553 2.424 ;
     RECT  25.553 1.296 25.573 2.424 ;
     RECT  25.573 1.296 25.811 2.52 ;
     RECT  24.329 7.968 26.089 7.992 ;
     RECT  26.053 9.12 26.089 9.144 ;
     RECT  26.089 7.968 26.101 9.144 ;
     RECT  24.761 5.808 26.125 6.12 ;
     RECT  26.101 7.248 26.125 9.144 ;
     RECT  26.125 5.808 26.129 9.144 ;
     RECT  26.129 5.808 26.188 7.272 ;
     RECT  26.188 5.808 26.209 6.888 ;
     RECT  25.811 1.728 26.345 2.52 ;
     RECT  26.209 5.808 26.345 6.792 ;
     RECT  26.129 8.496 26.485 9.144 ;
     RECT  25.445 10.896 26.485 11.448 ;
     RECT  26.485 8.496 26.993 9.288 ;
     RECT  26.345 1.776 27.241 2.52 ;
     RECT  24.725 4.368 27.241 4.392 ;
     RECT  26.993 9.072 27.317 9.288 ;
     RECT  27.241 1.776 27.389 4.392 ;
     RECT  27.389 1.824 27.461 4.248 ;
     RECT  26.485 10.368 27.569 11.448 ;
     RECT  26.345 6.048 27.641 6.792 ;
     RECT  27.641 6.048 27.713 6.12 ;
     RECT  27.461 1.872 27.785 4.248 ;
     RECT  27.569 10.368 27.877 11.4 ;
     RECT  27.317 9.072 28.145 9.096 ;
     RECT  27.877 10.32 28.145 11.4 ;
     RECT  27.785 2.832 28.253 4.248 ;
     RECT  28.253 2.832 28.433 2.856 ;
     RECT  28.253 4.224 28.465 4.248 ;
     RECT  28.465 4.224 29.408 4.728 ;
     RECT  27.713 6.048 29.408 6.072 ;
     RECT  28.501 8.496 29.408 8.52 ;
     RECT  28.145 11.136 29.408 11.4 ;
     RECT  28.741 27.6 29.408 27.624 ;
     RECT  24.304 37.872 29.408 124.488 ;
     RECT  24.304 126.672 29.408 126.984 ;
     RECT  29.408 2.148 29.512 124.488 ;
     RECT  29.408 126.672 29.512 174.972 ;
     RECT  29.512 126.672 29.6 174.702 ;
     RECT  29.512 2.418 29.704 124.488 ;
     RECT  29.6 126.618 29.704 174.702 ;
     RECT  29.704 27.6 34.808 27.624 ;
     RECT  29.704 37.872 34.808 124.488 ;
     RECT  29.704 126.672 34.808 126.984 ;
     RECT  34.808 2.148 34.912 124.488 ;
     RECT  34.808 126.672 34.912 174.972 ;
     RECT  34.912 126.672 35 174.702 ;
     RECT  34.912 2.418 35.104 124.488 ;
     RECT  35 126.618 35.104 174.702 ;
     RECT  35.104 27.6 40.208 27.624 ;
     RECT  35.104 37.872 40.208 124.488 ;
     RECT  35.104 126.672 40.208 126.984 ;
     RECT  40.208 2.148 40.312 124.488 ;
     RECT  40.208 126.672 40.312 174.972 ;
     RECT  40.312 126.672 40.4 174.702 ;
     RECT  40.312 2.418 40.504 124.488 ;
     RECT  40.4 126.618 40.504 174.702 ;
     RECT  40.504 27.6 45.608 27.624 ;
     RECT  40.504 37.872 45.608 124.488 ;
     RECT  40.504 126.672 45.608 126.984 ;
     RECT  45.608 2.148 45.712 124.488 ;
     RECT  45.608 126.672 45.712 174.972 ;
     RECT  45.712 126.672 45.8 174.702 ;
     RECT  45.712 2.418 45.904 124.488 ;
     RECT  45.8 126.618 45.904 174.702 ;
     RECT  45.904 27.6 51.008 27.624 ;
     RECT  45.904 37.872 51.008 124.488 ;
     RECT  45.904 126.672 51.008 126.984 ;
     RECT  51.008 2.148 51.112 124.488 ;
     RECT  51.008 126.672 51.112 174.972 ;
     RECT  51.112 126.672 51.2 174.702 ;
     RECT  51.112 2.418 51.304 124.488 ;
     RECT  51.2 126.618 51.304 174.702 ;
     RECT  51.304 27.6 56.408 27.624 ;
     RECT  51.304 37.872 56.408 124.488 ;
     RECT  51.304 126.672 56.408 126.984 ;
     RECT  56.408 2.148 56.512 124.488 ;
     RECT  56.408 126.672 56.512 174.972 ;
     RECT  56.512 126.672 56.6 174.702 ;
     RECT  56.512 2.418 56.704 124.488 ;
     RECT  56.6 126.618 56.704 174.702 ;
     RECT  56.704 27.6 61.808 27.624 ;
     RECT  56.704 37.872 61.808 124.488 ;
     RECT  56.704 126.672 61.808 126.984 ;
     RECT  61.808 2.148 61.912 124.488 ;
     RECT  61.808 126.672 61.912 174.972 ;
     RECT  61.912 126.672 62 174.702 ;
     RECT  61.912 2.418 62.104 124.488 ;
     RECT  62 126.618 62.104 174.702 ;
     RECT  62.104 27.6 67.004 27.624 ;
     RECT  67.004 27.6 67.208 27.816 ;
     RECT  62.104 37.872 67.208 124.488 ;
     RECT  62.104 126.672 67.208 126.984 ;
     RECT  67.208 2.148 67.312 124.488 ;
     RECT  67.208 126.672 67.312 174.972 ;
     RECT  67.312 126.672 67.4 174.702 ;
     RECT  67.312 2.418 67.504 124.488 ;
     RECT  67.4 126.618 67.504 174.702 ;
     RECT  67.504 126.768 67.925 126.984 ;
     RECT  67.925 126.96 69.077 126.984 ;
     RECT  67.504 27.6 72.608 27.624 ;
     RECT  67.504 37.872 72.608 124.488 ;
     RECT  72.608 2.148 72.712 124.488 ;
     RECT  72.608 126.888 72.712 174.972 ;
     RECT  72.712 126.888 72.8 174.702 ;
     RECT  72.712 2.418 72.904 124.488 ;
     RECT  72.8 126.618 72.904 174.702 ;
     RECT  72.904 27.6 78.008 27.624 ;
     RECT  72.904 37.872 78.008 124.488 ;
     RECT  78.008 2.148 78.112 124.488 ;
     RECT  78.008 126.888 78.112 174.972 ;
     RECT  78.112 126.888 78.2 174.702 ;
     RECT  78.112 2.418 78.304 124.488 ;
     RECT  78.2 126.618 78.304 174.702 ;
     RECT  78.304 27.6 83.408 27.624 ;
     RECT  78.304 37.872 83.408 124.488 ;
     RECT  83.408 2.148 83.512 124.488 ;
     RECT  83.408 126.888 83.512 174.972 ;
     RECT  83.512 126.888 83.6 174.702 ;
     RECT  83.512 2.418 83.704 124.488 ;
     RECT  83.6 126.618 83.704 174.702 ;
     RECT  83.704 27.6 88.808 27.624 ;
     RECT  83.704 37.872 88.808 124.488 ;
     RECT  88.808 2.148 88.912 124.488 ;
     RECT  88.808 126.888 88.912 174.972 ;
     RECT  88.912 126.888 89 174.702 ;
     RECT  88.912 2.418 89.104 124.488 ;
     RECT  89 126.618 89.104 174.702 ;
     RECT  89.104 27.6 94.208 27.624 ;
     RECT  89.104 37.872 94.208 124.488 ;
     RECT  94.208 2.148 94.312 124.488 ;
     RECT  94.208 126.888 94.312 174.972 ;
     RECT  94.312 126.888 94.4 174.702 ;
     RECT  94.312 2.418 94.504 124.488 ;
     RECT  94.4 126.618 94.504 174.702 ;
     RECT  94.504 37.872 95.027 124.488 ;
     RECT  95.027 38.112 98.593 124.488 ;
     RECT  94.504 27.6 99.608 27.624 ;
     RECT  98.593 37.968 99.608 124.488 ;
     RECT  99.608 2.148 99.712 124.488 ;
     RECT  99.608 126.888 99.712 174.972 ;
     RECT  99.712 126.888 99.8 174.702 ;
     RECT  99.712 2.418 99.904 124.488 ;
     RECT  99.8 126.618 99.904 174.702 ;
     RECT  99.904 27.6 101.171 27.624 ;
     RECT  99.904 37.968 102.341 124.488 ;
     RECT  102.341 38.16 105.008 124.488 ;
     RECT  105.008 2.148 105.112 124.488 ;
     RECT  105.008 126.888 105.112 174.972 ;
     RECT  105.112 126.888 105.2 174.702 ;
     RECT  105.112 2.418 105.304 124.488 ;
     RECT  105.2 126.618 105.304 174.702 ;
     RECT  105.304 38.16 110.408 124.488 ;
     RECT  110.408 2.148 110.512 124.488 ;
     RECT  110.408 126.888 110.512 174.972 ;
     RECT  110.512 126.888 110.6 174.702 ;
     RECT  110.512 2.418 110.704 124.488 ;
     RECT  110.6 126.618 110.704 174.702 ;
     RECT  110.704 38.688 115.808 124.488 ;
     RECT  115.808 2.148 115.912 124.488 ;
     RECT  115.808 126.888 115.912 174.972 ;
     RECT  115.912 126.888 116 174.702 ;
     RECT  115.912 2.418 116.104 124.488 ;
     RECT  116 126.618 116.104 174.702 ;
     RECT  116.104 38.688 121.208 124.488 ;
     RECT  121.208 2.148 121.312 124.488 ;
     RECT  121.208 126.888 121.312 174.972 ;
     RECT  121.312 126.888 121.4 174.702 ;
     RECT  121.312 2.418 121.504 124.488 ;
     RECT  121.4 126.618 121.504 174.702 ;
     RECT  121.504 38.688 126.608 124.488 ;
     RECT  126.608 2.148 126.712 124.488 ;
     RECT  126.608 126.888 126.712 174.972 ;
     RECT  126.712 126.888 126.8 174.702 ;
     RECT  126.712 2.418 126.904 124.488 ;
     RECT  126.8 126.618 126.904 174.702 ;
     RECT  126.904 38.688 132.008 124.488 ;
     RECT  132.008 2.148 132.112 124.488 ;
     RECT  132.008 126.888 132.112 174.972 ;
     RECT  132.112 126.888 132.2 174.702 ;
     RECT  132.112 2.418 132.304 124.488 ;
     RECT  132.2 126.618 132.304 174.702 ;
     RECT  132.304 38.688 137.408 124.488 ;
     RECT  137.408 2.148 137.512 124.488 ;
     RECT  137.408 126.888 137.512 174.972 ;
     RECT  137.512 126.888 137.6 174.702 ;
     RECT  137.512 2.418 137.704 124.488 ;
     RECT  137.6 126.618 137.704 174.702 ;
     RECT  137.704 38.688 142.808 124.488 ;
     RECT  142.808 2.148 142.912 124.488 ;
     RECT  142.808 126.888 142.912 174.972 ;
     RECT  142.912 126.888 143 174.702 ;
     RECT  142.912 2.418 143.104 124.488 ;
     RECT  143 126.618 143.104 174.702 ;
     RECT  143.104 38.688 148.208 124.488 ;
     RECT  148.208 2.148 148.312 124.488 ;
     RECT  148.208 126.888 148.312 174.972 ;
     RECT  148.312 126.888 148.4 174.702 ;
     RECT  148.312 2.418 148.504 124.488 ;
     RECT  148.4 126.618 148.504 174.702 ;
     RECT  148.504 38.688 153.608 124.488 ;
     RECT  153.608 2.148 153.712 124.488 ;
     RECT  153.608 126.888 153.712 174.972 ;
     RECT  153.712 126.888 153.8 174.702 ;
     RECT  153.712 2.418 153.904 124.488 ;
     RECT  153.8 126.618 153.904 174.702 ;
     RECT  153.904 38.688 159.008 124.488 ;
     RECT  159.008 2.148 159.112 124.488 ;
     RECT  159.008 126.888 159.112 174.972 ;
     RECT  159.112 126.888 159.2 174.702 ;
     RECT  159.112 2.418 159.304 124.488 ;
     RECT  159.2 126.618 159.304 174.702 ;
     RECT  159.304 38.688 164.408 124.488 ;
     RECT  164.408 2.148 164.512 124.488 ;
     RECT  164.408 126.888 164.512 174.972 ;
     RECT  164.512 126.888 164.6 174.702 ;
     RECT  164.512 2.418 164.704 124.488 ;
     RECT  164.6 126.618 164.704 174.702 ;
     RECT  164.704 38.688 169.808 124.488 ;
     RECT  169.808 2.148 169.912 124.488 ;
     RECT  169.808 126.888 169.912 174.972 ;
     RECT  169.912 126.888 170 174.702 ;
     RECT  169.912 2.418 170.104 124.488 ;
     RECT  170 126.618 170.104 174.702 ;
     RECT  170.104 38.688 175.208 124.488 ;
     RECT  175.208 2.148 175.312 124.488 ;
     RECT  175.208 126.888 175.312 174.972 ;
     RECT  175.312 126.888 175.4 174.702 ;
     RECT  175.312 2.418 175.504 124.488 ;
     RECT  175.4 126.618 175.504 174.702 ;
     RECT  175.504 38.688 180.608 124.488 ;
     RECT  180.608 2.148 180.712 124.488 ;
     RECT  180.608 126.888 180.712 174.972 ;
     RECT  180.712 126.888 180.8 174.702 ;
     RECT  180.712 2.418 180.904 124.488 ;
     RECT  180.8 126.618 180.904 174.702 ;
     RECT  180.904 38.688 186.008 124.488 ;
     RECT  186.008 2.148 186.112 124.488 ;
     RECT  186.008 126.888 186.112 174.972 ;
     RECT  186.112 126.888 186.2 174.702 ;
     RECT  186.112 2.418 186.304 124.488 ;
     RECT  186.2 126.618 186.304 174.702 ;
     RECT  186.304 38.688 191.408 124.488 ;
     RECT  191.408 2.148 191.512 124.488 ;
     RECT  191.408 126.888 191.512 174.972 ;
     RECT  191.512 126.888 191.6 174.702 ;
     RECT  191.512 2.418 191.704 124.488 ;
     RECT  191.6 126.618 191.704 174.702 ;
     RECT  191.704 38.688 196.808 124.488 ;
     RECT  196.808 2.148 196.912 124.488 ;
     RECT  196.808 126.888 196.912 174.972 ;
     RECT  196.912 126.888 197 174.702 ;
     RECT  196.912 2.418 197.104 124.488 ;
     RECT  197 126.618 197.104 174.702 ;
     RECT  197.104 38.688 197.568 124.488 ;
     RECT  197.568 38.688 197.777 94.44 ;
     RECT  197.568 98.064 198.713 98.088 ;
     RECT  197.777 73.584 198.965 76.392 ;
     RECT  197.777 78.096 198.965 81 ;
     RECT  197.777 92.88 198.965 94.44 ;
     RECT  198.917 98.64 199.001 98.664 ;
     RECT  197.777 82.608 199.361 87.24 ;
     RECT  197.777 88.368 199.361 91.272 ;
     RECT  198.965 78.096 199.469 78.792 ;
     RECT  197.777 38.688 199.505 71.88 ;
     RECT  198.965 73.584 199.505 73.608 ;
     RECT  198.965 74.736 199.505 74.76 ;
     RECT  198.965 75.888 199.505 75.912 ;
     RECT  199.469 78.096 199.505 78.696 ;
     RECT  198.965 79.824 199.505 81 ;
     RECT  199.361 85.008 199.505 87.24 ;
     RECT  199.361 88.368 199.505 90.696 ;
     RECT  199.505 71.664 199.541 71.688 ;
     RECT  199.361 82.608 199.541 83.88 ;
     RECT  199.505 38.688 199.901 66.888 ;
     RECT  199.189 106.608 199.937 106.632 ;
     RECT  199.901 38.688 199.945 66.264 ;
     RECT  199.541 83.856 199.973 83.88 ;
     RECT  199.897 103.2 199.981 103.224 ;
     RECT  199.505 88.464 200.009 88.488 ;
     RECT  198.965 92.88 200.009 92.904 ;
     RECT  198.965 94.416 200.009 94.44 ;
     RECT  199.969 104.304 200.053 104.328 ;
     RECT  199.541 82.608 200.081 82.632 ;
     RECT  199.505 86.064 200.081 86.76 ;
     RECT  199.945 38.688 200.099 55.896 ;
     RECT  200.099 54.864 200.297 55.896 ;
     RECT  199.945 57.168 200.723 66.264 ;
     RECT  200.297 54.864 200.729 55.272 ;
     RECT  199.505 69.744 200.801 69.768 ;
     RECT  200.729 54.864 200.837 54.888 ;
     RECT  200.905 70.128 201.013 70.296 ;
     RECT  200.723 57.408 201.061 66.264 ;
     RECT  201.061 57.408 201.445 66.888 ;
     RECT  199.505 68.112 201.445 68.52 ;
     RECT  201.445 57.408 201.637 68.52 ;
     RECT  201.637 57.408 201.685 68.664 ;
     RECT  200.917 73.248 202.021 73.272 ;
     RECT  202.021 73.248 202.069 73.848 ;
     RECT  200.341 75.12 202.069 75.144 ;
     RECT  200.099 38.688 202.208 53.88 ;
     RECT  201.685 57.072 202.208 68.664 ;
     RECT  201.013 70.128 202.208 70.872 ;
     RECT  202.069 73.248 202.208 75.144 ;
     RECT  199.505 78.624 202.208 78.648 ;
     RECT  200.081 86.736 202.208 86.76 ;
     RECT  202.208 2.148 202.312 174.972 ;
     RECT  202.312 2.418 202.504 174.702 ;
     RECT  202.504 40.32 202.643 53.88 ;
     RECT  202.643 40.32 202.835 53.544 ;
     RECT  202.504 57.072 202.835 61.176 ;
     RECT  202.835 43.296 202.883 53.544 ;
     RECT  202.504 70.128 202.883 70.968 ;
     RECT  202.883 43.296 202.979 53.352 ;
     RECT  202.835 57.072 202.979 61.128 ;
     RECT  202.979 57.072 203.027 59.016 ;
     RECT  202.979 43.68 203.267 53.352 ;
     RECT  203.027 57.072 203.537 58.92 ;
     RECT  202.504 86.736 203.555 86.76 ;
     RECT  202.504 62.832 203.603 68.664 ;
     RECT  202.979 60.672 203.651 61.128 ;
     RECT  202.504 73.248 203.749 75.672 ;
     RECT  202.883 70.272 203.797 70.968 ;
     RECT  202.504 39.312 204.083 39.336 ;
     RECT  203.603 63.072 204.083 68.664 ;
     RECT  202.835 40.32 204.131 42.264 ;
     RECT  203.537 58.128 204.185 58.92 ;
     RECT  204.131 40.32 204.323 42.072 ;
     RECT  203.267 43.68 204.419 53.112 ;
     RECT  204.083 63.12 205.229 68.664 ;
     RECT  203.797 70.272 205.481 71.304 ;
     RECT  204.419 44.64 205.877 53.112 ;
     RECT  204.185 58.368 205.945 58.92 ;
     RECT  205.945 58.08 206.125 58.92 ;
     RECT  205.229 66.24 206.197 68.664 ;
     RECT  206.125 58.08 206.269 59.64 ;
     RECT  205.229 63.12 206.341 65.208 ;
     RECT  205.481 70.656 206.341 71.304 ;
     RECT  203.749 72.96 206.341 75.672 ;
     RECT  206.341 63.024 206.377 65.208 ;
     RECT  204.323 41.52 206.381 42.072 ;
     RECT  205.877 44.64 206.381 51.768 ;
     RECT  205.877 52.8 206.417 53.112 ;
     RECT  206.341 70.656 206.521 75.672 ;
     RECT  206.269 58.08 206.557 59.784 ;
     RECT  206.521 70.272 206.561 75.672 ;
     RECT  203.651 60.864 206.588 61.128 ;
     RECT  206.377 62.64 206.588 65.208 ;
     RECT  206.557 58.08 206.629 59.832 ;
     RECT  206.588 60.864 206.629 65.208 ;
     RECT  206.629 58.08 207.025 65.208 ;
     RECT  206.197 66.24 207.025 69.24 ;
     RECT  206.561 73.248 207.565 75.672 ;
     RECT  204.323 40.32 207.608 40.344 ;
     RECT  206.381 41.52 207.608 41.976 ;
     RECT  206.381 44.64 207.608 44.904 ;
     RECT  206.381 45.984 207.608 51.768 ;
     RECT  206.417 53.088 207.608 53.112 ;
     RECT  203.537 57.072 207.608 57.096 ;
     RECT  207.025 58.08 207.608 69.24 ;
     RECT  206.561 70.272 207.608 72.264 ;
     RECT  207.565 73.248 207.608 76.056 ;
     RECT  202.504 78.624 207.608 78.648 ;
     RECT  207.608 2.148 207.712 174.972 ;
     RECT  207.712 2.418 207.904 174.702 ;
     RECT  207.904 67.344 207.965 69.24 ;
     RECT  207.904 44.64 208.145 44.664 ;
     RECT  207.904 48.192 208.361 51.768 ;
     RECT  207.904 72.96 208.541 76.056 ;
     RECT  207.965 67.344 209.005 68.616 ;
     RECT  209.005 67.344 209.077 68.76 ;
     RECT  208.541 74.016 209.081 76.056 ;
     RECT  209.077 67.344 209.113 69.048 ;
     RECT  209.081 75.408 209.257 76.056 ;
     RECT  208.361 48.192 209.333 48.216 ;
     RECT  209.113 67.296 209.333 69.048 ;
     RECT  207.904 57.072 209.401 65.688 ;
     RECT  209.333 67.296 209.401 68.904 ;
     RECT  207.904 70.224 209.437 71.832 ;
     RECT  208.541 72.96 209.437 72.984 ;
     RECT  209.401 57.072 209.449 68.904 ;
     RECT  209.437 70.224 209.473 72.984 ;
     RECT  209.449 60.768 209.477 68.904 ;
     RECT  207.904 45.984 209.513 46.872 ;
     RECT  209.477 63.696 209.52 68.904 ;
     RECT  209.473 70.128 209.725 72.984 ;
     RECT  209.725 70.032 209.833 72.984 ;
     RECT  209.081 74.016 209.833 74.04 ;
     RECT  209.833 70.032 209.869 74.04 ;
     RECT  209.257 75.408 210.125 76.44 ;
     RECT  210.125 75.408 210.229 75.432 ;
     RECT  210.125 76.416 210.229 76.44 ;
     RECT  210.229 76.416 210.313 76.968 ;
     RECT  207.904 40.32 210.467 40.344 ;
     RECT  209.449 57.072 210.481 59.736 ;
     RECT  209.477 60.768 210.481 62.712 ;
     RECT  207.904 41.52 210.515 41.976 ;
     RECT  210.481 57.072 210.557 62.712 ;
     RECT  210.469 54.72 210.61 54.744 ;
     RECT  210.313 76.416 210.611 76.92 ;
     RECT  210.557 60.24 210.661 62.712 ;
     RECT  209.52 63.792 210.661 68.904 ;
     RECT  209.869 69.888 210.697 74.04 ;
     RECT  210.229 75.216 210.697 75.432 ;
     RECT  210.661 60.24 210.733 68.904 ;
     RECT  210.697 69.888 210.733 75.432 ;
     RECT  209.513 45.984 210.773 46.296 ;
     RECT  210.733 60.24 210.809 75.432 ;
     RECT  208.361 49.296 211.241 51.768 ;
     RECT  211.241 49.296 211.457 50.952 ;
     RECT  210.809 60.24 211.597 75.384 ;
     RECT  211.597 60.048 211.621 75.384 ;
     RECT  211.621 59.808 211.637 75.384 ;
     RECT  210.557 57.072 211.742 58.488 ;
     RECT  211.457 49.296 211.745 50.376 ;
     RECT  210.61 54.72 211.817 54.792 ;
     RECT  211.637 64.56 211.849 75.384 ;
     RECT  210.611 76.416 211.849 76.68 ;
     RECT  211.817 54.768 211.889 54.792 ;
     RECT  210.515 41.52 212.003 41.544 ;
     RECT  211.849 64.56 212.029 76.68 ;
     RECT  211.637 59.808 212.317 63.48 ;
     RECT  211.742 57.12 212.425 58.488 ;
     RECT  212.317 59.712 212.425 63.48 ;
     RECT  212.425 57.12 212.929 63.48 ;
     RECT  212.029 64.56 212.929 76.968 ;
     RECT  210.773 46.272 213.008 46.296 ;
     RECT  211.745 49.296 213.008 49.32 ;
     RECT  211.745 50.352 213.008 50.376 ;
     RECT  207.904 53.088 213.008 53.112 ;
     RECT  212.929 57.12 213.008 76.968 ;
     RECT  207.904 78.624 213.008 78.648 ;
     RECT  213.008 2.148 213.112 174.972 ;
     RECT  213.112 2.418 213.304 174.702 ;
     RECT  213.304 50.352 213.443 50.376 ;
     RECT  213.304 53.088 213.491 53.112 ;
     RECT  213.304 57.024 213.797 78.648 ;
     RECT  213.304 49.296 214.259 49.32 ;
     RECT  213.797 76.56 214.333 78.648 ;
     RECT  214.333 76.56 214.585 78.696 ;
     RECT  213.797 57.024 214.837 75.432 ;
     RECT  214.585 76.56 214.837 79.176 ;
     RECT  214.837 57.024 215.089 79.176 ;
     RECT  215.089 56.784 215.197 79.176 ;
     RECT  215.197 56.736 215.273 79.176 ;
     RECT  215.269 55.392 215.449 55.416 ;
     RECT  215.273 56.736 215.449 79.08 ;
     RECT  215.449 55.392 215.849 79.08 ;
     RECT  215.849 77.616 216.101 79.08 ;
     RECT  216.101 77.616 216.22 78.312 ;
     RECT  215.849 55.392 216.461 76.632 ;
     RECT  216.22 77.616 216.461 78.072 ;
     RECT  216.461 56.256 216.605 76.632 ;
     RECT  216.605 57.744 216.641 76.632 ;
     RECT  213.304 46.272 216.659 46.296 ;
     RECT  216.461 77.76 216.893 78.072 ;
     RECT  216.893 78.048 217.217 78.072 ;
     RECT  216.641 57.744 217.253 76.536 ;
     RECT  216.605 56.256 217.361 56.568 ;
     RECT  216.961 79.728 217.505 79.752 ;
     RECT  217.361 56.544 217.937 56.568 ;
     RECT  217.253 76.08 218.257 76.536 ;
     RECT  217.253 57.744 218.293 75.048 ;
     RECT  218.257 76.08 218.293 76.68 ;
     RECT  218.293 57.744 218.545 76.68 ;
     RECT  218.545 57.36 220.057 76.68 ;
     RECT  220.057 57.36 220.169 76.92 ;
     RECT  220.169 57.36 220.284 76.68 ;
    LAYER M5 ;
     RECT  22.992 0.016 25.992 0.131 ;
     RECT  23.088 0.131 25.992 0.179 ;
     RECT  16.08 0.016 16.392 0.611 ;
     RECT  23.184 0.179 25.992 0.611 ;
     RECT  23.376 0.611 25.992 0.659 ;
     RECT  16.176 0.611 16.2 1.187 ;
     RECT  23.472 0.659 25.992 1.715 ;
     RECT  23.568 1.715 25.992 1.907 ;
     RECT  2.4 2.137 2.52 2.151 ;
     RECT  7.8 2.137 7.92 2.151 ;
     RECT  13.2 2.137 13.32 2.151 ;
     RECT  18.6 2.137 18.72 2.151 ;
     RECT  29.4 2.137 29.52 2.151 ;
     RECT  34.8 2.137 34.92 2.151 ;
     RECT  40.2 2.137 40.32 2.151 ;
     RECT  45.6 2.137 45.72 2.151 ;
     RECT  51 2.137 51.12 2.151 ;
     RECT  56.4 2.137 56.52 2.151 ;
     RECT  61.8 2.137 61.92 2.151 ;
     RECT  67.2 2.137 67.32 2.151 ;
     RECT  72.6 2.137 72.72 2.151 ;
     RECT  78 2.137 78.12 2.151 ;
     RECT  83.4 2.137 83.52 2.151 ;
     RECT  88.8 2.137 88.92 2.151 ;
     RECT  94.2 2.137 94.32 2.151 ;
     RECT  99.6 2.137 99.72 2.151 ;
     RECT  105 2.137 105.12 2.151 ;
     RECT  110.4 2.137 110.52 2.151 ;
     RECT  115.8 2.137 115.92 2.151 ;
     RECT  121.2 2.137 121.32 2.151 ;
     RECT  126.6 2.137 126.72 2.151 ;
     RECT  132 2.137 132.12 2.151 ;
     RECT  137.4 2.137 137.52 2.151 ;
     RECT  142.8 2.137 142.92 2.151 ;
     RECT  148.2 2.137 148.32 2.151 ;
     RECT  153.6 2.137 153.72 2.151 ;
     RECT  159 2.137 159.12 2.151 ;
     RECT  164.4 2.137 164.52 2.151 ;
     RECT  169.8 2.137 169.92 2.151 ;
     RECT  175.2 2.137 175.32 2.151 ;
     RECT  180.6 2.137 180.72 2.151 ;
     RECT  186 2.137 186.12 2.151 ;
     RECT  191.4 2.137 191.52 2.151 ;
     RECT  196.8 2.137 196.92 2.151 ;
     RECT  202.2 2.137 202.32 2.151 ;
     RECT  207.6 2.137 207.72 2.151 ;
     RECT  213 2.137 213.12 2.151 ;
     RECT  23.568 1.907 25.608 2.291 ;
     RECT  24 2.291 25.608 2.435 ;
     RECT  25.584 2.435 25.608 2.531 ;
     RECT  21.072 3.301 21.096 4.403 ;
     RECT  24 2.435 24.504 4.451 ;
     RECT  16.464 3.925 16.488 5.507 ;
     RECT  19.968 4.837 19.992 5.507 ;
     RECT  24 4.451 24.408 5.747 ;
     RECT  13.2 2.151 13.512 6.277 ;
     RECT  26.16 6.037 26.184 6.899 ;
     RECT  22.32 4.501 22.344 7.381 ;
     RECT  13.104 6.277 13.512 8.003 ;
     RECT  22.224 7.381 22.344 8.003 ;
     RECT  24 5.747 24.312 8.053 ;
     RECT  22.32 8.003 22.344 8.099 ;
     RECT  29.4 2.151 29.712 8.485 ;
     RECT  15.984 7.237 16.008 8.579 ;
     RECT  18.6 2.151 18.912 8.821 ;
     RECT  28.512 8.485 29.712 9.061 ;
     RECT  26.112 7.237 26.136 9.155 ;
     RECT  23.568 8.053 24.312 9.731 ;
     RECT  18.6 8.821 19.032 10.595 ;
     RECT  27.888 9.061 29.712 11.123 ;
     RECT  28.512 11.123 29.712 11.411 ;
     RECT  28.752 11.411 29.712 27.635 ;
     RECT  67.2 2.151 67.512 27.781 ;
     RECT  94.2 2.151 94.512 37.861 ;
     RECT  18.6 10.595 18.912 38.101 ;
     RECT  14.544 38.005 14.568 38.149 ;
     RECT  23.616 9.731 24.312 38.677 ;
     RECT  78 2.151 78.312 38.677 ;
     RECT  202.2 2.151 202.512 38.677 ;
     RECT  14.496 38.149 14.568 38.725 ;
     RECT  13.2 8.003 13.512 39.013 ;
     RECT  14.496 38.725 14.616 39.013 ;
     RECT  20.256 39.061 20.28 39.205 ;
     RECT  61.8 2.151 62.112 39.205 ;
     RECT  191.4 2.151 191.712 39.205 ;
     RECT  137.4 2.151 137.712 39.733 ;
     RECT  77.424 38.677 78.312 39.781 ;
     RECT  83.4 2.151 83.712 39.781 ;
     RECT  85.536 39.541 85.56 39.781 ;
     RECT  200.64 39.253 200.664 39.781 ;
     RECT  202.032 38.677 202.512 39.781 ;
     RECT  199.2 39.589 199.224 39.829 ;
     RECT  200.64 39.781 202.512 39.829 ;
     RECT  17.904 38.101 18.912 39.877 ;
     RECT  20.256 39.205 20.376 39.877 ;
     RECT  88.8 2.151 89.112 40.021 ;
     RECT  72.6 2.151 72.912 40.309 ;
     RECT  16.896 39.589 16.92 40.357 ;
     RECT  17.904 39.877 20.376 40.357 ;
     RECT  148.2 2.151 148.512 40.357 ;
     RECT  16.896 40.357 20.376 40.405 ;
     RECT  21.744 38.725 21.768 40.405 ;
     RECT  72.6 40.309 73.368 40.549 ;
     RECT  6.672 40.261 6.696 40.645 ;
     RECT  7.8 2.151 8.112 40.645 ;
     RECT  204.048 39.301 204.072 40.645 ;
     RECT  88.8 40.021 89.736 40.693 ;
     RECT  90.72 40.021 90.744 40.693 ;
     RECT  6.672 40.645 8.112 40.837 ;
     RECT  9.216 39.733 9.24 40.837 ;
     RECT  88.8 40.693 90.744 40.837 ;
     RECT  199.2 39.829 202.512 40.837 ;
     RECT  199.2 40.837 202.68 40.885 ;
     RECT  204.048 40.645 204.312 40.885 ;
     RECT  6.672 40.837 9.24 40.981 ;
     RECT  13.2 39.013 14.616 41.125 ;
     RECT  15.648 39.829 15.672 41.125 ;
     RECT  110.4 2.151 110.712 41.173 ;
     RECT  121.2 2.151 121.512 41.173 ;
     RECT  72.6 40.549 73.704 41.269 ;
     RECT  23.616 38.677 24.408 41.317 ;
     RECT  126.6 2.151 126.912 41.365 ;
     RECT  72.6 41.269 74.568 41.411 ;
     RECT  22.8 41.317 24.408 41.459 ;
     RECT  42.768 41.317 42.792 41.459 ;
     RECT  54.72 41.317 54.744 41.459 ;
     RECT  199.2 40.885 204.312 41.461 ;
     RECT  13.2 41.125 15.672 41.557 ;
     RECT  110.4 41.173 111.048 41.603 ;
     RECT  45.6 2.151 45.912 41.653 ;
     RECT  132 2.151 132.312 41.653 ;
     RECT  121.2 41.173 121.704 41.749 ;
     RECT  126.6 41.365 127.32 41.749 ;
     RECT  142.8 2.151 143.112 41.749 ;
     RECT  45.6 41.653 46.056 41.795 ;
     RECT  196.8 2.151 197.112 41.893 ;
     RECT  198.24 41.461 204.312 41.893 ;
     RECT  16.896 40.405 21.768 41.941 ;
     RECT  210.432 40.309 210.456 41.941 ;
     RECT  121.2 41.749 122.52 42.035 ;
     RECT  67.056 27.781 67.512 42.037 ;
     RECT  118.56 41.173 118.584 42.131 ;
     RECT  5.424 40.021 5.448 42.421 ;
     RECT  40.2 2.151 40.512 42.517 ;
     RECT  45.6 41.795 45.912 42.709 ;
     RECT  4.752 42.421 5.448 42.997 ;
     RECT  29.4 27.635 29.712 43.141 ;
     RECT  34.8 2.151 35.112 43.237 ;
     RECT  61.8 39.205 62.424 43.285 ;
     RECT  148.2 40.357 149.064 43.333 ;
     RECT  101.136 27.589 101.16 43.573 ;
     RECT  101.136 43.573 101.448 43.619 ;
     RECT  13.2 41.557 15.768 43.621 ;
     RECT  16.896 41.941 22.488 43.621 ;
     RECT  196.8 41.893 204.312 43.669 ;
     RECT  4.752 42.997 5.496 43.765 ;
     RECT  53.424 39.301 53.448 43.813 ;
     RECT  11.472 43.285 11.496 44.099 ;
     RECT  115.8 2.151 116.112 44.101 ;
     RECT  6.672 40.981 10.056 44.341 ;
     RECT  34.8 43.237 35.496 44.389 ;
     RECT  3.888 43.765 5.496 44.629 ;
     RECT  142.8 41.749 143.352 44.677 ;
     RECT  99.6 2.151 99.912 44.725 ;
     RECT  101.424 43.619 101.448 44.725 ;
     RECT  137.4 39.733 138.216 44.725 ;
     RECT  2.4 2.151 2.712 44.773 ;
     RECT  3.792 44.629 5.496 44.773 ;
     RECT  2.4 44.773 5.496 44.965 ;
     RECT  6.672 44.341 11.448 44.965 ;
     RECT  43.2 41.941 43.224 45.109 ;
     RECT  44.832 42.709 45.912 45.109 ;
     RECT  47.664 41.461 47.688 45.109 ;
     RECT  80.784 42.421 80.808 45.157 ;
     RECT  110.4 41.603 110.952 45.203 ;
     RECT  99.6 44.725 101.448 45.205 ;
     RECT  42.768 45.109 43.224 45.251 ;
     RECT  44.832 45.109 47.688 45.251 ;
     RECT  44.832 45.251 45.912 45.301 ;
     RECT  94.2 37.861 95.016 45.349 ;
     RECT  98.64 45.205 101.448 45.395 ;
     RECT  93.696 45.349 95.016 45.445 ;
     RECT  80.784 45.157 81.192 45.493 ;
     RECT  99.6 45.395 101.448 45.635 ;
     RECT  93.6 45.445 95.016 45.779 ;
     RECT  130.56 45.637 130.584 45.779 ;
     RECT  2.4 44.965 11.448 45.781 ;
     RECT  13.2 43.621 22.488 45.925 ;
     RECT  23.616 41.459 24.408 45.925 ;
     RECT  2.4 45.781 11.736 45.971 ;
     RECT  72.6 41.411 73.704 45.973 ;
     RECT  64.944 46.021 65.064 46.163 ;
     RECT  121.2 42.035 121.704 46.165 ;
     RECT  53.424 43.813 54.12 46.213 ;
     RECT  56.4 2.151 56.712 46.213 ;
     RECT  121.2 46.165 122.328 46.307 ;
     RECT  56.4 46.213 57.096 46.355 ;
     RECT  43.2 45.251 43.224 46.405 ;
     RECT  118.128 43.765 118.152 46.405 ;
     RECT  44.736 45.301 45.912 46.451 ;
     RECT  45.456 46.451 45.912 46.501 ;
     RECT  47.664 45.251 47.688 46.501 ;
     RECT  58.704 46.405 58.728 46.501 ;
     RECT  67.056 42.037 67.608 46.501 ;
     RECT  56.4 46.355 57 46.547 ;
     RECT  118.128 46.405 118.584 46.547 ;
     RECT  121.2 46.307 122.232 46.547 ;
     RECT  40.2 42.517 40.728 46.549 ;
     RECT  26.736 46.213 26.76 46.595 ;
     RECT  53.424 46.213 54.84 46.643 ;
     RECT  58.704 46.501 58.824 46.643 ;
     RECT  38.784 46.501 38.808 46.691 ;
     RECT  88.8 40.837 91.272 46.693 ;
     RECT  11.712 45.971 11.736 46.835 ;
     RECT  93.6 45.779 94.512 46.885 ;
     RECT  67.056 46.501 67.848 46.931 ;
     RECT  72.48 45.973 73.704 47.125 ;
     RECT  87.12 44.965 87.144 47.125 ;
     RECT  42.768 46.405 43.224 47.171 ;
     RECT  45.456 46.501 47.688 47.171 ;
     RECT  58.704 46.643 58.728 47.171 ;
     RECT  29.4 43.141 30.072 47.315 ;
     RECT  13.2 45.925 24.408 47.317 ;
     RECT  2.4 45.971 10.728 47.413 ;
     RECT  77.424 39.781 79.176 47.459 ;
     RECT  12.72 47.317 24.408 47.507 ;
     RECT  47.424 47.171 47.688 47.557 ;
     RECT  113.424 47.461 113.448 47.603 ;
     RECT  72.48 47.125 74.664 47.651 ;
     RECT  78 47.459 79.176 47.653 ;
     RECT  80.64 45.493 81.192 47.653 ;
     RECT  56.4 46.547 56.712 47.749 ;
     RECT  61.8 43.285 62.472 47.845 ;
     RECT  45.456 47.171 46.008 47.891 ;
     RECT  56.4 47.749 56.808 47.891 ;
     RECT  40.2 46.549 40.776 47.893 ;
     RECT  83.4 39.781 85.56 48.085 ;
     RECT  121.2 46.547 121.704 48.133 ;
     RECT  86.64 47.125 87.144 48.467 ;
     RECT  58.704 48.469 58.824 48.611 ;
     RECT  61.8 47.845 62.52 48.661 ;
     RECT  58.8 48.611 58.824 48.707 ;
     RECT  12.912 47.507 24.408 48.997 ;
     RECT  25.44 43.765 25.464 48.997 ;
     RECT  40.2 47.893 40.872 48.997 ;
     RECT  45.456 47.891 45.912 48.997 ;
     RECT  53.424 46.643 54.12 48.997 ;
     RECT  69.696 47.701 69.72 48.997 ;
     RECT  40.2 48.997 40.92 49.045 ;
     RECT  47.424 47.557 48.168 49.045 ;
     RECT  69.072 48.997 69.72 49.045 ;
     RECT  97.92 46.261 97.944 49.045 ;
     RECT  99.6 45.635 101.16 49.045 ;
     RECT  112.752 48.997 112.776 49.045 ;
     RECT  36.912 48.997 36.936 49.093 ;
     RECT  45.12 48.997 45.912 49.093 ;
     RECT  93.6 46.885 95.448 49.093 ;
     RECT  96.768 48.997 96.792 49.093 ;
     RECT  112.224 49.045 112.776 49.189 ;
     RECT  12.912 48.997 25.464 49.235 ;
     RECT  29.4 47.315 29.928 49.235 ;
     RECT  36.912 49.093 37.032 49.235 ;
     RECT  45.024 49.093 45.912 49.235 ;
     RECT  47.424 49.045 49.032 49.235 ;
     RECT  52.896 48.997 54.12 49.235 ;
     RECT  92.928 49.093 95.448 49.235 ;
     RECT  96.768 49.093 96.888 49.235 ;
     RECT  108.96 48.997 108.984 49.235 ;
     RECT  56.4 47.891 56.712 49.237 ;
     RECT  78 47.653 81.192 49.237 ;
     RECT  40.032 49.045 41.016 49.283 ;
     RECT  112.224 49.189 112.872 49.285 ;
     RECT  213 2.151 213.312 49.285 ;
     RECT  56.4 49.237 56.808 49.427 ;
     RECT  112.128 49.285 112.872 49.427 ;
     RECT  2.4 47.413 11.448 49.475 ;
     RECT  67.056 46.931 67.608 49.523 ;
     RECT  112.128 49.427 112.152 49.523 ;
     RECT  76.944 49.189 76.968 49.571 ;
     RECT  45.456 49.235 45.912 49.861 ;
     RECT  26.784 49.093 26.808 50.003 ;
     RECT  45.456 49.861 46.008 50.005 ;
     RECT  51 2.151 51.312 50.005 ;
     RECT  107.52 49.765 107.544 50.005 ;
     RECT  78 49.237 81.288 50.051 ;
     RECT  58.704 49.765 58.728 50.147 ;
     RECT  82.656 48.085 85.56 50.195 ;
     RECT  43.2 47.171 43.224 50.245 ;
     RECT  191.4 39.205 192.36 50.245 ;
     RECT  64.944 46.163 64.968 50.293 ;
     RECT  118.128 46.547 118.152 50.293 ;
     RECT  134.016 49.477 134.04 50.293 ;
     RECT  29.4 49.235 29.832 50.341 ;
     RECT  34.8 44.389 35.592 50.341 ;
     RECT  118.128 50.293 118.584 50.435 ;
     RECT  134.016 50.293 134.568 50.435 ;
     RECT  74.688 49.237 74.712 50.437 ;
     RECT  45.456 50.005 46.2 50.485 ;
     RECT  153.6 2.151 153.912 50.485 ;
     RECT  164.4 2.151 164.712 50.485 ;
     RECT  169.8 2.151 170.112 50.485 ;
     RECT  180.6 2.151 180.912 50.485 ;
     RECT  121.104 48.133 121.704 50.531 ;
     RECT  194.448 50.245 194.472 50.533 ;
     RECT  34.8 50.341 35.688 50.579 ;
     RECT  42.768 50.245 43.224 50.579 ;
     RECT  190.416 50.245 192.36 50.579 ;
     RECT  12.912 49.235 24.408 50.581 ;
     RECT  25.44 49.235 25.464 50.581 ;
     RECT  47.424 49.235 48.168 50.581 ;
     RECT  107.424 50.005 107.544 50.627 ;
     RECT  153.6 50.485 154.008 50.627 ;
     RECT  164.4 50.485 164.808 50.627 ;
     RECT  169.8 50.485 170.232 50.627 ;
     RECT  180.6 50.485 181.032 50.627 ;
     RECT  190.416 50.579 191.712 50.627 ;
     RECT  2.4 49.475 11.16 50.629 ;
     RECT  26.592 50.533 26.616 50.675 ;
     RECT  45.024 50.485 46.2 50.675 ;
     RECT  194.448 50.533 194.568 50.675 ;
     RECT  61.8 48.661 63.288 50.677 ;
     RECT  74.688 50.437 74.76 50.677 ;
     RECT  76.368 50.005 76.392 50.677 ;
     RECT  142.8 44.677 143.448 50.677 ;
     RECT  61.68 50.677 63.288 50.771 ;
     RECT  64.944 50.293 65.016 50.771 ;
     RECT  78 50.051 81.192 50.771 ;
     RECT  87.12 48.467 87.144 50.771 ;
     RECT  88.704 46.693 91.272 50.771 ;
     RECT  97.92 49.045 101.16 50.771 ;
     RECT  115.8 44.101 116.664 50.771 ;
     RECT  118.128 50.435 118.152 50.771 ;
     RECT  126.6 41.749 127.416 50.771 ;
     RECT  72.48 47.651 73.704 50.819 ;
     RECT  12.912 50.581 25.464 50.821 ;
     RECT  68.976 49.045 69.72 50.821 ;
     RECT  12.912 50.821 25.608 50.867 ;
     RECT  61.68 50.771 62.712 50.867 ;
     RECT  37.056 50.725 37.08 50.915 ;
     RECT  42.864 50.579 43.224 50.915 ;
     RECT  61.68 50.867 62.52 50.915 ;
     RECT  74.688 50.677 76.392 50.915 ;
     RECT  90.624 50.771 91.272 50.915 ;
     RECT  153.6 50.627 153.912 50.917 ;
     RECT  53.424 49.235 54.12 50.963 ;
     RECT  68.784 50.821 69.72 50.963 ;
     RECT  68.88 50.963 69.72 51.059 ;
     RECT  142.8 50.677 144.216 51.059 ;
     RECT  152.88 50.917 153.912 51.059 ;
     RECT  47.328 50.581 48.168 51.061 ;
     RECT  105 2.151 105.312 51.061 ;
     RECT  98.64 50.771 101.16 51.107 ;
     RECT  0.336 51.013 0.36 51.109 ;
     RECT  40.032 49.283 40.728 51.109 ;
     RECT  61.68 50.915 62.472 51.155 ;
     RECT  107.664 50.917 107.784 51.203 ;
     RECT  0.288 51.109 0.36 51.205 ;
     RECT  0.288 51.205 0.456 51.253 ;
     RECT  196.8 43.669 204.408 51.253 ;
     RECT  121.2 50.531 121.704 51.301 ;
     RECT  43.2 50.915 43.224 51.347 ;
     RECT  47.328 51.061 48.456 51.347 ;
     RECT  50.688 50.005 51.312 51.347 ;
     RECT  53.472 50.963 54.12 51.347 ;
     RECT  68.976 51.059 69.72 51.347 ;
     RECT  72.48 50.819 73.56 51.347 ;
     RECT  78 50.771 80.856 51.347 ;
     RECT  82.656 50.195 85.512 51.347 ;
     RECT  90.624 50.915 91.224 51.347 ;
     RECT  93.6 49.235 95.448 51.347 ;
     RECT  134.016 50.435 134.04 51.347 ;
     RECT  146.88 43.861 146.904 51.347 ;
     RECT  145.584 43.045 145.608 51.349 ;
     RECT  148.2 43.333 149.16 51.349 ;
     RECT  47.424 51.347 48.456 51.395 ;
     RECT  72.48 51.347 73.512 51.395 ;
     RECT  88.704 50.771 89.544 51.395 ;
     RECT  94.08 51.347 95.064 51.395 ;
     RECT  99.504 51.107 101.16 51.395 ;
     RECT  132 41.653 132.504 51.395 ;
     RECT  145.584 51.349 146.52 51.395 ;
     RECT  56.4 49.427 56.712 51.397 ;
     RECT  196.704 51.253 204.408 51.443 ;
     RECT  64.992 50.771 65.016 51.491 ;
     RECT  132 51.395 132.408 51.491 ;
     RECT  67.2 49.523 67.608 51.493 ;
     RECT  45.456 50.675 46.2 51.539 ;
     RECT  54.72 51.397 54.744 51.539 ;
     RECT  56.4 51.397 56.808 51.539 ;
     RECT  61.8 51.155 62.472 51.539 ;
     RECT  144.192 51.059 144.216 51.539 ;
     RECT  104.88 51.061 105.312 51.587 ;
     RECT  121.2 51.301 122.568 51.587 ;
     RECT  145.68 51.395 146.52 51.587 ;
     RECT  47.616 51.395 48.456 51.635 ;
     RECT  82.656 51.347 84.984 51.635 ;
     RECT  0.24 51.253 0.456 51.637 ;
     RECT  61.8 51.539 62.232 51.683 ;
     RECT  72.6 51.395 73.512 51.683 ;
     RECT  137.4 44.725 138.264 51.683 ;
     RECT  94.08 51.395 94.824 51.731 ;
     RECT  146.496 51.587 146.52 51.731 ;
     RECT  166.464 51.397 166.488 51.731 ;
     RECT  29.4 50.341 30.888 51.779 ;
     RECT  68.976 51.347 69.192 51.779 ;
     RECT  90.624 51.347 90.648 51.779 ;
     RECT  107.952 51.397 107.976 51.779 ;
     RECT  65.616 51.541 65.64 51.781 ;
     RECT  67.2 51.493 67.848 51.781 ;
     RECT  76.944 51.349 76.968 51.827 ;
     RECT  87.072 51.397 87.096 51.827 ;
     RECT  0.192 51.637 0.456 51.829 ;
     RECT  24 50.867 25.608 51.829 ;
     RECT  40.032 51.109 41.016 51.829 ;
     RECT  65.616 51.781 67.848 51.875 ;
     RECT  82.656 51.635 83.712 51.875 ;
     RECT  99.504 51.395 99.912 51.875 ;
     RECT  68.976 51.779 69.144 51.923 ;
     RECT  66.336 51.875 67.848 51.971 ;
     RECT  74.688 50.915 75.48 51.971 ;
     RECT  121.2 51.587 121.608 51.971 ;
     RECT  148.2 51.349 149.352 52.019 ;
     RECT  94.2 51.731 94.824 52.067 ;
     RECT  33.072 51.061 33.096 52.163 ;
     RECT  0.144 51.829 0.456 52.165 ;
     RECT  48.432 51.635 48.456 52.307 ;
     RECT  29.4 51.779 29.928 52.355 ;
     RECT  88.8 51.395 89.544 52.355 ;
     RECT  24 51.829 25.704 52.403 ;
     RECT  94.2 52.067 94.728 52.499 ;
     RECT  75.408 51.971 75.48 52.643 ;
     RECT  0.144 52.165 0.504 52.693 ;
     RECT  25.68 52.403 25.704 52.789 ;
     RECT  45.6 51.539 46.2 52.835 ;
     RECT  2.304 50.629 11.16 52.885 ;
     RECT  12.912 50.867 22.776 52.885 ;
     RECT  75.456 52.643 75.48 52.931 ;
     RECT  34.8 50.579 35.496 53.171 ;
     RECT  66.336 51.971 67.512 53.171 ;
     RECT  72.6 51.683 73.464 53.219 ;
     RECT  25.68 52.789 25.752 53.315 ;
     RECT  72.6 53.219 73.32 53.363 ;
     RECT  72.6 53.363 73.128 53.411 ;
     RECT  78 51.347 78.984 53.507 ;
     RECT  80.352 51.347 80.376 53.555 ;
     RECT  193.248 52.885 193.272 53.603 ;
     RECT  25.68 53.315 25.704 53.747 ;
     RECT  39.984 51.829 41.016 53.843 ;
     RECT  24 52.403 24.552 53.891 ;
     RECT  0.144 52.693 0.552 53.893 ;
     RECT  2.304 52.885 22.776 54.179 ;
     RECT  210.432 41.941 210.504 54.709 ;
     RECT  0.144 53.893 0.6 54.755 ;
     RECT  0.144 54.755 0.504 55.717 ;
     RECT  12.912 54.179 22.776 56.243 ;
     RECT  13.2 56.243 22.776 56.339 ;
     RECT  211.968 41.509 211.992 57.061 ;
     RECT  0.144 55.717 0.648 57.587 ;
     RECT  210.432 54.709 210.6 57.589 ;
     RECT  211.68 57.061 211.992 57.589 ;
     RECT  0.144 57.587 0.504 57.683 ;
     RECT  210.432 57.589 211.992 57.683 ;
     RECT  2.304 54.179 11.16 58.259 ;
     RECT  210.432 57.683 211.704 58.403 ;
     RECT  211.68 58.403 211.704 58.451 ;
     RECT  0.144 57.683 0.456 58.645 ;
     RECT  0.144 58.645 0.552 59.507 ;
     RECT  209.424 51.637 209.448 59.699 ;
     RECT  2.4 58.259 11.16 59.797 ;
     RECT  207.6 2.151 207.912 59.797 ;
     RECT  2.304 59.797 11.16 59.891 ;
     RECT  211.632 59.797 211.656 60.373 ;
     RECT  213 49.285 214.248 60.373 ;
     RECT  0.144 59.507 0.504 60.659 ;
     RECT  211.632 60.373 214.248 60.851 ;
     RECT  206.64 59.797 207.912 60.997 ;
     RECT  209.376 59.797 209.4 60.997 ;
     RECT  206.64 60.997 209.4 61.331 ;
     RECT  210.432 58.403 210.6 61.429 ;
     RECT  0.144 60.659 0.408 61.861 ;
     RECT  2.304 59.891 10.776 62.243 ;
     RECT  0.144 61.861 0.456 62.293 ;
     RECT  212.352 60.851 214.248 62.675 ;
     RECT  210.432 61.429 211.272 62.723 ;
     RECT  2.304 62.243 10.68 63.299 ;
     RECT  2.304 63.299 10.584 63.587 ;
     RECT  209.376 61.331 209.4 63.685 ;
     RECT  2.304 63.587 10.536 63.731 ;
     RECT  0.144 62.293 0.552 63.875 ;
     RECT  196.8 51.443 204.408 64.019 ;
     RECT  2.4 63.731 10.536 64.211 ;
     RECT  209.376 63.685 209.448 64.357 ;
     RECT  198.144 64.019 204.408 64.451 ;
     RECT  210.432 62.723 210.6 64.499 ;
     RECT  9.312 64.211 10.536 64.739 ;
     RECT  208.992 64.357 209.448 64.931 ;
     RECT  2.4 64.211 8.112 64.933 ;
     RECT  0.144 63.875 0.504 65.027 ;
     RECT  209.376 64.931 209.448 65.027 ;
     RECT  213 62.675 214.248 65.125 ;
     RECT  213 65.125 214.344 65.267 ;
     RECT  9.648 64.739 10.536 65.747 ;
     RECT  2.304 64.933 8.112 66.179 ;
     RECT  2.304 66.179 6.744 66.227 ;
     RECT  10.032 65.747 10.536 66.275 ;
     RECT  0.192 65.027 0.504 66.323 ;
     RECT  0.192 66.323 0.312 66.755 ;
     RECT  0.192 66.755 0.216 66.803 ;
     RECT  206.64 61.331 207.912 66.803 ;
     RECT  2.304 66.227 6.168 66.851 ;
     RECT  2.4 66.851 6.168 66.899 ;
     RECT  3.84 66.899 6.168 67.283 ;
     RECT  210.432 64.499 210.456 67.283 ;
     RECT  4.176 67.283 5.928 67.379 ;
     RECT  211.488 66.085 211.512 67.523 ;
     RECT  209.424 65.027 209.448 67.765 ;
     RECT  209.424 67.765 210.024 67.811 ;
     RECT  2.4 66.899 2.808 67.859 ;
     RECT  4.176 67.379 4.2 67.859 ;
     RECT  207.6 66.803 207.912 68.341 ;
     RECT  207.504 68.341 207.912 69.251 ;
     RECT  198.144 64.451 204.36 70.163 ;
     RECT  13.2 56.339 22.728 70.451 ;
     RECT  10.032 66.275 10.056 70.499 ;
     RECT  207.6 69.251 207.912 70.645 ;
     RECT  210 67.811 210.024 70.645 ;
     RECT  13.2 70.451 22.104 70.787 ;
     RECT  198.144 70.163 201.048 70.883 ;
     RECT  216.624 46.261 216.648 70.885 ;
     RECT  209.328 70.645 210.024 71.029 ;
     RECT  216.624 70.885 217.416 71.171 ;
     RECT  21.264 70.787 22.104 71.219 ;
     RECT  206.736 70.645 207.912 71.267 ;
     RECT  209.328 71.029 210.264 71.363 ;
     RECT  207.6 71.267 207.912 71.797 ;
     RECT  216.624 71.171 216.696 71.845 ;
     RECT  21.264 71.219 21.288 71.891 ;
     RECT  216.48 71.845 216.696 71.987 ;
     RECT  213 65.267 214.248 71.989 ;
     RECT  216.624 71.987 216.696 72.083 ;
     RECT  13.2 70.787 20.184 72.179 ;
     RECT  13.2 72.179 14.904 72.419 ;
     RECT  16.224 72.179 20.184 72.419 ;
     RECT  13.2 72.419 14.568 72.515 ;
     RECT  212.112 71.989 214.248 72.995 ;
     RECT  216.624 72.083 216.648 72.995 ;
     RECT  14.544 72.515 14.568 73.091 ;
     RECT  207.6 71.797 208.488 73.235 ;
     RECT  198.144 70.883 200.952 73.283 ;
     RECT  220.128 73.141 220.152 73.331 ;
     RECT  202.032 70.163 204.36 73.859 ;
     RECT  16.224 72.419 16.248 74.101 ;
     RECT  202.08 73.859 204.36 74.627 ;
     RECT  17.808 72.419 20.184 74.723 ;
     RECT  202.2 74.627 204.36 74.723 ;
     RECT  213 72.995 214.248 75.157 ;
     RECT  15.36 74.101 16.248 75.299 ;
     RECT  202.2 74.723 204.312 75.299 ;
     RECT  202.2 75.299 203.544 75.683 ;
     RECT  210.24 71.363 210.264 76.405 ;
     RECT  210.24 76.405 210.6 76.931 ;
     RECT  210.24 76.931 210.264 76.979 ;
     RECT  212.448 75.157 214.248 76.979 ;
     RECT  16.224 75.299 16.248 76.981 ;
     RECT  16.224 76.981 16.296 77.555 ;
     RECT  18.192 74.723 19.704 77.795 ;
     RECT  215.424 76.885 215.448 77.989 ;
     RECT  213 76.979 214.248 78.131 ;
     RECT  215.424 77.989 216.168 78.227 ;
     RECT  216.144 78.227 216.168 78.323 ;
     RECT  2.4 67.859 2.712 78.421 ;
     RECT  2.304 78.421 2.712 78.469 ;
     RECT  2.304 78.469 3.048 78.517 ;
     RECT  0.528 78.469 0.552 78.613 ;
     RECT  198.144 73.283 200.904 78.659 ;
     RECT  14.832 77.941 14.856 78.707 ;
     RECT  0.336 78.613 0.552 78.997 ;
     RECT  2.304 78.517 4.248 79.093 ;
     RECT  2.304 79.093 4.392 79.141 ;
     RECT  5.904 67.379 5.928 79.141 ;
     RECT  0.24 78.997 0.552 79.717 ;
     RECT  7.8 66.179 8.112 79.717 ;
     RECT  2.304 79.141 5.928 79.765 ;
     RECT  6.912 79.717 8.112 79.765 ;
     RECT  18.6 77.795 19.704 80.243 ;
     RECT  0.192 79.717 0.552 80.245 ;
     RECT  2.256 79.765 8.112 80.245 ;
     RECT  0.192 80.245 0.696 80.341 ;
     RECT  0.144 80.341 0.696 80.821 ;
     RECT  0.144 80.821 0.744 81.205 ;
     RECT  2.256 80.245 8.424 83.843 ;
     RECT  0.144 81.205 0.84 83.891 ;
     RECT  2.304 83.843 6.264 84.419 ;
     RECT  7.584 83.843 8.424 84.419 ;
     RECT  7.8 84.419 8.424 84.901 ;
     RECT  7.8 84.901 8.52 85.381 ;
     RECT  2.304 84.419 6.168 85.717 ;
     RECT  7.2 85.381 8.52 85.717 ;
     RECT  0.144 83.891 0.552 85.765 ;
     RECT  2.304 85.717 8.52 86.099 ;
     RECT  21.072 86.293 21.096 86.579 ;
     RECT  203.52 75.683 203.544 86.771 ;
     RECT  0.144 85.765 0.6 86.867 ;
     RECT  0.192 86.867 0.6 86.963 ;
     RECT  0.192 86.963 0.552 87.059 ;
     RECT  2.304 86.099 8.112 87.875 ;
     RECT  0.192 87.059 0.504 87.923 ;
     RECT  3.936 87.875 8.112 88.453 ;
     RECT  2.304 87.875 2.904 88.885 ;
     RECT  3.936 88.453 8.52 88.885 ;
     RECT  2.304 88.885 8.52 88.933 ;
     RECT  0.24 87.923 0.504 88.979 ;
     RECT  0.24 88.979 0.408 89.125 ;
     RECT  2.304 88.933 8.76 89.219 ;
     RECT  16.224 77.555 16.248 89.987 ;
     RECT  0.144 89.125 0.408 90.181 ;
     RECT  2.304 89.219 8.472 90.229 ;
     RECT  0.144 90.181 0.456 90.277 ;
     RECT  0.144 90.277 0.504 90.563 ;
     RECT  0.192 90.563 0.504 90.659 ;
     RECT  0.24 90.659 0.504 90.757 ;
     RECT  0.24 90.757 0.552 91.669 ;
     RECT  0.192 91.669 0.552 91.717 ;
     RECT  2.304 90.229 9.384 91.811 ;
     RECT  0.192 91.717 0.6 92.005 ;
     RECT  2.304 91.811 8.52 92.387 ;
     RECT  2.304 92.387 8.472 92.483 ;
     RECT  0.144 92.005 0.6 93.157 ;
     RECT  2.304 92.483 8.112 93.445 ;
     RECT  0.144 93.157 1.128 93.539 ;
     RECT  0.192 93.539 1.128 93.587 ;
     RECT  0.192 93.587 0.648 94.693 ;
     RECT  0.144 94.693 0.648 94.787 ;
     RECT  0.144 94.787 0.6 96.613 ;
     RECT  0.048 96.613 0.6 96.755 ;
     RECT  2.304 93.445 8.232 98.099 ;
     RECT  198.144 78.659 200.04 98.099 ;
     RECT  0.048 96.755 0.312 98.195 ;
     RECT  0.144 98.195 0.312 98.675 ;
     RECT  2.304 98.099 6.792 98.675 ;
     RECT  198.96 98.099 200.04 98.675 ;
     RECT  2.304 98.675 5.64 99.203 ;
     RECT  2.4 99.203 4.968 99.251 ;
     RECT  0.192 98.675 0.312 99.779 ;
     RECT  0.192 99.779 0.216 99.827 ;
     RECT  2.4 99.251 4.488 100.355 ;
     RECT  3.792 100.355 4.488 102.659 ;
     RECT  199.2 98.675 200.04 104.339 ;
     RECT  199.2 104.339 199.224 106.643 ;
     RECT  4.464 102.659 4.488 107.219 ;
     RECT  6.768 98.675 6.792 126.707 ;
     RECT  7.8 98.099 8.232 126.995 ;
     RECT  2.4 100.355 2.712 174.969 ;
     RECT  7.8 126.995 8.112 174.969 ;
     RECT  13.2 72.515 13.512 174.969 ;
     RECT  18.6 80.243 18.912 174.969 ;
     RECT  24 53.891 24.312 174.969 ;
     RECT  29.4 52.355 29.712 174.969 ;
     RECT  34.8 53.171 35.112 174.969 ;
     RECT  40.2 53.843 40.512 174.969 ;
     RECT  45.6 52.835 45.912 174.969 ;
     RECT  51 51.347 51.312 174.969 ;
     RECT  56.4 51.539 56.712 174.969 ;
     RECT  61.8 51.683 62.112 174.969 ;
     RECT  67.2 53.171 67.512 174.969 ;
     RECT  72.6 53.411 72.912 174.969 ;
     RECT  78 53.507 78.312 174.969 ;
     RECT  83.4 51.875 83.712 174.969 ;
     RECT  88.8 52.355 89.112 174.969 ;
     RECT  94.2 52.499 94.512 174.969 ;
     RECT  99.6 51.875 99.912 174.969 ;
     RECT  105 51.587 105.312 174.969 ;
     RECT  110.4 45.203 110.712 174.969 ;
     RECT  115.8 50.771 116.112 174.969 ;
     RECT  121.2 51.971 121.512 174.969 ;
     RECT  126.6 50.771 126.912 174.969 ;
     RECT  132 51.491 132.312 174.969 ;
     RECT  137.4 51.683 137.712 174.969 ;
     RECT  142.8 51.059 143.112 174.969 ;
     RECT  148.2 52.019 148.512 174.969 ;
     RECT  153.6 51.059 153.912 174.969 ;
     RECT  159 2.151 159.312 174.969 ;
     RECT  164.4 50.627 164.712 174.969 ;
     RECT  169.8 50.627 170.112 174.969 ;
     RECT  175.2 2.151 175.512 174.969 ;
     RECT  180.6 50.627 180.912 174.969 ;
     RECT  186 2.151 186.312 174.969 ;
     RECT  191.4 50.627 191.712 174.969 ;
     RECT  196.8 64.019 197.112 174.969 ;
     RECT  202.2 75.683 202.512 174.969 ;
     RECT  207.6 73.235 207.912 174.969 ;
     RECT  213 78.131 213.312 174.969 ;
     RECT  2.4 174.969 2.52 174.983 ;
     RECT  7.8 174.969 7.92 174.983 ;
     RECT  13.2 174.969 13.32 174.983 ;
     RECT  18.6 174.969 18.72 174.983 ;
     RECT  24 174.969 24.12 174.983 ;
     RECT  29.4 174.969 29.52 174.983 ;
     RECT  34.8 174.969 34.92 174.983 ;
     RECT  40.2 174.969 40.32 174.983 ;
     RECT  45.6 174.969 45.72 174.983 ;
     RECT  51 174.969 51.12 174.983 ;
     RECT  56.4 174.969 56.52 174.983 ;
     RECT  61.8 174.969 61.92 174.983 ;
     RECT  67.2 174.969 67.32 174.983 ;
     RECT  72.6 174.969 72.72 174.983 ;
     RECT  78 174.969 78.12 174.983 ;
     RECT  83.4 174.969 83.52 174.983 ;
     RECT  88.8 174.969 88.92 174.983 ;
     RECT  94.2 174.969 94.32 174.983 ;
     RECT  99.6 174.969 99.72 174.983 ;
     RECT  105 174.969 105.12 174.983 ;
     RECT  110.4 174.969 110.52 174.983 ;
     RECT  115.8 174.969 115.92 174.983 ;
     RECT  121.2 174.969 121.32 174.983 ;
     RECT  126.6 174.969 126.72 174.983 ;
     RECT  132 174.969 132.12 174.983 ;
     RECT  137.4 174.969 137.52 174.983 ;
     RECT  142.8 174.969 142.92 174.983 ;
     RECT  148.2 174.969 148.32 174.983 ;
     RECT  153.6 174.969 153.72 174.983 ;
     RECT  159 174.969 159.12 174.983 ;
     RECT  164.4 174.969 164.52 174.983 ;
     RECT  169.8 174.969 169.92 174.983 ;
     RECT  175.2 174.969 175.32 174.983 ;
     RECT  180.6 174.969 180.72 174.983 ;
     RECT  186 174.969 186.12 174.983 ;
     RECT  191.4 174.969 191.52 174.983 ;
     RECT  196.8 174.969 196.92 174.983 ;
     RECT  202.2 174.969 202.32 174.983 ;
     RECT  207.6 174.969 207.72 174.983 ;
     RECT  213 174.969 213.12 174.983 ;
     RECT  24.504 2.435 25.584 2.531 ;
     RECT  18.912 4.837 19.968 5.507 ;
     RECT  22.344 8.053 23.568 8.099 ;
     RECT  99.912 27.589 101.136 43.619 ;
     RECT  13.512 38.005 14.544 38.149 ;
     RECT  13.512 38.149 14.496 39.013 ;
     RECT  18.912 39.061 20.256 39.877 ;
     RECT  20.28 39.061 21.744 39.205 ;
     RECT  20.376 39.205 21.744 40.405 ;
     RECT  200.664 39.253 202.032 39.781 ;
     RECT  16.92 39.589 17.904 40.357 ;
     RECT  199.224 39.589 200.64 39.829 ;
     RECT  8.112 39.733 9.216 40.837 ;
     RECT  14.616 39.829 15.648 41.125 ;
     RECT  15.672 39.829 16.896 41.557 ;
     RECT  89.736 40.021 90.72 40.693 ;
     RECT  5.448 40.261 6.672 42.997 ;
     RECT  6.696 40.261 7.8 40.645 ;
     RECT  202.68 40.837 204.048 40.885 ;
     RECT  21.768 41.317 22.8 41.459 ;
     RECT  53.448 41.317 54.72 41.459 ;
     RECT  21.768 41.459 23.616 41.941 ;
     RECT  197.112 41.461 198.24 41.893 ;
     RECT  210.456 41.509 211.968 41.941 ;
     RECT  211.992 41.509 213 57.683 ;
     RECT  15.768 41.557 16.896 43.621 ;
     RECT  22.488 41.941 23.616 45.925 ;
     RECT  210.504 41.941 211.968 54.709 ;
     RECT  5.496 42.997 6.672 44.965 ;
     RECT  10.056 43.285 11.472 44.099 ;
     RECT  99.912 43.619 101.424 44.725 ;
     RECT  2.712 43.765 3.888 44.629 ;
     RECT  24.408 43.765 25.44 48.997 ;
     RECT  145.608 43.861 146.88 51.347 ;
     RECT  146.904 43.861 148.2 51.347 ;
     RECT  10.056 44.099 11.448 44.341 ;
     RECT  116.664 44.101 118.128 50.771 ;
     RECT  2.712 44.629 3.792 44.773 ;
     RECT  42.768 45.251 43.2 46.405 ;
     RECT  45.912 45.251 47.664 46.501 ;
     RECT  43.224 45.301 44.736 46.451 ;
     RECT  79.176 45.493 80.64 47.653 ;
     RECT  130.584 45.637 132 45.779 ;
     RECT  94.512 45.779 95.016 46.885 ;
     RECT  11.736 45.781 13.2 46.835 ;
     RECT  10.728 45.971 11.712 46.835 ;
     RECT  25.464 46.213 26.736 46.595 ;
     RECT  38.808 46.501 40.2 46.691 ;
     RECT  56.712 46.547 56.808 47.749 ;
     RECT  10.728 46.835 13.2 47.317 ;
     RECT  85.56 47.125 86.64 48.467 ;
     RECT  46.008 47.171 47.424 47.891 ;
     RECT  58.704 47.171 58.728 48.469 ;
     RECT  10.728 47.317 12.72 47.413 ;
     RECT  11.448 47.413 12.72 47.507 ;
     RECT  11.448 47.507 12.912 49.475 ;
     RECT  45.912 47.891 47.424 49.861 ;
     RECT  56.712 47.891 56.808 49.237 ;
     RECT  81.192 48.085 82.656 49.237 ;
     RECT  58.704 48.611 58.8 48.707 ;
     RECT  58.704 48.707 58.728 49.765 ;
     RECT  35.592 48.997 36.912 49.235 ;
     RECT  67.608 48.997 69.072 49.045 ;
     RECT  95.448 48.997 96.768 49.235 ;
     RECT  96.792 48.997 97.92 49.093 ;
     RECT  108.984 48.997 110.4 49.235 ;
     RECT  67.608 49.045 68.976 50.821 ;
     RECT  110.712 49.045 112.224 49.285 ;
     RECT  25.464 49.093 26.784 50.003 ;
     RECT  96.888 49.093 97.92 49.235 ;
     RECT  76.968 49.189 78 49.571 ;
     RECT  24.408 49.235 25.44 50.581 ;
     RECT  29.832 49.235 29.928 50.341 ;
     RECT  35.592 49.235 35.688 50.341 ;
     RECT  45.024 49.235 45.456 50.485 ;
     RECT  73.704 49.237 74.688 50.819 ;
     RECT  81.288 49.237 82.656 50.051 ;
     RECT  110.712 49.285 112.128 49.523 ;
     RECT  132.504 49.477 134.016 51.347 ;
     RECT  46.008 49.861 47.424 50.005 ;
     RECT  25.464 50.003 26.616 50.533 ;
     RECT  46.2 50.005 47.424 50.581 ;
     RECT  81.192 50.051 82.656 50.771 ;
     RECT  25.464 50.533 26.592 50.675 ;
     RECT  46.2 50.581 47.328 51.347 ;
     RECT  25.464 50.675 25.704 50.821 ;
     RECT  144.216 50.677 145.584 51.395 ;
     RECT  89.544 50.771 90.624 51.779 ;
     RECT  73.56 50.819 74.688 51.347 ;
     RECT  25.608 50.821 25.704 51.829 ;
     RECT  67.608 50.821 68.784 50.963 ;
     RECT  22.776 50.867 24 56.339 ;
     RECT  75.48 50.915 76.392 51.349 ;
     RECT  67.608 50.963 68.88 51.059 ;
     RECT  67.608 51.059 68.976 51.493 ;
     RECT  143.112 51.059 144.192 51.539 ;
     RECT  46.2 51.347 47.424 51.395 ;
     RECT  73.512 51.347 74.688 51.683 ;
     RECT  78.984 51.347 80.352 53.507 ;
     RECT  145.608 51.347 146.52 51.349 ;
     RECT  75.48 51.349 76.944 51.827 ;
     RECT  76.968 51.349 78 51.827 ;
     RECT  46.2 51.395 47.616 51.635 ;
     RECT  144.216 51.395 145.68 51.539 ;
     RECT  67.848 51.493 68.976 51.923 ;
     RECT  207.912 51.637 209.424 59.699 ;
     RECT  209.448 51.637 210.432 59.699 ;
     RECT  73.464 51.683 74.688 51.971 ;
     RECT  24.552 52.403 25.68 53.747 ;
     RECT  210.6 54.709 211.968 57.061 ;
     RECT  0.504 54.755 0.6 55.717 ;
     RECT  22.728 56.339 24 70.451 ;
     RECT  210.6 57.061 211.68 57.589 ;
     RECT  0.504 57.587 0.552 57.683 ;
     RECT  0.456 57.683 0.552 58.645 ;
     RECT  211.704 57.683 213 58.451 ;
     RECT  210.6 58.403 211.68 58.451 ;
     RECT  210.6 58.451 213 59.797 ;
     RECT  207.912 59.699 210.432 59.797 ;
     RECT  207.912 59.797 209.376 60.997 ;
     RECT  209.4 59.797 210.432 63.685 ;
     RECT  210.6 59.797 211.632 60.851 ;
     RECT  211.656 59.797 213 60.373 ;
     RECT  0.408 60.659 0.456 61.861 ;
     RECT  210.6 60.851 212.352 61.429 ;
     RECT  207.912 61.331 209.376 64.357 ;
     RECT  211.272 61.429 212.352 62.675 ;
     RECT  209.448 63.685 210.432 67.283 ;
     RECT  2.304 63.731 2.4 64.933 ;
     RECT  197.112 64.019 198.144 98.099 ;
     RECT  8.112 64.211 9.312 64.739 ;
     RECT  207.912 64.357 208.992 64.931 ;
     RECT  207.912 64.931 209.376 65.027 ;
     RECT  207.912 65.027 209.424 67.811 ;
     RECT  210.456 66.085 211.488 67.283 ;
     RECT  211.512 66.085 213 67.523 ;
     RECT  6.744 66.179 7.8 66.227 ;
     RECT  2.808 66.899 3.84 67.283 ;
     RECT  2.808 67.283 4.176 67.859 ;
     RECT  209.448 67.283 211.488 67.523 ;
     RECT  209.448 67.523 210.024 67.765 ;
     RECT  207.504 69.251 207.6 70.645 ;
     RECT  201.048 70.163 202.032 70.883 ;
     RECT  207.912 70.645 209.328 71.363 ;
     RECT  20.184 70.787 21.264 71.891 ;
     RECT  200.952 70.883 202.032 73.283 ;
     RECT  207.912 71.363 208.488 71.797 ;
     RECT  14.904 72.179 16.224 72.419 ;
     RECT  13.512 72.515 14.544 73.091 ;
     RECT  200.904 73.283 202.032 73.859 ;
     RECT  200.904 73.859 202.08 74.627 ;
     RECT  200.904 74.627 202.2 78.659 ;
     RECT  202.512 75.683 203.52 86.771 ;
     RECT  214.248 76.885 215.424 78.131 ;
     RECT  13.512 77.941 14.832 78.707 ;
     RECT  14.856 77.941 16.224 78.707 ;
     RECT  4.392 79.093 5.904 79.141 ;
     RECT  5.928 79.717 6.912 79.765 ;
     RECT  0.744 80.821 2.256 81.205 ;
     RECT  0.84 81.205 2.256 83.843 ;
     RECT  0.84 83.843 2.304 83.891 ;
     RECT  6.264 83.843 7.584 84.419 ;
     RECT  6.168 84.419 7.8 85.381 ;
     RECT  6.168 85.381 7.2 85.717 ;
     RECT  2.904 87.875 3.936 88.885 ;
     RECT  0.192 87.923 0.24 89.125 ;
     RECT  0.408 88.979 0.504 90.181 ;
     RECT  8.472 89.219 8.76 90.229 ;
     RECT  0.456 90.181 0.504 90.277 ;
     RECT  0.144 90.563 0.192 90.659 ;
     RECT  0.144 90.659 0.24 91.669 ;
     RECT  0.144 91.669 0.192 92.005 ;
     RECT  8.112 92.483 8.232 93.445 ;
     RECT  1.128 93.157 2.304 93.587 ;
     RECT  0.144 93.539 0.192 94.693 ;
     RECT  6.792 98.099 7.8 126.707 ;
     RECT  5.64 98.675 6.768 99.203 ;
     RECT  2.712 100.355 3.792 102.659 ;
  END
END hfd_hgi_vm_calendar_SW
END LIBRARY
